VERSION 5.7 ;
BUSBITCHARS "[]" ;
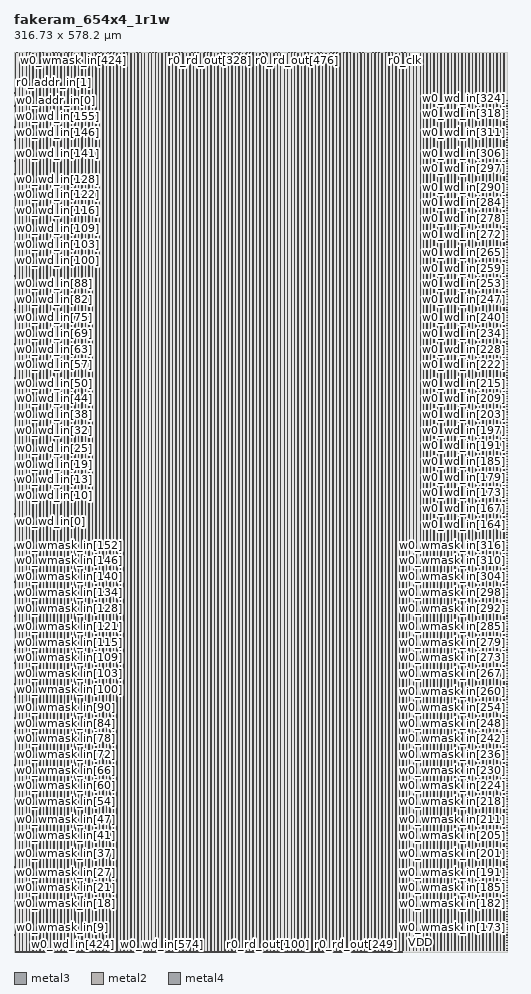
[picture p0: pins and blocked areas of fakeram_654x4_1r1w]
MACRO fakeram_654x4_1r1w
  FOREIGN fakeram_654x4_1r1w 0 0 ;
  SYMMETRY X Y R90 ;
  SIZE 316.730 BY 578.200 ;
  CLASS BLOCK ;
  PIN w0_wmask_in[0]
    DIRECTION INPUT ;
    USE SIGNAL ;
    SHAPE ABUTMENT ;
    PORT
      LAYER metal3 ;
      RECT 0.000 0.805 0.210 0.875 ;
    END
  END w0_wmask_in[0]
  PIN w0_wmask_in[1]
    DIRECTION INPUT ;
    USE SIGNAL ;
    SHAPE ABUTMENT ;
    PORT
      LAYER metal3 ;
      RECT 0.000 2.485 0.210 2.555 ;
    END
  END w0_wmask_in[1]
  PIN w0_wmask_in[2]
    DIRECTION INPUT ;
    USE SIGNAL ;
    SHAPE ABUTMENT ;
    PORT
      LAYER metal3 ;
      RECT 0.000 4.165 0.210 4.235 ;
    END
  END w0_wmask_in[2]
  PIN w0_wmask_in[3]
    DIRECTION INPUT ;
    USE SIGNAL ;
    SHAPE ABUTMENT ;
    PORT
      LAYER metal3 ;
      RECT 0.000 5.845 0.210 5.915 ;
    END
  END w0_wmask_in[3]
  PIN w0_wmask_in[4]
    DIRECTION INPUT ;
    USE SIGNAL ;
    SHAPE ABUTMENT ;
    PORT
      LAYER metal3 ;
      RECT 0.000 7.525 0.210 7.595 ;
    END
  END w0_wmask_in[4]
  PIN w0_wmask_in[5]
    DIRECTION INPUT ;
    USE SIGNAL ;
    SHAPE ABUTMENT ;
    PORT
      LAYER metal3 ;
      RECT 0.000 9.205 0.210 9.275 ;
    END
  END w0_wmask_in[5]
  PIN w0_wmask_in[6]
    DIRECTION INPUT ;
    USE SIGNAL ;
    SHAPE ABUTMENT ;
    PORT
      LAYER metal3 ;
      RECT 0.000 10.885 0.210 10.955 ;
    END
  END w0_wmask_in[6]
  PIN w0_wmask_in[7]
    DIRECTION INPUT ;
    USE SIGNAL ;
    SHAPE ABUTMENT ;
    PORT
      LAYER metal3 ;
      RECT 0.000 12.565 0.210 12.635 ;
    END
  END w0_wmask_in[7]
  PIN w0_wmask_in[8]
    DIRECTION INPUT ;
    USE SIGNAL ;
    SHAPE ABUTMENT ;
    PORT
      LAYER metal3 ;
      RECT 0.000 14.245 0.210 14.315 ;
    END
  END w0_wmask_in[8]
  PIN w0_wmask_in[9]
    DIRECTION INPUT ;
    USE SIGNAL ;
    SHAPE ABUTMENT ;
    PORT
      LAYER metal3 ;
      RECT 0.000 15.925 0.210 15.995 ;
    END
  END w0_wmask_in[9]
  PIN w0_wmask_in[10]
    DIRECTION INPUT ;
    USE SIGNAL ;
    SHAPE ABUTMENT ;
    PORT
      LAYER metal3 ;
      RECT 0.000 17.605 0.210 17.675 ;
    END
  END w0_wmask_in[10]
  PIN w0_wmask_in[11]
    DIRECTION INPUT ;
    USE SIGNAL ;
    SHAPE ABUTMENT ;
    PORT
      LAYER metal3 ;
      RECT 0.000 19.285 0.210 19.355 ;
    END
  END w0_wmask_in[11]
  PIN w0_wmask_in[12]
    DIRECTION INPUT ;
    USE SIGNAL ;
    SHAPE ABUTMENT ;
    PORT
      LAYER metal3 ;
      RECT 0.000 20.965 0.210 21.035 ;
    END
  END w0_wmask_in[12]
  PIN w0_wmask_in[13]
    DIRECTION INPUT ;
    USE SIGNAL ;
    SHAPE ABUTMENT ;
    PORT
      LAYER metal3 ;
      RECT 0.000 22.645 0.210 22.715 ;
    END
  END w0_wmask_in[13]
  PIN w0_wmask_in[14]
    DIRECTION INPUT ;
    USE SIGNAL ;
    SHAPE ABUTMENT ;
    PORT
      LAYER metal3 ;
      RECT 0.000 24.325 0.210 24.395 ;
    END
  END w0_wmask_in[14]
  PIN w0_wmask_in[15]
    DIRECTION INPUT ;
    USE SIGNAL ;
    SHAPE ABUTMENT ;
    PORT
      LAYER metal3 ;
      RECT 0.000 26.005 0.210 26.075 ;
    END
  END w0_wmask_in[15]
  PIN w0_wmask_in[16]
    DIRECTION INPUT ;
    USE SIGNAL ;
    SHAPE ABUTMENT ;
    PORT
      LAYER metal3 ;
      RECT 0.000 27.685 0.210 27.755 ;
    END
  END w0_wmask_in[16]
  PIN w0_wmask_in[17]
    DIRECTION INPUT ;
    USE SIGNAL ;
    SHAPE ABUTMENT ;
    PORT
      LAYER metal3 ;
      RECT 0.000 29.365 0.210 29.435 ;
    END
  END w0_wmask_in[17]
  PIN w0_wmask_in[18]
    DIRECTION INPUT ;
    USE SIGNAL ;
    SHAPE ABUTMENT ;
    PORT
      LAYER metal3 ;
      RECT 0.000 31.045 0.210 31.115 ;
    END
  END w0_wmask_in[18]
  PIN w0_wmask_in[19]
    DIRECTION INPUT ;
    USE SIGNAL ;
    SHAPE ABUTMENT ;
    PORT
      LAYER metal3 ;
      RECT 0.000 32.725 0.210 32.795 ;
    END
  END w0_wmask_in[19]
  PIN w0_wmask_in[20]
    DIRECTION INPUT ;
    USE SIGNAL ;
    SHAPE ABUTMENT ;
    PORT
      LAYER metal3 ;
      RECT 0.000 34.405 0.210 34.475 ;
    END
  END w0_wmask_in[20]
  PIN w0_wmask_in[21]
    DIRECTION INPUT ;
    USE SIGNAL ;
    SHAPE ABUTMENT ;
    PORT
      LAYER metal3 ;
      RECT 0.000 36.085 0.210 36.155 ;
    END
  END w0_wmask_in[21]
  PIN w0_wmask_in[22]
    DIRECTION INPUT ;
    USE SIGNAL ;
    SHAPE ABUTMENT ;
    PORT
      LAYER metal3 ;
      RECT 0.000 37.765 0.210 37.835 ;
    END
  END w0_wmask_in[22]
  PIN w0_wmask_in[23]
    DIRECTION INPUT ;
    USE SIGNAL ;
    SHAPE ABUTMENT ;
    PORT
      LAYER metal3 ;
      RECT 0.000 39.445 0.210 39.515 ;
    END
  END w0_wmask_in[23]
  PIN w0_wmask_in[24]
    DIRECTION INPUT ;
    USE SIGNAL ;
    SHAPE ABUTMENT ;
    PORT
      LAYER metal3 ;
      RECT 0.000 41.125 0.210 41.195 ;
    END
  END w0_wmask_in[24]
  PIN w0_wmask_in[25]
    DIRECTION INPUT ;
    USE SIGNAL ;
    SHAPE ABUTMENT ;
    PORT
      LAYER metal3 ;
      RECT 0.000 42.805 0.210 42.875 ;
    END
  END w0_wmask_in[25]
  PIN w0_wmask_in[26]
    DIRECTION INPUT ;
    USE SIGNAL ;
    SHAPE ABUTMENT ;
    PORT
      LAYER metal3 ;
      RECT 0.000 44.485 0.210 44.555 ;
    END
  END w0_wmask_in[26]
  PIN w0_wmask_in[27]
    DIRECTION INPUT ;
    USE SIGNAL ;
    SHAPE ABUTMENT ;
    PORT
      LAYER metal3 ;
      RECT 0.000 46.165 0.210 46.235 ;
    END
  END w0_wmask_in[27]
  PIN w0_wmask_in[28]
    DIRECTION INPUT ;
    USE SIGNAL ;
    SHAPE ABUTMENT ;
    PORT
      LAYER metal3 ;
      RECT 0.000 47.845 0.210 47.915 ;
    END
  END w0_wmask_in[28]
  PIN w0_wmask_in[29]
    DIRECTION INPUT ;
    USE SIGNAL ;
    SHAPE ABUTMENT ;
    PORT
      LAYER metal3 ;
      RECT 0.000 49.525 0.210 49.595 ;
    END
  END w0_wmask_in[29]
  PIN w0_wmask_in[30]
    DIRECTION INPUT ;
    USE SIGNAL ;
    SHAPE ABUTMENT ;
    PORT
      LAYER metal3 ;
      RECT 0.000 51.205 0.210 51.275 ;
    END
  END w0_wmask_in[30]
  PIN w0_wmask_in[31]
    DIRECTION INPUT ;
    USE SIGNAL ;
    SHAPE ABUTMENT ;
    PORT
      LAYER metal3 ;
      RECT 0.000 52.885 0.210 52.955 ;
    END
  END w0_wmask_in[31]
  PIN w0_wmask_in[32]
    DIRECTION INPUT ;
    USE SIGNAL ;
    SHAPE ABUTMENT ;
    PORT
      LAYER metal3 ;
      RECT 0.000 54.565 0.210 54.635 ;
    END
  END w0_wmask_in[32]
  PIN w0_wmask_in[33]
    DIRECTION INPUT ;
    USE SIGNAL ;
    SHAPE ABUTMENT ;
    PORT
      LAYER metal3 ;
      RECT 0.000 56.245 0.210 56.315 ;
    END
  END w0_wmask_in[33]
  PIN w0_wmask_in[34]
    DIRECTION INPUT ;
    USE SIGNAL ;
    SHAPE ABUTMENT ;
    PORT
      LAYER metal3 ;
      RECT 0.000 57.925 0.210 57.995 ;
    END
  END w0_wmask_in[34]
  PIN w0_wmask_in[35]
    DIRECTION INPUT ;
    USE SIGNAL ;
    SHAPE ABUTMENT ;
    PORT
      LAYER metal3 ;
      RECT 0.000 59.605 0.210 59.675 ;
    END
  END w0_wmask_in[35]
  PIN w0_wmask_in[36]
    DIRECTION INPUT ;
    USE SIGNAL ;
    SHAPE ABUTMENT ;
    PORT
      LAYER metal3 ;
      RECT 0.000 61.285 0.210 61.355 ;
    END
  END w0_wmask_in[36]
  PIN w0_wmask_in[37]
    DIRECTION INPUT ;
    USE SIGNAL ;
    SHAPE ABUTMENT ;
    PORT
      LAYER metal3 ;
      RECT 0.000 62.965 0.210 63.035 ;
    END
  END w0_wmask_in[37]
  PIN w0_wmask_in[38]
    DIRECTION INPUT ;
    USE SIGNAL ;
    SHAPE ABUTMENT ;
    PORT
      LAYER metal3 ;
      RECT 0.000 64.645 0.210 64.715 ;
    END
  END w0_wmask_in[38]
  PIN w0_wmask_in[39]
    DIRECTION INPUT ;
    USE SIGNAL ;
    SHAPE ABUTMENT ;
    PORT
      LAYER metal3 ;
      RECT 0.000 66.325 0.210 66.395 ;
    END
  END w0_wmask_in[39]
  PIN w0_wmask_in[40]
    DIRECTION INPUT ;
    USE SIGNAL ;
    SHAPE ABUTMENT ;
    PORT
      LAYER metal3 ;
      RECT 0.000 68.005 0.210 68.075 ;
    END
  END w0_wmask_in[40]
  PIN w0_wmask_in[41]
    DIRECTION INPUT ;
    USE SIGNAL ;
    SHAPE ABUTMENT ;
    PORT
      LAYER metal3 ;
      RECT 0.000 69.685 0.210 69.755 ;
    END
  END w0_wmask_in[41]
  PIN w0_wmask_in[42]
    DIRECTION INPUT ;
    USE SIGNAL ;
    SHAPE ABUTMENT ;
    PORT
      LAYER metal3 ;
      RECT 0.000 71.365 0.210 71.435 ;
    END
  END w0_wmask_in[42]
  PIN w0_wmask_in[43]
    DIRECTION INPUT ;
    USE SIGNAL ;
    SHAPE ABUTMENT ;
    PORT
      LAYER metal3 ;
      RECT 0.000 73.045 0.210 73.115 ;
    END
  END w0_wmask_in[43]
  PIN w0_wmask_in[44]
    DIRECTION INPUT ;
    USE SIGNAL ;
    SHAPE ABUTMENT ;
    PORT
      LAYER metal3 ;
      RECT 0.000 74.725 0.210 74.795 ;
    END
  END w0_wmask_in[44]
  PIN w0_wmask_in[45]
    DIRECTION INPUT ;
    USE SIGNAL ;
    SHAPE ABUTMENT ;
    PORT
      LAYER metal3 ;
      RECT 0.000 76.405 0.210 76.475 ;
    END
  END w0_wmask_in[45]
  PIN w0_wmask_in[46]
    DIRECTION INPUT ;
    USE SIGNAL ;
    SHAPE ABUTMENT ;
    PORT
      LAYER metal3 ;
      RECT 0.000 78.085 0.210 78.155 ;
    END
  END w0_wmask_in[46]
  PIN w0_wmask_in[47]
    DIRECTION INPUT ;
    USE SIGNAL ;
    SHAPE ABUTMENT ;
    PORT
      LAYER metal3 ;
      RECT 0.000 79.765 0.210 79.835 ;
    END
  END w0_wmask_in[47]
  PIN w0_wmask_in[48]
    DIRECTION INPUT ;
    USE SIGNAL ;
    SHAPE ABUTMENT ;
    PORT
      LAYER metal3 ;
      RECT 0.000 81.445 0.210 81.515 ;
    END
  END w0_wmask_in[48]
  PIN w0_wmask_in[49]
    DIRECTION INPUT ;
    USE SIGNAL ;
    SHAPE ABUTMENT ;
    PORT
      LAYER metal3 ;
      RECT 0.000 83.125 0.210 83.195 ;
    END
  END w0_wmask_in[49]
  PIN w0_wmask_in[50]
    DIRECTION INPUT ;
    USE SIGNAL ;
    SHAPE ABUTMENT ;
    PORT
      LAYER metal3 ;
      RECT 0.000 84.805 0.210 84.875 ;
    END
  END w0_wmask_in[50]
  PIN w0_wmask_in[51]
    DIRECTION INPUT ;
    USE SIGNAL ;
    SHAPE ABUTMENT ;
    PORT
      LAYER metal3 ;
      RECT 0.000 86.485 0.210 86.555 ;
    END
  END w0_wmask_in[51]
  PIN w0_wmask_in[52]
    DIRECTION INPUT ;
    USE SIGNAL ;
    SHAPE ABUTMENT ;
    PORT
      LAYER metal3 ;
      RECT 0.000 88.165 0.210 88.235 ;
    END
  END w0_wmask_in[52]
  PIN w0_wmask_in[53]
    DIRECTION INPUT ;
    USE SIGNAL ;
    SHAPE ABUTMENT ;
    PORT
      LAYER metal3 ;
      RECT 0.000 89.845 0.210 89.915 ;
    END
  END w0_wmask_in[53]
  PIN w0_wmask_in[54]
    DIRECTION INPUT ;
    USE SIGNAL ;
    SHAPE ABUTMENT ;
    PORT
      LAYER metal3 ;
      RECT 0.000 91.525 0.210 91.595 ;
    END
  END w0_wmask_in[54]
  PIN w0_wmask_in[55]
    DIRECTION INPUT ;
    USE SIGNAL ;
    SHAPE ABUTMENT ;
    PORT
      LAYER metal3 ;
      RECT 0.000 93.205 0.210 93.275 ;
    END
  END w0_wmask_in[55]
  PIN w0_wmask_in[56]
    DIRECTION INPUT ;
    USE SIGNAL ;
    SHAPE ABUTMENT ;
    PORT
      LAYER metal3 ;
      RECT 0.000 94.885 0.210 94.955 ;
    END
  END w0_wmask_in[56]
  PIN w0_wmask_in[57]
    DIRECTION INPUT ;
    USE SIGNAL ;
    SHAPE ABUTMENT ;
    PORT
      LAYER metal3 ;
      RECT 0.000 96.565 0.210 96.635 ;
    END
  END w0_wmask_in[57]
  PIN w0_wmask_in[58]
    DIRECTION INPUT ;
    USE SIGNAL ;
    SHAPE ABUTMENT ;
    PORT
      LAYER metal3 ;
      RECT 0.000 98.245 0.210 98.315 ;
    END
  END w0_wmask_in[58]
  PIN w0_wmask_in[59]
    DIRECTION INPUT ;
    USE SIGNAL ;
    SHAPE ABUTMENT ;
    PORT
      LAYER metal3 ;
      RECT 0.000 99.925 0.210 99.995 ;
    END
  END w0_wmask_in[59]
  PIN w0_wmask_in[60]
    DIRECTION INPUT ;
    USE SIGNAL ;
    SHAPE ABUTMENT ;
    PORT
      LAYER metal3 ;
      RECT 0.000 101.605 0.210 101.675 ;
    END
  END w0_wmask_in[60]
  PIN w0_wmask_in[61]
    DIRECTION INPUT ;
    USE SIGNAL ;
    SHAPE ABUTMENT ;
    PORT
      LAYER metal3 ;
      RECT 0.000 103.285 0.210 103.355 ;
    END
  END w0_wmask_in[61]
  PIN w0_wmask_in[62]
    DIRECTION INPUT ;
    USE SIGNAL ;
    SHAPE ABUTMENT ;
    PORT
      LAYER metal3 ;
      RECT 0.000 104.965 0.210 105.035 ;
    END
  END w0_wmask_in[62]
  PIN w0_wmask_in[63]
    DIRECTION INPUT ;
    USE SIGNAL ;
    SHAPE ABUTMENT ;
    PORT
      LAYER metal3 ;
      RECT 0.000 106.645 0.210 106.715 ;
    END
  END w0_wmask_in[63]
  PIN w0_wmask_in[64]
    DIRECTION INPUT ;
    USE SIGNAL ;
    SHAPE ABUTMENT ;
    PORT
      LAYER metal3 ;
      RECT 0.000 108.325 0.210 108.395 ;
    END
  END w0_wmask_in[64]
  PIN w0_wmask_in[65]
    DIRECTION INPUT ;
    USE SIGNAL ;
    SHAPE ABUTMENT ;
    PORT
      LAYER metal3 ;
      RECT 0.000 110.005 0.210 110.075 ;
    END
  END w0_wmask_in[65]
  PIN w0_wmask_in[66]
    DIRECTION INPUT ;
    USE SIGNAL ;
    SHAPE ABUTMENT ;
    PORT
      LAYER metal3 ;
      RECT 0.000 111.685 0.210 111.755 ;
    END
  END w0_wmask_in[66]
  PIN w0_wmask_in[67]
    DIRECTION INPUT ;
    USE SIGNAL ;
    SHAPE ABUTMENT ;
    PORT
      LAYER metal3 ;
      RECT 0.000 113.365 0.210 113.435 ;
    END
  END w0_wmask_in[67]
  PIN w0_wmask_in[68]
    DIRECTION INPUT ;
    USE SIGNAL ;
    SHAPE ABUTMENT ;
    PORT
      LAYER metal3 ;
      RECT 0.000 115.045 0.210 115.115 ;
    END
  END w0_wmask_in[68]
  PIN w0_wmask_in[69]
    DIRECTION INPUT ;
    USE SIGNAL ;
    SHAPE ABUTMENT ;
    PORT
      LAYER metal3 ;
      RECT 0.000 116.725 0.210 116.795 ;
    END
  END w0_wmask_in[69]
  PIN w0_wmask_in[70]
    DIRECTION INPUT ;
    USE SIGNAL ;
    SHAPE ABUTMENT ;
    PORT
      LAYER metal3 ;
      RECT 0.000 118.405 0.210 118.475 ;
    END
  END w0_wmask_in[70]
  PIN w0_wmask_in[71]
    DIRECTION INPUT ;
    USE SIGNAL ;
    SHAPE ABUTMENT ;
    PORT
      LAYER metal3 ;
      RECT 0.000 120.085 0.210 120.155 ;
    END
  END w0_wmask_in[71]
  PIN w0_wmask_in[72]
    DIRECTION INPUT ;
    USE SIGNAL ;
    SHAPE ABUTMENT ;
    PORT
      LAYER metal3 ;
      RECT 0.000 121.765 0.210 121.835 ;
    END
  END w0_wmask_in[72]
  PIN w0_wmask_in[73]
    DIRECTION INPUT ;
    USE SIGNAL ;
    SHAPE ABUTMENT ;
    PORT
      LAYER metal3 ;
      RECT 0.000 123.445 0.210 123.515 ;
    END
  END w0_wmask_in[73]
  PIN w0_wmask_in[74]
    DIRECTION INPUT ;
    USE SIGNAL ;
    SHAPE ABUTMENT ;
    PORT
      LAYER metal3 ;
      RECT 0.000 125.125 0.210 125.195 ;
    END
  END w0_wmask_in[74]
  PIN w0_wmask_in[75]
    DIRECTION INPUT ;
    USE SIGNAL ;
    SHAPE ABUTMENT ;
    PORT
      LAYER metal3 ;
      RECT 0.000 126.805 0.210 126.875 ;
    END
  END w0_wmask_in[75]
  PIN w0_wmask_in[76]
    DIRECTION INPUT ;
    USE SIGNAL ;
    SHAPE ABUTMENT ;
    PORT
      LAYER metal3 ;
      RECT 0.000 128.485 0.210 128.555 ;
    END
  END w0_wmask_in[76]
  PIN w0_wmask_in[77]
    DIRECTION INPUT ;
    USE SIGNAL ;
    SHAPE ABUTMENT ;
    PORT
      LAYER metal3 ;
      RECT 0.000 130.165 0.210 130.235 ;
    END
  END w0_wmask_in[77]
  PIN w0_wmask_in[78]
    DIRECTION INPUT ;
    USE SIGNAL ;
    SHAPE ABUTMENT ;
    PORT
      LAYER metal3 ;
      RECT 0.000 131.845 0.210 131.915 ;
    END
  END w0_wmask_in[78]
  PIN w0_wmask_in[79]
    DIRECTION INPUT ;
    USE SIGNAL ;
    SHAPE ABUTMENT ;
    PORT
      LAYER metal3 ;
      RECT 0.000 133.525 0.210 133.595 ;
    END
  END w0_wmask_in[79]
  PIN w0_wmask_in[80]
    DIRECTION INPUT ;
    USE SIGNAL ;
    SHAPE ABUTMENT ;
    PORT
      LAYER metal3 ;
      RECT 0.000 135.205 0.210 135.275 ;
    END
  END w0_wmask_in[80]
  PIN w0_wmask_in[81]
    DIRECTION INPUT ;
    USE SIGNAL ;
    SHAPE ABUTMENT ;
    PORT
      LAYER metal3 ;
      RECT 0.000 136.885 0.210 136.955 ;
    END
  END w0_wmask_in[81]
  PIN w0_wmask_in[82]
    DIRECTION INPUT ;
    USE SIGNAL ;
    SHAPE ABUTMENT ;
    PORT
      LAYER metal3 ;
      RECT 0.000 138.565 0.210 138.635 ;
    END
  END w0_wmask_in[82]
  PIN w0_wmask_in[83]
    DIRECTION INPUT ;
    USE SIGNAL ;
    SHAPE ABUTMENT ;
    PORT
      LAYER metal3 ;
      RECT 0.000 140.245 0.210 140.315 ;
    END
  END w0_wmask_in[83]
  PIN w0_wmask_in[84]
    DIRECTION INPUT ;
    USE SIGNAL ;
    SHAPE ABUTMENT ;
    PORT
      LAYER metal3 ;
      RECT 0.000 141.925 0.210 141.995 ;
    END
  END w0_wmask_in[84]
  PIN w0_wmask_in[85]
    DIRECTION INPUT ;
    USE SIGNAL ;
    SHAPE ABUTMENT ;
    PORT
      LAYER metal3 ;
      RECT 0.000 143.605 0.210 143.675 ;
    END
  END w0_wmask_in[85]
  PIN w0_wmask_in[86]
    DIRECTION INPUT ;
    USE SIGNAL ;
    SHAPE ABUTMENT ;
    PORT
      LAYER metal3 ;
      RECT 0.000 145.285 0.210 145.355 ;
    END
  END w0_wmask_in[86]
  PIN w0_wmask_in[87]
    DIRECTION INPUT ;
    USE SIGNAL ;
    SHAPE ABUTMENT ;
    PORT
      LAYER metal3 ;
      RECT 0.000 146.965 0.210 147.035 ;
    END
  END w0_wmask_in[87]
  PIN w0_wmask_in[88]
    DIRECTION INPUT ;
    USE SIGNAL ;
    SHAPE ABUTMENT ;
    PORT
      LAYER metal3 ;
      RECT 0.000 148.645 0.210 148.715 ;
    END
  END w0_wmask_in[88]
  PIN w0_wmask_in[89]
    DIRECTION INPUT ;
    USE SIGNAL ;
    SHAPE ABUTMENT ;
    PORT
      LAYER metal3 ;
      RECT 0.000 150.325 0.210 150.395 ;
    END
  END w0_wmask_in[89]
  PIN w0_wmask_in[90]
    DIRECTION INPUT ;
    USE SIGNAL ;
    SHAPE ABUTMENT ;
    PORT
      LAYER metal3 ;
      RECT 0.000 152.005 0.210 152.075 ;
    END
  END w0_wmask_in[90]
  PIN w0_wmask_in[91]
    DIRECTION INPUT ;
    USE SIGNAL ;
    SHAPE ABUTMENT ;
    PORT
      LAYER metal3 ;
      RECT 0.000 153.685 0.210 153.755 ;
    END
  END w0_wmask_in[91]
  PIN w0_wmask_in[92]
    DIRECTION INPUT ;
    USE SIGNAL ;
    SHAPE ABUTMENT ;
    PORT
      LAYER metal3 ;
      RECT 0.000 155.365 0.210 155.435 ;
    END
  END w0_wmask_in[92]
  PIN w0_wmask_in[93]
    DIRECTION INPUT ;
    USE SIGNAL ;
    SHAPE ABUTMENT ;
    PORT
      LAYER metal3 ;
      RECT 0.000 157.045 0.210 157.115 ;
    END
  END w0_wmask_in[93]
  PIN w0_wmask_in[94]
    DIRECTION INPUT ;
    USE SIGNAL ;
    SHAPE ABUTMENT ;
    PORT
      LAYER metal3 ;
      RECT 0.000 158.725 0.210 158.795 ;
    END
  END w0_wmask_in[94]
  PIN w0_wmask_in[95]
    DIRECTION INPUT ;
    USE SIGNAL ;
    SHAPE ABUTMENT ;
    PORT
      LAYER metal3 ;
      RECT 0.000 160.405 0.210 160.475 ;
    END
  END w0_wmask_in[95]
  PIN w0_wmask_in[96]
    DIRECTION INPUT ;
    USE SIGNAL ;
    SHAPE ABUTMENT ;
    PORT
      LAYER metal3 ;
      RECT 0.000 162.085 0.210 162.155 ;
    END
  END w0_wmask_in[96]
  PIN w0_wmask_in[97]
    DIRECTION INPUT ;
    USE SIGNAL ;
    SHAPE ABUTMENT ;
    PORT
      LAYER metal3 ;
      RECT 0.000 163.765 0.210 163.835 ;
    END
  END w0_wmask_in[97]
  PIN w0_wmask_in[98]
    DIRECTION INPUT ;
    USE SIGNAL ;
    SHAPE ABUTMENT ;
    PORT
      LAYER metal3 ;
      RECT 0.000 165.445 0.210 165.515 ;
    END
  END w0_wmask_in[98]
  PIN w0_wmask_in[99]
    DIRECTION INPUT ;
    USE SIGNAL ;
    SHAPE ABUTMENT ;
    PORT
      LAYER metal3 ;
      RECT 0.000 167.125 0.210 167.195 ;
    END
  END w0_wmask_in[99]
  PIN w0_wmask_in[100]
    DIRECTION INPUT ;
    USE SIGNAL ;
    SHAPE ABUTMENT ;
    PORT
      LAYER metal3 ;
      RECT 0.000 168.805 0.210 168.875 ;
    END
  END w0_wmask_in[100]
  PIN w0_wmask_in[101]
    DIRECTION INPUT ;
    USE SIGNAL ;
    SHAPE ABUTMENT ;
    PORT
      LAYER metal3 ;
      RECT 0.000 170.485 0.210 170.555 ;
    END
  END w0_wmask_in[101]
  PIN w0_wmask_in[102]
    DIRECTION INPUT ;
    USE SIGNAL ;
    SHAPE ABUTMENT ;
    PORT
      LAYER metal3 ;
      RECT 0.000 172.165 0.210 172.235 ;
    END
  END w0_wmask_in[102]
  PIN w0_wmask_in[103]
    DIRECTION INPUT ;
    USE SIGNAL ;
    SHAPE ABUTMENT ;
    PORT
      LAYER metal3 ;
      RECT 0.000 173.845 0.210 173.915 ;
    END
  END w0_wmask_in[103]
  PIN w0_wmask_in[104]
    DIRECTION INPUT ;
    USE SIGNAL ;
    SHAPE ABUTMENT ;
    PORT
      LAYER metal3 ;
      RECT 0.000 175.525 0.210 175.595 ;
    END
  END w0_wmask_in[104]
  PIN w0_wmask_in[105]
    DIRECTION INPUT ;
    USE SIGNAL ;
    SHAPE ABUTMENT ;
    PORT
      LAYER metal3 ;
      RECT 0.000 177.205 0.210 177.275 ;
    END
  END w0_wmask_in[105]
  PIN w0_wmask_in[106]
    DIRECTION INPUT ;
    USE SIGNAL ;
    SHAPE ABUTMENT ;
    PORT
      LAYER metal3 ;
      RECT 0.000 178.885 0.210 178.955 ;
    END
  END w0_wmask_in[106]
  PIN w0_wmask_in[107]
    DIRECTION INPUT ;
    USE SIGNAL ;
    SHAPE ABUTMENT ;
    PORT
      LAYER metal3 ;
      RECT 0.000 180.565 0.210 180.635 ;
    END
  END w0_wmask_in[107]
  PIN w0_wmask_in[108]
    DIRECTION INPUT ;
    USE SIGNAL ;
    SHAPE ABUTMENT ;
    PORT
      LAYER metal3 ;
      RECT 0.000 182.245 0.210 182.315 ;
    END
  END w0_wmask_in[108]
  PIN w0_wmask_in[109]
    DIRECTION INPUT ;
    USE SIGNAL ;
    SHAPE ABUTMENT ;
    PORT
      LAYER metal3 ;
      RECT 0.000 183.925 0.210 183.995 ;
    END
  END w0_wmask_in[109]
  PIN w0_wmask_in[110]
    DIRECTION INPUT ;
    USE SIGNAL ;
    SHAPE ABUTMENT ;
    PORT
      LAYER metal3 ;
      RECT 0.000 185.605 0.210 185.675 ;
    END
  END w0_wmask_in[110]
  PIN w0_wmask_in[111]
    DIRECTION INPUT ;
    USE SIGNAL ;
    SHAPE ABUTMENT ;
    PORT
      LAYER metal3 ;
      RECT 0.000 187.285 0.210 187.355 ;
    END
  END w0_wmask_in[111]
  PIN w0_wmask_in[112]
    DIRECTION INPUT ;
    USE SIGNAL ;
    SHAPE ABUTMENT ;
    PORT
      LAYER metal3 ;
      RECT 0.000 188.965 0.210 189.035 ;
    END
  END w0_wmask_in[112]
  PIN w0_wmask_in[113]
    DIRECTION INPUT ;
    USE SIGNAL ;
    SHAPE ABUTMENT ;
    PORT
      LAYER metal3 ;
      RECT 0.000 190.645 0.210 190.715 ;
    END
  END w0_wmask_in[113]
  PIN w0_wmask_in[114]
    DIRECTION INPUT ;
    USE SIGNAL ;
    SHAPE ABUTMENT ;
    PORT
      LAYER metal3 ;
      RECT 0.000 192.325 0.210 192.395 ;
    END
  END w0_wmask_in[114]
  PIN w0_wmask_in[115]
    DIRECTION INPUT ;
    USE SIGNAL ;
    SHAPE ABUTMENT ;
    PORT
      LAYER metal3 ;
      RECT 0.000 194.005 0.210 194.075 ;
    END
  END w0_wmask_in[115]
  PIN w0_wmask_in[116]
    DIRECTION INPUT ;
    USE SIGNAL ;
    SHAPE ABUTMENT ;
    PORT
      LAYER metal3 ;
      RECT 0.000 195.685 0.210 195.755 ;
    END
  END w0_wmask_in[116]
  PIN w0_wmask_in[117]
    DIRECTION INPUT ;
    USE SIGNAL ;
    SHAPE ABUTMENT ;
    PORT
      LAYER metal3 ;
      RECT 0.000 197.365 0.210 197.435 ;
    END
  END w0_wmask_in[117]
  PIN w0_wmask_in[118]
    DIRECTION INPUT ;
    USE SIGNAL ;
    SHAPE ABUTMENT ;
    PORT
      LAYER metal3 ;
      RECT 0.000 199.045 0.210 199.115 ;
    END
  END w0_wmask_in[118]
  PIN w0_wmask_in[119]
    DIRECTION INPUT ;
    USE SIGNAL ;
    SHAPE ABUTMENT ;
    PORT
      LAYER metal3 ;
      RECT 0.000 200.725 0.210 200.795 ;
    END
  END w0_wmask_in[119]
  PIN w0_wmask_in[120]
    DIRECTION INPUT ;
    USE SIGNAL ;
    SHAPE ABUTMENT ;
    PORT
      LAYER metal3 ;
      RECT 0.000 202.405 0.210 202.475 ;
    END
  END w0_wmask_in[120]
  PIN w0_wmask_in[121]
    DIRECTION INPUT ;
    USE SIGNAL ;
    SHAPE ABUTMENT ;
    PORT
      LAYER metal3 ;
      RECT 0.000 204.085 0.210 204.155 ;
    END
  END w0_wmask_in[121]
  PIN w0_wmask_in[122]
    DIRECTION INPUT ;
    USE SIGNAL ;
    SHAPE ABUTMENT ;
    PORT
      LAYER metal3 ;
      RECT 0.000 205.765 0.210 205.835 ;
    END
  END w0_wmask_in[122]
  PIN w0_wmask_in[123]
    DIRECTION INPUT ;
    USE SIGNAL ;
    SHAPE ABUTMENT ;
    PORT
      LAYER metal3 ;
      RECT 0.000 207.445 0.210 207.515 ;
    END
  END w0_wmask_in[123]
  PIN w0_wmask_in[124]
    DIRECTION INPUT ;
    USE SIGNAL ;
    SHAPE ABUTMENT ;
    PORT
      LAYER metal3 ;
      RECT 0.000 209.125 0.210 209.195 ;
    END
  END w0_wmask_in[124]
  PIN w0_wmask_in[125]
    DIRECTION INPUT ;
    USE SIGNAL ;
    SHAPE ABUTMENT ;
    PORT
      LAYER metal3 ;
      RECT 0.000 210.805 0.210 210.875 ;
    END
  END w0_wmask_in[125]
  PIN w0_wmask_in[126]
    DIRECTION INPUT ;
    USE SIGNAL ;
    SHAPE ABUTMENT ;
    PORT
      LAYER metal3 ;
      RECT 0.000 212.485 0.210 212.555 ;
    END
  END w0_wmask_in[126]
  PIN w0_wmask_in[127]
    DIRECTION INPUT ;
    USE SIGNAL ;
    SHAPE ABUTMENT ;
    PORT
      LAYER metal3 ;
      RECT 0.000 214.165 0.210 214.235 ;
    END
  END w0_wmask_in[127]
  PIN w0_wmask_in[128]
    DIRECTION INPUT ;
    USE SIGNAL ;
    SHAPE ABUTMENT ;
    PORT
      LAYER metal3 ;
      RECT 0.000 215.845 0.210 215.915 ;
    END
  END w0_wmask_in[128]
  PIN w0_wmask_in[129]
    DIRECTION INPUT ;
    USE SIGNAL ;
    SHAPE ABUTMENT ;
    PORT
      LAYER metal3 ;
      RECT 0.000 217.525 0.210 217.595 ;
    END
  END w0_wmask_in[129]
  PIN w0_wmask_in[130]
    DIRECTION INPUT ;
    USE SIGNAL ;
    SHAPE ABUTMENT ;
    PORT
      LAYER metal3 ;
      RECT 0.000 219.205 0.210 219.275 ;
    END
  END w0_wmask_in[130]
  PIN w0_wmask_in[131]
    DIRECTION INPUT ;
    USE SIGNAL ;
    SHAPE ABUTMENT ;
    PORT
      LAYER metal3 ;
      RECT 0.000 220.885 0.210 220.955 ;
    END
  END w0_wmask_in[131]
  PIN w0_wmask_in[132]
    DIRECTION INPUT ;
    USE SIGNAL ;
    SHAPE ABUTMENT ;
    PORT
      LAYER metal3 ;
      RECT 0.000 222.565 0.210 222.635 ;
    END
  END w0_wmask_in[132]
  PIN w0_wmask_in[133]
    DIRECTION INPUT ;
    USE SIGNAL ;
    SHAPE ABUTMENT ;
    PORT
      LAYER metal3 ;
      RECT 0.000 224.245 0.210 224.315 ;
    END
  END w0_wmask_in[133]
  PIN w0_wmask_in[134]
    DIRECTION INPUT ;
    USE SIGNAL ;
    SHAPE ABUTMENT ;
    PORT
      LAYER metal3 ;
      RECT 0.000 225.925 0.210 225.995 ;
    END
  END w0_wmask_in[134]
  PIN w0_wmask_in[135]
    DIRECTION INPUT ;
    USE SIGNAL ;
    SHAPE ABUTMENT ;
    PORT
      LAYER metal3 ;
      RECT 0.000 227.605 0.210 227.675 ;
    END
  END w0_wmask_in[135]
  PIN w0_wmask_in[136]
    DIRECTION INPUT ;
    USE SIGNAL ;
    SHAPE ABUTMENT ;
    PORT
      LAYER metal3 ;
      RECT 0.000 229.285 0.210 229.355 ;
    END
  END w0_wmask_in[136]
  PIN w0_wmask_in[137]
    DIRECTION INPUT ;
    USE SIGNAL ;
    SHAPE ABUTMENT ;
    PORT
      LAYER metal3 ;
      RECT 0.000 230.965 0.210 231.035 ;
    END
  END w0_wmask_in[137]
  PIN w0_wmask_in[138]
    DIRECTION INPUT ;
    USE SIGNAL ;
    SHAPE ABUTMENT ;
    PORT
      LAYER metal3 ;
      RECT 0.000 232.645 0.210 232.715 ;
    END
  END w0_wmask_in[138]
  PIN w0_wmask_in[139]
    DIRECTION INPUT ;
    USE SIGNAL ;
    SHAPE ABUTMENT ;
    PORT
      LAYER metal3 ;
      RECT 0.000 234.325 0.210 234.395 ;
    END
  END w0_wmask_in[139]
  PIN w0_wmask_in[140]
    DIRECTION INPUT ;
    USE SIGNAL ;
    SHAPE ABUTMENT ;
    PORT
      LAYER metal3 ;
      RECT 0.000 236.005 0.210 236.075 ;
    END
  END w0_wmask_in[140]
  PIN w0_wmask_in[141]
    DIRECTION INPUT ;
    USE SIGNAL ;
    SHAPE ABUTMENT ;
    PORT
      LAYER metal3 ;
      RECT 0.000 237.685 0.210 237.755 ;
    END
  END w0_wmask_in[141]
  PIN w0_wmask_in[142]
    DIRECTION INPUT ;
    USE SIGNAL ;
    SHAPE ABUTMENT ;
    PORT
      LAYER metal3 ;
      RECT 0.000 239.365 0.210 239.435 ;
    END
  END w0_wmask_in[142]
  PIN w0_wmask_in[143]
    DIRECTION INPUT ;
    USE SIGNAL ;
    SHAPE ABUTMENT ;
    PORT
      LAYER metal3 ;
      RECT 0.000 241.045 0.210 241.115 ;
    END
  END w0_wmask_in[143]
  PIN w0_wmask_in[144]
    DIRECTION INPUT ;
    USE SIGNAL ;
    SHAPE ABUTMENT ;
    PORT
      LAYER metal3 ;
      RECT 0.000 242.725 0.210 242.795 ;
    END
  END w0_wmask_in[144]
  PIN w0_wmask_in[145]
    DIRECTION INPUT ;
    USE SIGNAL ;
    SHAPE ABUTMENT ;
    PORT
      LAYER metal3 ;
      RECT 0.000 244.405 0.210 244.475 ;
    END
  END w0_wmask_in[145]
  PIN w0_wmask_in[146]
    DIRECTION INPUT ;
    USE SIGNAL ;
    SHAPE ABUTMENT ;
    PORT
      LAYER metal3 ;
      RECT 0.000 246.085 0.210 246.155 ;
    END
  END w0_wmask_in[146]
  PIN w0_wmask_in[147]
    DIRECTION INPUT ;
    USE SIGNAL ;
    SHAPE ABUTMENT ;
    PORT
      LAYER metal3 ;
      RECT 0.000 247.765 0.210 247.835 ;
    END
  END w0_wmask_in[147]
  PIN w0_wmask_in[148]
    DIRECTION INPUT ;
    USE SIGNAL ;
    SHAPE ABUTMENT ;
    PORT
      LAYER metal3 ;
      RECT 0.000 249.445 0.210 249.515 ;
    END
  END w0_wmask_in[148]
  PIN w0_wmask_in[149]
    DIRECTION INPUT ;
    USE SIGNAL ;
    SHAPE ABUTMENT ;
    PORT
      LAYER metal3 ;
      RECT 0.000 251.125 0.210 251.195 ;
    END
  END w0_wmask_in[149]
  PIN w0_wmask_in[150]
    DIRECTION INPUT ;
    USE SIGNAL ;
    SHAPE ABUTMENT ;
    PORT
      LAYER metal3 ;
      RECT 0.000 252.805 0.210 252.875 ;
    END
  END w0_wmask_in[150]
  PIN w0_wmask_in[151]
    DIRECTION INPUT ;
    USE SIGNAL ;
    SHAPE ABUTMENT ;
    PORT
      LAYER metal3 ;
      RECT 0.000 254.485 0.210 254.555 ;
    END
  END w0_wmask_in[151]
  PIN w0_wmask_in[152]
    DIRECTION INPUT ;
    USE SIGNAL ;
    SHAPE ABUTMENT ;
    PORT
      LAYER metal3 ;
      RECT 0.000 256.165 0.210 256.235 ;
    END
  END w0_wmask_in[152]
  PIN w0_wmask_in[153]
    DIRECTION INPUT ;
    USE SIGNAL ;
    SHAPE ABUTMENT ;
    PORT
      LAYER metal3 ;
      RECT 0.000 257.845 0.210 257.915 ;
    END
  END w0_wmask_in[153]
  PIN w0_wmask_in[154]
    DIRECTION INPUT ;
    USE SIGNAL ;
    SHAPE ABUTMENT ;
    PORT
      LAYER metal3 ;
      RECT 0.000 259.525 0.210 259.595 ;
    END
  END w0_wmask_in[154]
  PIN w0_wmask_in[155]
    DIRECTION INPUT ;
    USE SIGNAL ;
    SHAPE ABUTMENT ;
    PORT
      LAYER metal3 ;
      RECT 0.000 261.205 0.210 261.275 ;
    END
  END w0_wmask_in[155]
  PIN w0_wmask_in[156]
    DIRECTION INPUT ;
    USE SIGNAL ;
    SHAPE ABUTMENT ;
    PORT
      LAYER metal3 ;
      RECT 0.000 262.885 0.210 262.955 ;
    END
  END w0_wmask_in[156]
  PIN w0_wmask_in[157]
    DIRECTION INPUT ;
    USE SIGNAL ;
    SHAPE ABUTMENT ;
    PORT
      LAYER metal3 ;
      RECT 0.000 264.565 0.210 264.635 ;
    END
  END w0_wmask_in[157]
  PIN w0_wmask_in[158]
    DIRECTION INPUT ;
    USE SIGNAL ;
    SHAPE ABUTMENT ;
    PORT
      LAYER metal3 ;
      RECT 0.000 266.245 0.210 266.315 ;
    END
  END w0_wmask_in[158]
  PIN w0_wmask_in[159]
    DIRECTION INPUT ;
    USE SIGNAL ;
    SHAPE ABUTMENT ;
    PORT
      LAYER metal3 ;
      RECT 0.000 267.925 0.210 267.995 ;
    END
  END w0_wmask_in[159]
  PIN w0_wmask_in[160]
    DIRECTION INPUT ;
    USE SIGNAL ;
    SHAPE ABUTMENT ;
    PORT
      LAYER metal3 ;
      RECT 0.000 269.605 0.210 269.675 ;
    END
  END w0_wmask_in[160]
  PIN w0_wmask_in[161]
    DIRECTION INPUT ;
    USE SIGNAL ;
    SHAPE ABUTMENT ;
    PORT
      LAYER metal3 ;
      RECT 0.000 271.285 0.210 271.355 ;
    END
  END w0_wmask_in[161]
  PIN w0_wmask_in[162]
    DIRECTION INPUT ;
    USE SIGNAL ;
    SHAPE ABUTMENT ;
    PORT
      LAYER metal3 ;
      RECT 0.000 272.965 0.210 273.035 ;
    END
  END w0_wmask_in[162]
  PIN w0_wmask_in[163]
    DIRECTION INPUT ;
    USE SIGNAL ;
    SHAPE ABUTMENT ;
    PORT
      LAYER metal3 ;
      RECT 0.000 274.645 0.210 274.715 ;
    END
  END w0_wmask_in[163]
  PIN w0_wmask_in[164]
    DIRECTION INPUT ;
    USE SIGNAL ;
    SHAPE ABUTMENT ;
    PORT
      LAYER metal3 ;
      RECT 316.520 0.805 316.730 0.875 ;
    END
  END w0_wmask_in[164]
  PIN w0_wmask_in[165]
    DIRECTION INPUT ;
    USE SIGNAL ;
    SHAPE ABUTMENT ;
    PORT
      LAYER metal3 ;
      RECT 316.520 2.485 316.730 2.555 ;
    END
  END w0_wmask_in[165]
  PIN w0_wmask_in[166]
    DIRECTION INPUT ;
    USE SIGNAL ;
    SHAPE ABUTMENT ;
    PORT
      LAYER metal3 ;
      RECT 316.520 4.165 316.730 4.235 ;
    END
  END w0_wmask_in[166]
  PIN w0_wmask_in[167]
    DIRECTION INPUT ;
    USE SIGNAL ;
    SHAPE ABUTMENT ;
    PORT
      LAYER metal3 ;
      RECT 316.520 5.845 316.730 5.915 ;
    END
  END w0_wmask_in[167]
  PIN w0_wmask_in[168]
    DIRECTION INPUT ;
    USE SIGNAL ;
    SHAPE ABUTMENT ;
    PORT
      LAYER metal3 ;
      RECT 316.520 7.525 316.730 7.595 ;
    END
  END w0_wmask_in[168]
  PIN w0_wmask_in[169]
    DIRECTION INPUT ;
    USE SIGNAL ;
    SHAPE ABUTMENT ;
    PORT
      LAYER metal3 ;
      RECT 316.520 9.205 316.730 9.275 ;
    END
  END w0_wmask_in[169]
  PIN w0_wmask_in[170]
    DIRECTION INPUT ;
    USE SIGNAL ;
    SHAPE ABUTMENT ;
    PORT
      LAYER metal3 ;
      RECT 316.520 10.885 316.730 10.955 ;
    END
  END w0_wmask_in[170]
  PIN w0_wmask_in[171]
    DIRECTION INPUT ;
    USE SIGNAL ;
    SHAPE ABUTMENT ;
    PORT
      LAYER metal3 ;
      RECT 316.520 12.565 316.730 12.635 ;
    END
  END w0_wmask_in[171]
  PIN w0_wmask_in[172]
    DIRECTION INPUT ;
    USE SIGNAL ;
    SHAPE ABUTMENT ;
    PORT
      LAYER metal3 ;
      RECT 316.520 14.245 316.730 14.315 ;
    END
  END w0_wmask_in[172]
  PIN w0_wmask_in[173]
    DIRECTION INPUT ;
    USE SIGNAL ;
    SHAPE ABUTMENT ;
    PORT
      LAYER metal3 ;
      RECT 316.520 15.925 316.730 15.995 ;
    END
  END w0_wmask_in[173]
  PIN w0_wmask_in[174]
    DIRECTION INPUT ;
    USE SIGNAL ;
    SHAPE ABUTMENT ;
    PORT
      LAYER metal3 ;
      RECT 316.520 17.605 316.730 17.675 ;
    END
  END w0_wmask_in[174]
  PIN w0_wmask_in[175]
    DIRECTION INPUT ;
    USE SIGNAL ;
    SHAPE ABUTMENT ;
    PORT
      LAYER metal3 ;
      RECT 316.520 19.285 316.730 19.355 ;
    END
  END w0_wmask_in[175]
  PIN w0_wmask_in[176]
    DIRECTION INPUT ;
    USE SIGNAL ;
    SHAPE ABUTMENT ;
    PORT
      LAYER metal3 ;
      RECT 316.520 20.965 316.730 21.035 ;
    END
  END w0_wmask_in[176]
  PIN w0_wmask_in[177]
    DIRECTION INPUT ;
    USE SIGNAL ;
    SHAPE ABUTMENT ;
    PORT
      LAYER metal3 ;
      RECT 316.520 22.645 316.730 22.715 ;
    END
  END w0_wmask_in[177]
  PIN w0_wmask_in[178]
    DIRECTION INPUT ;
    USE SIGNAL ;
    SHAPE ABUTMENT ;
    PORT
      LAYER metal3 ;
      RECT 316.520 24.325 316.730 24.395 ;
    END
  END w0_wmask_in[178]
  PIN w0_wmask_in[179]
    DIRECTION INPUT ;
    USE SIGNAL ;
    SHAPE ABUTMENT ;
    PORT
      LAYER metal3 ;
      RECT 316.520 26.005 316.730 26.075 ;
    END
  END w0_wmask_in[179]
  PIN w0_wmask_in[180]
    DIRECTION INPUT ;
    USE SIGNAL ;
    SHAPE ABUTMENT ;
    PORT
      LAYER metal3 ;
      RECT 316.520 27.685 316.730 27.755 ;
    END
  END w0_wmask_in[180]
  PIN w0_wmask_in[181]
    DIRECTION INPUT ;
    USE SIGNAL ;
    SHAPE ABUTMENT ;
    PORT
      LAYER metal3 ;
      RECT 316.520 29.365 316.730 29.435 ;
    END
  END w0_wmask_in[181]
  PIN w0_wmask_in[182]
    DIRECTION INPUT ;
    USE SIGNAL ;
    SHAPE ABUTMENT ;
    PORT
      LAYER metal3 ;
      RECT 316.520 31.045 316.730 31.115 ;
    END
  END w0_wmask_in[182]
  PIN w0_wmask_in[183]
    DIRECTION INPUT ;
    USE SIGNAL ;
    SHAPE ABUTMENT ;
    PORT
      LAYER metal3 ;
      RECT 316.520 32.725 316.730 32.795 ;
    END
  END w0_wmask_in[183]
  PIN w0_wmask_in[184]
    DIRECTION INPUT ;
    USE SIGNAL ;
    SHAPE ABUTMENT ;
    PORT
      LAYER metal3 ;
      RECT 316.520 34.405 316.730 34.475 ;
    END
  END w0_wmask_in[184]
  PIN w0_wmask_in[185]
    DIRECTION INPUT ;
    USE SIGNAL ;
    SHAPE ABUTMENT ;
    PORT
      LAYER metal3 ;
      RECT 316.520 36.085 316.730 36.155 ;
    END
  END w0_wmask_in[185]
  PIN w0_wmask_in[186]
    DIRECTION INPUT ;
    USE SIGNAL ;
    SHAPE ABUTMENT ;
    PORT
      LAYER metal3 ;
      RECT 316.520 37.765 316.730 37.835 ;
    END
  END w0_wmask_in[186]
  PIN w0_wmask_in[187]
    DIRECTION INPUT ;
    USE SIGNAL ;
    SHAPE ABUTMENT ;
    PORT
      LAYER metal3 ;
      RECT 316.520 39.445 316.730 39.515 ;
    END
  END w0_wmask_in[187]
  PIN w0_wmask_in[188]
    DIRECTION INPUT ;
    USE SIGNAL ;
    SHAPE ABUTMENT ;
    PORT
      LAYER metal3 ;
      RECT 316.520 41.125 316.730 41.195 ;
    END
  END w0_wmask_in[188]
  PIN w0_wmask_in[189]
    DIRECTION INPUT ;
    USE SIGNAL ;
    SHAPE ABUTMENT ;
    PORT
      LAYER metal3 ;
      RECT 316.520 42.805 316.730 42.875 ;
    END
  END w0_wmask_in[189]
  PIN w0_wmask_in[190]
    DIRECTION INPUT ;
    USE SIGNAL ;
    SHAPE ABUTMENT ;
    PORT
      LAYER metal3 ;
      RECT 316.520 44.485 316.730 44.555 ;
    END
  END w0_wmask_in[190]
  PIN w0_wmask_in[191]
    DIRECTION INPUT ;
    USE SIGNAL ;
    SHAPE ABUTMENT ;
    PORT
      LAYER metal3 ;
      RECT 316.520 46.165 316.730 46.235 ;
    END
  END w0_wmask_in[191]
  PIN w0_wmask_in[192]
    DIRECTION INPUT ;
    USE SIGNAL ;
    SHAPE ABUTMENT ;
    PORT
      LAYER metal3 ;
      RECT 316.520 47.845 316.730 47.915 ;
    END
  END w0_wmask_in[192]
  PIN w0_wmask_in[193]
    DIRECTION INPUT ;
    USE SIGNAL ;
    SHAPE ABUTMENT ;
    PORT
      LAYER metal3 ;
      RECT 316.520 49.525 316.730 49.595 ;
    END
  END w0_wmask_in[193]
  PIN w0_wmask_in[194]
    DIRECTION INPUT ;
    USE SIGNAL ;
    SHAPE ABUTMENT ;
    PORT
      LAYER metal3 ;
      RECT 316.520 51.205 316.730 51.275 ;
    END
  END w0_wmask_in[194]
  PIN w0_wmask_in[195]
    DIRECTION INPUT ;
    USE SIGNAL ;
    SHAPE ABUTMENT ;
    PORT
      LAYER metal3 ;
      RECT 316.520 52.885 316.730 52.955 ;
    END
  END w0_wmask_in[195]
  PIN w0_wmask_in[196]
    DIRECTION INPUT ;
    USE SIGNAL ;
    SHAPE ABUTMENT ;
    PORT
      LAYER metal3 ;
      RECT 316.520 54.565 316.730 54.635 ;
    END
  END w0_wmask_in[196]
  PIN w0_wmask_in[197]
    DIRECTION INPUT ;
    USE SIGNAL ;
    SHAPE ABUTMENT ;
    PORT
      LAYER metal3 ;
      RECT 316.520 56.245 316.730 56.315 ;
    END
  END w0_wmask_in[197]
  PIN w0_wmask_in[198]
    DIRECTION INPUT ;
    USE SIGNAL ;
    SHAPE ABUTMENT ;
    PORT
      LAYER metal3 ;
      RECT 316.520 57.925 316.730 57.995 ;
    END
  END w0_wmask_in[198]
  PIN w0_wmask_in[199]
    DIRECTION INPUT ;
    USE SIGNAL ;
    SHAPE ABUTMENT ;
    PORT
      LAYER metal3 ;
      RECT 316.520 59.605 316.730 59.675 ;
    END
  END w0_wmask_in[199]
  PIN w0_wmask_in[200]
    DIRECTION INPUT ;
    USE SIGNAL ;
    SHAPE ABUTMENT ;
    PORT
      LAYER metal3 ;
      RECT 316.520 61.285 316.730 61.355 ;
    END
  END w0_wmask_in[200]
  PIN w0_wmask_in[201]
    DIRECTION INPUT ;
    USE SIGNAL ;
    SHAPE ABUTMENT ;
    PORT
      LAYER metal3 ;
      RECT 316.520 62.965 316.730 63.035 ;
    END
  END w0_wmask_in[201]
  PIN w0_wmask_in[202]
    DIRECTION INPUT ;
    USE SIGNAL ;
    SHAPE ABUTMENT ;
    PORT
      LAYER metal3 ;
      RECT 316.520 64.645 316.730 64.715 ;
    END
  END w0_wmask_in[202]
  PIN w0_wmask_in[203]
    DIRECTION INPUT ;
    USE SIGNAL ;
    SHAPE ABUTMENT ;
    PORT
      LAYER metal3 ;
      RECT 316.520 66.325 316.730 66.395 ;
    END
  END w0_wmask_in[203]
  PIN w0_wmask_in[204]
    DIRECTION INPUT ;
    USE SIGNAL ;
    SHAPE ABUTMENT ;
    PORT
      LAYER metal3 ;
      RECT 316.520 68.005 316.730 68.075 ;
    END
  END w0_wmask_in[204]
  PIN w0_wmask_in[205]
    DIRECTION INPUT ;
    USE SIGNAL ;
    SHAPE ABUTMENT ;
    PORT
      LAYER metal3 ;
      RECT 316.520 69.685 316.730 69.755 ;
    END
  END w0_wmask_in[205]
  PIN w0_wmask_in[206]
    DIRECTION INPUT ;
    USE SIGNAL ;
    SHAPE ABUTMENT ;
    PORT
      LAYER metal3 ;
      RECT 316.520 71.365 316.730 71.435 ;
    END
  END w0_wmask_in[206]
  PIN w0_wmask_in[207]
    DIRECTION INPUT ;
    USE SIGNAL ;
    SHAPE ABUTMENT ;
    PORT
      LAYER metal3 ;
      RECT 316.520 73.045 316.730 73.115 ;
    END
  END w0_wmask_in[207]
  PIN w0_wmask_in[208]
    DIRECTION INPUT ;
    USE SIGNAL ;
    SHAPE ABUTMENT ;
    PORT
      LAYER metal3 ;
      RECT 316.520 74.725 316.730 74.795 ;
    END
  END w0_wmask_in[208]
  PIN w0_wmask_in[209]
    DIRECTION INPUT ;
    USE SIGNAL ;
    SHAPE ABUTMENT ;
    PORT
      LAYER metal3 ;
      RECT 316.520 76.405 316.730 76.475 ;
    END
  END w0_wmask_in[209]
  PIN w0_wmask_in[210]
    DIRECTION INPUT ;
    USE SIGNAL ;
    SHAPE ABUTMENT ;
    PORT
      LAYER metal3 ;
      RECT 316.520 78.085 316.730 78.155 ;
    END
  END w0_wmask_in[210]
  PIN w0_wmask_in[211]
    DIRECTION INPUT ;
    USE SIGNAL ;
    SHAPE ABUTMENT ;
    PORT
      LAYER metal3 ;
      RECT 316.520 79.765 316.730 79.835 ;
    END
  END w0_wmask_in[211]
  PIN w0_wmask_in[212]
    DIRECTION INPUT ;
    USE SIGNAL ;
    SHAPE ABUTMENT ;
    PORT
      LAYER metal3 ;
      RECT 316.520 81.445 316.730 81.515 ;
    END
  END w0_wmask_in[212]
  PIN w0_wmask_in[213]
    DIRECTION INPUT ;
    USE SIGNAL ;
    SHAPE ABUTMENT ;
    PORT
      LAYER metal3 ;
      RECT 316.520 83.125 316.730 83.195 ;
    END
  END w0_wmask_in[213]
  PIN w0_wmask_in[214]
    DIRECTION INPUT ;
    USE SIGNAL ;
    SHAPE ABUTMENT ;
    PORT
      LAYER metal3 ;
      RECT 316.520 84.805 316.730 84.875 ;
    END
  END w0_wmask_in[214]
  PIN w0_wmask_in[215]
    DIRECTION INPUT ;
    USE SIGNAL ;
    SHAPE ABUTMENT ;
    PORT
      LAYER metal3 ;
      RECT 316.520 86.485 316.730 86.555 ;
    END
  END w0_wmask_in[215]
  PIN w0_wmask_in[216]
    DIRECTION INPUT ;
    USE SIGNAL ;
    SHAPE ABUTMENT ;
    PORT
      LAYER metal3 ;
      RECT 316.520 88.165 316.730 88.235 ;
    END
  END w0_wmask_in[216]
  PIN w0_wmask_in[217]
    DIRECTION INPUT ;
    USE SIGNAL ;
    SHAPE ABUTMENT ;
    PORT
      LAYER metal3 ;
      RECT 316.520 89.845 316.730 89.915 ;
    END
  END w0_wmask_in[217]
  PIN w0_wmask_in[218]
    DIRECTION INPUT ;
    USE SIGNAL ;
    SHAPE ABUTMENT ;
    PORT
      LAYER metal3 ;
      RECT 316.520 91.525 316.730 91.595 ;
    END
  END w0_wmask_in[218]
  PIN w0_wmask_in[219]
    DIRECTION INPUT ;
    USE SIGNAL ;
    SHAPE ABUTMENT ;
    PORT
      LAYER metal3 ;
      RECT 316.520 93.205 316.730 93.275 ;
    END
  END w0_wmask_in[219]
  PIN w0_wmask_in[220]
    DIRECTION INPUT ;
    USE SIGNAL ;
    SHAPE ABUTMENT ;
    PORT
      LAYER metal3 ;
      RECT 316.520 94.885 316.730 94.955 ;
    END
  END w0_wmask_in[220]
  PIN w0_wmask_in[221]
    DIRECTION INPUT ;
    USE SIGNAL ;
    SHAPE ABUTMENT ;
    PORT
      LAYER metal3 ;
      RECT 316.520 96.565 316.730 96.635 ;
    END
  END w0_wmask_in[221]
  PIN w0_wmask_in[222]
    DIRECTION INPUT ;
    USE SIGNAL ;
    SHAPE ABUTMENT ;
    PORT
      LAYER metal3 ;
      RECT 316.520 98.245 316.730 98.315 ;
    END
  END w0_wmask_in[222]
  PIN w0_wmask_in[223]
    DIRECTION INPUT ;
    USE SIGNAL ;
    SHAPE ABUTMENT ;
    PORT
      LAYER metal3 ;
      RECT 316.520 99.925 316.730 99.995 ;
    END
  END w0_wmask_in[223]
  PIN w0_wmask_in[224]
    DIRECTION INPUT ;
    USE SIGNAL ;
    SHAPE ABUTMENT ;
    PORT
      LAYER metal3 ;
      RECT 316.520 101.605 316.730 101.675 ;
    END
  END w0_wmask_in[224]
  PIN w0_wmask_in[225]
    DIRECTION INPUT ;
    USE SIGNAL ;
    SHAPE ABUTMENT ;
    PORT
      LAYER metal3 ;
      RECT 316.520 103.285 316.730 103.355 ;
    END
  END w0_wmask_in[225]
  PIN w0_wmask_in[226]
    DIRECTION INPUT ;
    USE SIGNAL ;
    SHAPE ABUTMENT ;
    PORT
      LAYER metal3 ;
      RECT 316.520 104.965 316.730 105.035 ;
    END
  END w0_wmask_in[226]
  PIN w0_wmask_in[227]
    DIRECTION INPUT ;
    USE SIGNAL ;
    SHAPE ABUTMENT ;
    PORT
      LAYER metal3 ;
      RECT 316.520 106.645 316.730 106.715 ;
    END
  END w0_wmask_in[227]
  PIN w0_wmask_in[228]
    DIRECTION INPUT ;
    USE SIGNAL ;
    SHAPE ABUTMENT ;
    PORT
      LAYER metal3 ;
      RECT 316.520 108.325 316.730 108.395 ;
    END
  END w0_wmask_in[228]
  PIN w0_wmask_in[229]
    DIRECTION INPUT ;
    USE SIGNAL ;
    SHAPE ABUTMENT ;
    PORT
      LAYER metal3 ;
      RECT 316.520 110.005 316.730 110.075 ;
    END
  END w0_wmask_in[229]
  PIN w0_wmask_in[230]
    DIRECTION INPUT ;
    USE SIGNAL ;
    SHAPE ABUTMENT ;
    PORT
      LAYER metal3 ;
      RECT 316.520 111.685 316.730 111.755 ;
    END
  END w0_wmask_in[230]
  PIN w0_wmask_in[231]
    DIRECTION INPUT ;
    USE SIGNAL ;
    SHAPE ABUTMENT ;
    PORT
      LAYER metal3 ;
      RECT 316.520 113.365 316.730 113.435 ;
    END
  END w0_wmask_in[231]
  PIN w0_wmask_in[232]
    DIRECTION INPUT ;
    USE SIGNAL ;
    SHAPE ABUTMENT ;
    PORT
      LAYER metal3 ;
      RECT 316.520 115.045 316.730 115.115 ;
    END
  END w0_wmask_in[232]
  PIN w0_wmask_in[233]
    DIRECTION INPUT ;
    USE SIGNAL ;
    SHAPE ABUTMENT ;
    PORT
      LAYER metal3 ;
      RECT 316.520 116.725 316.730 116.795 ;
    END
  END w0_wmask_in[233]
  PIN w0_wmask_in[234]
    DIRECTION INPUT ;
    USE SIGNAL ;
    SHAPE ABUTMENT ;
    PORT
      LAYER metal3 ;
      RECT 316.520 118.405 316.730 118.475 ;
    END
  END w0_wmask_in[234]
  PIN w0_wmask_in[235]
    DIRECTION INPUT ;
    USE SIGNAL ;
    SHAPE ABUTMENT ;
    PORT
      LAYER metal3 ;
      RECT 316.520 120.085 316.730 120.155 ;
    END
  END w0_wmask_in[235]
  PIN w0_wmask_in[236]
    DIRECTION INPUT ;
    USE SIGNAL ;
    SHAPE ABUTMENT ;
    PORT
      LAYER metal3 ;
      RECT 316.520 121.765 316.730 121.835 ;
    END
  END w0_wmask_in[236]
  PIN w0_wmask_in[237]
    DIRECTION INPUT ;
    USE SIGNAL ;
    SHAPE ABUTMENT ;
    PORT
      LAYER metal3 ;
      RECT 316.520 123.445 316.730 123.515 ;
    END
  END w0_wmask_in[237]
  PIN w0_wmask_in[238]
    DIRECTION INPUT ;
    USE SIGNAL ;
    SHAPE ABUTMENT ;
    PORT
      LAYER metal3 ;
      RECT 316.520 125.125 316.730 125.195 ;
    END
  END w0_wmask_in[238]
  PIN w0_wmask_in[239]
    DIRECTION INPUT ;
    USE SIGNAL ;
    SHAPE ABUTMENT ;
    PORT
      LAYER metal3 ;
      RECT 316.520 126.805 316.730 126.875 ;
    END
  END w0_wmask_in[239]
  PIN w0_wmask_in[240]
    DIRECTION INPUT ;
    USE SIGNAL ;
    SHAPE ABUTMENT ;
    PORT
      LAYER metal3 ;
      RECT 316.520 128.485 316.730 128.555 ;
    END
  END w0_wmask_in[240]
  PIN w0_wmask_in[241]
    DIRECTION INPUT ;
    USE SIGNAL ;
    SHAPE ABUTMENT ;
    PORT
      LAYER metal3 ;
      RECT 316.520 130.165 316.730 130.235 ;
    END
  END w0_wmask_in[241]
  PIN w0_wmask_in[242]
    DIRECTION INPUT ;
    USE SIGNAL ;
    SHAPE ABUTMENT ;
    PORT
      LAYER metal3 ;
      RECT 316.520 131.845 316.730 131.915 ;
    END
  END w0_wmask_in[242]
  PIN w0_wmask_in[243]
    DIRECTION INPUT ;
    USE SIGNAL ;
    SHAPE ABUTMENT ;
    PORT
      LAYER metal3 ;
      RECT 316.520 133.525 316.730 133.595 ;
    END
  END w0_wmask_in[243]
  PIN w0_wmask_in[244]
    DIRECTION INPUT ;
    USE SIGNAL ;
    SHAPE ABUTMENT ;
    PORT
      LAYER metal3 ;
      RECT 316.520 135.205 316.730 135.275 ;
    END
  END w0_wmask_in[244]
  PIN w0_wmask_in[245]
    DIRECTION INPUT ;
    USE SIGNAL ;
    SHAPE ABUTMENT ;
    PORT
      LAYER metal3 ;
      RECT 316.520 136.885 316.730 136.955 ;
    END
  END w0_wmask_in[245]
  PIN w0_wmask_in[246]
    DIRECTION INPUT ;
    USE SIGNAL ;
    SHAPE ABUTMENT ;
    PORT
      LAYER metal3 ;
      RECT 316.520 138.565 316.730 138.635 ;
    END
  END w0_wmask_in[246]
  PIN w0_wmask_in[247]
    DIRECTION INPUT ;
    USE SIGNAL ;
    SHAPE ABUTMENT ;
    PORT
      LAYER metal3 ;
      RECT 316.520 140.245 316.730 140.315 ;
    END
  END w0_wmask_in[247]
  PIN w0_wmask_in[248]
    DIRECTION INPUT ;
    USE SIGNAL ;
    SHAPE ABUTMENT ;
    PORT
      LAYER metal3 ;
      RECT 316.520 141.925 316.730 141.995 ;
    END
  END w0_wmask_in[248]
  PIN w0_wmask_in[249]
    DIRECTION INPUT ;
    USE SIGNAL ;
    SHAPE ABUTMENT ;
    PORT
      LAYER metal3 ;
      RECT 316.520 143.605 316.730 143.675 ;
    END
  END w0_wmask_in[249]
  PIN w0_wmask_in[250]
    DIRECTION INPUT ;
    USE SIGNAL ;
    SHAPE ABUTMENT ;
    PORT
      LAYER metal3 ;
      RECT 316.520 145.285 316.730 145.355 ;
    END
  END w0_wmask_in[250]
  PIN w0_wmask_in[251]
    DIRECTION INPUT ;
    USE SIGNAL ;
    SHAPE ABUTMENT ;
    PORT
      LAYER metal3 ;
      RECT 316.520 146.965 316.730 147.035 ;
    END
  END w0_wmask_in[251]
  PIN w0_wmask_in[252]
    DIRECTION INPUT ;
    USE SIGNAL ;
    SHAPE ABUTMENT ;
    PORT
      LAYER metal3 ;
      RECT 316.520 148.645 316.730 148.715 ;
    END
  END w0_wmask_in[252]
  PIN w0_wmask_in[253]
    DIRECTION INPUT ;
    USE SIGNAL ;
    SHAPE ABUTMENT ;
    PORT
      LAYER metal3 ;
      RECT 316.520 150.325 316.730 150.395 ;
    END
  END w0_wmask_in[253]
  PIN w0_wmask_in[254]
    DIRECTION INPUT ;
    USE SIGNAL ;
    SHAPE ABUTMENT ;
    PORT
      LAYER metal3 ;
      RECT 316.520 152.005 316.730 152.075 ;
    END
  END w0_wmask_in[254]
  PIN w0_wmask_in[255]
    DIRECTION INPUT ;
    USE SIGNAL ;
    SHAPE ABUTMENT ;
    PORT
      LAYER metal3 ;
      RECT 316.520 153.685 316.730 153.755 ;
    END
  END w0_wmask_in[255]
  PIN w0_wmask_in[256]
    DIRECTION INPUT ;
    USE SIGNAL ;
    SHAPE ABUTMENT ;
    PORT
      LAYER metal3 ;
      RECT 316.520 155.365 316.730 155.435 ;
    END
  END w0_wmask_in[256]
  PIN w0_wmask_in[257]
    DIRECTION INPUT ;
    USE SIGNAL ;
    SHAPE ABUTMENT ;
    PORT
      LAYER metal3 ;
      RECT 316.520 157.045 316.730 157.115 ;
    END
  END w0_wmask_in[257]
  PIN w0_wmask_in[258]
    DIRECTION INPUT ;
    USE SIGNAL ;
    SHAPE ABUTMENT ;
    PORT
      LAYER metal3 ;
      RECT 316.520 158.725 316.730 158.795 ;
    END
  END w0_wmask_in[258]
  PIN w0_wmask_in[259]
    DIRECTION INPUT ;
    USE SIGNAL ;
    SHAPE ABUTMENT ;
    PORT
      LAYER metal3 ;
      RECT 316.520 160.405 316.730 160.475 ;
    END
  END w0_wmask_in[259]
  PIN w0_wmask_in[260]
    DIRECTION INPUT ;
    USE SIGNAL ;
    SHAPE ABUTMENT ;
    PORT
      LAYER metal3 ;
      RECT 316.520 162.085 316.730 162.155 ;
    END
  END w0_wmask_in[260]
  PIN w0_wmask_in[261]
    DIRECTION INPUT ;
    USE SIGNAL ;
    SHAPE ABUTMENT ;
    PORT
      LAYER metal3 ;
      RECT 316.520 163.765 316.730 163.835 ;
    END
  END w0_wmask_in[261]
  PIN w0_wmask_in[262]
    DIRECTION INPUT ;
    USE SIGNAL ;
    SHAPE ABUTMENT ;
    PORT
      LAYER metal3 ;
      RECT 316.520 165.445 316.730 165.515 ;
    END
  END w0_wmask_in[262]
  PIN w0_wmask_in[263]
    DIRECTION INPUT ;
    USE SIGNAL ;
    SHAPE ABUTMENT ;
    PORT
      LAYER metal3 ;
      RECT 316.520 167.125 316.730 167.195 ;
    END
  END w0_wmask_in[263]
  PIN w0_wmask_in[264]
    DIRECTION INPUT ;
    USE SIGNAL ;
    SHAPE ABUTMENT ;
    PORT
      LAYER metal3 ;
      RECT 316.520 168.805 316.730 168.875 ;
    END
  END w0_wmask_in[264]
  PIN w0_wmask_in[265]
    DIRECTION INPUT ;
    USE SIGNAL ;
    SHAPE ABUTMENT ;
    PORT
      LAYER metal3 ;
      RECT 316.520 170.485 316.730 170.555 ;
    END
  END w0_wmask_in[265]
  PIN w0_wmask_in[266]
    DIRECTION INPUT ;
    USE SIGNAL ;
    SHAPE ABUTMENT ;
    PORT
      LAYER metal3 ;
      RECT 316.520 172.165 316.730 172.235 ;
    END
  END w0_wmask_in[266]
  PIN w0_wmask_in[267]
    DIRECTION INPUT ;
    USE SIGNAL ;
    SHAPE ABUTMENT ;
    PORT
      LAYER metal3 ;
      RECT 316.520 173.845 316.730 173.915 ;
    END
  END w0_wmask_in[267]
  PIN w0_wmask_in[268]
    DIRECTION INPUT ;
    USE SIGNAL ;
    SHAPE ABUTMENT ;
    PORT
      LAYER metal3 ;
      RECT 316.520 175.525 316.730 175.595 ;
    END
  END w0_wmask_in[268]
  PIN w0_wmask_in[269]
    DIRECTION INPUT ;
    USE SIGNAL ;
    SHAPE ABUTMENT ;
    PORT
      LAYER metal3 ;
      RECT 316.520 177.205 316.730 177.275 ;
    END
  END w0_wmask_in[269]
  PIN w0_wmask_in[270]
    DIRECTION INPUT ;
    USE SIGNAL ;
    SHAPE ABUTMENT ;
    PORT
      LAYER metal3 ;
      RECT 316.520 178.885 316.730 178.955 ;
    END
  END w0_wmask_in[270]
  PIN w0_wmask_in[271]
    DIRECTION INPUT ;
    USE SIGNAL ;
    SHAPE ABUTMENT ;
    PORT
      LAYER metal3 ;
      RECT 316.520 180.565 316.730 180.635 ;
    END
  END w0_wmask_in[271]
  PIN w0_wmask_in[272]
    DIRECTION INPUT ;
    USE SIGNAL ;
    SHAPE ABUTMENT ;
    PORT
      LAYER metal3 ;
      RECT 316.520 182.245 316.730 182.315 ;
    END
  END w0_wmask_in[272]
  PIN w0_wmask_in[273]
    DIRECTION INPUT ;
    USE SIGNAL ;
    SHAPE ABUTMENT ;
    PORT
      LAYER metal3 ;
      RECT 316.520 183.925 316.730 183.995 ;
    END
  END w0_wmask_in[273]
  PIN w0_wmask_in[274]
    DIRECTION INPUT ;
    USE SIGNAL ;
    SHAPE ABUTMENT ;
    PORT
      LAYER metal3 ;
      RECT 316.520 185.605 316.730 185.675 ;
    END
  END w0_wmask_in[274]
  PIN w0_wmask_in[275]
    DIRECTION INPUT ;
    USE SIGNAL ;
    SHAPE ABUTMENT ;
    PORT
      LAYER metal3 ;
      RECT 316.520 187.285 316.730 187.355 ;
    END
  END w0_wmask_in[275]
  PIN w0_wmask_in[276]
    DIRECTION INPUT ;
    USE SIGNAL ;
    SHAPE ABUTMENT ;
    PORT
      LAYER metal3 ;
      RECT 316.520 188.965 316.730 189.035 ;
    END
  END w0_wmask_in[276]
  PIN w0_wmask_in[277]
    DIRECTION INPUT ;
    USE SIGNAL ;
    SHAPE ABUTMENT ;
    PORT
      LAYER metal3 ;
      RECT 316.520 190.645 316.730 190.715 ;
    END
  END w0_wmask_in[277]
  PIN w0_wmask_in[278]
    DIRECTION INPUT ;
    USE SIGNAL ;
    SHAPE ABUTMENT ;
    PORT
      LAYER metal3 ;
      RECT 316.520 192.325 316.730 192.395 ;
    END
  END w0_wmask_in[278]
  PIN w0_wmask_in[279]
    DIRECTION INPUT ;
    USE SIGNAL ;
    SHAPE ABUTMENT ;
    PORT
      LAYER metal3 ;
      RECT 316.520 194.005 316.730 194.075 ;
    END
  END w0_wmask_in[279]
  PIN w0_wmask_in[280]
    DIRECTION INPUT ;
    USE SIGNAL ;
    SHAPE ABUTMENT ;
    PORT
      LAYER metal3 ;
      RECT 316.520 195.685 316.730 195.755 ;
    END
  END w0_wmask_in[280]
  PIN w0_wmask_in[281]
    DIRECTION INPUT ;
    USE SIGNAL ;
    SHAPE ABUTMENT ;
    PORT
      LAYER metal3 ;
      RECT 316.520 197.365 316.730 197.435 ;
    END
  END w0_wmask_in[281]
  PIN w0_wmask_in[282]
    DIRECTION INPUT ;
    USE SIGNAL ;
    SHAPE ABUTMENT ;
    PORT
      LAYER metal3 ;
      RECT 316.520 199.045 316.730 199.115 ;
    END
  END w0_wmask_in[282]
  PIN w0_wmask_in[283]
    DIRECTION INPUT ;
    USE SIGNAL ;
    SHAPE ABUTMENT ;
    PORT
      LAYER metal3 ;
      RECT 316.520 200.725 316.730 200.795 ;
    END
  END w0_wmask_in[283]
  PIN w0_wmask_in[284]
    DIRECTION INPUT ;
    USE SIGNAL ;
    SHAPE ABUTMENT ;
    PORT
      LAYER metal3 ;
      RECT 316.520 202.405 316.730 202.475 ;
    END
  END w0_wmask_in[284]
  PIN w0_wmask_in[285]
    DIRECTION INPUT ;
    USE SIGNAL ;
    SHAPE ABUTMENT ;
    PORT
      LAYER metal3 ;
      RECT 316.520 204.085 316.730 204.155 ;
    END
  END w0_wmask_in[285]
  PIN w0_wmask_in[286]
    DIRECTION INPUT ;
    USE SIGNAL ;
    SHAPE ABUTMENT ;
    PORT
      LAYER metal3 ;
      RECT 316.520 205.765 316.730 205.835 ;
    END
  END w0_wmask_in[286]
  PIN w0_wmask_in[287]
    DIRECTION INPUT ;
    USE SIGNAL ;
    SHAPE ABUTMENT ;
    PORT
      LAYER metal3 ;
      RECT 316.520 207.445 316.730 207.515 ;
    END
  END w0_wmask_in[287]
  PIN w0_wmask_in[288]
    DIRECTION INPUT ;
    USE SIGNAL ;
    SHAPE ABUTMENT ;
    PORT
      LAYER metal3 ;
      RECT 316.520 209.125 316.730 209.195 ;
    END
  END w0_wmask_in[288]
  PIN w0_wmask_in[289]
    DIRECTION INPUT ;
    USE SIGNAL ;
    SHAPE ABUTMENT ;
    PORT
      LAYER metal3 ;
      RECT 316.520 210.805 316.730 210.875 ;
    END
  END w0_wmask_in[289]
  PIN w0_wmask_in[290]
    DIRECTION INPUT ;
    USE SIGNAL ;
    SHAPE ABUTMENT ;
    PORT
      LAYER metal3 ;
      RECT 316.520 212.485 316.730 212.555 ;
    END
  END w0_wmask_in[290]
  PIN w0_wmask_in[291]
    DIRECTION INPUT ;
    USE SIGNAL ;
    SHAPE ABUTMENT ;
    PORT
      LAYER metal3 ;
      RECT 316.520 214.165 316.730 214.235 ;
    END
  END w0_wmask_in[291]
  PIN w0_wmask_in[292]
    DIRECTION INPUT ;
    USE SIGNAL ;
    SHAPE ABUTMENT ;
    PORT
      LAYER metal3 ;
      RECT 316.520 215.845 316.730 215.915 ;
    END
  END w0_wmask_in[292]
  PIN w0_wmask_in[293]
    DIRECTION INPUT ;
    USE SIGNAL ;
    SHAPE ABUTMENT ;
    PORT
      LAYER metal3 ;
      RECT 316.520 217.525 316.730 217.595 ;
    END
  END w0_wmask_in[293]
  PIN w0_wmask_in[294]
    DIRECTION INPUT ;
    USE SIGNAL ;
    SHAPE ABUTMENT ;
    PORT
      LAYER metal3 ;
      RECT 316.520 219.205 316.730 219.275 ;
    END
  END w0_wmask_in[294]
  PIN w0_wmask_in[295]
    DIRECTION INPUT ;
    USE SIGNAL ;
    SHAPE ABUTMENT ;
    PORT
      LAYER metal3 ;
      RECT 316.520 220.885 316.730 220.955 ;
    END
  END w0_wmask_in[295]
  PIN w0_wmask_in[296]
    DIRECTION INPUT ;
    USE SIGNAL ;
    SHAPE ABUTMENT ;
    PORT
      LAYER metal3 ;
      RECT 316.520 222.565 316.730 222.635 ;
    END
  END w0_wmask_in[296]
  PIN w0_wmask_in[297]
    DIRECTION INPUT ;
    USE SIGNAL ;
    SHAPE ABUTMENT ;
    PORT
      LAYER metal3 ;
      RECT 316.520 224.245 316.730 224.315 ;
    END
  END w0_wmask_in[297]
  PIN w0_wmask_in[298]
    DIRECTION INPUT ;
    USE SIGNAL ;
    SHAPE ABUTMENT ;
    PORT
      LAYER metal3 ;
      RECT 316.520 225.925 316.730 225.995 ;
    END
  END w0_wmask_in[298]
  PIN w0_wmask_in[299]
    DIRECTION INPUT ;
    USE SIGNAL ;
    SHAPE ABUTMENT ;
    PORT
      LAYER metal3 ;
      RECT 316.520 227.605 316.730 227.675 ;
    END
  END w0_wmask_in[299]
  PIN w0_wmask_in[300]
    DIRECTION INPUT ;
    USE SIGNAL ;
    SHAPE ABUTMENT ;
    PORT
      LAYER metal3 ;
      RECT 316.520 229.285 316.730 229.355 ;
    END
  END w0_wmask_in[300]
  PIN w0_wmask_in[301]
    DIRECTION INPUT ;
    USE SIGNAL ;
    SHAPE ABUTMENT ;
    PORT
      LAYER metal3 ;
      RECT 316.520 230.965 316.730 231.035 ;
    END
  END w0_wmask_in[301]
  PIN w0_wmask_in[302]
    DIRECTION INPUT ;
    USE SIGNAL ;
    SHAPE ABUTMENT ;
    PORT
      LAYER metal3 ;
      RECT 316.520 232.645 316.730 232.715 ;
    END
  END w0_wmask_in[302]
  PIN w0_wmask_in[303]
    DIRECTION INPUT ;
    USE SIGNAL ;
    SHAPE ABUTMENT ;
    PORT
      LAYER metal3 ;
      RECT 316.520 234.325 316.730 234.395 ;
    END
  END w0_wmask_in[303]
  PIN w0_wmask_in[304]
    DIRECTION INPUT ;
    USE SIGNAL ;
    SHAPE ABUTMENT ;
    PORT
      LAYER metal3 ;
      RECT 316.520 236.005 316.730 236.075 ;
    END
  END w0_wmask_in[304]
  PIN w0_wmask_in[305]
    DIRECTION INPUT ;
    USE SIGNAL ;
    SHAPE ABUTMENT ;
    PORT
      LAYER metal3 ;
      RECT 316.520 237.685 316.730 237.755 ;
    END
  END w0_wmask_in[305]
  PIN w0_wmask_in[306]
    DIRECTION INPUT ;
    USE SIGNAL ;
    SHAPE ABUTMENT ;
    PORT
      LAYER metal3 ;
      RECT 316.520 239.365 316.730 239.435 ;
    END
  END w0_wmask_in[306]
  PIN w0_wmask_in[307]
    DIRECTION INPUT ;
    USE SIGNAL ;
    SHAPE ABUTMENT ;
    PORT
      LAYER metal3 ;
      RECT 316.520 241.045 316.730 241.115 ;
    END
  END w0_wmask_in[307]
  PIN w0_wmask_in[308]
    DIRECTION INPUT ;
    USE SIGNAL ;
    SHAPE ABUTMENT ;
    PORT
      LAYER metal3 ;
      RECT 316.520 242.725 316.730 242.795 ;
    END
  END w0_wmask_in[308]
  PIN w0_wmask_in[309]
    DIRECTION INPUT ;
    USE SIGNAL ;
    SHAPE ABUTMENT ;
    PORT
      LAYER metal3 ;
      RECT 316.520 244.405 316.730 244.475 ;
    END
  END w0_wmask_in[309]
  PIN w0_wmask_in[310]
    DIRECTION INPUT ;
    USE SIGNAL ;
    SHAPE ABUTMENT ;
    PORT
      LAYER metal3 ;
      RECT 316.520 246.085 316.730 246.155 ;
    END
  END w0_wmask_in[310]
  PIN w0_wmask_in[311]
    DIRECTION INPUT ;
    USE SIGNAL ;
    SHAPE ABUTMENT ;
    PORT
      LAYER metal3 ;
      RECT 316.520 247.765 316.730 247.835 ;
    END
  END w0_wmask_in[311]
  PIN w0_wmask_in[312]
    DIRECTION INPUT ;
    USE SIGNAL ;
    SHAPE ABUTMENT ;
    PORT
      LAYER metal3 ;
      RECT 316.520 249.445 316.730 249.515 ;
    END
  END w0_wmask_in[312]
  PIN w0_wmask_in[313]
    DIRECTION INPUT ;
    USE SIGNAL ;
    SHAPE ABUTMENT ;
    PORT
      LAYER metal3 ;
      RECT 316.520 251.125 316.730 251.195 ;
    END
  END w0_wmask_in[313]
  PIN w0_wmask_in[314]
    DIRECTION INPUT ;
    USE SIGNAL ;
    SHAPE ABUTMENT ;
    PORT
      LAYER metal3 ;
      RECT 316.520 252.805 316.730 252.875 ;
    END
  END w0_wmask_in[314]
  PIN w0_wmask_in[315]
    DIRECTION INPUT ;
    USE SIGNAL ;
    SHAPE ABUTMENT ;
    PORT
      LAYER metal3 ;
      RECT 316.520 254.485 316.730 254.555 ;
    END
  END w0_wmask_in[315]
  PIN w0_wmask_in[316]
    DIRECTION INPUT ;
    USE SIGNAL ;
    SHAPE ABUTMENT ;
    PORT
      LAYER metal3 ;
      RECT 316.520 256.165 316.730 256.235 ;
    END
  END w0_wmask_in[316]
  PIN w0_wmask_in[317]
    DIRECTION INPUT ;
    USE SIGNAL ;
    SHAPE ABUTMENT ;
    PORT
      LAYER metal3 ;
      RECT 316.520 257.845 316.730 257.915 ;
    END
  END w0_wmask_in[317]
  PIN w0_wmask_in[318]
    DIRECTION INPUT ;
    USE SIGNAL ;
    SHAPE ABUTMENT ;
    PORT
      LAYER metal3 ;
      RECT 316.520 259.525 316.730 259.595 ;
    END
  END w0_wmask_in[318]
  PIN w0_wmask_in[319]
    DIRECTION INPUT ;
    USE SIGNAL ;
    SHAPE ABUTMENT ;
    PORT
      LAYER metal3 ;
      RECT 316.520 261.205 316.730 261.275 ;
    END
  END w0_wmask_in[319]
  PIN w0_wmask_in[320]
    DIRECTION INPUT ;
    USE SIGNAL ;
    SHAPE ABUTMENT ;
    PORT
      LAYER metal3 ;
      RECT 316.520 262.885 316.730 262.955 ;
    END
  END w0_wmask_in[320]
  PIN w0_wmask_in[321]
    DIRECTION INPUT ;
    USE SIGNAL ;
    SHAPE ABUTMENT ;
    PORT
      LAYER metal3 ;
      RECT 316.520 264.565 316.730 264.635 ;
    END
  END w0_wmask_in[321]
  PIN w0_wmask_in[322]
    DIRECTION INPUT ;
    USE SIGNAL ;
    SHAPE ABUTMENT ;
    PORT
      LAYER metal3 ;
      RECT 316.520 266.245 316.730 266.315 ;
    END
  END w0_wmask_in[322]
  PIN w0_wmask_in[323]
    DIRECTION INPUT ;
    USE SIGNAL ;
    SHAPE ABUTMENT ;
    PORT
      LAYER metal3 ;
      RECT 316.520 267.925 316.730 267.995 ;
    END
  END w0_wmask_in[323]
  PIN w0_wmask_in[324]
    DIRECTION INPUT ;
    USE SIGNAL ;
    SHAPE ABUTMENT ;
    PORT
      LAYER metal3 ;
      RECT 316.520 269.605 316.730 269.675 ;
    END
  END w0_wmask_in[324]
  PIN w0_wmask_in[325]
    DIRECTION INPUT ;
    USE SIGNAL ;
    SHAPE ABUTMENT ;
    PORT
      LAYER metal3 ;
      RECT 316.520 271.285 316.730 271.355 ;
    END
  END w0_wmask_in[325]
  PIN w0_wmask_in[326]
    DIRECTION INPUT ;
    USE SIGNAL ;
    SHAPE ABUTMENT ;
    PORT
      LAYER metal3 ;
      RECT 316.520 272.965 316.730 273.035 ;
    END
  END w0_wmask_in[326]
  PIN w0_wmask_in[327]
    DIRECTION INPUT ;
    USE SIGNAL ;
    SHAPE ABUTMENT ;
    PORT
      LAYER metal2 ;
      RECT 1.105 577.990 1.175 578.200 ;
    END
  END w0_wmask_in[327]
  PIN w0_wmask_in[328]
    DIRECTION INPUT ;
    USE SIGNAL ;
    SHAPE ABUTMENT ;
    PORT
      LAYER metal2 ;
      RECT 1.485 577.990 1.555 578.200 ;
    END
  END w0_wmask_in[328]
  PIN w0_wmask_in[329]
    DIRECTION INPUT ;
    USE SIGNAL ;
    SHAPE ABUTMENT ;
    PORT
      LAYER metal2 ;
      RECT 1.865 577.990 1.935 578.200 ;
    END
  END w0_wmask_in[329]
  PIN w0_wmask_in[330]
    DIRECTION INPUT ;
    USE SIGNAL ;
    SHAPE ABUTMENT ;
    PORT
      LAYER metal2 ;
      RECT 2.245 577.990 2.315 578.200 ;
    END
  END w0_wmask_in[330]
  PIN w0_wmask_in[331]
    DIRECTION INPUT ;
    USE SIGNAL ;
    SHAPE ABUTMENT ;
    PORT
      LAYER metal2 ;
      RECT 2.625 577.990 2.695 578.200 ;
    END
  END w0_wmask_in[331]
  PIN w0_wmask_in[332]
    DIRECTION INPUT ;
    USE SIGNAL ;
    SHAPE ABUTMENT ;
    PORT
      LAYER metal2 ;
      RECT 3.005 577.990 3.075 578.200 ;
    END
  END w0_wmask_in[332]
  PIN w0_wmask_in[333]
    DIRECTION INPUT ;
    USE SIGNAL ;
    SHAPE ABUTMENT ;
    PORT
      LAYER metal2 ;
      RECT 3.385 577.990 3.455 578.200 ;
    END
  END w0_wmask_in[333]
  PIN w0_wmask_in[334]
    DIRECTION INPUT ;
    USE SIGNAL ;
    SHAPE ABUTMENT ;
    PORT
      LAYER metal2 ;
      RECT 3.765 577.990 3.835 578.200 ;
    END
  END w0_wmask_in[334]
  PIN w0_wmask_in[335]
    DIRECTION INPUT ;
    USE SIGNAL ;
    SHAPE ABUTMENT ;
    PORT
      LAYER metal2 ;
      RECT 4.145 577.990 4.215 578.200 ;
    END
  END w0_wmask_in[335]
  PIN w0_wmask_in[336]
    DIRECTION INPUT ;
    USE SIGNAL ;
    SHAPE ABUTMENT ;
    PORT
      LAYER metal2 ;
      RECT 4.525 577.990 4.595 578.200 ;
    END
  END w0_wmask_in[336]
  PIN w0_wmask_in[337]
    DIRECTION INPUT ;
    USE SIGNAL ;
    SHAPE ABUTMENT ;
    PORT
      LAYER metal2 ;
      RECT 4.905 577.990 4.975 578.200 ;
    END
  END w0_wmask_in[337]
  PIN w0_wmask_in[338]
    DIRECTION INPUT ;
    USE SIGNAL ;
    SHAPE ABUTMENT ;
    PORT
      LAYER metal2 ;
      RECT 5.285 577.990 5.355 578.200 ;
    END
  END w0_wmask_in[338]
  PIN w0_wmask_in[339]
    DIRECTION INPUT ;
    USE SIGNAL ;
    SHAPE ABUTMENT ;
    PORT
      LAYER metal2 ;
      RECT 5.665 577.990 5.735 578.200 ;
    END
  END w0_wmask_in[339]
  PIN w0_wmask_in[340]
    DIRECTION INPUT ;
    USE SIGNAL ;
    SHAPE ABUTMENT ;
    PORT
      LAYER metal2 ;
      RECT 6.045 577.990 6.115 578.200 ;
    END
  END w0_wmask_in[340]
  PIN w0_wmask_in[341]
    DIRECTION INPUT ;
    USE SIGNAL ;
    SHAPE ABUTMENT ;
    PORT
      LAYER metal2 ;
      RECT 6.425 577.990 6.495 578.200 ;
    END
  END w0_wmask_in[341]
  PIN w0_wmask_in[342]
    DIRECTION INPUT ;
    USE SIGNAL ;
    SHAPE ABUTMENT ;
    PORT
      LAYER metal2 ;
      RECT 6.805 577.990 6.875 578.200 ;
    END
  END w0_wmask_in[342]
  PIN w0_wmask_in[343]
    DIRECTION INPUT ;
    USE SIGNAL ;
    SHAPE ABUTMENT ;
    PORT
      LAYER metal2 ;
      RECT 7.185 577.990 7.255 578.200 ;
    END
  END w0_wmask_in[343]
  PIN w0_wmask_in[344]
    DIRECTION INPUT ;
    USE SIGNAL ;
    SHAPE ABUTMENT ;
    PORT
      LAYER metal2 ;
      RECT 7.565 577.990 7.635 578.200 ;
    END
  END w0_wmask_in[344]
  PIN w0_wmask_in[345]
    DIRECTION INPUT ;
    USE SIGNAL ;
    SHAPE ABUTMENT ;
    PORT
      LAYER metal2 ;
      RECT 7.945 577.990 8.015 578.200 ;
    END
  END w0_wmask_in[345]
  PIN w0_wmask_in[346]
    DIRECTION INPUT ;
    USE SIGNAL ;
    SHAPE ABUTMENT ;
    PORT
      LAYER metal2 ;
      RECT 8.325 577.990 8.395 578.200 ;
    END
  END w0_wmask_in[346]
  PIN w0_wmask_in[347]
    DIRECTION INPUT ;
    USE SIGNAL ;
    SHAPE ABUTMENT ;
    PORT
      LAYER metal2 ;
      RECT 8.705 577.990 8.775 578.200 ;
    END
  END w0_wmask_in[347]
  PIN w0_wmask_in[348]
    DIRECTION INPUT ;
    USE SIGNAL ;
    SHAPE ABUTMENT ;
    PORT
      LAYER metal2 ;
      RECT 9.085 577.990 9.155 578.200 ;
    END
  END w0_wmask_in[348]
  PIN w0_wmask_in[349]
    DIRECTION INPUT ;
    USE SIGNAL ;
    SHAPE ABUTMENT ;
    PORT
      LAYER metal2 ;
      RECT 9.465 577.990 9.535 578.200 ;
    END
  END w0_wmask_in[349]
  PIN w0_wmask_in[350]
    DIRECTION INPUT ;
    USE SIGNAL ;
    SHAPE ABUTMENT ;
    PORT
      LAYER metal2 ;
      RECT 9.845 577.990 9.915 578.200 ;
    END
  END w0_wmask_in[350]
  PIN w0_wmask_in[351]
    DIRECTION INPUT ;
    USE SIGNAL ;
    SHAPE ABUTMENT ;
    PORT
      LAYER metal2 ;
      RECT 10.225 577.990 10.295 578.200 ;
    END
  END w0_wmask_in[351]
  PIN w0_wmask_in[352]
    DIRECTION INPUT ;
    USE SIGNAL ;
    SHAPE ABUTMENT ;
    PORT
      LAYER metal2 ;
      RECT 10.605 577.990 10.675 578.200 ;
    END
  END w0_wmask_in[352]
  PIN w0_wmask_in[353]
    DIRECTION INPUT ;
    USE SIGNAL ;
    SHAPE ABUTMENT ;
    PORT
      LAYER metal2 ;
      RECT 10.985 577.990 11.055 578.200 ;
    END
  END w0_wmask_in[353]
  PIN w0_wmask_in[354]
    DIRECTION INPUT ;
    USE SIGNAL ;
    SHAPE ABUTMENT ;
    PORT
      LAYER metal2 ;
      RECT 11.365 577.990 11.435 578.200 ;
    END
  END w0_wmask_in[354]
  PIN w0_wmask_in[355]
    DIRECTION INPUT ;
    USE SIGNAL ;
    SHAPE ABUTMENT ;
    PORT
      LAYER metal2 ;
      RECT 11.745 577.990 11.815 578.200 ;
    END
  END w0_wmask_in[355]
  PIN w0_wmask_in[356]
    DIRECTION INPUT ;
    USE SIGNAL ;
    SHAPE ABUTMENT ;
    PORT
      LAYER metal2 ;
      RECT 12.125 577.990 12.195 578.200 ;
    END
  END w0_wmask_in[356]
  PIN w0_wmask_in[357]
    DIRECTION INPUT ;
    USE SIGNAL ;
    SHAPE ABUTMENT ;
    PORT
      LAYER metal2 ;
      RECT 12.505 577.990 12.575 578.200 ;
    END
  END w0_wmask_in[357]
  PIN w0_wmask_in[358]
    DIRECTION INPUT ;
    USE SIGNAL ;
    SHAPE ABUTMENT ;
    PORT
      LAYER metal2 ;
      RECT 12.885 577.990 12.955 578.200 ;
    END
  END w0_wmask_in[358]
  PIN w0_wmask_in[359]
    DIRECTION INPUT ;
    USE SIGNAL ;
    SHAPE ABUTMENT ;
    PORT
      LAYER metal2 ;
      RECT 13.265 577.990 13.335 578.200 ;
    END
  END w0_wmask_in[359]
  PIN w0_wmask_in[360]
    DIRECTION INPUT ;
    USE SIGNAL ;
    SHAPE ABUTMENT ;
    PORT
      LAYER metal2 ;
      RECT 13.645 577.990 13.715 578.200 ;
    END
  END w0_wmask_in[360]
  PIN w0_wmask_in[361]
    DIRECTION INPUT ;
    USE SIGNAL ;
    SHAPE ABUTMENT ;
    PORT
      LAYER metal2 ;
      RECT 14.025 577.990 14.095 578.200 ;
    END
  END w0_wmask_in[361]
  PIN w0_wmask_in[362]
    DIRECTION INPUT ;
    USE SIGNAL ;
    SHAPE ABUTMENT ;
    PORT
      LAYER metal2 ;
      RECT 14.405 577.990 14.475 578.200 ;
    END
  END w0_wmask_in[362]
  PIN w0_wmask_in[363]
    DIRECTION INPUT ;
    USE SIGNAL ;
    SHAPE ABUTMENT ;
    PORT
      LAYER metal2 ;
      RECT 14.785 577.990 14.855 578.200 ;
    END
  END w0_wmask_in[363]
  PIN w0_wmask_in[364]
    DIRECTION INPUT ;
    USE SIGNAL ;
    SHAPE ABUTMENT ;
    PORT
      LAYER metal2 ;
      RECT 15.165 577.990 15.235 578.200 ;
    END
  END w0_wmask_in[364]
  PIN w0_wmask_in[365]
    DIRECTION INPUT ;
    USE SIGNAL ;
    SHAPE ABUTMENT ;
    PORT
      LAYER metal2 ;
      RECT 15.545 577.990 15.615 578.200 ;
    END
  END w0_wmask_in[365]
  PIN w0_wmask_in[366]
    DIRECTION INPUT ;
    USE SIGNAL ;
    SHAPE ABUTMENT ;
    PORT
      LAYER metal2 ;
      RECT 15.925 577.990 15.995 578.200 ;
    END
  END w0_wmask_in[366]
  PIN w0_wmask_in[367]
    DIRECTION INPUT ;
    USE SIGNAL ;
    SHAPE ABUTMENT ;
    PORT
      LAYER metal2 ;
      RECT 16.305 577.990 16.375 578.200 ;
    END
  END w0_wmask_in[367]
  PIN w0_wmask_in[368]
    DIRECTION INPUT ;
    USE SIGNAL ;
    SHAPE ABUTMENT ;
    PORT
      LAYER metal2 ;
      RECT 16.685 577.990 16.755 578.200 ;
    END
  END w0_wmask_in[368]
  PIN w0_wmask_in[369]
    DIRECTION INPUT ;
    USE SIGNAL ;
    SHAPE ABUTMENT ;
    PORT
      LAYER metal2 ;
      RECT 17.065 577.990 17.135 578.200 ;
    END
  END w0_wmask_in[369]
  PIN w0_wmask_in[370]
    DIRECTION INPUT ;
    USE SIGNAL ;
    SHAPE ABUTMENT ;
    PORT
      LAYER metal2 ;
      RECT 17.445 577.990 17.515 578.200 ;
    END
  END w0_wmask_in[370]
  PIN w0_wmask_in[371]
    DIRECTION INPUT ;
    USE SIGNAL ;
    SHAPE ABUTMENT ;
    PORT
      LAYER metal2 ;
      RECT 17.825 577.990 17.895 578.200 ;
    END
  END w0_wmask_in[371]
  PIN w0_wmask_in[372]
    DIRECTION INPUT ;
    USE SIGNAL ;
    SHAPE ABUTMENT ;
    PORT
      LAYER metal2 ;
      RECT 18.205 577.990 18.275 578.200 ;
    END
  END w0_wmask_in[372]
  PIN w0_wmask_in[373]
    DIRECTION INPUT ;
    USE SIGNAL ;
    SHAPE ABUTMENT ;
    PORT
      LAYER metal2 ;
      RECT 18.585 577.990 18.655 578.200 ;
    END
  END w0_wmask_in[373]
  PIN w0_wmask_in[374]
    DIRECTION INPUT ;
    USE SIGNAL ;
    SHAPE ABUTMENT ;
    PORT
      LAYER metal2 ;
      RECT 18.965 577.990 19.035 578.200 ;
    END
  END w0_wmask_in[374]
  PIN w0_wmask_in[375]
    DIRECTION INPUT ;
    USE SIGNAL ;
    SHAPE ABUTMENT ;
    PORT
      LAYER metal2 ;
      RECT 19.345 577.990 19.415 578.200 ;
    END
  END w0_wmask_in[375]
  PIN w0_wmask_in[376]
    DIRECTION INPUT ;
    USE SIGNAL ;
    SHAPE ABUTMENT ;
    PORT
      LAYER metal2 ;
      RECT 19.725 577.990 19.795 578.200 ;
    END
  END w0_wmask_in[376]
  PIN w0_wmask_in[377]
    DIRECTION INPUT ;
    USE SIGNAL ;
    SHAPE ABUTMENT ;
    PORT
      LAYER metal2 ;
      RECT 20.105 577.990 20.175 578.200 ;
    END
  END w0_wmask_in[377]
  PIN w0_wmask_in[378]
    DIRECTION INPUT ;
    USE SIGNAL ;
    SHAPE ABUTMENT ;
    PORT
      LAYER metal2 ;
      RECT 20.485 577.990 20.555 578.200 ;
    END
  END w0_wmask_in[378]
  PIN w0_wmask_in[379]
    DIRECTION INPUT ;
    USE SIGNAL ;
    SHAPE ABUTMENT ;
    PORT
      LAYER metal2 ;
      RECT 20.865 577.990 20.935 578.200 ;
    END
  END w0_wmask_in[379]
  PIN w0_wmask_in[380]
    DIRECTION INPUT ;
    USE SIGNAL ;
    SHAPE ABUTMENT ;
    PORT
      LAYER metal2 ;
      RECT 21.245 577.990 21.315 578.200 ;
    END
  END w0_wmask_in[380]
  PIN w0_wmask_in[381]
    DIRECTION INPUT ;
    USE SIGNAL ;
    SHAPE ABUTMENT ;
    PORT
      LAYER metal2 ;
      RECT 21.625 577.990 21.695 578.200 ;
    END
  END w0_wmask_in[381]
  PIN w0_wmask_in[382]
    DIRECTION INPUT ;
    USE SIGNAL ;
    SHAPE ABUTMENT ;
    PORT
      LAYER metal2 ;
      RECT 22.005 577.990 22.075 578.200 ;
    END
  END w0_wmask_in[382]
  PIN w0_wmask_in[383]
    DIRECTION INPUT ;
    USE SIGNAL ;
    SHAPE ABUTMENT ;
    PORT
      LAYER metal2 ;
      RECT 22.385 577.990 22.455 578.200 ;
    END
  END w0_wmask_in[383]
  PIN w0_wmask_in[384]
    DIRECTION INPUT ;
    USE SIGNAL ;
    SHAPE ABUTMENT ;
    PORT
      LAYER metal2 ;
      RECT 22.765 577.990 22.835 578.200 ;
    END
  END w0_wmask_in[384]
  PIN w0_wmask_in[385]
    DIRECTION INPUT ;
    USE SIGNAL ;
    SHAPE ABUTMENT ;
    PORT
      LAYER metal2 ;
      RECT 23.145 577.990 23.215 578.200 ;
    END
  END w0_wmask_in[385]
  PIN w0_wmask_in[386]
    DIRECTION INPUT ;
    USE SIGNAL ;
    SHAPE ABUTMENT ;
    PORT
      LAYER metal2 ;
      RECT 23.525 577.990 23.595 578.200 ;
    END
  END w0_wmask_in[386]
  PIN w0_wmask_in[387]
    DIRECTION INPUT ;
    USE SIGNAL ;
    SHAPE ABUTMENT ;
    PORT
      LAYER metal2 ;
      RECT 23.905 577.990 23.975 578.200 ;
    END
  END w0_wmask_in[387]
  PIN w0_wmask_in[388]
    DIRECTION INPUT ;
    USE SIGNAL ;
    SHAPE ABUTMENT ;
    PORT
      LAYER metal2 ;
      RECT 24.285 577.990 24.355 578.200 ;
    END
  END w0_wmask_in[388]
  PIN w0_wmask_in[389]
    DIRECTION INPUT ;
    USE SIGNAL ;
    SHAPE ABUTMENT ;
    PORT
      LAYER metal2 ;
      RECT 24.665 577.990 24.735 578.200 ;
    END
  END w0_wmask_in[389]
  PIN w0_wmask_in[390]
    DIRECTION INPUT ;
    USE SIGNAL ;
    SHAPE ABUTMENT ;
    PORT
      LAYER metal2 ;
      RECT 25.045 577.990 25.115 578.200 ;
    END
  END w0_wmask_in[390]
  PIN w0_wmask_in[391]
    DIRECTION INPUT ;
    USE SIGNAL ;
    SHAPE ABUTMENT ;
    PORT
      LAYER metal2 ;
      RECT 25.425 577.990 25.495 578.200 ;
    END
  END w0_wmask_in[391]
  PIN w0_wmask_in[392]
    DIRECTION INPUT ;
    USE SIGNAL ;
    SHAPE ABUTMENT ;
    PORT
      LAYER metal2 ;
      RECT 25.805 577.990 25.875 578.200 ;
    END
  END w0_wmask_in[392]
  PIN w0_wmask_in[393]
    DIRECTION INPUT ;
    USE SIGNAL ;
    SHAPE ABUTMENT ;
    PORT
      LAYER metal2 ;
      RECT 26.185 577.990 26.255 578.200 ;
    END
  END w0_wmask_in[393]
  PIN w0_wmask_in[394]
    DIRECTION INPUT ;
    USE SIGNAL ;
    SHAPE ABUTMENT ;
    PORT
      LAYER metal2 ;
      RECT 26.565 577.990 26.635 578.200 ;
    END
  END w0_wmask_in[394]
  PIN w0_wmask_in[395]
    DIRECTION INPUT ;
    USE SIGNAL ;
    SHAPE ABUTMENT ;
    PORT
      LAYER metal2 ;
      RECT 26.945 577.990 27.015 578.200 ;
    END
  END w0_wmask_in[395]
  PIN w0_wmask_in[396]
    DIRECTION INPUT ;
    USE SIGNAL ;
    SHAPE ABUTMENT ;
    PORT
      LAYER metal2 ;
      RECT 27.325 577.990 27.395 578.200 ;
    END
  END w0_wmask_in[396]
  PIN w0_wmask_in[397]
    DIRECTION INPUT ;
    USE SIGNAL ;
    SHAPE ABUTMENT ;
    PORT
      LAYER metal2 ;
      RECT 27.705 577.990 27.775 578.200 ;
    END
  END w0_wmask_in[397]
  PIN w0_wmask_in[398]
    DIRECTION INPUT ;
    USE SIGNAL ;
    SHAPE ABUTMENT ;
    PORT
      LAYER metal2 ;
      RECT 28.085 577.990 28.155 578.200 ;
    END
  END w0_wmask_in[398]
  PIN w0_wmask_in[399]
    DIRECTION INPUT ;
    USE SIGNAL ;
    SHAPE ABUTMENT ;
    PORT
      LAYER metal2 ;
      RECT 28.465 577.990 28.535 578.200 ;
    END
  END w0_wmask_in[399]
  PIN w0_wmask_in[400]
    DIRECTION INPUT ;
    USE SIGNAL ;
    SHAPE ABUTMENT ;
    PORT
      LAYER metal2 ;
      RECT 28.845 577.990 28.915 578.200 ;
    END
  END w0_wmask_in[400]
  PIN w0_wmask_in[401]
    DIRECTION INPUT ;
    USE SIGNAL ;
    SHAPE ABUTMENT ;
    PORT
      LAYER metal2 ;
      RECT 29.225 577.990 29.295 578.200 ;
    END
  END w0_wmask_in[401]
  PIN w0_wmask_in[402]
    DIRECTION INPUT ;
    USE SIGNAL ;
    SHAPE ABUTMENT ;
    PORT
      LAYER metal2 ;
      RECT 29.605 577.990 29.675 578.200 ;
    END
  END w0_wmask_in[402]
  PIN w0_wmask_in[403]
    DIRECTION INPUT ;
    USE SIGNAL ;
    SHAPE ABUTMENT ;
    PORT
      LAYER metal2 ;
      RECT 29.985 577.990 30.055 578.200 ;
    END
  END w0_wmask_in[403]
  PIN w0_wmask_in[404]
    DIRECTION INPUT ;
    USE SIGNAL ;
    SHAPE ABUTMENT ;
    PORT
      LAYER metal2 ;
      RECT 30.365 577.990 30.435 578.200 ;
    END
  END w0_wmask_in[404]
  PIN w0_wmask_in[405]
    DIRECTION INPUT ;
    USE SIGNAL ;
    SHAPE ABUTMENT ;
    PORT
      LAYER metal2 ;
      RECT 30.745 577.990 30.815 578.200 ;
    END
  END w0_wmask_in[405]
  PIN w0_wmask_in[406]
    DIRECTION INPUT ;
    USE SIGNAL ;
    SHAPE ABUTMENT ;
    PORT
      LAYER metal2 ;
      RECT 31.125 577.990 31.195 578.200 ;
    END
  END w0_wmask_in[406]
  PIN w0_wmask_in[407]
    DIRECTION INPUT ;
    USE SIGNAL ;
    SHAPE ABUTMENT ;
    PORT
      LAYER metal2 ;
      RECT 31.505 577.990 31.575 578.200 ;
    END
  END w0_wmask_in[407]
  PIN w0_wmask_in[408]
    DIRECTION INPUT ;
    USE SIGNAL ;
    SHAPE ABUTMENT ;
    PORT
      LAYER metal2 ;
      RECT 31.885 577.990 31.955 578.200 ;
    END
  END w0_wmask_in[408]
  PIN w0_wmask_in[409]
    DIRECTION INPUT ;
    USE SIGNAL ;
    SHAPE ABUTMENT ;
    PORT
      LAYER metal2 ;
      RECT 32.265 577.990 32.335 578.200 ;
    END
  END w0_wmask_in[409]
  PIN w0_wmask_in[410]
    DIRECTION INPUT ;
    USE SIGNAL ;
    SHAPE ABUTMENT ;
    PORT
      LAYER metal2 ;
      RECT 32.645 577.990 32.715 578.200 ;
    END
  END w0_wmask_in[410]
  PIN w0_wmask_in[411]
    DIRECTION INPUT ;
    USE SIGNAL ;
    SHAPE ABUTMENT ;
    PORT
      LAYER metal2 ;
      RECT 33.025 577.990 33.095 578.200 ;
    END
  END w0_wmask_in[411]
  PIN w0_wmask_in[412]
    DIRECTION INPUT ;
    USE SIGNAL ;
    SHAPE ABUTMENT ;
    PORT
      LAYER metal2 ;
      RECT 33.405 577.990 33.475 578.200 ;
    END
  END w0_wmask_in[412]
  PIN w0_wmask_in[413]
    DIRECTION INPUT ;
    USE SIGNAL ;
    SHAPE ABUTMENT ;
    PORT
      LAYER metal2 ;
      RECT 33.785 577.990 33.855 578.200 ;
    END
  END w0_wmask_in[413]
  PIN w0_wmask_in[414]
    DIRECTION INPUT ;
    USE SIGNAL ;
    SHAPE ABUTMENT ;
    PORT
      LAYER metal2 ;
      RECT 34.165 577.990 34.235 578.200 ;
    END
  END w0_wmask_in[414]
  PIN w0_wmask_in[415]
    DIRECTION INPUT ;
    USE SIGNAL ;
    SHAPE ABUTMENT ;
    PORT
      LAYER metal2 ;
      RECT 34.545 577.990 34.615 578.200 ;
    END
  END w0_wmask_in[415]
  PIN w0_wmask_in[416]
    DIRECTION INPUT ;
    USE SIGNAL ;
    SHAPE ABUTMENT ;
    PORT
      LAYER metal2 ;
      RECT 34.925 577.990 34.995 578.200 ;
    END
  END w0_wmask_in[416]
  PIN w0_wmask_in[417]
    DIRECTION INPUT ;
    USE SIGNAL ;
    SHAPE ABUTMENT ;
    PORT
      LAYER metal2 ;
      RECT 35.305 577.990 35.375 578.200 ;
    END
  END w0_wmask_in[417]
  PIN w0_wmask_in[418]
    DIRECTION INPUT ;
    USE SIGNAL ;
    SHAPE ABUTMENT ;
    PORT
      LAYER metal2 ;
      RECT 35.685 577.990 35.755 578.200 ;
    END
  END w0_wmask_in[418]
  PIN w0_wmask_in[419]
    DIRECTION INPUT ;
    USE SIGNAL ;
    SHAPE ABUTMENT ;
    PORT
      LAYER metal2 ;
      RECT 36.065 577.990 36.135 578.200 ;
    END
  END w0_wmask_in[419]
  PIN w0_wmask_in[420]
    DIRECTION INPUT ;
    USE SIGNAL ;
    SHAPE ABUTMENT ;
    PORT
      LAYER metal2 ;
      RECT 36.445 577.990 36.515 578.200 ;
    END
  END w0_wmask_in[420]
  PIN w0_wmask_in[421]
    DIRECTION INPUT ;
    USE SIGNAL ;
    SHAPE ABUTMENT ;
    PORT
      LAYER metal2 ;
      RECT 36.825 577.990 36.895 578.200 ;
    END
  END w0_wmask_in[421]
  PIN w0_wmask_in[422]
    DIRECTION INPUT ;
    USE SIGNAL ;
    SHAPE ABUTMENT ;
    PORT
      LAYER metal2 ;
      RECT 37.205 577.990 37.275 578.200 ;
    END
  END w0_wmask_in[422]
  PIN w0_wmask_in[423]
    DIRECTION INPUT ;
    USE SIGNAL ;
    SHAPE ABUTMENT ;
    PORT
      LAYER metal2 ;
      RECT 37.585 577.990 37.655 578.200 ;
    END
  END w0_wmask_in[423]
  PIN w0_wmask_in[424]
    DIRECTION INPUT ;
    USE SIGNAL ;
    SHAPE ABUTMENT ;
    PORT
      LAYER metal2 ;
      RECT 37.965 577.990 38.035 578.200 ;
    END
  END w0_wmask_in[424]
  PIN w0_wmask_in[425]
    DIRECTION INPUT ;
    USE SIGNAL ;
    SHAPE ABUTMENT ;
    PORT
      LAYER metal2 ;
      RECT 38.345 577.990 38.415 578.200 ;
    END
  END w0_wmask_in[425]
  PIN w0_wmask_in[426]
    DIRECTION INPUT ;
    USE SIGNAL ;
    SHAPE ABUTMENT ;
    PORT
      LAYER metal2 ;
      RECT 38.725 577.990 38.795 578.200 ;
    END
  END w0_wmask_in[426]
  PIN w0_wmask_in[427]
    DIRECTION INPUT ;
    USE SIGNAL ;
    SHAPE ABUTMENT ;
    PORT
      LAYER metal2 ;
      RECT 39.105 577.990 39.175 578.200 ;
    END
  END w0_wmask_in[427]
  PIN w0_wmask_in[428]
    DIRECTION INPUT ;
    USE SIGNAL ;
    SHAPE ABUTMENT ;
    PORT
      LAYER metal2 ;
      RECT 39.485 577.990 39.555 578.200 ;
    END
  END w0_wmask_in[428]
  PIN w0_wmask_in[429]
    DIRECTION INPUT ;
    USE SIGNAL ;
    SHAPE ABUTMENT ;
    PORT
      LAYER metal2 ;
      RECT 39.865 577.990 39.935 578.200 ;
    END
  END w0_wmask_in[429]
  PIN w0_wmask_in[430]
    DIRECTION INPUT ;
    USE SIGNAL ;
    SHAPE ABUTMENT ;
    PORT
      LAYER metal2 ;
      RECT 40.245 577.990 40.315 578.200 ;
    END
  END w0_wmask_in[430]
  PIN w0_wmask_in[431]
    DIRECTION INPUT ;
    USE SIGNAL ;
    SHAPE ABUTMENT ;
    PORT
      LAYER metal2 ;
      RECT 40.625 577.990 40.695 578.200 ;
    END
  END w0_wmask_in[431]
  PIN w0_wmask_in[432]
    DIRECTION INPUT ;
    USE SIGNAL ;
    SHAPE ABUTMENT ;
    PORT
      LAYER metal2 ;
      RECT 41.005 577.990 41.075 578.200 ;
    END
  END w0_wmask_in[432]
  PIN w0_wmask_in[433]
    DIRECTION INPUT ;
    USE SIGNAL ;
    SHAPE ABUTMENT ;
    PORT
      LAYER metal2 ;
      RECT 41.385 577.990 41.455 578.200 ;
    END
  END w0_wmask_in[433]
  PIN w0_wmask_in[434]
    DIRECTION INPUT ;
    USE SIGNAL ;
    SHAPE ABUTMENT ;
    PORT
      LAYER metal2 ;
      RECT 41.765 577.990 41.835 578.200 ;
    END
  END w0_wmask_in[434]
  PIN w0_wmask_in[435]
    DIRECTION INPUT ;
    USE SIGNAL ;
    SHAPE ABUTMENT ;
    PORT
      LAYER metal2 ;
      RECT 42.145 577.990 42.215 578.200 ;
    END
  END w0_wmask_in[435]
  PIN w0_wmask_in[436]
    DIRECTION INPUT ;
    USE SIGNAL ;
    SHAPE ABUTMENT ;
    PORT
      LAYER metal2 ;
      RECT 42.525 577.990 42.595 578.200 ;
    END
  END w0_wmask_in[436]
  PIN w0_wmask_in[437]
    DIRECTION INPUT ;
    USE SIGNAL ;
    SHAPE ABUTMENT ;
    PORT
      LAYER metal2 ;
      RECT 42.905 577.990 42.975 578.200 ;
    END
  END w0_wmask_in[437]
  PIN w0_wmask_in[438]
    DIRECTION INPUT ;
    USE SIGNAL ;
    SHAPE ABUTMENT ;
    PORT
      LAYER metal2 ;
      RECT 43.285 577.990 43.355 578.200 ;
    END
  END w0_wmask_in[438]
  PIN w0_wmask_in[439]
    DIRECTION INPUT ;
    USE SIGNAL ;
    SHAPE ABUTMENT ;
    PORT
      LAYER metal2 ;
      RECT 43.665 577.990 43.735 578.200 ;
    END
  END w0_wmask_in[439]
  PIN w0_wmask_in[440]
    DIRECTION INPUT ;
    USE SIGNAL ;
    SHAPE ABUTMENT ;
    PORT
      LAYER metal2 ;
      RECT 44.045 577.990 44.115 578.200 ;
    END
  END w0_wmask_in[440]
  PIN w0_wmask_in[441]
    DIRECTION INPUT ;
    USE SIGNAL ;
    SHAPE ABUTMENT ;
    PORT
      LAYER metal2 ;
      RECT 44.425 577.990 44.495 578.200 ;
    END
  END w0_wmask_in[441]
  PIN w0_wmask_in[442]
    DIRECTION INPUT ;
    USE SIGNAL ;
    SHAPE ABUTMENT ;
    PORT
      LAYER metal2 ;
      RECT 44.805 577.990 44.875 578.200 ;
    END
  END w0_wmask_in[442]
  PIN w0_wmask_in[443]
    DIRECTION INPUT ;
    USE SIGNAL ;
    SHAPE ABUTMENT ;
    PORT
      LAYER metal2 ;
      RECT 45.185 577.990 45.255 578.200 ;
    END
  END w0_wmask_in[443]
  PIN w0_wmask_in[444]
    DIRECTION INPUT ;
    USE SIGNAL ;
    SHAPE ABUTMENT ;
    PORT
      LAYER metal2 ;
      RECT 45.565 577.990 45.635 578.200 ;
    END
  END w0_wmask_in[444]
  PIN w0_wmask_in[445]
    DIRECTION INPUT ;
    USE SIGNAL ;
    SHAPE ABUTMENT ;
    PORT
      LAYER metal2 ;
      RECT 45.945 577.990 46.015 578.200 ;
    END
  END w0_wmask_in[445]
  PIN w0_wmask_in[446]
    DIRECTION INPUT ;
    USE SIGNAL ;
    SHAPE ABUTMENT ;
    PORT
      LAYER metal2 ;
      RECT 46.325 577.990 46.395 578.200 ;
    END
  END w0_wmask_in[446]
  PIN w0_wmask_in[447]
    DIRECTION INPUT ;
    USE SIGNAL ;
    SHAPE ABUTMENT ;
    PORT
      LAYER metal2 ;
      RECT 46.705 577.990 46.775 578.200 ;
    END
  END w0_wmask_in[447]
  PIN w0_wmask_in[448]
    DIRECTION INPUT ;
    USE SIGNAL ;
    SHAPE ABUTMENT ;
    PORT
      LAYER metal2 ;
      RECT 47.085 577.990 47.155 578.200 ;
    END
  END w0_wmask_in[448]
  PIN w0_wmask_in[449]
    DIRECTION INPUT ;
    USE SIGNAL ;
    SHAPE ABUTMENT ;
    PORT
      LAYER metal2 ;
      RECT 47.465 577.990 47.535 578.200 ;
    END
  END w0_wmask_in[449]
  PIN w0_wmask_in[450]
    DIRECTION INPUT ;
    USE SIGNAL ;
    SHAPE ABUTMENT ;
    PORT
      LAYER metal2 ;
      RECT 47.845 577.990 47.915 578.200 ;
    END
  END w0_wmask_in[450]
  PIN w0_wmask_in[451]
    DIRECTION INPUT ;
    USE SIGNAL ;
    SHAPE ABUTMENT ;
    PORT
      LAYER metal2 ;
      RECT 48.225 577.990 48.295 578.200 ;
    END
  END w0_wmask_in[451]
  PIN w0_wmask_in[452]
    DIRECTION INPUT ;
    USE SIGNAL ;
    SHAPE ABUTMENT ;
    PORT
      LAYER metal2 ;
      RECT 48.605 577.990 48.675 578.200 ;
    END
  END w0_wmask_in[452]
  PIN w0_wmask_in[453]
    DIRECTION INPUT ;
    USE SIGNAL ;
    SHAPE ABUTMENT ;
    PORT
      LAYER metal2 ;
      RECT 48.985 577.990 49.055 578.200 ;
    END
  END w0_wmask_in[453]
  PIN w0_wmask_in[454]
    DIRECTION INPUT ;
    USE SIGNAL ;
    SHAPE ABUTMENT ;
    PORT
      LAYER metal2 ;
      RECT 49.365 577.990 49.435 578.200 ;
    END
  END w0_wmask_in[454]
  PIN w0_wmask_in[455]
    DIRECTION INPUT ;
    USE SIGNAL ;
    SHAPE ABUTMENT ;
    PORT
      LAYER metal2 ;
      RECT 49.745 577.990 49.815 578.200 ;
    END
  END w0_wmask_in[455]
  PIN w0_wmask_in[456]
    DIRECTION INPUT ;
    USE SIGNAL ;
    SHAPE ABUTMENT ;
    PORT
      LAYER metal2 ;
      RECT 50.125 577.990 50.195 578.200 ;
    END
  END w0_wmask_in[456]
  PIN w0_wmask_in[457]
    DIRECTION INPUT ;
    USE SIGNAL ;
    SHAPE ABUTMENT ;
    PORT
      LAYER metal2 ;
      RECT 50.505 577.990 50.575 578.200 ;
    END
  END w0_wmask_in[457]
  PIN w0_wmask_in[458]
    DIRECTION INPUT ;
    USE SIGNAL ;
    SHAPE ABUTMENT ;
    PORT
      LAYER metal2 ;
      RECT 50.885 577.990 50.955 578.200 ;
    END
  END w0_wmask_in[458]
  PIN w0_wmask_in[459]
    DIRECTION INPUT ;
    USE SIGNAL ;
    SHAPE ABUTMENT ;
    PORT
      LAYER metal2 ;
      RECT 51.265 577.990 51.335 578.200 ;
    END
  END w0_wmask_in[459]
  PIN w0_wmask_in[460]
    DIRECTION INPUT ;
    USE SIGNAL ;
    SHAPE ABUTMENT ;
    PORT
      LAYER metal2 ;
      RECT 51.645 577.990 51.715 578.200 ;
    END
  END w0_wmask_in[460]
  PIN w0_wmask_in[461]
    DIRECTION INPUT ;
    USE SIGNAL ;
    SHAPE ABUTMENT ;
    PORT
      LAYER metal2 ;
      RECT 52.025 577.990 52.095 578.200 ;
    END
  END w0_wmask_in[461]
  PIN w0_wmask_in[462]
    DIRECTION INPUT ;
    USE SIGNAL ;
    SHAPE ABUTMENT ;
    PORT
      LAYER metal2 ;
      RECT 52.405 577.990 52.475 578.200 ;
    END
  END w0_wmask_in[462]
  PIN w0_wmask_in[463]
    DIRECTION INPUT ;
    USE SIGNAL ;
    SHAPE ABUTMENT ;
    PORT
      LAYER metal2 ;
      RECT 52.785 577.990 52.855 578.200 ;
    END
  END w0_wmask_in[463]
  PIN w0_wmask_in[464]
    DIRECTION INPUT ;
    USE SIGNAL ;
    SHAPE ABUTMENT ;
    PORT
      LAYER metal2 ;
      RECT 53.165 577.990 53.235 578.200 ;
    END
  END w0_wmask_in[464]
  PIN w0_wmask_in[465]
    DIRECTION INPUT ;
    USE SIGNAL ;
    SHAPE ABUTMENT ;
    PORT
      LAYER metal2 ;
      RECT 53.545 577.990 53.615 578.200 ;
    END
  END w0_wmask_in[465]
  PIN w0_wmask_in[466]
    DIRECTION INPUT ;
    USE SIGNAL ;
    SHAPE ABUTMENT ;
    PORT
      LAYER metal2 ;
      RECT 53.925 577.990 53.995 578.200 ;
    END
  END w0_wmask_in[466]
  PIN w0_wmask_in[467]
    DIRECTION INPUT ;
    USE SIGNAL ;
    SHAPE ABUTMENT ;
    PORT
      LAYER metal2 ;
      RECT 54.305 577.990 54.375 578.200 ;
    END
  END w0_wmask_in[467]
  PIN w0_wmask_in[468]
    DIRECTION INPUT ;
    USE SIGNAL ;
    SHAPE ABUTMENT ;
    PORT
      LAYER metal2 ;
      RECT 54.685 577.990 54.755 578.200 ;
    END
  END w0_wmask_in[468]
  PIN w0_wmask_in[469]
    DIRECTION INPUT ;
    USE SIGNAL ;
    SHAPE ABUTMENT ;
    PORT
      LAYER metal2 ;
      RECT 55.065 577.990 55.135 578.200 ;
    END
  END w0_wmask_in[469]
  PIN w0_wmask_in[470]
    DIRECTION INPUT ;
    USE SIGNAL ;
    SHAPE ABUTMENT ;
    PORT
      LAYER metal2 ;
      RECT 55.445 577.990 55.515 578.200 ;
    END
  END w0_wmask_in[470]
  PIN w0_wmask_in[471]
    DIRECTION INPUT ;
    USE SIGNAL ;
    SHAPE ABUTMENT ;
    PORT
      LAYER metal2 ;
      RECT 55.825 577.990 55.895 578.200 ;
    END
  END w0_wmask_in[471]
  PIN w0_wmask_in[472]
    DIRECTION INPUT ;
    USE SIGNAL ;
    SHAPE ABUTMENT ;
    PORT
      LAYER metal2 ;
      RECT 56.205 577.990 56.275 578.200 ;
    END
  END w0_wmask_in[472]
  PIN w0_wmask_in[473]
    DIRECTION INPUT ;
    USE SIGNAL ;
    SHAPE ABUTMENT ;
    PORT
      LAYER metal2 ;
      RECT 56.585 577.990 56.655 578.200 ;
    END
  END w0_wmask_in[473]
  PIN w0_wmask_in[474]
    DIRECTION INPUT ;
    USE SIGNAL ;
    SHAPE ABUTMENT ;
    PORT
      LAYER metal2 ;
      RECT 56.965 577.990 57.035 578.200 ;
    END
  END w0_wmask_in[474]
  PIN w0_wmask_in[475]
    DIRECTION INPUT ;
    USE SIGNAL ;
    SHAPE ABUTMENT ;
    PORT
      LAYER metal2 ;
      RECT 57.345 577.990 57.415 578.200 ;
    END
  END w0_wmask_in[475]
  PIN w0_wmask_in[476]
    DIRECTION INPUT ;
    USE SIGNAL ;
    SHAPE ABUTMENT ;
    PORT
      LAYER metal2 ;
      RECT 57.725 577.990 57.795 578.200 ;
    END
  END w0_wmask_in[476]
  PIN w0_wmask_in[477]
    DIRECTION INPUT ;
    USE SIGNAL ;
    SHAPE ABUTMENT ;
    PORT
      LAYER metal2 ;
      RECT 58.105 577.990 58.175 578.200 ;
    END
  END w0_wmask_in[477]
  PIN w0_wmask_in[478]
    DIRECTION INPUT ;
    USE SIGNAL ;
    SHAPE ABUTMENT ;
    PORT
      LAYER metal2 ;
      RECT 58.485 577.990 58.555 578.200 ;
    END
  END w0_wmask_in[478]
  PIN w0_wmask_in[479]
    DIRECTION INPUT ;
    USE SIGNAL ;
    SHAPE ABUTMENT ;
    PORT
      LAYER metal2 ;
      RECT 58.865 577.990 58.935 578.200 ;
    END
  END w0_wmask_in[479]
  PIN w0_wmask_in[480]
    DIRECTION INPUT ;
    USE SIGNAL ;
    SHAPE ABUTMENT ;
    PORT
      LAYER metal2 ;
      RECT 59.245 577.990 59.315 578.200 ;
    END
  END w0_wmask_in[480]
  PIN w0_wmask_in[481]
    DIRECTION INPUT ;
    USE SIGNAL ;
    SHAPE ABUTMENT ;
    PORT
      LAYER metal2 ;
      RECT 59.625 577.990 59.695 578.200 ;
    END
  END w0_wmask_in[481]
  PIN w0_wmask_in[482]
    DIRECTION INPUT ;
    USE SIGNAL ;
    SHAPE ABUTMENT ;
    PORT
      LAYER metal2 ;
      RECT 60.005 577.990 60.075 578.200 ;
    END
  END w0_wmask_in[482]
  PIN w0_wmask_in[483]
    DIRECTION INPUT ;
    USE SIGNAL ;
    SHAPE ABUTMENT ;
    PORT
      LAYER metal2 ;
      RECT 60.385 577.990 60.455 578.200 ;
    END
  END w0_wmask_in[483]
  PIN w0_wmask_in[484]
    DIRECTION INPUT ;
    USE SIGNAL ;
    SHAPE ABUTMENT ;
    PORT
      LAYER metal2 ;
      RECT 60.765 577.990 60.835 578.200 ;
    END
  END w0_wmask_in[484]
  PIN w0_wmask_in[485]
    DIRECTION INPUT ;
    USE SIGNAL ;
    SHAPE ABUTMENT ;
    PORT
      LAYER metal2 ;
      RECT 61.145 577.990 61.215 578.200 ;
    END
  END w0_wmask_in[485]
  PIN w0_wmask_in[486]
    DIRECTION INPUT ;
    USE SIGNAL ;
    SHAPE ABUTMENT ;
    PORT
      LAYER metal2 ;
      RECT 61.525 577.990 61.595 578.200 ;
    END
  END w0_wmask_in[486]
  PIN w0_wmask_in[487]
    DIRECTION INPUT ;
    USE SIGNAL ;
    SHAPE ABUTMENT ;
    PORT
      LAYER metal2 ;
      RECT 61.905 577.990 61.975 578.200 ;
    END
  END w0_wmask_in[487]
  PIN w0_wmask_in[488]
    DIRECTION INPUT ;
    USE SIGNAL ;
    SHAPE ABUTMENT ;
    PORT
      LAYER metal2 ;
      RECT 62.285 577.990 62.355 578.200 ;
    END
  END w0_wmask_in[488]
  PIN w0_wmask_in[489]
    DIRECTION INPUT ;
    USE SIGNAL ;
    SHAPE ABUTMENT ;
    PORT
      LAYER metal2 ;
      RECT 62.665 577.990 62.735 578.200 ;
    END
  END w0_wmask_in[489]
  PIN w0_wmask_in[490]
    DIRECTION INPUT ;
    USE SIGNAL ;
    SHAPE ABUTMENT ;
    PORT
      LAYER metal2 ;
      RECT 63.045 577.990 63.115 578.200 ;
    END
  END w0_wmask_in[490]
  PIN w0_wmask_in[491]
    DIRECTION INPUT ;
    USE SIGNAL ;
    SHAPE ABUTMENT ;
    PORT
      LAYER metal2 ;
      RECT 63.425 577.990 63.495 578.200 ;
    END
  END w0_wmask_in[491]
  PIN w0_wmask_in[492]
    DIRECTION INPUT ;
    USE SIGNAL ;
    SHAPE ABUTMENT ;
    PORT
      LAYER metal2 ;
      RECT 63.805 577.990 63.875 578.200 ;
    END
  END w0_wmask_in[492]
  PIN w0_wmask_in[493]
    DIRECTION INPUT ;
    USE SIGNAL ;
    SHAPE ABUTMENT ;
    PORT
      LAYER metal2 ;
      RECT 64.185 577.990 64.255 578.200 ;
    END
  END w0_wmask_in[493]
  PIN w0_wmask_in[494]
    DIRECTION INPUT ;
    USE SIGNAL ;
    SHAPE ABUTMENT ;
    PORT
      LAYER metal2 ;
      RECT 64.565 577.990 64.635 578.200 ;
    END
  END w0_wmask_in[494]
  PIN w0_wmask_in[495]
    DIRECTION INPUT ;
    USE SIGNAL ;
    SHAPE ABUTMENT ;
    PORT
      LAYER metal2 ;
      RECT 64.945 577.990 65.015 578.200 ;
    END
  END w0_wmask_in[495]
  PIN w0_wmask_in[496]
    DIRECTION INPUT ;
    USE SIGNAL ;
    SHAPE ABUTMENT ;
    PORT
      LAYER metal2 ;
      RECT 65.325 577.990 65.395 578.200 ;
    END
  END w0_wmask_in[496]
  PIN w0_wmask_in[497]
    DIRECTION INPUT ;
    USE SIGNAL ;
    SHAPE ABUTMENT ;
    PORT
      LAYER metal2 ;
      RECT 65.705 577.990 65.775 578.200 ;
    END
  END w0_wmask_in[497]
  PIN w0_wmask_in[498]
    DIRECTION INPUT ;
    USE SIGNAL ;
    SHAPE ABUTMENT ;
    PORT
      LAYER metal2 ;
      RECT 66.085 577.990 66.155 578.200 ;
    END
  END w0_wmask_in[498]
  PIN w0_wmask_in[499]
    DIRECTION INPUT ;
    USE SIGNAL ;
    SHAPE ABUTMENT ;
    PORT
      LAYER metal2 ;
      RECT 66.465 577.990 66.535 578.200 ;
    END
  END w0_wmask_in[499]
  PIN w0_wmask_in[500]
    DIRECTION INPUT ;
    USE SIGNAL ;
    SHAPE ABUTMENT ;
    PORT
      LAYER metal2 ;
      RECT 66.845 577.990 66.915 578.200 ;
    END
  END w0_wmask_in[500]
  PIN w0_wmask_in[501]
    DIRECTION INPUT ;
    USE SIGNAL ;
    SHAPE ABUTMENT ;
    PORT
      LAYER metal2 ;
      RECT 67.225 577.990 67.295 578.200 ;
    END
  END w0_wmask_in[501]
  PIN w0_wmask_in[502]
    DIRECTION INPUT ;
    USE SIGNAL ;
    SHAPE ABUTMENT ;
    PORT
      LAYER metal2 ;
      RECT 67.605 577.990 67.675 578.200 ;
    END
  END w0_wmask_in[502]
  PIN w0_wmask_in[503]
    DIRECTION INPUT ;
    USE SIGNAL ;
    SHAPE ABUTMENT ;
    PORT
      LAYER metal2 ;
      RECT 67.985 577.990 68.055 578.200 ;
    END
  END w0_wmask_in[503]
  PIN w0_wmask_in[504]
    DIRECTION INPUT ;
    USE SIGNAL ;
    SHAPE ABUTMENT ;
    PORT
      LAYER metal2 ;
      RECT 68.365 577.990 68.435 578.200 ;
    END
  END w0_wmask_in[504]
  PIN w0_wmask_in[505]
    DIRECTION INPUT ;
    USE SIGNAL ;
    SHAPE ABUTMENT ;
    PORT
      LAYER metal2 ;
      RECT 68.745 577.990 68.815 578.200 ;
    END
  END w0_wmask_in[505]
  PIN w0_wmask_in[506]
    DIRECTION INPUT ;
    USE SIGNAL ;
    SHAPE ABUTMENT ;
    PORT
      LAYER metal2 ;
      RECT 69.125 577.990 69.195 578.200 ;
    END
  END w0_wmask_in[506]
  PIN w0_wmask_in[507]
    DIRECTION INPUT ;
    USE SIGNAL ;
    SHAPE ABUTMENT ;
    PORT
      LAYER metal2 ;
      RECT 69.505 577.990 69.575 578.200 ;
    END
  END w0_wmask_in[507]
  PIN w0_wmask_in[508]
    DIRECTION INPUT ;
    USE SIGNAL ;
    SHAPE ABUTMENT ;
    PORT
      LAYER metal2 ;
      RECT 69.885 577.990 69.955 578.200 ;
    END
  END w0_wmask_in[508]
  PIN w0_wmask_in[509]
    DIRECTION INPUT ;
    USE SIGNAL ;
    SHAPE ABUTMENT ;
    PORT
      LAYER metal2 ;
      RECT 70.265 577.990 70.335 578.200 ;
    END
  END w0_wmask_in[509]
  PIN w0_wmask_in[510]
    DIRECTION INPUT ;
    USE SIGNAL ;
    SHAPE ABUTMENT ;
    PORT
      LAYER metal2 ;
      RECT 70.645 577.990 70.715 578.200 ;
    END
  END w0_wmask_in[510]
  PIN w0_wmask_in[511]
    DIRECTION INPUT ;
    USE SIGNAL ;
    SHAPE ABUTMENT ;
    PORT
      LAYER metal2 ;
      RECT 71.025 577.990 71.095 578.200 ;
    END
  END w0_wmask_in[511]
  PIN w0_wmask_in[512]
    DIRECTION INPUT ;
    USE SIGNAL ;
    SHAPE ABUTMENT ;
    PORT
      LAYER metal2 ;
      RECT 71.405 577.990 71.475 578.200 ;
    END
  END w0_wmask_in[512]
  PIN w0_wmask_in[513]
    DIRECTION INPUT ;
    USE SIGNAL ;
    SHAPE ABUTMENT ;
    PORT
      LAYER metal2 ;
      RECT 71.785 577.990 71.855 578.200 ;
    END
  END w0_wmask_in[513]
  PIN w0_wmask_in[514]
    DIRECTION INPUT ;
    USE SIGNAL ;
    SHAPE ABUTMENT ;
    PORT
      LAYER metal2 ;
      RECT 72.165 577.990 72.235 578.200 ;
    END
  END w0_wmask_in[514]
  PIN w0_wmask_in[515]
    DIRECTION INPUT ;
    USE SIGNAL ;
    SHAPE ABUTMENT ;
    PORT
      LAYER metal2 ;
      RECT 72.545 577.990 72.615 578.200 ;
    END
  END w0_wmask_in[515]
  PIN w0_wmask_in[516]
    DIRECTION INPUT ;
    USE SIGNAL ;
    SHAPE ABUTMENT ;
    PORT
      LAYER metal2 ;
      RECT 72.925 577.990 72.995 578.200 ;
    END
  END w0_wmask_in[516]
  PIN w0_wmask_in[517]
    DIRECTION INPUT ;
    USE SIGNAL ;
    SHAPE ABUTMENT ;
    PORT
      LAYER metal2 ;
      RECT 73.305 577.990 73.375 578.200 ;
    END
  END w0_wmask_in[517]
  PIN w0_wmask_in[518]
    DIRECTION INPUT ;
    USE SIGNAL ;
    SHAPE ABUTMENT ;
    PORT
      LAYER metal2 ;
      RECT 73.685 577.990 73.755 578.200 ;
    END
  END w0_wmask_in[518]
  PIN w0_wmask_in[519]
    DIRECTION INPUT ;
    USE SIGNAL ;
    SHAPE ABUTMENT ;
    PORT
      LAYER metal2 ;
      RECT 74.065 577.990 74.135 578.200 ;
    END
  END w0_wmask_in[519]
  PIN w0_wmask_in[520]
    DIRECTION INPUT ;
    USE SIGNAL ;
    SHAPE ABUTMENT ;
    PORT
      LAYER metal2 ;
      RECT 74.445 577.990 74.515 578.200 ;
    END
  END w0_wmask_in[520]
  PIN w0_wmask_in[521]
    DIRECTION INPUT ;
    USE SIGNAL ;
    SHAPE ABUTMENT ;
    PORT
      LAYER metal2 ;
      RECT 74.825 577.990 74.895 578.200 ;
    END
  END w0_wmask_in[521]
  PIN w0_wmask_in[522]
    DIRECTION INPUT ;
    USE SIGNAL ;
    SHAPE ABUTMENT ;
    PORT
      LAYER metal2 ;
      RECT 75.205 577.990 75.275 578.200 ;
    END
  END w0_wmask_in[522]
  PIN w0_wmask_in[523]
    DIRECTION INPUT ;
    USE SIGNAL ;
    SHAPE ABUTMENT ;
    PORT
      LAYER metal2 ;
      RECT 75.585 577.990 75.655 578.200 ;
    END
  END w0_wmask_in[523]
  PIN w0_wmask_in[524]
    DIRECTION INPUT ;
    USE SIGNAL ;
    SHAPE ABUTMENT ;
    PORT
      LAYER metal2 ;
      RECT 75.965 577.990 76.035 578.200 ;
    END
  END w0_wmask_in[524]
  PIN w0_wmask_in[525]
    DIRECTION INPUT ;
    USE SIGNAL ;
    SHAPE ABUTMENT ;
    PORT
      LAYER metal2 ;
      RECT 76.345 577.990 76.415 578.200 ;
    END
  END w0_wmask_in[525]
  PIN w0_wmask_in[526]
    DIRECTION INPUT ;
    USE SIGNAL ;
    SHAPE ABUTMENT ;
    PORT
      LAYER metal2 ;
      RECT 76.725 577.990 76.795 578.200 ;
    END
  END w0_wmask_in[526]
  PIN w0_wmask_in[527]
    DIRECTION INPUT ;
    USE SIGNAL ;
    SHAPE ABUTMENT ;
    PORT
      LAYER metal2 ;
      RECT 77.105 577.990 77.175 578.200 ;
    END
  END w0_wmask_in[527]
  PIN w0_wmask_in[528]
    DIRECTION INPUT ;
    USE SIGNAL ;
    SHAPE ABUTMENT ;
    PORT
      LAYER metal2 ;
      RECT 77.485 577.990 77.555 578.200 ;
    END
  END w0_wmask_in[528]
  PIN w0_wmask_in[529]
    DIRECTION INPUT ;
    USE SIGNAL ;
    SHAPE ABUTMENT ;
    PORT
      LAYER metal2 ;
      RECT 77.865 577.990 77.935 578.200 ;
    END
  END w0_wmask_in[529]
  PIN w0_wmask_in[530]
    DIRECTION INPUT ;
    USE SIGNAL ;
    SHAPE ABUTMENT ;
    PORT
      LAYER metal2 ;
      RECT 78.245 577.990 78.315 578.200 ;
    END
  END w0_wmask_in[530]
  PIN w0_wmask_in[531]
    DIRECTION INPUT ;
    USE SIGNAL ;
    SHAPE ABUTMENT ;
    PORT
      LAYER metal2 ;
      RECT 78.625 577.990 78.695 578.200 ;
    END
  END w0_wmask_in[531]
  PIN w0_wmask_in[532]
    DIRECTION INPUT ;
    USE SIGNAL ;
    SHAPE ABUTMENT ;
    PORT
      LAYER metal2 ;
      RECT 79.005 577.990 79.075 578.200 ;
    END
  END w0_wmask_in[532]
  PIN w0_wmask_in[533]
    DIRECTION INPUT ;
    USE SIGNAL ;
    SHAPE ABUTMENT ;
    PORT
      LAYER metal2 ;
      RECT 79.385 577.990 79.455 578.200 ;
    END
  END w0_wmask_in[533]
  PIN w0_wmask_in[534]
    DIRECTION INPUT ;
    USE SIGNAL ;
    SHAPE ABUTMENT ;
    PORT
      LAYER metal2 ;
      RECT 79.765 577.990 79.835 578.200 ;
    END
  END w0_wmask_in[534]
  PIN w0_wmask_in[535]
    DIRECTION INPUT ;
    USE SIGNAL ;
    SHAPE ABUTMENT ;
    PORT
      LAYER metal2 ;
      RECT 80.145 577.990 80.215 578.200 ;
    END
  END w0_wmask_in[535]
  PIN w0_wmask_in[536]
    DIRECTION INPUT ;
    USE SIGNAL ;
    SHAPE ABUTMENT ;
    PORT
      LAYER metal2 ;
      RECT 80.525 577.990 80.595 578.200 ;
    END
  END w0_wmask_in[536]
  PIN w0_wmask_in[537]
    DIRECTION INPUT ;
    USE SIGNAL ;
    SHAPE ABUTMENT ;
    PORT
      LAYER metal2 ;
      RECT 80.905 577.990 80.975 578.200 ;
    END
  END w0_wmask_in[537]
  PIN w0_wmask_in[538]
    DIRECTION INPUT ;
    USE SIGNAL ;
    SHAPE ABUTMENT ;
    PORT
      LAYER metal2 ;
      RECT 81.285 577.990 81.355 578.200 ;
    END
  END w0_wmask_in[538]
  PIN w0_wmask_in[539]
    DIRECTION INPUT ;
    USE SIGNAL ;
    SHAPE ABUTMENT ;
    PORT
      LAYER metal2 ;
      RECT 81.665 577.990 81.735 578.200 ;
    END
  END w0_wmask_in[539]
  PIN w0_wmask_in[540]
    DIRECTION INPUT ;
    USE SIGNAL ;
    SHAPE ABUTMENT ;
    PORT
      LAYER metal2 ;
      RECT 82.045 577.990 82.115 578.200 ;
    END
  END w0_wmask_in[540]
  PIN w0_wmask_in[541]
    DIRECTION INPUT ;
    USE SIGNAL ;
    SHAPE ABUTMENT ;
    PORT
      LAYER metal2 ;
      RECT 82.425 577.990 82.495 578.200 ;
    END
  END w0_wmask_in[541]
  PIN w0_wmask_in[542]
    DIRECTION INPUT ;
    USE SIGNAL ;
    SHAPE ABUTMENT ;
    PORT
      LAYER metal2 ;
      RECT 82.805 577.990 82.875 578.200 ;
    END
  END w0_wmask_in[542]
  PIN w0_wmask_in[543]
    DIRECTION INPUT ;
    USE SIGNAL ;
    SHAPE ABUTMENT ;
    PORT
      LAYER metal2 ;
      RECT 83.185 577.990 83.255 578.200 ;
    END
  END w0_wmask_in[543]
  PIN w0_wmask_in[544]
    DIRECTION INPUT ;
    USE SIGNAL ;
    SHAPE ABUTMENT ;
    PORT
      LAYER metal2 ;
      RECT 83.565 577.990 83.635 578.200 ;
    END
  END w0_wmask_in[544]
  PIN w0_wmask_in[545]
    DIRECTION INPUT ;
    USE SIGNAL ;
    SHAPE ABUTMENT ;
    PORT
      LAYER metal2 ;
      RECT 83.945 577.990 84.015 578.200 ;
    END
  END w0_wmask_in[545]
  PIN w0_wmask_in[546]
    DIRECTION INPUT ;
    USE SIGNAL ;
    SHAPE ABUTMENT ;
    PORT
      LAYER metal2 ;
      RECT 84.325 577.990 84.395 578.200 ;
    END
  END w0_wmask_in[546]
  PIN w0_wmask_in[547]
    DIRECTION INPUT ;
    USE SIGNAL ;
    SHAPE ABUTMENT ;
    PORT
      LAYER metal2 ;
      RECT 84.705 577.990 84.775 578.200 ;
    END
  END w0_wmask_in[547]
  PIN w0_wmask_in[548]
    DIRECTION INPUT ;
    USE SIGNAL ;
    SHAPE ABUTMENT ;
    PORT
      LAYER metal2 ;
      RECT 85.085 577.990 85.155 578.200 ;
    END
  END w0_wmask_in[548]
  PIN w0_wmask_in[549]
    DIRECTION INPUT ;
    USE SIGNAL ;
    SHAPE ABUTMENT ;
    PORT
      LAYER metal2 ;
      RECT 85.465 577.990 85.535 578.200 ;
    END
  END w0_wmask_in[549]
  PIN w0_wmask_in[550]
    DIRECTION INPUT ;
    USE SIGNAL ;
    SHAPE ABUTMENT ;
    PORT
      LAYER metal2 ;
      RECT 85.845 577.990 85.915 578.200 ;
    END
  END w0_wmask_in[550]
  PIN w0_wmask_in[551]
    DIRECTION INPUT ;
    USE SIGNAL ;
    SHAPE ABUTMENT ;
    PORT
      LAYER metal2 ;
      RECT 86.225 577.990 86.295 578.200 ;
    END
  END w0_wmask_in[551]
  PIN w0_wmask_in[552]
    DIRECTION INPUT ;
    USE SIGNAL ;
    SHAPE ABUTMENT ;
    PORT
      LAYER metal2 ;
      RECT 86.605 577.990 86.675 578.200 ;
    END
  END w0_wmask_in[552]
  PIN w0_wmask_in[553]
    DIRECTION INPUT ;
    USE SIGNAL ;
    SHAPE ABUTMENT ;
    PORT
      LAYER metal2 ;
      RECT 86.985 577.990 87.055 578.200 ;
    END
  END w0_wmask_in[553]
  PIN w0_wmask_in[554]
    DIRECTION INPUT ;
    USE SIGNAL ;
    SHAPE ABUTMENT ;
    PORT
      LAYER metal2 ;
      RECT 87.365 577.990 87.435 578.200 ;
    END
  END w0_wmask_in[554]
  PIN w0_wmask_in[555]
    DIRECTION INPUT ;
    USE SIGNAL ;
    SHAPE ABUTMENT ;
    PORT
      LAYER metal2 ;
      RECT 87.745 577.990 87.815 578.200 ;
    END
  END w0_wmask_in[555]
  PIN w0_wmask_in[556]
    DIRECTION INPUT ;
    USE SIGNAL ;
    SHAPE ABUTMENT ;
    PORT
      LAYER metal2 ;
      RECT 88.125 577.990 88.195 578.200 ;
    END
  END w0_wmask_in[556]
  PIN w0_wmask_in[557]
    DIRECTION INPUT ;
    USE SIGNAL ;
    SHAPE ABUTMENT ;
    PORT
      LAYER metal2 ;
      RECT 88.505 577.990 88.575 578.200 ;
    END
  END w0_wmask_in[557]
  PIN w0_wmask_in[558]
    DIRECTION INPUT ;
    USE SIGNAL ;
    SHAPE ABUTMENT ;
    PORT
      LAYER metal2 ;
      RECT 88.885 577.990 88.955 578.200 ;
    END
  END w0_wmask_in[558]
  PIN w0_wmask_in[559]
    DIRECTION INPUT ;
    USE SIGNAL ;
    SHAPE ABUTMENT ;
    PORT
      LAYER metal2 ;
      RECT 89.265 577.990 89.335 578.200 ;
    END
  END w0_wmask_in[559]
  PIN w0_wmask_in[560]
    DIRECTION INPUT ;
    USE SIGNAL ;
    SHAPE ABUTMENT ;
    PORT
      LAYER metal2 ;
      RECT 89.645 577.990 89.715 578.200 ;
    END
  END w0_wmask_in[560]
  PIN w0_wmask_in[561]
    DIRECTION INPUT ;
    USE SIGNAL ;
    SHAPE ABUTMENT ;
    PORT
      LAYER metal2 ;
      RECT 90.025 577.990 90.095 578.200 ;
    END
  END w0_wmask_in[561]
  PIN w0_wmask_in[562]
    DIRECTION INPUT ;
    USE SIGNAL ;
    SHAPE ABUTMENT ;
    PORT
      LAYER metal2 ;
      RECT 90.405 577.990 90.475 578.200 ;
    END
  END w0_wmask_in[562]
  PIN w0_wmask_in[563]
    DIRECTION INPUT ;
    USE SIGNAL ;
    SHAPE ABUTMENT ;
    PORT
      LAYER metal2 ;
      RECT 90.785 577.990 90.855 578.200 ;
    END
  END w0_wmask_in[563]
  PIN w0_wmask_in[564]
    DIRECTION INPUT ;
    USE SIGNAL ;
    SHAPE ABUTMENT ;
    PORT
      LAYER metal2 ;
      RECT 91.165 577.990 91.235 578.200 ;
    END
  END w0_wmask_in[564]
  PIN w0_wmask_in[565]
    DIRECTION INPUT ;
    USE SIGNAL ;
    SHAPE ABUTMENT ;
    PORT
      LAYER metal2 ;
      RECT 91.545 577.990 91.615 578.200 ;
    END
  END w0_wmask_in[565]
  PIN w0_wmask_in[566]
    DIRECTION INPUT ;
    USE SIGNAL ;
    SHAPE ABUTMENT ;
    PORT
      LAYER metal2 ;
      RECT 91.925 577.990 91.995 578.200 ;
    END
  END w0_wmask_in[566]
  PIN w0_wmask_in[567]
    DIRECTION INPUT ;
    USE SIGNAL ;
    SHAPE ABUTMENT ;
    PORT
      LAYER metal2 ;
      RECT 92.305 577.990 92.375 578.200 ;
    END
  END w0_wmask_in[567]
  PIN w0_wmask_in[568]
    DIRECTION INPUT ;
    USE SIGNAL ;
    SHAPE ABUTMENT ;
    PORT
      LAYER metal2 ;
      RECT 92.685 577.990 92.755 578.200 ;
    END
  END w0_wmask_in[568]
  PIN w0_wmask_in[569]
    DIRECTION INPUT ;
    USE SIGNAL ;
    SHAPE ABUTMENT ;
    PORT
      LAYER metal2 ;
      RECT 93.065 577.990 93.135 578.200 ;
    END
  END w0_wmask_in[569]
  PIN w0_wmask_in[570]
    DIRECTION INPUT ;
    USE SIGNAL ;
    SHAPE ABUTMENT ;
    PORT
      LAYER metal2 ;
      RECT 93.445 577.990 93.515 578.200 ;
    END
  END w0_wmask_in[570]
  PIN w0_wmask_in[571]
    DIRECTION INPUT ;
    USE SIGNAL ;
    SHAPE ABUTMENT ;
    PORT
      LAYER metal2 ;
      RECT 93.825 577.990 93.895 578.200 ;
    END
  END w0_wmask_in[571]
  PIN w0_wmask_in[572]
    DIRECTION INPUT ;
    USE SIGNAL ;
    SHAPE ABUTMENT ;
    PORT
      LAYER metal2 ;
      RECT 94.205 577.990 94.275 578.200 ;
    END
  END w0_wmask_in[572]
  PIN w0_wmask_in[573]
    DIRECTION INPUT ;
    USE SIGNAL ;
    SHAPE ABUTMENT ;
    PORT
      LAYER metal2 ;
      RECT 94.585 577.990 94.655 578.200 ;
    END
  END w0_wmask_in[573]
  PIN w0_wmask_in[574]
    DIRECTION INPUT ;
    USE SIGNAL ;
    SHAPE ABUTMENT ;
    PORT
      LAYER metal2 ;
      RECT 94.965 577.990 95.035 578.200 ;
    END
  END w0_wmask_in[574]
  PIN w0_wmask_in[575]
    DIRECTION INPUT ;
    USE SIGNAL ;
    SHAPE ABUTMENT ;
    PORT
      LAYER metal2 ;
      RECT 95.345 577.990 95.415 578.200 ;
    END
  END w0_wmask_in[575]
  PIN w0_wmask_in[576]
    DIRECTION INPUT ;
    USE SIGNAL ;
    SHAPE ABUTMENT ;
    PORT
      LAYER metal2 ;
      RECT 95.725 577.990 95.795 578.200 ;
    END
  END w0_wmask_in[576]
  PIN w0_wmask_in[577]
    DIRECTION INPUT ;
    USE SIGNAL ;
    SHAPE ABUTMENT ;
    PORT
      LAYER metal2 ;
      RECT 96.105 577.990 96.175 578.200 ;
    END
  END w0_wmask_in[577]
  PIN w0_wmask_in[578]
    DIRECTION INPUT ;
    USE SIGNAL ;
    SHAPE ABUTMENT ;
    PORT
      LAYER metal2 ;
      RECT 96.485 577.990 96.555 578.200 ;
    END
  END w0_wmask_in[578]
  PIN w0_wmask_in[579]
    DIRECTION INPUT ;
    USE SIGNAL ;
    SHAPE ABUTMENT ;
    PORT
      LAYER metal2 ;
      RECT 96.865 577.990 96.935 578.200 ;
    END
  END w0_wmask_in[579]
  PIN w0_wmask_in[580]
    DIRECTION INPUT ;
    USE SIGNAL ;
    SHAPE ABUTMENT ;
    PORT
      LAYER metal2 ;
      RECT 97.245 577.990 97.315 578.200 ;
    END
  END w0_wmask_in[580]
  PIN w0_wmask_in[581]
    DIRECTION INPUT ;
    USE SIGNAL ;
    SHAPE ABUTMENT ;
    PORT
      LAYER metal2 ;
      RECT 97.625 577.990 97.695 578.200 ;
    END
  END w0_wmask_in[581]
  PIN w0_wmask_in[582]
    DIRECTION INPUT ;
    USE SIGNAL ;
    SHAPE ABUTMENT ;
    PORT
      LAYER metal2 ;
      RECT 98.005 577.990 98.075 578.200 ;
    END
  END w0_wmask_in[582]
  PIN w0_wmask_in[583]
    DIRECTION INPUT ;
    USE SIGNAL ;
    SHAPE ABUTMENT ;
    PORT
      LAYER metal2 ;
      RECT 98.385 577.990 98.455 578.200 ;
    END
  END w0_wmask_in[583]
  PIN w0_wmask_in[584]
    DIRECTION INPUT ;
    USE SIGNAL ;
    SHAPE ABUTMENT ;
    PORT
      LAYER metal2 ;
      RECT 98.765 577.990 98.835 578.200 ;
    END
  END w0_wmask_in[584]
  PIN w0_wmask_in[585]
    DIRECTION INPUT ;
    USE SIGNAL ;
    SHAPE ABUTMENT ;
    PORT
      LAYER metal2 ;
      RECT 99.145 577.990 99.215 578.200 ;
    END
  END w0_wmask_in[585]
  PIN w0_wmask_in[586]
    DIRECTION INPUT ;
    USE SIGNAL ;
    SHAPE ABUTMENT ;
    PORT
      LAYER metal2 ;
      RECT 99.525 577.990 99.595 578.200 ;
    END
  END w0_wmask_in[586]
  PIN w0_wmask_in[587]
    DIRECTION INPUT ;
    USE SIGNAL ;
    SHAPE ABUTMENT ;
    PORT
      LAYER metal2 ;
      RECT 99.905 577.990 99.975 578.200 ;
    END
  END w0_wmask_in[587]
  PIN w0_wmask_in[588]
    DIRECTION INPUT ;
    USE SIGNAL ;
    SHAPE ABUTMENT ;
    PORT
      LAYER metal2 ;
      RECT 100.285 577.990 100.355 578.200 ;
    END
  END w0_wmask_in[588]
  PIN w0_wmask_in[589]
    DIRECTION INPUT ;
    USE SIGNAL ;
    SHAPE ABUTMENT ;
    PORT
      LAYER metal2 ;
      RECT 100.665 577.990 100.735 578.200 ;
    END
  END w0_wmask_in[589]
  PIN w0_wmask_in[590]
    DIRECTION INPUT ;
    USE SIGNAL ;
    SHAPE ABUTMENT ;
    PORT
      LAYER metal2 ;
      RECT 101.045 577.990 101.115 578.200 ;
    END
  END w0_wmask_in[590]
  PIN w0_wmask_in[591]
    DIRECTION INPUT ;
    USE SIGNAL ;
    SHAPE ABUTMENT ;
    PORT
      LAYER metal2 ;
      RECT 101.425 577.990 101.495 578.200 ;
    END
  END w0_wmask_in[591]
  PIN w0_wmask_in[592]
    DIRECTION INPUT ;
    USE SIGNAL ;
    SHAPE ABUTMENT ;
    PORT
      LAYER metal2 ;
      RECT 101.805 577.990 101.875 578.200 ;
    END
  END w0_wmask_in[592]
  PIN w0_wmask_in[593]
    DIRECTION INPUT ;
    USE SIGNAL ;
    SHAPE ABUTMENT ;
    PORT
      LAYER metal2 ;
      RECT 102.185 577.990 102.255 578.200 ;
    END
  END w0_wmask_in[593]
  PIN w0_wmask_in[594]
    DIRECTION INPUT ;
    USE SIGNAL ;
    SHAPE ABUTMENT ;
    PORT
      LAYER metal2 ;
      RECT 102.565 577.990 102.635 578.200 ;
    END
  END w0_wmask_in[594]
  PIN w0_wmask_in[595]
    DIRECTION INPUT ;
    USE SIGNAL ;
    SHAPE ABUTMENT ;
    PORT
      LAYER metal2 ;
      RECT 102.945 577.990 103.015 578.200 ;
    END
  END w0_wmask_in[595]
  PIN w0_wmask_in[596]
    DIRECTION INPUT ;
    USE SIGNAL ;
    SHAPE ABUTMENT ;
    PORT
      LAYER metal2 ;
      RECT 103.325 577.990 103.395 578.200 ;
    END
  END w0_wmask_in[596]
  PIN w0_wmask_in[597]
    DIRECTION INPUT ;
    USE SIGNAL ;
    SHAPE ABUTMENT ;
    PORT
      LAYER metal2 ;
      RECT 103.705 577.990 103.775 578.200 ;
    END
  END w0_wmask_in[597]
  PIN w0_wmask_in[598]
    DIRECTION INPUT ;
    USE SIGNAL ;
    SHAPE ABUTMENT ;
    PORT
      LAYER metal2 ;
      RECT 104.085 577.990 104.155 578.200 ;
    END
  END w0_wmask_in[598]
  PIN w0_wmask_in[599]
    DIRECTION INPUT ;
    USE SIGNAL ;
    SHAPE ABUTMENT ;
    PORT
      LAYER metal2 ;
      RECT 104.465 577.990 104.535 578.200 ;
    END
  END w0_wmask_in[599]
  PIN w0_wmask_in[600]
    DIRECTION INPUT ;
    USE SIGNAL ;
    SHAPE ABUTMENT ;
    PORT
      LAYER metal2 ;
      RECT 104.845 577.990 104.915 578.200 ;
    END
  END w0_wmask_in[600]
  PIN w0_wmask_in[601]
    DIRECTION INPUT ;
    USE SIGNAL ;
    SHAPE ABUTMENT ;
    PORT
      LAYER metal2 ;
      RECT 105.225 577.990 105.295 578.200 ;
    END
  END w0_wmask_in[601]
  PIN w0_wmask_in[602]
    DIRECTION INPUT ;
    USE SIGNAL ;
    SHAPE ABUTMENT ;
    PORT
      LAYER metal2 ;
      RECT 105.605 577.990 105.675 578.200 ;
    END
  END w0_wmask_in[602]
  PIN w0_wmask_in[603]
    DIRECTION INPUT ;
    USE SIGNAL ;
    SHAPE ABUTMENT ;
    PORT
      LAYER metal2 ;
      RECT 105.985 577.990 106.055 578.200 ;
    END
  END w0_wmask_in[603]
  PIN w0_wmask_in[604]
    DIRECTION INPUT ;
    USE SIGNAL ;
    SHAPE ABUTMENT ;
    PORT
      LAYER metal2 ;
      RECT 106.365 577.990 106.435 578.200 ;
    END
  END w0_wmask_in[604]
  PIN w0_wmask_in[605]
    DIRECTION INPUT ;
    USE SIGNAL ;
    SHAPE ABUTMENT ;
    PORT
      LAYER metal2 ;
      RECT 106.745 577.990 106.815 578.200 ;
    END
  END w0_wmask_in[605]
  PIN w0_wmask_in[606]
    DIRECTION INPUT ;
    USE SIGNAL ;
    SHAPE ABUTMENT ;
    PORT
      LAYER metal2 ;
      RECT 107.125 577.990 107.195 578.200 ;
    END
  END w0_wmask_in[606]
  PIN w0_wmask_in[607]
    DIRECTION INPUT ;
    USE SIGNAL ;
    SHAPE ABUTMENT ;
    PORT
      LAYER metal2 ;
      RECT 107.505 577.990 107.575 578.200 ;
    END
  END w0_wmask_in[607]
  PIN w0_wmask_in[608]
    DIRECTION INPUT ;
    USE SIGNAL ;
    SHAPE ABUTMENT ;
    PORT
      LAYER metal2 ;
      RECT 107.885 577.990 107.955 578.200 ;
    END
  END w0_wmask_in[608]
  PIN w0_wmask_in[609]
    DIRECTION INPUT ;
    USE SIGNAL ;
    SHAPE ABUTMENT ;
    PORT
      LAYER metal2 ;
      RECT 108.265 577.990 108.335 578.200 ;
    END
  END w0_wmask_in[609]
  PIN w0_wmask_in[610]
    DIRECTION INPUT ;
    USE SIGNAL ;
    SHAPE ABUTMENT ;
    PORT
      LAYER metal2 ;
      RECT 108.645 577.990 108.715 578.200 ;
    END
  END w0_wmask_in[610]
  PIN w0_wmask_in[611]
    DIRECTION INPUT ;
    USE SIGNAL ;
    SHAPE ABUTMENT ;
    PORT
      LAYER metal2 ;
      RECT 109.025 577.990 109.095 578.200 ;
    END
  END w0_wmask_in[611]
  PIN w0_wmask_in[612]
    DIRECTION INPUT ;
    USE SIGNAL ;
    SHAPE ABUTMENT ;
    PORT
      LAYER metal2 ;
      RECT 109.405 577.990 109.475 578.200 ;
    END
  END w0_wmask_in[612]
  PIN w0_wmask_in[613]
    DIRECTION INPUT ;
    USE SIGNAL ;
    SHAPE ABUTMENT ;
    PORT
      LAYER metal2 ;
      RECT 109.785 577.990 109.855 578.200 ;
    END
  END w0_wmask_in[613]
  PIN w0_wmask_in[614]
    DIRECTION INPUT ;
    USE SIGNAL ;
    SHAPE ABUTMENT ;
    PORT
      LAYER metal2 ;
      RECT 110.165 577.990 110.235 578.200 ;
    END
  END w0_wmask_in[614]
  PIN w0_wmask_in[615]
    DIRECTION INPUT ;
    USE SIGNAL ;
    SHAPE ABUTMENT ;
    PORT
      LAYER metal2 ;
      RECT 110.545 577.990 110.615 578.200 ;
    END
  END w0_wmask_in[615]
  PIN w0_wmask_in[616]
    DIRECTION INPUT ;
    USE SIGNAL ;
    SHAPE ABUTMENT ;
    PORT
      LAYER metal2 ;
      RECT 110.925 577.990 110.995 578.200 ;
    END
  END w0_wmask_in[616]
  PIN w0_wmask_in[617]
    DIRECTION INPUT ;
    USE SIGNAL ;
    SHAPE ABUTMENT ;
    PORT
      LAYER metal2 ;
      RECT 111.305 577.990 111.375 578.200 ;
    END
  END w0_wmask_in[617]
  PIN w0_wmask_in[618]
    DIRECTION INPUT ;
    USE SIGNAL ;
    SHAPE ABUTMENT ;
    PORT
      LAYER metal2 ;
      RECT 111.685 577.990 111.755 578.200 ;
    END
  END w0_wmask_in[618]
  PIN w0_wmask_in[619]
    DIRECTION INPUT ;
    USE SIGNAL ;
    SHAPE ABUTMENT ;
    PORT
      LAYER metal2 ;
      RECT 112.065 577.990 112.135 578.200 ;
    END
  END w0_wmask_in[619]
  PIN w0_wmask_in[620]
    DIRECTION INPUT ;
    USE SIGNAL ;
    SHAPE ABUTMENT ;
    PORT
      LAYER metal2 ;
      RECT 112.445 577.990 112.515 578.200 ;
    END
  END w0_wmask_in[620]
  PIN w0_wmask_in[621]
    DIRECTION INPUT ;
    USE SIGNAL ;
    SHAPE ABUTMENT ;
    PORT
      LAYER metal2 ;
      RECT 112.825 577.990 112.895 578.200 ;
    END
  END w0_wmask_in[621]
  PIN w0_wmask_in[622]
    DIRECTION INPUT ;
    USE SIGNAL ;
    SHAPE ABUTMENT ;
    PORT
      LAYER metal2 ;
      RECT 113.205 577.990 113.275 578.200 ;
    END
  END w0_wmask_in[622]
  PIN w0_wmask_in[623]
    DIRECTION INPUT ;
    USE SIGNAL ;
    SHAPE ABUTMENT ;
    PORT
      LAYER metal2 ;
      RECT 113.585 577.990 113.655 578.200 ;
    END
  END w0_wmask_in[623]
  PIN w0_wmask_in[624]
    DIRECTION INPUT ;
    USE SIGNAL ;
    SHAPE ABUTMENT ;
    PORT
      LAYER metal2 ;
      RECT 113.965 577.990 114.035 578.200 ;
    END
  END w0_wmask_in[624]
  PIN w0_wmask_in[625]
    DIRECTION INPUT ;
    USE SIGNAL ;
    SHAPE ABUTMENT ;
    PORT
      LAYER metal2 ;
      RECT 114.345 577.990 114.415 578.200 ;
    END
  END w0_wmask_in[625]
  PIN w0_wmask_in[626]
    DIRECTION INPUT ;
    USE SIGNAL ;
    SHAPE ABUTMENT ;
    PORT
      LAYER metal2 ;
      RECT 114.725 577.990 114.795 578.200 ;
    END
  END w0_wmask_in[626]
  PIN w0_wmask_in[627]
    DIRECTION INPUT ;
    USE SIGNAL ;
    SHAPE ABUTMENT ;
    PORT
      LAYER metal2 ;
      RECT 115.105 577.990 115.175 578.200 ;
    END
  END w0_wmask_in[627]
  PIN w0_wmask_in[628]
    DIRECTION INPUT ;
    USE SIGNAL ;
    SHAPE ABUTMENT ;
    PORT
      LAYER metal2 ;
      RECT 115.485 577.990 115.555 578.200 ;
    END
  END w0_wmask_in[628]
  PIN w0_wmask_in[629]
    DIRECTION INPUT ;
    USE SIGNAL ;
    SHAPE ABUTMENT ;
    PORT
      LAYER metal2 ;
      RECT 115.865 577.990 115.935 578.200 ;
    END
  END w0_wmask_in[629]
  PIN w0_wmask_in[630]
    DIRECTION INPUT ;
    USE SIGNAL ;
    SHAPE ABUTMENT ;
    PORT
      LAYER metal2 ;
      RECT 116.245 577.990 116.315 578.200 ;
    END
  END w0_wmask_in[630]
  PIN w0_wmask_in[631]
    DIRECTION INPUT ;
    USE SIGNAL ;
    SHAPE ABUTMENT ;
    PORT
      LAYER metal2 ;
      RECT 116.625 577.990 116.695 578.200 ;
    END
  END w0_wmask_in[631]
  PIN w0_wmask_in[632]
    DIRECTION INPUT ;
    USE SIGNAL ;
    SHAPE ABUTMENT ;
    PORT
      LAYER metal2 ;
      RECT 117.005 577.990 117.075 578.200 ;
    END
  END w0_wmask_in[632]
  PIN w0_wmask_in[633]
    DIRECTION INPUT ;
    USE SIGNAL ;
    SHAPE ABUTMENT ;
    PORT
      LAYER metal2 ;
      RECT 117.385 577.990 117.455 578.200 ;
    END
  END w0_wmask_in[633]
  PIN w0_wmask_in[634]
    DIRECTION INPUT ;
    USE SIGNAL ;
    SHAPE ABUTMENT ;
    PORT
      LAYER metal2 ;
      RECT 117.765 577.990 117.835 578.200 ;
    END
  END w0_wmask_in[634]
  PIN w0_wmask_in[635]
    DIRECTION INPUT ;
    USE SIGNAL ;
    SHAPE ABUTMENT ;
    PORT
      LAYER metal2 ;
      RECT 118.145 577.990 118.215 578.200 ;
    END
  END w0_wmask_in[635]
  PIN w0_wmask_in[636]
    DIRECTION INPUT ;
    USE SIGNAL ;
    SHAPE ABUTMENT ;
    PORT
      LAYER metal2 ;
      RECT 118.525 577.990 118.595 578.200 ;
    END
  END w0_wmask_in[636]
  PIN w0_wmask_in[637]
    DIRECTION INPUT ;
    USE SIGNAL ;
    SHAPE ABUTMENT ;
    PORT
      LAYER metal2 ;
      RECT 118.905 577.990 118.975 578.200 ;
    END
  END w0_wmask_in[637]
  PIN w0_wmask_in[638]
    DIRECTION INPUT ;
    USE SIGNAL ;
    SHAPE ABUTMENT ;
    PORT
      LAYER metal2 ;
      RECT 119.285 577.990 119.355 578.200 ;
    END
  END w0_wmask_in[638]
  PIN w0_wmask_in[639]
    DIRECTION INPUT ;
    USE SIGNAL ;
    SHAPE ABUTMENT ;
    PORT
      LAYER metal2 ;
      RECT 119.665 577.990 119.735 578.200 ;
    END
  END w0_wmask_in[639]
  PIN w0_wmask_in[640]
    DIRECTION INPUT ;
    USE SIGNAL ;
    SHAPE ABUTMENT ;
    PORT
      LAYER metal2 ;
      RECT 120.045 577.990 120.115 578.200 ;
    END
  END w0_wmask_in[640]
  PIN w0_wmask_in[641]
    DIRECTION INPUT ;
    USE SIGNAL ;
    SHAPE ABUTMENT ;
    PORT
      LAYER metal2 ;
      RECT 120.425 577.990 120.495 578.200 ;
    END
  END w0_wmask_in[641]
  PIN w0_wmask_in[642]
    DIRECTION INPUT ;
    USE SIGNAL ;
    SHAPE ABUTMENT ;
    PORT
      LAYER metal2 ;
      RECT 120.805 577.990 120.875 578.200 ;
    END
  END w0_wmask_in[642]
  PIN w0_wmask_in[643]
    DIRECTION INPUT ;
    USE SIGNAL ;
    SHAPE ABUTMENT ;
    PORT
      LAYER metal2 ;
      RECT 121.185 577.990 121.255 578.200 ;
    END
  END w0_wmask_in[643]
  PIN w0_wmask_in[644]
    DIRECTION INPUT ;
    USE SIGNAL ;
    SHAPE ABUTMENT ;
    PORT
      LAYER metal2 ;
      RECT 121.565 577.990 121.635 578.200 ;
    END
  END w0_wmask_in[644]
  PIN w0_wmask_in[645]
    DIRECTION INPUT ;
    USE SIGNAL ;
    SHAPE ABUTMENT ;
    PORT
      LAYER metal2 ;
      RECT 121.945 577.990 122.015 578.200 ;
    END
  END w0_wmask_in[645]
  PIN w0_wmask_in[646]
    DIRECTION INPUT ;
    USE SIGNAL ;
    SHAPE ABUTMENT ;
    PORT
      LAYER metal2 ;
      RECT 122.325 577.990 122.395 578.200 ;
    END
  END w0_wmask_in[646]
  PIN w0_wmask_in[647]
    DIRECTION INPUT ;
    USE SIGNAL ;
    SHAPE ABUTMENT ;
    PORT
      LAYER metal2 ;
      RECT 122.705 577.990 122.775 578.200 ;
    END
  END w0_wmask_in[647]
  PIN w0_wmask_in[648]
    DIRECTION INPUT ;
    USE SIGNAL ;
    SHAPE ABUTMENT ;
    PORT
      LAYER metal2 ;
      RECT 123.085 577.990 123.155 578.200 ;
    END
  END w0_wmask_in[648]
  PIN w0_wmask_in[649]
    DIRECTION INPUT ;
    USE SIGNAL ;
    SHAPE ABUTMENT ;
    PORT
      LAYER metal2 ;
      RECT 123.465 577.990 123.535 578.200 ;
    END
  END w0_wmask_in[649]
  PIN w0_wmask_in[650]
    DIRECTION INPUT ;
    USE SIGNAL ;
    SHAPE ABUTMENT ;
    PORT
      LAYER metal2 ;
      RECT 123.845 577.990 123.915 578.200 ;
    END
  END w0_wmask_in[650]
  PIN w0_wmask_in[651]
    DIRECTION INPUT ;
    USE SIGNAL ;
    SHAPE ABUTMENT ;
    PORT
      LAYER metal2 ;
      RECT 124.225 577.990 124.295 578.200 ;
    END
  END w0_wmask_in[651]
  PIN w0_wmask_in[652]
    DIRECTION INPUT ;
    USE SIGNAL ;
    SHAPE ABUTMENT ;
    PORT
      LAYER metal2 ;
      RECT 124.605 577.990 124.675 578.200 ;
    END
  END w0_wmask_in[652]
  PIN w0_wmask_in[653]
    DIRECTION INPUT ;
    USE SIGNAL ;
    SHAPE ABUTMENT ;
    PORT
      LAYER metal2 ;
      RECT 124.985 577.990 125.055 578.200 ;
    END
  END w0_wmask_in[653]
  PIN w0_wd_in[0]
    DIRECTION INPUT ;
    USE SIGNAL ;
    SHAPE ABUTMENT ;
    PORT
      LAYER metal3 ;
      RECT 0.000 276.325 0.210 276.395 ;
    END
  END w0_wd_in[0]
  PIN w0_wd_in[1]
    DIRECTION INPUT ;
    USE SIGNAL ;
    SHAPE ABUTMENT ;
    PORT
      LAYER metal3 ;
      RECT 0.000 278.005 0.210 278.075 ;
    END
  END w0_wd_in[1]
  PIN w0_wd_in[2]
    DIRECTION INPUT ;
    USE SIGNAL ;
    SHAPE ABUTMENT ;
    PORT
      LAYER metal3 ;
      RECT 0.000 279.685 0.210 279.755 ;
    END
  END w0_wd_in[2]
  PIN w0_wd_in[3]
    DIRECTION INPUT ;
    USE SIGNAL ;
    SHAPE ABUTMENT ;
    PORT
      LAYER metal3 ;
      RECT 0.000 281.365 0.210 281.435 ;
    END
  END w0_wd_in[3]
  PIN w0_wd_in[4]
    DIRECTION INPUT ;
    USE SIGNAL ;
    SHAPE ABUTMENT ;
    PORT
      LAYER metal3 ;
      RECT 0.000 283.045 0.210 283.115 ;
    END
  END w0_wd_in[4]
  PIN w0_wd_in[5]
    DIRECTION INPUT ;
    USE SIGNAL ;
    SHAPE ABUTMENT ;
    PORT
      LAYER metal3 ;
      RECT 0.000 284.725 0.210 284.795 ;
    END
  END w0_wd_in[5]
  PIN w0_wd_in[6]
    DIRECTION INPUT ;
    USE SIGNAL ;
    SHAPE ABUTMENT ;
    PORT
      LAYER metal3 ;
      RECT 0.000 286.405 0.210 286.475 ;
    END
  END w0_wd_in[6]
  PIN w0_wd_in[7]
    DIRECTION INPUT ;
    USE SIGNAL ;
    SHAPE ABUTMENT ;
    PORT
      LAYER metal3 ;
      RECT 0.000 288.085 0.210 288.155 ;
    END
  END w0_wd_in[7]
  PIN w0_wd_in[8]
    DIRECTION INPUT ;
    USE SIGNAL ;
    SHAPE ABUTMENT ;
    PORT
      LAYER metal3 ;
      RECT 0.000 289.765 0.210 289.835 ;
    END
  END w0_wd_in[8]
  PIN w0_wd_in[9]
    DIRECTION INPUT ;
    USE SIGNAL ;
    SHAPE ABUTMENT ;
    PORT
      LAYER metal3 ;
      RECT 0.000 291.445 0.210 291.515 ;
    END
  END w0_wd_in[9]
  PIN w0_wd_in[10]
    DIRECTION INPUT ;
    USE SIGNAL ;
    SHAPE ABUTMENT ;
    PORT
      LAYER metal3 ;
      RECT 0.000 293.125 0.210 293.195 ;
    END
  END w0_wd_in[10]
  PIN w0_wd_in[11]
    DIRECTION INPUT ;
    USE SIGNAL ;
    SHAPE ABUTMENT ;
    PORT
      LAYER metal3 ;
      RECT 0.000 294.805 0.210 294.875 ;
    END
  END w0_wd_in[11]
  PIN w0_wd_in[12]
    DIRECTION INPUT ;
    USE SIGNAL ;
    SHAPE ABUTMENT ;
    PORT
      LAYER metal3 ;
      RECT 0.000 296.485 0.210 296.555 ;
    END
  END w0_wd_in[12]
  PIN w0_wd_in[13]
    DIRECTION INPUT ;
    USE SIGNAL ;
    SHAPE ABUTMENT ;
    PORT
      LAYER metal3 ;
      RECT 0.000 298.165 0.210 298.235 ;
    END
  END w0_wd_in[13]
  PIN w0_wd_in[14]
    DIRECTION INPUT ;
    USE SIGNAL ;
    SHAPE ABUTMENT ;
    PORT
      LAYER metal3 ;
      RECT 0.000 299.845 0.210 299.915 ;
    END
  END w0_wd_in[14]
  PIN w0_wd_in[15]
    DIRECTION INPUT ;
    USE SIGNAL ;
    SHAPE ABUTMENT ;
    PORT
      LAYER metal3 ;
      RECT 0.000 301.525 0.210 301.595 ;
    END
  END w0_wd_in[15]
  PIN w0_wd_in[16]
    DIRECTION INPUT ;
    USE SIGNAL ;
    SHAPE ABUTMENT ;
    PORT
      LAYER metal3 ;
      RECT 0.000 303.205 0.210 303.275 ;
    END
  END w0_wd_in[16]
  PIN w0_wd_in[17]
    DIRECTION INPUT ;
    USE SIGNAL ;
    SHAPE ABUTMENT ;
    PORT
      LAYER metal3 ;
      RECT 0.000 304.885 0.210 304.955 ;
    END
  END w0_wd_in[17]
  PIN w0_wd_in[18]
    DIRECTION INPUT ;
    USE SIGNAL ;
    SHAPE ABUTMENT ;
    PORT
      LAYER metal3 ;
      RECT 0.000 306.565 0.210 306.635 ;
    END
  END w0_wd_in[18]
  PIN w0_wd_in[19]
    DIRECTION INPUT ;
    USE SIGNAL ;
    SHAPE ABUTMENT ;
    PORT
      LAYER metal3 ;
      RECT 0.000 308.245 0.210 308.315 ;
    END
  END w0_wd_in[19]
  PIN w0_wd_in[20]
    DIRECTION INPUT ;
    USE SIGNAL ;
    SHAPE ABUTMENT ;
    PORT
      LAYER metal3 ;
      RECT 0.000 309.925 0.210 309.995 ;
    END
  END w0_wd_in[20]
  PIN w0_wd_in[21]
    DIRECTION INPUT ;
    USE SIGNAL ;
    SHAPE ABUTMENT ;
    PORT
      LAYER metal3 ;
      RECT 0.000 311.605 0.210 311.675 ;
    END
  END w0_wd_in[21]
  PIN w0_wd_in[22]
    DIRECTION INPUT ;
    USE SIGNAL ;
    SHAPE ABUTMENT ;
    PORT
      LAYER metal3 ;
      RECT 0.000 313.285 0.210 313.355 ;
    END
  END w0_wd_in[22]
  PIN w0_wd_in[23]
    DIRECTION INPUT ;
    USE SIGNAL ;
    SHAPE ABUTMENT ;
    PORT
      LAYER metal3 ;
      RECT 0.000 314.965 0.210 315.035 ;
    END
  END w0_wd_in[23]
  PIN w0_wd_in[24]
    DIRECTION INPUT ;
    USE SIGNAL ;
    SHAPE ABUTMENT ;
    PORT
      LAYER metal3 ;
      RECT 0.000 316.645 0.210 316.715 ;
    END
  END w0_wd_in[24]
  PIN w0_wd_in[25]
    DIRECTION INPUT ;
    USE SIGNAL ;
    SHAPE ABUTMENT ;
    PORT
      LAYER metal3 ;
      RECT 0.000 318.325 0.210 318.395 ;
    END
  END w0_wd_in[25]
  PIN w0_wd_in[26]
    DIRECTION INPUT ;
    USE SIGNAL ;
    SHAPE ABUTMENT ;
    PORT
      LAYER metal3 ;
      RECT 0.000 320.005 0.210 320.075 ;
    END
  END w0_wd_in[26]
  PIN w0_wd_in[27]
    DIRECTION INPUT ;
    USE SIGNAL ;
    SHAPE ABUTMENT ;
    PORT
      LAYER metal3 ;
      RECT 0.000 321.685 0.210 321.755 ;
    END
  END w0_wd_in[27]
  PIN w0_wd_in[28]
    DIRECTION INPUT ;
    USE SIGNAL ;
    SHAPE ABUTMENT ;
    PORT
      LAYER metal3 ;
      RECT 0.000 323.365 0.210 323.435 ;
    END
  END w0_wd_in[28]
  PIN w0_wd_in[29]
    DIRECTION INPUT ;
    USE SIGNAL ;
    SHAPE ABUTMENT ;
    PORT
      LAYER metal3 ;
      RECT 0.000 325.045 0.210 325.115 ;
    END
  END w0_wd_in[29]
  PIN w0_wd_in[30]
    DIRECTION INPUT ;
    USE SIGNAL ;
    SHAPE ABUTMENT ;
    PORT
      LAYER metal3 ;
      RECT 0.000 326.725 0.210 326.795 ;
    END
  END w0_wd_in[30]
  PIN w0_wd_in[31]
    DIRECTION INPUT ;
    USE SIGNAL ;
    SHAPE ABUTMENT ;
    PORT
      LAYER metal3 ;
      RECT 0.000 328.405 0.210 328.475 ;
    END
  END w0_wd_in[31]
  PIN w0_wd_in[32]
    DIRECTION INPUT ;
    USE SIGNAL ;
    SHAPE ABUTMENT ;
    PORT
      LAYER metal3 ;
      RECT 0.000 330.085 0.210 330.155 ;
    END
  END w0_wd_in[32]
  PIN w0_wd_in[33]
    DIRECTION INPUT ;
    USE SIGNAL ;
    SHAPE ABUTMENT ;
    PORT
      LAYER metal3 ;
      RECT 0.000 331.765 0.210 331.835 ;
    END
  END w0_wd_in[33]
  PIN w0_wd_in[34]
    DIRECTION INPUT ;
    USE SIGNAL ;
    SHAPE ABUTMENT ;
    PORT
      LAYER metal3 ;
      RECT 0.000 333.445 0.210 333.515 ;
    END
  END w0_wd_in[34]
  PIN w0_wd_in[35]
    DIRECTION INPUT ;
    USE SIGNAL ;
    SHAPE ABUTMENT ;
    PORT
      LAYER metal3 ;
      RECT 0.000 335.125 0.210 335.195 ;
    END
  END w0_wd_in[35]
  PIN w0_wd_in[36]
    DIRECTION INPUT ;
    USE SIGNAL ;
    SHAPE ABUTMENT ;
    PORT
      LAYER metal3 ;
      RECT 0.000 336.805 0.210 336.875 ;
    END
  END w0_wd_in[36]
  PIN w0_wd_in[37]
    DIRECTION INPUT ;
    USE SIGNAL ;
    SHAPE ABUTMENT ;
    PORT
      LAYER metal3 ;
      RECT 0.000 338.485 0.210 338.555 ;
    END
  END w0_wd_in[37]
  PIN w0_wd_in[38]
    DIRECTION INPUT ;
    USE SIGNAL ;
    SHAPE ABUTMENT ;
    PORT
      LAYER metal3 ;
      RECT 0.000 340.165 0.210 340.235 ;
    END
  END w0_wd_in[38]
  PIN w0_wd_in[39]
    DIRECTION INPUT ;
    USE SIGNAL ;
    SHAPE ABUTMENT ;
    PORT
      LAYER metal3 ;
      RECT 0.000 341.845 0.210 341.915 ;
    END
  END w0_wd_in[39]
  PIN w0_wd_in[40]
    DIRECTION INPUT ;
    USE SIGNAL ;
    SHAPE ABUTMENT ;
    PORT
      LAYER metal3 ;
      RECT 0.000 343.525 0.210 343.595 ;
    END
  END w0_wd_in[40]
  PIN w0_wd_in[41]
    DIRECTION INPUT ;
    USE SIGNAL ;
    SHAPE ABUTMENT ;
    PORT
      LAYER metal3 ;
      RECT 0.000 345.205 0.210 345.275 ;
    END
  END w0_wd_in[41]
  PIN w0_wd_in[42]
    DIRECTION INPUT ;
    USE SIGNAL ;
    SHAPE ABUTMENT ;
    PORT
      LAYER metal3 ;
      RECT 0.000 346.885 0.210 346.955 ;
    END
  END w0_wd_in[42]
  PIN w0_wd_in[43]
    DIRECTION INPUT ;
    USE SIGNAL ;
    SHAPE ABUTMENT ;
    PORT
      LAYER metal3 ;
      RECT 0.000 348.565 0.210 348.635 ;
    END
  END w0_wd_in[43]
  PIN w0_wd_in[44]
    DIRECTION INPUT ;
    USE SIGNAL ;
    SHAPE ABUTMENT ;
    PORT
      LAYER metal3 ;
      RECT 0.000 350.245 0.210 350.315 ;
    END
  END w0_wd_in[44]
  PIN w0_wd_in[45]
    DIRECTION INPUT ;
    USE SIGNAL ;
    SHAPE ABUTMENT ;
    PORT
      LAYER metal3 ;
      RECT 0.000 351.925 0.210 351.995 ;
    END
  END w0_wd_in[45]
  PIN w0_wd_in[46]
    DIRECTION INPUT ;
    USE SIGNAL ;
    SHAPE ABUTMENT ;
    PORT
      LAYER metal3 ;
      RECT 0.000 353.605 0.210 353.675 ;
    END
  END w0_wd_in[46]
  PIN w0_wd_in[47]
    DIRECTION INPUT ;
    USE SIGNAL ;
    SHAPE ABUTMENT ;
    PORT
      LAYER metal3 ;
      RECT 0.000 355.285 0.210 355.355 ;
    END
  END w0_wd_in[47]
  PIN w0_wd_in[48]
    DIRECTION INPUT ;
    USE SIGNAL ;
    SHAPE ABUTMENT ;
    PORT
      LAYER metal3 ;
      RECT 0.000 356.965 0.210 357.035 ;
    END
  END w0_wd_in[48]
  PIN w0_wd_in[49]
    DIRECTION INPUT ;
    USE SIGNAL ;
    SHAPE ABUTMENT ;
    PORT
      LAYER metal3 ;
      RECT 0.000 358.645 0.210 358.715 ;
    END
  END w0_wd_in[49]
  PIN w0_wd_in[50]
    DIRECTION INPUT ;
    USE SIGNAL ;
    SHAPE ABUTMENT ;
    PORT
      LAYER metal3 ;
      RECT 0.000 360.325 0.210 360.395 ;
    END
  END w0_wd_in[50]
  PIN w0_wd_in[51]
    DIRECTION INPUT ;
    USE SIGNAL ;
    SHAPE ABUTMENT ;
    PORT
      LAYER metal3 ;
      RECT 0.000 362.005 0.210 362.075 ;
    END
  END w0_wd_in[51]
  PIN w0_wd_in[52]
    DIRECTION INPUT ;
    USE SIGNAL ;
    SHAPE ABUTMENT ;
    PORT
      LAYER metal3 ;
      RECT 0.000 363.685 0.210 363.755 ;
    END
  END w0_wd_in[52]
  PIN w0_wd_in[53]
    DIRECTION INPUT ;
    USE SIGNAL ;
    SHAPE ABUTMENT ;
    PORT
      LAYER metal3 ;
      RECT 0.000 365.365 0.210 365.435 ;
    END
  END w0_wd_in[53]
  PIN w0_wd_in[54]
    DIRECTION INPUT ;
    USE SIGNAL ;
    SHAPE ABUTMENT ;
    PORT
      LAYER metal3 ;
      RECT 0.000 367.045 0.210 367.115 ;
    END
  END w0_wd_in[54]
  PIN w0_wd_in[55]
    DIRECTION INPUT ;
    USE SIGNAL ;
    SHAPE ABUTMENT ;
    PORT
      LAYER metal3 ;
      RECT 0.000 368.725 0.210 368.795 ;
    END
  END w0_wd_in[55]
  PIN w0_wd_in[56]
    DIRECTION INPUT ;
    USE SIGNAL ;
    SHAPE ABUTMENT ;
    PORT
      LAYER metal3 ;
      RECT 0.000 370.405 0.210 370.475 ;
    END
  END w0_wd_in[56]
  PIN w0_wd_in[57]
    DIRECTION INPUT ;
    USE SIGNAL ;
    SHAPE ABUTMENT ;
    PORT
      LAYER metal3 ;
      RECT 0.000 372.085 0.210 372.155 ;
    END
  END w0_wd_in[57]
  PIN w0_wd_in[58]
    DIRECTION INPUT ;
    USE SIGNAL ;
    SHAPE ABUTMENT ;
    PORT
      LAYER metal3 ;
      RECT 0.000 373.765 0.210 373.835 ;
    END
  END w0_wd_in[58]
  PIN w0_wd_in[59]
    DIRECTION INPUT ;
    USE SIGNAL ;
    SHAPE ABUTMENT ;
    PORT
      LAYER metal3 ;
      RECT 0.000 375.445 0.210 375.515 ;
    END
  END w0_wd_in[59]
  PIN w0_wd_in[60]
    DIRECTION INPUT ;
    USE SIGNAL ;
    SHAPE ABUTMENT ;
    PORT
      LAYER metal3 ;
      RECT 0.000 377.125 0.210 377.195 ;
    END
  END w0_wd_in[60]
  PIN w0_wd_in[61]
    DIRECTION INPUT ;
    USE SIGNAL ;
    SHAPE ABUTMENT ;
    PORT
      LAYER metal3 ;
      RECT 0.000 378.805 0.210 378.875 ;
    END
  END w0_wd_in[61]
  PIN w0_wd_in[62]
    DIRECTION INPUT ;
    USE SIGNAL ;
    SHAPE ABUTMENT ;
    PORT
      LAYER metal3 ;
      RECT 0.000 380.485 0.210 380.555 ;
    END
  END w0_wd_in[62]
  PIN w0_wd_in[63]
    DIRECTION INPUT ;
    USE SIGNAL ;
    SHAPE ABUTMENT ;
    PORT
      LAYER metal3 ;
      RECT 0.000 382.165 0.210 382.235 ;
    END
  END w0_wd_in[63]
  PIN w0_wd_in[64]
    DIRECTION INPUT ;
    USE SIGNAL ;
    SHAPE ABUTMENT ;
    PORT
      LAYER metal3 ;
      RECT 0.000 383.845 0.210 383.915 ;
    END
  END w0_wd_in[64]
  PIN w0_wd_in[65]
    DIRECTION INPUT ;
    USE SIGNAL ;
    SHAPE ABUTMENT ;
    PORT
      LAYER metal3 ;
      RECT 0.000 385.525 0.210 385.595 ;
    END
  END w0_wd_in[65]
  PIN w0_wd_in[66]
    DIRECTION INPUT ;
    USE SIGNAL ;
    SHAPE ABUTMENT ;
    PORT
      LAYER metal3 ;
      RECT 0.000 387.205 0.210 387.275 ;
    END
  END w0_wd_in[66]
  PIN w0_wd_in[67]
    DIRECTION INPUT ;
    USE SIGNAL ;
    SHAPE ABUTMENT ;
    PORT
      LAYER metal3 ;
      RECT 0.000 388.885 0.210 388.955 ;
    END
  END w0_wd_in[67]
  PIN w0_wd_in[68]
    DIRECTION INPUT ;
    USE SIGNAL ;
    SHAPE ABUTMENT ;
    PORT
      LAYER metal3 ;
      RECT 0.000 390.565 0.210 390.635 ;
    END
  END w0_wd_in[68]
  PIN w0_wd_in[69]
    DIRECTION INPUT ;
    USE SIGNAL ;
    SHAPE ABUTMENT ;
    PORT
      LAYER metal3 ;
      RECT 0.000 392.245 0.210 392.315 ;
    END
  END w0_wd_in[69]
  PIN w0_wd_in[70]
    DIRECTION INPUT ;
    USE SIGNAL ;
    SHAPE ABUTMENT ;
    PORT
      LAYER metal3 ;
      RECT 0.000 393.925 0.210 393.995 ;
    END
  END w0_wd_in[70]
  PIN w0_wd_in[71]
    DIRECTION INPUT ;
    USE SIGNAL ;
    SHAPE ABUTMENT ;
    PORT
      LAYER metal3 ;
      RECT 0.000 395.605 0.210 395.675 ;
    END
  END w0_wd_in[71]
  PIN w0_wd_in[72]
    DIRECTION INPUT ;
    USE SIGNAL ;
    SHAPE ABUTMENT ;
    PORT
      LAYER metal3 ;
      RECT 0.000 397.285 0.210 397.355 ;
    END
  END w0_wd_in[72]
  PIN w0_wd_in[73]
    DIRECTION INPUT ;
    USE SIGNAL ;
    SHAPE ABUTMENT ;
    PORT
      LAYER metal3 ;
      RECT 0.000 398.965 0.210 399.035 ;
    END
  END w0_wd_in[73]
  PIN w0_wd_in[74]
    DIRECTION INPUT ;
    USE SIGNAL ;
    SHAPE ABUTMENT ;
    PORT
      LAYER metal3 ;
      RECT 0.000 400.645 0.210 400.715 ;
    END
  END w0_wd_in[74]
  PIN w0_wd_in[75]
    DIRECTION INPUT ;
    USE SIGNAL ;
    SHAPE ABUTMENT ;
    PORT
      LAYER metal3 ;
      RECT 0.000 402.325 0.210 402.395 ;
    END
  END w0_wd_in[75]
  PIN w0_wd_in[76]
    DIRECTION INPUT ;
    USE SIGNAL ;
    SHAPE ABUTMENT ;
    PORT
      LAYER metal3 ;
      RECT 0.000 404.005 0.210 404.075 ;
    END
  END w0_wd_in[76]
  PIN w0_wd_in[77]
    DIRECTION INPUT ;
    USE SIGNAL ;
    SHAPE ABUTMENT ;
    PORT
      LAYER metal3 ;
      RECT 0.000 405.685 0.210 405.755 ;
    END
  END w0_wd_in[77]
  PIN w0_wd_in[78]
    DIRECTION INPUT ;
    USE SIGNAL ;
    SHAPE ABUTMENT ;
    PORT
      LAYER metal3 ;
      RECT 0.000 407.365 0.210 407.435 ;
    END
  END w0_wd_in[78]
  PIN w0_wd_in[79]
    DIRECTION INPUT ;
    USE SIGNAL ;
    SHAPE ABUTMENT ;
    PORT
      LAYER metal3 ;
      RECT 0.000 409.045 0.210 409.115 ;
    END
  END w0_wd_in[79]
  PIN w0_wd_in[80]
    DIRECTION INPUT ;
    USE SIGNAL ;
    SHAPE ABUTMENT ;
    PORT
      LAYER metal3 ;
      RECT 0.000 410.725 0.210 410.795 ;
    END
  END w0_wd_in[80]
  PIN w0_wd_in[81]
    DIRECTION INPUT ;
    USE SIGNAL ;
    SHAPE ABUTMENT ;
    PORT
      LAYER metal3 ;
      RECT 0.000 412.405 0.210 412.475 ;
    END
  END w0_wd_in[81]
  PIN w0_wd_in[82]
    DIRECTION INPUT ;
    USE SIGNAL ;
    SHAPE ABUTMENT ;
    PORT
      LAYER metal3 ;
      RECT 0.000 414.085 0.210 414.155 ;
    END
  END w0_wd_in[82]
  PIN w0_wd_in[83]
    DIRECTION INPUT ;
    USE SIGNAL ;
    SHAPE ABUTMENT ;
    PORT
      LAYER metal3 ;
      RECT 0.000 415.765 0.210 415.835 ;
    END
  END w0_wd_in[83]
  PIN w0_wd_in[84]
    DIRECTION INPUT ;
    USE SIGNAL ;
    SHAPE ABUTMENT ;
    PORT
      LAYER metal3 ;
      RECT 0.000 417.445 0.210 417.515 ;
    END
  END w0_wd_in[84]
  PIN w0_wd_in[85]
    DIRECTION INPUT ;
    USE SIGNAL ;
    SHAPE ABUTMENT ;
    PORT
      LAYER metal3 ;
      RECT 0.000 419.125 0.210 419.195 ;
    END
  END w0_wd_in[85]
  PIN w0_wd_in[86]
    DIRECTION INPUT ;
    USE SIGNAL ;
    SHAPE ABUTMENT ;
    PORT
      LAYER metal3 ;
      RECT 0.000 420.805 0.210 420.875 ;
    END
  END w0_wd_in[86]
  PIN w0_wd_in[87]
    DIRECTION INPUT ;
    USE SIGNAL ;
    SHAPE ABUTMENT ;
    PORT
      LAYER metal3 ;
      RECT 0.000 422.485 0.210 422.555 ;
    END
  END w0_wd_in[87]
  PIN w0_wd_in[88]
    DIRECTION INPUT ;
    USE SIGNAL ;
    SHAPE ABUTMENT ;
    PORT
      LAYER metal3 ;
      RECT 0.000 424.165 0.210 424.235 ;
    END
  END w0_wd_in[88]
  PIN w0_wd_in[89]
    DIRECTION INPUT ;
    USE SIGNAL ;
    SHAPE ABUTMENT ;
    PORT
      LAYER metal3 ;
      RECT 0.000 425.845 0.210 425.915 ;
    END
  END w0_wd_in[89]
  PIN w0_wd_in[90]
    DIRECTION INPUT ;
    USE SIGNAL ;
    SHAPE ABUTMENT ;
    PORT
      LAYER metal3 ;
      RECT 0.000 427.525 0.210 427.595 ;
    END
  END w0_wd_in[90]
  PIN w0_wd_in[91]
    DIRECTION INPUT ;
    USE SIGNAL ;
    SHAPE ABUTMENT ;
    PORT
      LAYER metal3 ;
      RECT 0.000 429.205 0.210 429.275 ;
    END
  END w0_wd_in[91]
  PIN w0_wd_in[92]
    DIRECTION INPUT ;
    USE SIGNAL ;
    SHAPE ABUTMENT ;
    PORT
      LAYER metal3 ;
      RECT 0.000 430.885 0.210 430.955 ;
    END
  END w0_wd_in[92]
  PIN w0_wd_in[93]
    DIRECTION INPUT ;
    USE SIGNAL ;
    SHAPE ABUTMENT ;
    PORT
      LAYER metal3 ;
      RECT 0.000 432.565 0.210 432.635 ;
    END
  END w0_wd_in[93]
  PIN w0_wd_in[94]
    DIRECTION INPUT ;
    USE SIGNAL ;
    SHAPE ABUTMENT ;
    PORT
      LAYER metal3 ;
      RECT 0.000 434.245 0.210 434.315 ;
    END
  END w0_wd_in[94]
  PIN w0_wd_in[95]
    DIRECTION INPUT ;
    USE SIGNAL ;
    SHAPE ABUTMENT ;
    PORT
      LAYER metal3 ;
      RECT 0.000 435.925 0.210 435.995 ;
    END
  END w0_wd_in[95]
  PIN w0_wd_in[96]
    DIRECTION INPUT ;
    USE SIGNAL ;
    SHAPE ABUTMENT ;
    PORT
      LAYER metal3 ;
      RECT 0.000 437.605 0.210 437.675 ;
    END
  END w0_wd_in[96]
  PIN w0_wd_in[97]
    DIRECTION INPUT ;
    USE SIGNAL ;
    SHAPE ABUTMENT ;
    PORT
      LAYER metal3 ;
      RECT 0.000 439.285 0.210 439.355 ;
    END
  END w0_wd_in[97]
  PIN w0_wd_in[98]
    DIRECTION INPUT ;
    USE SIGNAL ;
    SHAPE ABUTMENT ;
    PORT
      LAYER metal3 ;
      RECT 0.000 440.965 0.210 441.035 ;
    END
  END w0_wd_in[98]
  PIN w0_wd_in[99]
    DIRECTION INPUT ;
    USE SIGNAL ;
    SHAPE ABUTMENT ;
    PORT
      LAYER metal3 ;
      RECT 0.000 442.645 0.210 442.715 ;
    END
  END w0_wd_in[99]
  PIN w0_wd_in[100]
    DIRECTION INPUT ;
    USE SIGNAL ;
    SHAPE ABUTMENT ;
    PORT
      LAYER metal3 ;
      RECT 0.000 444.325 0.210 444.395 ;
    END
  END w0_wd_in[100]
  PIN w0_wd_in[101]
    DIRECTION INPUT ;
    USE SIGNAL ;
    SHAPE ABUTMENT ;
    PORT
      LAYER metal3 ;
      RECT 0.000 446.005 0.210 446.075 ;
    END
  END w0_wd_in[101]
  PIN w0_wd_in[102]
    DIRECTION INPUT ;
    USE SIGNAL ;
    SHAPE ABUTMENT ;
    PORT
      LAYER metal3 ;
      RECT 0.000 447.685 0.210 447.755 ;
    END
  END w0_wd_in[102]
  PIN w0_wd_in[103]
    DIRECTION INPUT ;
    USE SIGNAL ;
    SHAPE ABUTMENT ;
    PORT
      LAYER metal3 ;
      RECT 0.000 449.365 0.210 449.435 ;
    END
  END w0_wd_in[103]
  PIN w0_wd_in[104]
    DIRECTION INPUT ;
    USE SIGNAL ;
    SHAPE ABUTMENT ;
    PORT
      LAYER metal3 ;
      RECT 0.000 451.045 0.210 451.115 ;
    END
  END w0_wd_in[104]
  PIN w0_wd_in[105]
    DIRECTION INPUT ;
    USE SIGNAL ;
    SHAPE ABUTMENT ;
    PORT
      LAYER metal3 ;
      RECT 0.000 452.725 0.210 452.795 ;
    END
  END w0_wd_in[105]
  PIN w0_wd_in[106]
    DIRECTION INPUT ;
    USE SIGNAL ;
    SHAPE ABUTMENT ;
    PORT
      LAYER metal3 ;
      RECT 0.000 454.405 0.210 454.475 ;
    END
  END w0_wd_in[106]
  PIN w0_wd_in[107]
    DIRECTION INPUT ;
    USE SIGNAL ;
    SHAPE ABUTMENT ;
    PORT
      LAYER metal3 ;
      RECT 0.000 456.085 0.210 456.155 ;
    END
  END w0_wd_in[107]
  PIN w0_wd_in[108]
    DIRECTION INPUT ;
    USE SIGNAL ;
    SHAPE ABUTMENT ;
    PORT
      LAYER metal3 ;
      RECT 0.000 457.765 0.210 457.835 ;
    END
  END w0_wd_in[108]
  PIN w0_wd_in[109]
    DIRECTION INPUT ;
    USE SIGNAL ;
    SHAPE ABUTMENT ;
    PORT
      LAYER metal3 ;
      RECT 0.000 459.445 0.210 459.515 ;
    END
  END w0_wd_in[109]
  PIN w0_wd_in[110]
    DIRECTION INPUT ;
    USE SIGNAL ;
    SHAPE ABUTMENT ;
    PORT
      LAYER metal3 ;
      RECT 0.000 461.125 0.210 461.195 ;
    END
  END w0_wd_in[110]
  PIN w0_wd_in[111]
    DIRECTION INPUT ;
    USE SIGNAL ;
    SHAPE ABUTMENT ;
    PORT
      LAYER metal3 ;
      RECT 0.000 462.805 0.210 462.875 ;
    END
  END w0_wd_in[111]
  PIN w0_wd_in[112]
    DIRECTION INPUT ;
    USE SIGNAL ;
    SHAPE ABUTMENT ;
    PORT
      LAYER metal3 ;
      RECT 0.000 464.485 0.210 464.555 ;
    END
  END w0_wd_in[112]
  PIN w0_wd_in[113]
    DIRECTION INPUT ;
    USE SIGNAL ;
    SHAPE ABUTMENT ;
    PORT
      LAYER metal3 ;
      RECT 0.000 466.165 0.210 466.235 ;
    END
  END w0_wd_in[113]
  PIN w0_wd_in[114]
    DIRECTION INPUT ;
    USE SIGNAL ;
    SHAPE ABUTMENT ;
    PORT
      LAYER metal3 ;
      RECT 0.000 467.845 0.210 467.915 ;
    END
  END w0_wd_in[114]
  PIN w0_wd_in[115]
    DIRECTION INPUT ;
    USE SIGNAL ;
    SHAPE ABUTMENT ;
    PORT
      LAYER metal3 ;
      RECT 0.000 469.525 0.210 469.595 ;
    END
  END w0_wd_in[115]
  PIN w0_wd_in[116]
    DIRECTION INPUT ;
    USE SIGNAL ;
    SHAPE ABUTMENT ;
    PORT
      LAYER metal3 ;
      RECT 0.000 471.205 0.210 471.275 ;
    END
  END w0_wd_in[116]
  PIN w0_wd_in[117]
    DIRECTION INPUT ;
    USE SIGNAL ;
    SHAPE ABUTMENT ;
    PORT
      LAYER metal3 ;
      RECT 0.000 472.885 0.210 472.955 ;
    END
  END w0_wd_in[117]
  PIN w0_wd_in[118]
    DIRECTION INPUT ;
    USE SIGNAL ;
    SHAPE ABUTMENT ;
    PORT
      LAYER metal3 ;
      RECT 0.000 474.565 0.210 474.635 ;
    END
  END w0_wd_in[118]
  PIN w0_wd_in[119]
    DIRECTION INPUT ;
    USE SIGNAL ;
    SHAPE ABUTMENT ;
    PORT
      LAYER metal3 ;
      RECT 0.000 476.245 0.210 476.315 ;
    END
  END w0_wd_in[119]
  PIN w0_wd_in[120]
    DIRECTION INPUT ;
    USE SIGNAL ;
    SHAPE ABUTMENT ;
    PORT
      LAYER metal3 ;
      RECT 0.000 477.925 0.210 477.995 ;
    END
  END w0_wd_in[120]
  PIN w0_wd_in[121]
    DIRECTION INPUT ;
    USE SIGNAL ;
    SHAPE ABUTMENT ;
    PORT
      LAYER metal3 ;
      RECT 0.000 479.605 0.210 479.675 ;
    END
  END w0_wd_in[121]
  PIN w0_wd_in[122]
    DIRECTION INPUT ;
    USE SIGNAL ;
    SHAPE ABUTMENT ;
    PORT
      LAYER metal3 ;
      RECT 0.000 481.285 0.210 481.355 ;
    END
  END w0_wd_in[122]
  PIN w0_wd_in[123]
    DIRECTION INPUT ;
    USE SIGNAL ;
    SHAPE ABUTMENT ;
    PORT
      LAYER metal3 ;
      RECT 0.000 482.965 0.210 483.035 ;
    END
  END w0_wd_in[123]
  PIN w0_wd_in[124]
    DIRECTION INPUT ;
    USE SIGNAL ;
    SHAPE ABUTMENT ;
    PORT
      LAYER metal3 ;
      RECT 0.000 484.645 0.210 484.715 ;
    END
  END w0_wd_in[124]
  PIN w0_wd_in[125]
    DIRECTION INPUT ;
    USE SIGNAL ;
    SHAPE ABUTMENT ;
    PORT
      LAYER metal3 ;
      RECT 0.000 486.325 0.210 486.395 ;
    END
  END w0_wd_in[125]
  PIN w0_wd_in[126]
    DIRECTION INPUT ;
    USE SIGNAL ;
    SHAPE ABUTMENT ;
    PORT
      LAYER metal3 ;
      RECT 0.000 488.005 0.210 488.075 ;
    END
  END w0_wd_in[126]
  PIN w0_wd_in[127]
    DIRECTION INPUT ;
    USE SIGNAL ;
    SHAPE ABUTMENT ;
    PORT
      LAYER metal3 ;
      RECT 0.000 489.685 0.210 489.755 ;
    END
  END w0_wd_in[127]
  PIN w0_wd_in[128]
    DIRECTION INPUT ;
    USE SIGNAL ;
    SHAPE ABUTMENT ;
    PORT
      LAYER metal3 ;
      RECT 0.000 491.365 0.210 491.435 ;
    END
  END w0_wd_in[128]
  PIN w0_wd_in[129]
    DIRECTION INPUT ;
    USE SIGNAL ;
    SHAPE ABUTMENT ;
    PORT
      LAYER metal3 ;
      RECT 0.000 493.045 0.210 493.115 ;
    END
  END w0_wd_in[129]
  PIN w0_wd_in[130]
    DIRECTION INPUT ;
    USE SIGNAL ;
    SHAPE ABUTMENT ;
    PORT
      LAYER metal3 ;
      RECT 0.000 494.725 0.210 494.795 ;
    END
  END w0_wd_in[130]
  PIN w0_wd_in[131]
    DIRECTION INPUT ;
    USE SIGNAL ;
    SHAPE ABUTMENT ;
    PORT
      LAYER metal3 ;
      RECT 0.000 496.405 0.210 496.475 ;
    END
  END w0_wd_in[131]
  PIN w0_wd_in[132]
    DIRECTION INPUT ;
    USE SIGNAL ;
    SHAPE ABUTMENT ;
    PORT
      LAYER metal3 ;
      RECT 0.000 498.085 0.210 498.155 ;
    END
  END w0_wd_in[132]
  PIN w0_wd_in[133]
    DIRECTION INPUT ;
    USE SIGNAL ;
    SHAPE ABUTMENT ;
    PORT
      LAYER metal3 ;
      RECT 0.000 499.765 0.210 499.835 ;
    END
  END w0_wd_in[133]
  PIN w0_wd_in[134]
    DIRECTION INPUT ;
    USE SIGNAL ;
    SHAPE ABUTMENT ;
    PORT
      LAYER metal3 ;
      RECT 0.000 501.445 0.210 501.515 ;
    END
  END w0_wd_in[134]
  PIN w0_wd_in[135]
    DIRECTION INPUT ;
    USE SIGNAL ;
    SHAPE ABUTMENT ;
    PORT
      LAYER metal3 ;
      RECT 0.000 503.125 0.210 503.195 ;
    END
  END w0_wd_in[135]
  PIN w0_wd_in[136]
    DIRECTION INPUT ;
    USE SIGNAL ;
    SHAPE ABUTMENT ;
    PORT
      LAYER metal3 ;
      RECT 0.000 504.805 0.210 504.875 ;
    END
  END w0_wd_in[136]
  PIN w0_wd_in[137]
    DIRECTION INPUT ;
    USE SIGNAL ;
    SHAPE ABUTMENT ;
    PORT
      LAYER metal3 ;
      RECT 0.000 506.485 0.210 506.555 ;
    END
  END w0_wd_in[137]
  PIN w0_wd_in[138]
    DIRECTION INPUT ;
    USE SIGNAL ;
    SHAPE ABUTMENT ;
    PORT
      LAYER metal3 ;
      RECT 0.000 508.165 0.210 508.235 ;
    END
  END w0_wd_in[138]
  PIN w0_wd_in[139]
    DIRECTION INPUT ;
    USE SIGNAL ;
    SHAPE ABUTMENT ;
    PORT
      LAYER metal3 ;
      RECT 0.000 509.845 0.210 509.915 ;
    END
  END w0_wd_in[139]
  PIN w0_wd_in[140]
    DIRECTION INPUT ;
    USE SIGNAL ;
    SHAPE ABUTMENT ;
    PORT
      LAYER metal3 ;
      RECT 0.000 511.525 0.210 511.595 ;
    END
  END w0_wd_in[140]
  PIN w0_wd_in[141]
    DIRECTION INPUT ;
    USE SIGNAL ;
    SHAPE ABUTMENT ;
    PORT
      LAYER metal3 ;
      RECT 0.000 513.205 0.210 513.275 ;
    END
  END w0_wd_in[141]
  PIN w0_wd_in[142]
    DIRECTION INPUT ;
    USE SIGNAL ;
    SHAPE ABUTMENT ;
    PORT
      LAYER metal3 ;
      RECT 0.000 514.885 0.210 514.955 ;
    END
  END w0_wd_in[142]
  PIN w0_wd_in[143]
    DIRECTION INPUT ;
    USE SIGNAL ;
    SHAPE ABUTMENT ;
    PORT
      LAYER metal3 ;
      RECT 0.000 516.565 0.210 516.635 ;
    END
  END w0_wd_in[143]
  PIN w0_wd_in[144]
    DIRECTION INPUT ;
    USE SIGNAL ;
    SHAPE ABUTMENT ;
    PORT
      LAYER metal3 ;
      RECT 0.000 518.245 0.210 518.315 ;
    END
  END w0_wd_in[144]
  PIN w0_wd_in[145]
    DIRECTION INPUT ;
    USE SIGNAL ;
    SHAPE ABUTMENT ;
    PORT
      LAYER metal3 ;
      RECT 0.000 519.925 0.210 519.995 ;
    END
  END w0_wd_in[145]
  PIN w0_wd_in[146]
    DIRECTION INPUT ;
    USE SIGNAL ;
    SHAPE ABUTMENT ;
    PORT
      LAYER metal3 ;
      RECT 0.000 521.605 0.210 521.675 ;
    END
  END w0_wd_in[146]
  PIN w0_wd_in[147]
    DIRECTION INPUT ;
    USE SIGNAL ;
    SHAPE ABUTMENT ;
    PORT
      LAYER metal3 ;
      RECT 0.000 523.285 0.210 523.355 ;
    END
  END w0_wd_in[147]
  PIN w0_wd_in[148]
    DIRECTION INPUT ;
    USE SIGNAL ;
    SHAPE ABUTMENT ;
    PORT
      LAYER metal3 ;
      RECT 0.000 524.965 0.210 525.035 ;
    END
  END w0_wd_in[148]
  PIN w0_wd_in[149]
    DIRECTION INPUT ;
    USE SIGNAL ;
    SHAPE ABUTMENT ;
    PORT
      LAYER metal3 ;
      RECT 0.000 526.645 0.210 526.715 ;
    END
  END w0_wd_in[149]
  PIN w0_wd_in[150]
    DIRECTION INPUT ;
    USE SIGNAL ;
    SHAPE ABUTMENT ;
    PORT
      LAYER metal3 ;
      RECT 0.000 528.325 0.210 528.395 ;
    END
  END w0_wd_in[150]
  PIN w0_wd_in[151]
    DIRECTION INPUT ;
    USE SIGNAL ;
    SHAPE ABUTMENT ;
    PORT
      LAYER metal3 ;
      RECT 0.000 530.005 0.210 530.075 ;
    END
  END w0_wd_in[151]
  PIN w0_wd_in[152]
    DIRECTION INPUT ;
    USE SIGNAL ;
    SHAPE ABUTMENT ;
    PORT
      LAYER metal3 ;
      RECT 0.000 531.685 0.210 531.755 ;
    END
  END w0_wd_in[152]
  PIN w0_wd_in[153]
    DIRECTION INPUT ;
    USE SIGNAL ;
    SHAPE ABUTMENT ;
    PORT
      LAYER metal3 ;
      RECT 0.000 533.365 0.210 533.435 ;
    END
  END w0_wd_in[153]
  PIN w0_wd_in[154]
    DIRECTION INPUT ;
    USE SIGNAL ;
    SHAPE ABUTMENT ;
    PORT
      LAYER metal3 ;
      RECT 0.000 535.045 0.210 535.115 ;
    END
  END w0_wd_in[154]
  PIN w0_wd_in[155]
    DIRECTION INPUT ;
    USE SIGNAL ;
    SHAPE ABUTMENT ;
    PORT
      LAYER metal3 ;
      RECT 0.000 536.725 0.210 536.795 ;
    END
  END w0_wd_in[155]
  PIN w0_wd_in[156]
    DIRECTION INPUT ;
    USE SIGNAL ;
    SHAPE ABUTMENT ;
    PORT
      LAYER metal3 ;
      RECT 0.000 538.405 0.210 538.475 ;
    END
  END w0_wd_in[156]
  PIN w0_wd_in[157]
    DIRECTION INPUT ;
    USE SIGNAL ;
    SHAPE ABUTMENT ;
    PORT
      LAYER metal3 ;
      RECT 0.000 540.085 0.210 540.155 ;
    END
  END w0_wd_in[157]
  PIN w0_wd_in[158]
    DIRECTION INPUT ;
    USE SIGNAL ;
    SHAPE ABUTMENT ;
    PORT
      LAYER metal3 ;
      RECT 0.000 541.765 0.210 541.835 ;
    END
  END w0_wd_in[158]
  PIN w0_wd_in[159]
    DIRECTION INPUT ;
    USE SIGNAL ;
    SHAPE ABUTMENT ;
    PORT
      LAYER metal3 ;
      RECT 0.000 543.445 0.210 543.515 ;
    END
  END w0_wd_in[159]
  PIN w0_wd_in[160]
    DIRECTION INPUT ;
    USE SIGNAL ;
    SHAPE ABUTMENT ;
    PORT
      LAYER metal3 ;
      RECT 0.000 545.125 0.210 545.195 ;
    END
  END w0_wd_in[160]
  PIN w0_wd_in[161]
    DIRECTION INPUT ;
    USE SIGNAL ;
    SHAPE ABUTMENT ;
    PORT
      LAYER metal3 ;
      RECT 0.000 546.805 0.210 546.875 ;
    END
  END w0_wd_in[161]
  PIN w0_wd_in[162]
    DIRECTION INPUT ;
    USE SIGNAL ;
    SHAPE ABUTMENT ;
    PORT
      LAYER metal3 ;
      RECT 0.000 548.485 0.210 548.555 ;
    END
  END w0_wd_in[162]
  PIN w0_wd_in[163]
    DIRECTION INPUT ;
    USE SIGNAL ;
    SHAPE ABUTMENT ;
    PORT
      LAYER metal3 ;
      RECT 0.000 550.165 0.210 550.235 ;
    END
  END w0_wd_in[163]
  PIN w0_wd_in[164]
    DIRECTION INPUT ;
    USE SIGNAL ;
    SHAPE ABUTMENT ;
    PORT
      LAYER metal3 ;
      RECT 316.520 274.645 316.730 274.715 ;
    END
  END w0_wd_in[164]
  PIN w0_wd_in[165]
    DIRECTION INPUT ;
    USE SIGNAL ;
    SHAPE ABUTMENT ;
    PORT
      LAYER metal3 ;
      RECT 316.520 276.325 316.730 276.395 ;
    END
  END w0_wd_in[165]
  PIN w0_wd_in[166]
    DIRECTION INPUT ;
    USE SIGNAL ;
    SHAPE ABUTMENT ;
    PORT
      LAYER metal3 ;
      RECT 316.520 278.005 316.730 278.075 ;
    END
  END w0_wd_in[166]
  PIN w0_wd_in[167]
    DIRECTION INPUT ;
    USE SIGNAL ;
    SHAPE ABUTMENT ;
    PORT
      LAYER metal3 ;
      RECT 316.520 279.685 316.730 279.755 ;
    END
  END w0_wd_in[167]
  PIN w0_wd_in[168]
    DIRECTION INPUT ;
    USE SIGNAL ;
    SHAPE ABUTMENT ;
    PORT
      LAYER metal3 ;
      RECT 316.520 281.365 316.730 281.435 ;
    END
  END w0_wd_in[168]
  PIN w0_wd_in[169]
    DIRECTION INPUT ;
    USE SIGNAL ;
    SHAPE ABUTMENT ;
    PORT
      LAYER metal3 ;
      RECT 316.520 283.045 316.730 283.115 ;
    END
  END w0_wd_in[169]
  PIN w0_wd_in[170]
    DIRECTION INPUT ;
    USE SIGNAL ;
    SHAPE ABUTMENT ;
    PORT
      LAYER metal3 ;
      RECT 316.520 284.725 316.730 284.795 ;
    END
  END w0_wd_in[170]
  PIN w0_wd_in[171]
    DIRECTION INPUT ;
    USE SIGNAL ;
    SHAPE ABUTMENT ;
    PORT
      LAYER metal3 ;
      RECT 316.520 286.405 316.730 286.475 ;
    END
  END w0_wd_in[171]
  PIN w0_wd_in[172]
    DIRECTION INPUT ;
    USE SIGNAL ;
    SHAPE ABUTMENT ;
    PORT
      LAYER metal3 ;
      RECT 316.520 288.085 316.730 288.155 ;
    END
  END w0_wd_in[172]
  PIN w0_wd_in[173]
    DIRECTION INPUT ;
    USE SIGNAL ;
    SHAPE ABUTMENT ;
    PORT
      LAYER metal3 ;
      RECT 316.520 289.765 316.730 289.835 ;
    END
  END w0_wd_in[173]
  PIN w0_wd_in[174]
    DIRECTION INPUT ;
    USE SIGNAL ;
    SHAPE ABUTMENT ;
    PORT
      LAYER metal3 ;
      RECT 316.520 291.445 316.730 291.515 ;
    END
  END w0_wd_in[174]
  PIN w0_wd_in[175]
    DIRECTION INPUT ;
    USE SIGNAL ;
    SHAPE ABUTMENT ;
    PORT
      LAYER metal3 ;
      RECT 316.520 293.125 316.730 293.195 ;
    END
  END w0_wd_in[175]
  PIN w0_wd_in[176]
    DIRECTION INPUT ;
    USE SIGNAL ;
    SHAPE ABUTMENT ;
    PORT
      LAYER metal3 ;
      RECT 316.520 294.805 316.730 294.875 ;
    END
  END w0_wd_in[176]
  PIN w0_wd_in[177]
    DIRECTION INPUT ;
    USE SIGNAL ;
    SHAPE ABUTMENT ;
    PORT
      LAYER metal3 ;
      RECT 316.520 296.485 316.730 296.555 ;
    END
  END w0_wd_in[177]
  PIN w0_wd_in[178]
    DIRECTION INPUT ;
    USE SIGNAL ;
    SHAPE ABUTMENT ;
    PORT
      LAYER metal3 ;
      RECT 316.520 298.165 316.730 298.235 ;
    END
  END w0_wd_in[178]
  PIN w0_wd_in[179]
    DIRECTION INPUT ;
    USE SIGNAL ;
    SHAPE ABUTMENT ;
    PORT
      LAYER metal3 ;
      RECT 316.520 299.845 316.730 299.915 ;
    END
  END w0_wd_in[179]
  PIN w0_wd_in[180]
    DIRECTION INPUT ;
    USE SIGNAL ;
    SHAPE ABUTMENT ;
    PORT
      LAYER metal3 ;
      RECT 316.520 301.525 316.730 301.595 ;
    END
  END w0_wd_in[180]
  PIN w0_wd_in[181]
    DIRECTION INPUT ;
    USE SIGNAL ;
    SHAPE ABUTMENT ;
    PORT
      LAYER metal3 ;
      RECT 316.520 303.205 316.730 303.275 ;
    END
  END w0_wd_in[181]
  PIN w0_wd_in[182]
    DIRECTION INPUT ;
    USE SIGNAL ;
    SHAPE ABUTMENT ;
    PORT
      LAYER metal3 ;
      RECT 316.520 304.885 316.730 304.955 ;
    END
  END w0_wd_in[182]
  PIN w0_wd_in[183]
    DIRECTION INPUT ;
    USE SIGNAL ;
    SHAPE ABUTMENT ;
    PORT
      LAYER metal3 ;
      RECT 316.520 306.565 316.730 306.635 ;
    END
  END w0_wd_in[183]
  PIN w0_wd_in[184]
    DIRECTION INPUT ;
    USE SIGNAL ;
    SHAPE ABUTMENT ;
    PORT
      LAYER metal3 ;
      RECT 316.520 308.245 316.730 308.315 ;
    END
  END w0_wd_in[184]
  PIN w0_wd_in[185]
    DIRECTION INPUT ;
    USE SIGNAL ;
    SHAPE ABUTMENT ;
    PORT
      LAYER metal3 ;
      RECT 316.520 309.925 316.730 309.995 ;
    END
  END w0_wd_in[185]
  PIN w0_wd_in[186]
    DIRECTION INPUT ;
    USE SIGNAL ;
    SHAPE ABUTMENT ;
    PORT
      LAYER metal3 ;
      RECT 316.520 311.605 316.730 311.675 ;
    END
  END w0_wd_in[186]
  PIN w0_wd_in[187]
    DIRECTION INPUT ;
    USE SIGNAL ;
    SHAPE ABUTMENT ;
    PORT
      LAYER metal3 ;
      RECT 316.520 313.285 316.730 313.355 ;
    END
  END w0_wd_in[187]
  PIN w0_wd_in[188]
    DIRECTION INPUT ;
    USE SIGNAL ;
    SHAPE ABUTMENT ;
    PORT
      LAYER metal3 ;
      RECT 316.520 314.965 316.730 315.035 ;
    END
  END w0_wd_in[188]
  PIN w0_wd_in[189]
    DIRECTION INPUT ;
    USE SIGNAL ;
    SHAPE ABUTMENT ;
    PORT
      LAYER metal3 ;
      RECT 316.520 316.645 316.730 316.715 ;
    END
  END w0_wd_in[189]
  PIN w0_wd_in[190]
    DIRECTION INPUT ;
    USE SIGNAL ;
    SHAPE ABUTMENT ;
    PORT
      LAYER metal3 ;
      RECT 316.520 318.325 316.730 318.395 ;
    END
  END w0_wd_in[190]
  PIN w0_wd_in[191]
    DIRECTION INPUT ;
    USE SIGNAL ;
    SHAPE ABUTMENT ;
    PORT
      LAYER metal3 ;
      RECT 316.520 320.005 316.730 320.075 ;
    END
  END w0_wd_in[191]
  PIN w0_wd_in[192]
    DIRECTION INPUT ;
    USE SIGNAL ;
    SHAPE ABUTMENT ;
    PORT
      LAYER metal3 ;
      RECT 316.520 321.685 316.730 321.755 ;
    END
  END w0_wd_in[192]
  PIN w0_wd_in[193]
    DIRECTION INPUT ;
    USE SIGNAL ;
    SHAPE ABUTMENT ;
    PORT
      LAYER metal3 ;
      RECT 316.520 323.365 316.730 323.435 ;
    END
  END w0_wd_in[193]
  PIN w0_wd_in[194]
    DIRECTION INPUT ;
    USE SIGNAL ;
    SHAPE ABUTMENT ;
    PORT
      LAYER metal3 ;
      RECT 316.520 325.045 316.730 325.115 ;
    END
  END w0_wd_in[194]
  PIN w0_wd_in[195]
    DIRECTION INPUT ;
    USE SIGNAL ;
    SHAPE ABUTMENT ;
    PORT
      LAYER metal3 ;
      RECT 316.520 326.725 316.730 326.795 ;
    END
  END w0_wd_in[195]
  PIN w0_wd_in[196]
    DIRECTION INPUT ;
    USE SIGNAL ;
    SHAPE ABUTMENT ;
    PORT
      LAYER metal3 ;
      RECT 316.520 328.405 316.730 328.475 ;
    END
  END w0_wd_in[196]
  PIN w0_wd_in[197]
    DIRECTION INPUT ;
    USE SIGNAL ;
    SHAPE ABUTMENT ;
    PORT
      LAYER metal3 ;
      RECT 316.520 330.085 316.730 330.155 ;
    END
  END w0_wd_in[197]
  PIN w0_wd_in[198]
    DIRECTION INPUT ;
    USE SIGNAL ;
    SHAPE ABUTMENT ;
    PORT
      LAYER metal3 ;
      RECT 316.520 331.765 316.730 331.835 ;
    END
  END w0_wd_in[198]
  PIN w0_wd_in[199]
    DIRECTION INPUT ;
    USE SIGNAL ;
    SHAPE ABUTMENT ;
    PORT
      LAYER metal3 ;
      RECT 316.520 333.445 316.730 333.515 ;
    END
  END w0_wd_in[199]
  PIN w0_wd_in[200]
    DIRECTION INPUT ;
    USE SIGNAL ;
    SHAPE ABUTMENT ;
    PORT
      LAYER metal3 ;
      RECT 316.520 335.125 316.730 335.195 ;
    END
  END w0_wd_in[200]
  PIN w0_wd_in[201]
    DIRECTION INPUT ;
    USE SIGNAL ;
    SHAPE ABUTMENT ;
    PORT
      LAYER metal3 ;
      RECT 316.520 336.805 316.730 336.875 ;
    END
  END w0_wd_in[201]
  PIN w0_wd_in[202]
    DIRECTION INPUT ;
    USE SIGNAL ;
    SHAPE ABUTMENT ;
    PORT
      LAYER metal3 ;
      RECT 316.520 338.485 316.730 338.555 ;
    END
  END w0_wd_in[202]
  PIN w0_wd_in[203]
    DIRECTION INPUT ;
    USE SIGNAL ;
    SHAPE ABUTMENT ;
    PORT
      LAYER metal3 ;
      RECT 316.520 340.165 316.730 340.235 ;
    END
  END w0_wd_in[203]
  PIN w0_wd_in[204]
    DIRECTION INPUT ;
    USE SIGNAL ;
    SHAPE ABUTMENT ;
    PORT
      LAYER metal3 ;
      RECT 316.520 341.845 316.730 341.915 ;
    END
  END w0_wd_in[204]
  PIN w0_wd_in[205]
    DIRECTION INPUT ;
    USE SIGNAL ;
    SHAPE ABUTMENT ;
    PORT
      LAYER metal3 ;
      RECT 316.520 343.525 316.730 343.595 ;
    END
  END w0_wd_in[205]
  PIN w0_wd_in[206]
    DIRECTION INPUT ;
    USE SIGNAL ;
    SHAPE ABUTMENT ;
    PORT
      LAYER metal3 ;
      RECT 316.520 345.205 316.730 345.275 ;
    END
  END w0_wd_in[206]
  PIN w0_wd_in[207]
    DIRECTION INPUT ;
    USE SIGNAL ;
    SHAPE ABUTMENT ;
    PORT
      LAYER metal3 ;
      RECT 316.520 346.885 316.730 346.955 ;
    END
  END w0_wd_in[207]
  PIN w0_wd_in[208]
    DIRECTION INPUT ;
    USE SIGNAL ;
    SHAPE ABUTMENT ;
    PORT
      LAYER metal3 ;
      RECT 316.520 348.565 316.730 348.635 ;
    END
  END w0_wd_in[208]
  PIN w0_wd_in[209]
    DIRECTION INPUT ;
    USE SIGNAL ;
    SHAPE ABUTMENT ;
    PORT
      LAYER metal3 ;
      RECT 316.520 350.245 316.730 350.315 ;
    END
  END w0_wd_in[209]
  PIN w0_wd_in[210]
    DIRECTION INPUT ;
    USE SIGNAL ;
    SHAPE ABUTMENT ;
    PORT
      LAYER metal3 ;
      RECT 316.520 351.925 316.730 351.995 ;
    END
  END w0_wd_in[210]
  PIN w0_wd_in[211]
    DIRECTION INPUT ;
    USE SIGNAL ;
    SHAPE ABUTMENT ;
    PORT
      LAYER metal3 ;
      RECT 316.520 353.605 316.730 353.675 ;
    END
  END w0_wd_in[211]
  PIN w0_wd_in[212]
    DIRECTION INPUT ;
    USE SIGNAL ;
    SHAPE ABUTMENT ;
    PORT
      LAYER metal3 ;
      RECT 316.520 355.285 316.730 355.355 ;
    END
  END w0_wd_in[212]
  PIN w0_wd_in[213]
    DIRECTION INPUT ;
    USE SIGNAL ;
    SHAPE ABUTMENT ;
    PORT
      LAYER metal3 ;
      RECT 316.520 356.965 316.730 357.035 ;
    END
  END w0_wd_in[213]
  PIN w0_wd_in[214]
    DIRECTION INPUT ;
    USE SIGNAL ;
    SHAPE ABUTMENT ;
    PORT
      LAYER metal3 ;
      RECT 316.520 358.645 316.730 358.715 ;
    END
  END w0_wd_in[214]
  PIN w0_wd_in[215]
    DIRECTION INPUT ;
    USE SIGNAL ;
    SHAPE ABUTMENT ;
    PORT
      LAYER metal3 ;
      RECT 316.520 360.325 316.730 360.395 ;
    END
  END w0_wd_in[215]
  PIN w0_wd_in[216]
    DIRECTION INPUT ;
    USE SIGNAL ;
    SHAPE ABUTMENT ;
    PORT
      LAYER metal3 ;
      RECT 316.520 362.005 316.730 362.075 ;
    END
  END w0_wd_in[216]
  PIN w0_wd_in[217]
    DIRECTION INPUT ;
    USE SIGNAL ;
    SHAPE ABUTMENT ;
    PORT
      LAYER metal3 ;
      RECT 316.520 363.685 316.730 363.755 ;
    END
  END w0_wd_in[217]
  PIN w0_wd_in[218]
    DIRECTION INPUT ;
    USE SIGNAL ;
    SHAPE ABUTMENT ;
    PORT
      LAYER metal3 ;
      RECT 316.520 365.365 316.730 365.435 ;
    END
  END w0_wd_in[218]
  PIN w0_wd_in[219]
    DIRECTION INPUT ;
    USE SIGNAL ;
    SHAPE ABUTMENT ;
    PORT
      LAYER metal3 ;
      RECT 316.520 367.045 316.730 367.115 ;
    END
  END w0_wd_in[219]
  PIN w0_wd_in[220]
    DIRECTION INPUT ;
    USE SIGNAL ;
    SHAPE ABUTMENT ;
    PORT
      LAYER metal3 ;
      RECT 316.520 368.725 316.730 368.795 ;
    END
  END w0_wd_in[220]
  PIN w0_wd_in[221]
    DIRECTION INPUT ;
    USE SIGNAL ;
    SHAPE ABUTMENT ;
    PORT
      LAYER metal3 ;
      RECT 316.520 370.405 316.730 370.475 ;
    END
  END w0_wd_in[221]
  PIN w0_wd_in[222]
    DIRECTION INPUT ;
    USE SIGNAL ;
    SHAPE ABUTMENT ;
    PORT
      LAYER metal3 ;
      RECT 316.520 372.085 316.730 372.155 ;
    END
  END w0_wd_in[222]
  PIN w0_wd_in[223]
    DIRECTION INPUT ;
    USE SIGNAL ;
    SHAPE ABUTMENT ;
    PORT
      LAYER metal3 ;
      RECT 316.520 373.765 316.730 373.835 ;
    END
  END w0_wd_in[223]
  PIN w0_wd_in[224]
    DIRECTION INPUT ;
    USE SIGNAL ;
    SHAPE ABUTMENT ;
    PORT
      LAYER metal3 ;
      RECT 316.520 375.445 316.730 375.515 ;
    END
  END w0_wd_in[224]
  PIN w0_wd_in[225]
    DIRECTION INPUT ;
    USE SIGNAL ;
    SHAPE ABUTMENT ;
    PORT
      LAYER metal3 ;
      RECT 316.520 377.125 316.730 377.195 ;
    END
  END w0_wd_in[225]
  PIN w0_wd_in[226]
    DIRECTION INPUT ;
    USE SIGNAL ;
    SHAPE ABUTMENT ;
    PORT
      LAYER metal3 ;
      RECT 316.520 378.805 316.730 378.875 ;
    END
  END w0_wd_in[226]
  PIN w0_wd_in[227]
    DIRECTION INPUT ;
    USE SIGNAL ;
    SHAPE ABUTMENT ;
    PORT
      LAYER metal3 ;
      RECT 316.520 380.485 316.730 380.555 ;
    END
  END w0_wd_in[227]
  PIN w0_wd_in[228]
    DIRECTION INPUT ;
    USE SIGNAL ;
    SHAPE ABUTMENT ;
    PORT
      LAYER metal3 ;
      RECT 316.520 382.165 316.730 382.235 ;
    END
  END w0_wd_in[228]
  PIN w0_wd_in[229]
    DIRECTION INPUT ;
    USE SIGNAL ;
    SHAPE ABUTMENT ;
    PORT
      LAYER metal3 ;
      RECT 316.520 383.845 316.730 383.915 ;
    END
  END w0_wd_in[229]
  PIN w0_wd_in[230]
    DIRECTION INPUT ;
    USE SIGNAL ;
    SHAPE ABUTMENT ;
    PORT
      LAYER metal3 ;
      RECT 316.520 385.525 316.730 385.595 ;
    END
  END w0_wd_in[230]
  PIN w0_wd_in[231]
    DIRECTION INPUT ;
    USE SIGNAL ;
    SHAPE ABUTMENT ;
    PORT
      LAYER metal3 ;
      RECT 316.520 387.205 316.730 387.275 ;
    END
  END w0_wd_in[231]
  PIN w0_wd_in[232]
    DIRECTION INPUT ;
    USE SIGNAL ;
    SHAPE ABUTMENT ;
    PORT
      LAYER metal3 ;
      RECT 316.520 388.885 316.730 388.955 ;
    END
  END w0_wd_in[232]
  PIN w0_wd_in[233]
    DIRECTION INPUT ;
    USE SIGNAL ;
    SHAPE ABUTMENT ;
    PORT
      LAYER metal3 ;
      RECT 316.520 390.565 316.730 390.635 ;
    END
  END w0_wd_in[233]
  PIN w0_wd_in[234]
    DIRECTION INPUT ;
    USE SIGNAL ;
    SHAPE ABUTMENT ;
    PORT
      LAYER metal3 ;
      RECT 316.520 392.245 316.730 392.315 ;
    END
  END w0_wd_in[234]
  PIN w0_wd_in[235]
    DIRECTION INPUT ;
    USE SIGNAL ;
    SHAPE ABUTMENT ;
    PORT
      LAYER metal3 ;
      RECT 316.520 393.925 316.730 393.995 ;
    END
  END w0_wd_in[235]
  PIN w0_wd_in[236]
    DIRECTION INPUT ;
    USE SIGNAL ;
    SHAPE ABUTMENT ;
    PORT
      LAYER metal3 ;
      RECT 316.520 395.605 316.730 395.675 ;
    END
  END w0_wd_in[236]
  PIN w0_wd_in[237]
    DIRECTION INPUT ;
    USE SIGNAL ;
    SHAPE ABUTMENT ;
    PORT
      LAYER metal3 ;
      RECT 316.520 397.285 316.730 397.355 ;
    END
  END w0_wd_in[237]
  PIN w0_wd_in[238]
    DIRECTION INPUT ;
    USE SIGNAL ;
    SHAPE ABUTMENT ;
    PORT
      LAYER metal3 ;
      RECT 316.520 398.965 316.730 399.035 ;
    END
  END w0_wd_in[238]
  PIN w0_wd_in[239]
    DIRECTION INPUT ;
    USE SIGNAL ;
    SHAPE ABUTMENT ;
    PORT
      LAYER metal3 ;
      RECT 316.520 400.645 316.730 400.715 ;
    END
  END w0_wd_in[239]
  PIN w0_wd_in[240]
    DIRECTION INPUT ;
    USE SIGNAL ;
    SHAPE ABUTMENT ;
    PORT
      LAYER metal3 ;
      RECT 316.520 402.325 316.730 402.395 ;
    END
  END w0_wd_in[240]
  PIN w0_wd_in[241]
    DIRECTION INPUT ;
    USE SIGNAL ;
    SHAPE ABUTMENT ;
    PORT
      LAYER metal3 ;
      RECT 316.520 404.005 316.730 404.075 ;
    END
  END w0_wd_in[241]
  PIN w0_wd_in[242]
    DIRECTION INPUT ;
    USE SIGNAL ;
    SHAPE ABUTMENT ;
    PORT
      LAYER metal3 ;
      RECT 316.520 405.685 316.730 405.755 ;
    END
  END w0_wd_in[242]
  PIN w0_wd_in[243]
    DIRECTION INPUT ;
    USE SIGNAL ;
    SHAPE ABUTMENT ;
    PORT
      LAYER metal3 ;
      RECT 316.520 407.365 316.730 407.435 ;
    END
  END w0_wd_in[243]
  PIN w0_wd_in[244]
    DIRECTION INPUT ;
    USE SIGNAL ;
    SHAPE ABUTMENT ;
    PORT
      LAYER metal3 ;
      RECT 316.520 409.045 316.730 409.115 ;
    END
  END w0_wd_in[244]
  PIN w0_wd_in[245]
    DIRECTION INPUT ;
    USE SIGNAL ;
    SHAPE ABUTMENT ;
    PORT
      LAYER metal3 ;
      RECT 316.520 410.725 316.730 410.795 ;
    END
  END w0_wd_in[245]
  PIN w0_wd_in[246]
    DIRECTION INPUT ;
    USE SIGNAL ;
    SHAPE ABUTMENT ;
    PORT
      LAYER metal3 ;
      RECT 316.520 412.405 316.730 412.475 ;
    END
  END w0_wd_in[246]
  PIN w0_wd_in[247]
    DIRECTION INPUT ;
    USE SIGNAL ;
    SHAPE ABUTMENT ;
    PORT
      LAYER metal3 ;
      RECT 316.520 414.085 316.730 414.155 ;
    END
  END w0_wd_in[247]
  PIN w0_wd_in[248]
    DIRECTION INPUT ;
    USE SIGNAL ;
    SHAPE ABUTMENT ;
    PORT
      LAYER metal3 ;
      RECT 316.520 415.765 316.730 415.835 ;
    END
  END w0_wd_in[248]
  PIN w0_wd_in[249]
    DIRECTION INPUT ;
    USE SIGNAL ;
    SHAPE ABUTMENT ;
    PORT
      LAYER metal3 ;
      RECT 316.520 417.445 316.730 417.515 ;
    END
  END w0_wd_in[249]
  PIN w0_wd_in[250]
    DIRECTION INPUT ;
    USE SIGNAL ;
    SHAPE ABUTMENT ;
    PORT
      LAYER metal3 ;
      RECT 316.520 419.125 316.730 419.195 ;
    END
  END w0_wd_in[250]
  PIN w0_wd_in[251]
    DIRECTION INPUT ;
    USE SIGNAL ;
    SHAPE ABUTMENT ;
    PORT
      LAYER metal3 ;
      RECT 316.520 420.805 316.730 420.875 ;
    END
  END w0_wd_in[251]
  PIN w0_wd_in[252]
    DIRECTION INPUT ;
    USE SIGNAL ;
    SHAPE ABUTMENT ;
    PORT
      LAYER metal3 ;
      RECT 316.520 422.485 316.730 422.555 ;
    END
  END w0_wd_in[252]
  PIN w0_wd_in[253]
    DIRECTION INPUT ;
    USE SIGNAL ;
    SHAPE ABUTMENT ;
    PORT
      LAYER metal3 ;
      RECT 316.520 424.165 316.730 424.235 ;
    END
  END w0_wd_in[253]
  PIN w0_wd_in[254]
    DIRECTION INPUT ;
    USE SIGNAL ;
    SHAPE ABUTMENT ;
    PORT
      LAYER metal3 ;
      RECT 316.520 425.845 316.730 425.915 ;
    END
  END w0_wd_in[254]
  PIN w0_wd_in[255]
    DIRECTION INPUT ;
    USE SIGNAL ;
    SHAPE ABUTMENT ;
    PORT
      LAYER metal3 ;
      RECT 316.520 427.525 316.730 427.595 ;
    END
  END w0_wd_in[255]
  PIN w0_wd_in[256]
    DIRECTION INPUT ;
    USE SIGNAL ;
    SHAPE ABUTMENT ;
    PORT
      LAYER metal3 ;
      RECT 316.520 429.205 316.730 429.275 ;
    END
  END w0_wd_in[256]
  PIN w0_wd_in[257]
    DIRECTION INPUT ;
    USE SIGNAL ;
    SHAPE ABUTMENT ;
    PORT
      LAYER metal3 ;
      RECT 316.520 430.885 316.730 430.955 ;
    END
  END w0_wd_in[257]
  PIN w0_wd_in[258]
    DIRECTION INPUT ;
    USE SIGNAL ;
    SHAPE ABUTMENT ;
    PORT
      LAYER metal3 ;
      RECT 316.520 432.565 316.730 432.635 ;
    END
  END w0_wd_in[258]
  PIN w0_wd_in[259]
    DIRECTION INPUT ;
    USE SIGNAL ;
    SHAPE ABUTMENT ;
    PORT
      LAYER metal3 ;
      RECT 316.520 434.245 316.730 434.315 ;
    END
  END w0_wd_in[259]
  PIN w0_wd_in[260]
    DIRECTION INPUT ;
    USE SIGNAL ;
    SHAPE ABUTMENT ;
    PORT
      LAYER metal3 ;
      RECT 316.520 435.925 316.730 435.995 ;
    END
  END w0_wd_in[260]
  PIN w0_wd_in[261]
    DIRECTION INPUT ;
    USE SIGNAL ;
    SHAPE ABUTMENT ;
    PORT
      LAYER metal3 ;
      RECT 316.520 437.605 316.730 437.675 ;
    END
  END w0_wd_in[261]
  PIN w0_wd_in[262]
    DIRECTION INPUT ;
    USE SIGNAL ;
    SHAPE ABUTMENT ;
    PORT
      LAYER metal3 ;
      RECT 316.520 439.285 316.730 439.355 ;
    END
  END w0_wd_in[262]
  PIN w0_wd_in[263]
    DIRECTION INPUT ;
    USE SIGNAL ;
    SHAPE ABUTMENT ;
    PORT
      LAYER metal3 ;
      RECT 316.520 440.965 316.730 441.035 ;
    END
  END w0_wd_in[263]
  PIN w0_wd_in[264]
    DIRECTION INPUT ;
    USE SIGNAL ;
    SHAPE ABUTMENT ;
    PORT
      LAYER metal3 ;
      RECT 316.520 442.645 316.730 442.715 ;
    END
  END w0_wd_in[264]
  PIN w0_wd_in[265]
    DIRECTION INPUT ;
    USE SIGNAL ;
    SHAPE ABUTMENT ;
    PORT
      LAYER metal3 ;
      RECT 316.520 444.325 316.730 444.395 ;
    END
  END w0_wd_in[265]
  PIN w0_wd_in[266]
    DIRECTION INPUT ;
    USE SIGNAL ;
    SHAPE ABUTMENT ;
    PORT
      LAYER metal3 ;
      RECT 316.520 446.005 316.730 446.075 ;
    END
  END w0_wd_in[266]
  PIN w0_wd_in[267]
    DIRECTION INPUT ;
    USE SIGNAL ;
    SHAPE ABUTMENT ;
    PORT
      LAYER metal3 ;
      RECT 316.520 447.685 316.730 447.755 ;
    END
  END w0_wd_in[267]
  PIN w0_wd_in[268]
    DIRECTION INPUT ;
    USE SIGNAL ;
    SHAPE ABUTMENT ;
    PORT
      LAYER metal3 ;
      RECT 316.520 449.365 316.730 449.435 ;
    END
  END w0_wd_in[268]
  PIN w0_wd_in[269]
    DIRECTION INPUT ;
    USE SIGNAL ;
    SHAPE ABUTMENT ;
    PORT
      LAYER metal3 ;
      RECT 316.520 451.045 316.730 451.115 ;
    END
  END w0_wd_in[269]
  PIN w0_wd_in[270]
    DIRECTION INPUT ;
    USE SIGNAL ;
    SHAPE ABUTMENT ;
    PORT
      LAYER metal3 ;
      RECT 316.520 452.725 316.730 452.795 ;
    END
  END w0_wd_in[270]
  PIN w0_wd_in[271]
    DIRECTION INPUT ;
    USE SIGNAL ;
    SHAPE ABUTMENT ;
    PORT
      LAYER metal3 ;
      RECT 316.520 454.405 316.730 454.475 ;
    END
  END w0_wd_in[271]
  PIN w0_wd_in[272]
    DIRECTION INPUT ;
    USE SIGNAL ;
    SHAPE ABUTMENT ;
    PORT
      LAYER metal3 ;
      RECT 316.520 456.085 316.730 456.155 ;
    END
  END w0_wd_in[272]
  PIN w0_wd_in[273]
    DIRECTION INPUT ;
    USE SIGNAL ;
    SHAPE ABUTMENT ;
    PORT
      LAYER metal3 ;
      RECT 316.520 457.765 316.730 457.835 ;
    END
  END w0_wd_in[273]
  PIN w0_wd_in[274]
    DIRECTION INPUT ;
    USE SIGNAL ;
    SHAPE ABUTMENT ;
    PORT
      LAYER metal3 ;
      RECT 316.520 459.445 316.730 459.515 ;
    END
  END w0_wd_in[274]
  PIN w0_wd_in[275]
    DIRECTION INPUT ;
    USE SIGNAL ;
    SHAPE ABUTMENT ;
    PORT
      LAYER metal3 ;
      RECT 316.520 461.125 316.730 461.195 ;
    END
  END w0_wd_in[275]
  PIN w0_wd_in[276]
    DIRECTION INPUT ;
    USE SIGNAL ;
    SHAPE ABUTMENT ;
    PORT
      LAYER metal3 ;
      RECT 316.520 462.805 316.730 462.875 ;
    END
  END w0_wd_in[276]
  PIN w0_wd_in[277]
    DIRECTION INPUT ;
    USE SIGNAL ;
    SHAPE ABUTMENT ;
    PORT
      LAYER metal3 ;
      RECT 316.520 464.485 316.730 464.555 ;
    END
  END w0_wd_in[277]
  PIN w0_wd_in[278]
    DIRECTION INPUT ;
    USE SIGNAL ;
    SHAPE ABUTMENT ;
    PORT
      LAYER metal3 ;
      RECT 316.520 466.165 316.730 466.235 ;
    END
  END w0_wd_in[278]
  PIN w0_wd_in[279]
    DIRECTION INPUT ;
    USE SIGNAL ;
    SHAPE ABUTMENT ;
    PORT
      LAYER metal3 ;
      RECT 316.520 467.845 316.730 467.915 ;
    END
  END w0_wd_in[279]
  PIN w0_wd_in[280]
    DIRECTION INPUT ;
    USE SIGNAL ;
    SHAPE ABUTMENT ;
    PORT
      LAYER metal3 ;
      RECT 316.520 469.525 316.730 469.595 ;
    END
  END w0_wd_in[280]
  PIN w0_wd_in[281]
    DIRECTION INPUT ;
    USE SIGNAL ;
    SHAPE ABUTMENT ;
    PORT
      LAYER metal3 ;
      RECT 316.520 471.205 316.730 471.275 ;
    END
  END w0_wd_in[281]
  PIN w0_wd_in[282]
    DIRECTION INPUT ;
    USE SIGNAL ;
    SHAPE ABUTMENT ;
    PORT
      LAYER metal3 ;
      RECT 316.520 472.885 316.730 472.955 ;
    END
  END w0_wd_in[282]
  PIN w0_wd_in[283]
    DIRECTION INPUT ;
    USE SIGNAL ;
    SHAPE ABUTMENT ;
    PORT
      LAYER metal3 ;
      RECT 316.520 474.565 316.730 474.635 ;
    END
  END w0_wd_in[283]
  PIN w0_wd_in[284]
    DIRECTION INPUT ;
    USE SIGNAL ;
    SHAPE ABUTMENT ;
    PORT
      LAYER metal3 ;
      RECT 316.520 476.245 316.730 476.315 ;
    END
  END w0_wd_in[284]
  PIN w0_wd_in[285]
    DIRECTION INPUT ;
    USE SIGNAL ;
    SHAPE ABUTMENT ;
    PORT
      LAYER metal3 ;
      RECT 316.520 477.925 316.730 477.995 ;
    END
  END w0_wd_in[285]
  PIN w0_wd_in[286]
    DIRECTION INPUT ;
    USE SIGNAL ;
    SHAPE ABUTMENT ;
    PORT
      LAYER metal3 ;
      RECT 316.520 479.605 316.730 479.675 ;
    END
  END w0_wd_in[286]
  PIN w0_wd_in[287]
    DIRECTION INPUT ;
    USE SIGNAL ;
    SHAPE ABUTMENT ;
    PORT
      LAYER metal3 ;
      RECT 316.520 481.285 316.730 481.355 ;
    END
  END w0_wd_in[287]
  PIN w0_wd_in[288]
    DIRECTION INPUT ;
    USE SIGNAL ;
    SHAPE ABUTMENT ;
    PORT
      LAYER metal3 ;
      RECT 316.520 482.965 316.730 483.035 ;
    END
  END w0_wd_in[288]
  PIN w0_wd_in[289]
    DIRECTION INPUT ;
    USE SIGNAL ;
    SHAPE ABUTMENT ;
    PORT
      LAYER metal3 ;
      RECT 316.520 484.645 316.730 484.715 ;
    END
  END w0_wd_in[289]
  PIN w0_wd_in[290]
    DIRECTION INPUT ;
    USE SIGNAL ;
    SHAPE ABUTMENT ;
    PORT
      LAYER metal3 ;
      RECT 316.520 486.325 316.730 486.395 ;
    END
  END w0_wd_in[290]
  PIN w0_wd_in[291]
    DIRECTION INPUT ;
    USE SIGNAL ;
    SHAPE ABUTMENT ;
    PORT
      LAYER metal3 ;
      RECT 316.520 488.005 316.730 488.075 ;
    END
  END w0_wd_in[291]
  PIN w0_wd_in[292]
    DIRECTION INPUT ;
    USE SIGNAL ;
    SHAPE ABUTMENT ;
    PORT
      LAYER metal3 ;
      RECT 316.520 489.685 316.730 489.755 ;
    END
  END w0_wd_in[292]
  PIN w0_wd_in[293]
    DIRECTION INPUT ;
    USE SIGNAL ;
    SHAPE ABUTMENT ;
    PORT
      LAYER metal3 ;
      RECT 316.520 491.365 316.730 491.435 ;
    END
  END w0_wd_in[293]
  PIN w0_wd_in[294]
    DIRECTION INPUT ;
    USE SIGNAL ;
    SHAPE ABUTMENT ;
    PORT
      LAYER metal3 ;
      RECT 316.520 493.045 316.730 493.115 ;
    END
  END w0_wd_in[294]
  PIN w0_wd_in[295]
    DIRECTION INPUT ;
    USE SIGNAL ;
    SHAPE ABUTMENT ;
    PORT
      LAYER metal3 ;
      RECT 316.520 494.725 316.730 494.795 ;
    END
  END w0_wd_in[295]
  PIN w0_wd_in[296]
    DIRECTION INPUT ;
    USE SIGNAL ;
    SHAPE ABUTMENT ;
    PORT
      LAYER metal3 ;
      RECT 316.520 496.405 316.730 496.475 ;
    END
  END w0_wd_in[296]
  PIN w0_wd_in[297]
    DIRECTION INPUT ;
    USE SIGNAL ;
    SHAPE ABUTMENT ;
    PORT
      LAYER metal3 ;
      RECT 316.520 498.085 316.730 498.155 ;
    END
  END w0_wd_in[297]
  PIN w0_wd_in[298]
    DIRECTION INPUT ;
    USE SIGNAL ;
    SHAPE ABUTMENT ;
    PORT
      LAYER metal3 ;
      RECT 316.520 499.765 316.730 499.835 ;
    END
  END w0_wd_in[298]
  PIN w0_wd_in[299]
    DIRECTION INPUT ;
    USE SIGNAL ;
    SHAPE ABUTMENT ;
    PORT
      LAYER metal3 ;
      RECT 316.520 501.445 316.730 501.515 ;
    END
  END w0_wd_in[299]
  PIN w0_wd_in[300]
    DIRECTION INPUT ;
    USE SIGNAL ;
    SHAPE ABUTMENT ;
    PORT
      LAYER metal3 ;
      RECT 316.520 503.125 316.730 503.195 ;
    END
  END w0_wd_in[300]
  PIN w0_wd_in[301]
    DIRECTION INPUT ;
    USE SIGNAL ;
    SHAPE ABUTMENT ;
    PORT
      LAYER metal3 ;
      RECT 316.520 504.805 316.730 504.875 ;
    END
  END w0_wd_in[301]
  PIN w0_wd_in[302]
    DIRECTION INPUT ;
    USE SIGNAL ;
    SHAPE ABUTMENT ;
    PORT
      LAYER metal3 ;
      RECT 316.520 506.485 316.730 506.555 ;
    END
  END w0_wd_in[302]
  PIN w0_wd_in[303]
    DIRECTION INPUT ;
    USE SIGNAL ;
    SHAPE ABUTMENT ;
    PORT
      LAYER metal3 ;
      RECT 316.520 508.165 316.730 508.235 ;
    END
  END w0_wd_in[303]
  PIN w0_wd_in[304]
    DIRECTION INPUT ;
    USE SIGNAL ;
    SHAPE ABUTMENT ;
    PORT
      LAYER metal3 ;
      RECT 316.520 509.845 316.730 509.915 ;
    END
  END w0_wd_in[304]
  PIN w0_wd_in[305]
    DIRECTION INPUT ;
    USE SIGNAL ;
    SHAPE ABUTMENT ;
    PORT
      LAYER metal3 ;
      RECT 316.520 511.525 316.730 511.595 ;
    END
  END w0_wd_in[305]
  PIN w0_wd_in[306]
    DIRECTION INPUT ;
    USE SIGNAL ;
    SHAPE ABUTMENT ;
    PORT
      LAYER metal3 ;
      RECT 316.520 513.205 316.730 513.275 ;
    END
  END w0_wd_in[306]
  PIN w0_wd_in[307]
    DIRECTION INPUT ;
    USE SIGNAL ;
    SHAPE ABUTMENT ;
    PORT
      LAYER metal3 ;
      RECT 316.520 514.885 316.730 514.955 ;
    END
  END w0_wd_in[307]
  PIN w0_wd_in[308]
    DIRECTION INPUT ;
    USE SIGNAL ;
    SHAPE ABUTMENT ;
    PORT
      LAYER metal3 ;
      RECT 316.520 516.565 316.730 516.635 ;
    END
  END w0_wd_in[308]
  PIN w0_wd_in[309]
    DIRECTION INPUT ;
    USE SIGNAL ;
    SHAPE ABUTMENT ;
    PORT
      LAYER metal3 ;
      RECT 316.520 518.245 316.730 518.315 ;
    END
  END w0_wd_in[309]
  PIN w0_wd_in[310]
    DIRECTION INPUT ;
    USE SIGNAL ;
    SHAPE ABUTMENT ;
    PORT
      LAYER metal3 ;
      RECT 316.520 519.925 316.730 519.995 ;
    END
  END w0_wd_in[310]
  PIN w0_wd_in[311]
    DIRECTION INPUT ;
    USE SIGNAL ;
    SHAPE ABUTMENT ;
    PORT
      LAYER metal3 ;
      RECT 316.520 521.605 316.730 521.675 ;
    END
  END w0_wd_in[311]
  PIN w0_wd_in[312]
    DIRECTION INPUT ;
    USE SIGNAL ;
    SHAPE ABUTMENT ;
    PORT
      LAYER metal3 ;
      RECT 316.520 523.285 316.730 523.355 ;
    END
  END w0_wd_in[312]
  PIN w0_wd_in[313]
    DIRECTION INPUT ;
    USE SIGNAL ;
    SHAPE ABUTMENT ;
    PORT
      LAYER metal3 ;
      RECT 316.520 524.965 316.730 525.035 ;
    END
  END w0_wd_in[313]
  PIN w0_wd_in[314]
    DIRECTION INPUT ;
    USE SIGNAL ;
    SHAPE ABUTMENT ;
    PORT
      LAYER metal3 ;
      RECT 316.520 526.645 316.730 526.715 ;
    END
  END w0_wd_in[314]
  PIN w0_wd_in[315]
    DIRECTION INPUT ;
    USE SIGNAL ;
    SHAPE ABUTMENT ;
    PORT
      LAYER metal3 ;
      RECT 316.520 528.325 316.730 528.395 ;
    END
  END w0_wd_in[315]
  PIN w0_wd_in[316]
    DIRECTION INPUT ;
    USE SIGNAL ;
    SHAPE ABUTMENT ;
    PORT
      LAYER metal3 ;
      RECT 316.520 530.005 316.730 530.075 ;
    END
  END w0_wd_in[316]
  PIN w0_wd_in[317]
    DIRECTION INPUT ;
    USE SIGNAL ;
    SHAPE ABUTMENT ;
    PORT
      LAYER metal3 ;
      RECT 316.520 531.685 316.730 531.755 ;
    END
  END w0_wd_in[317]
  PIN w0_wd_in[318]
    DIRECTION INPUT ;
    USE SIGNAL ;
    SHAPE ABUTMENT ;
    PORT
      LAYER metal3 ;
      RECT 316.520 533.365 316.730 533.435 ;
    END
  END w0_wd_in[318]
  PIN w0_wd_in[319]
    DIRECTION INPUT ;
    USE SIGNAL ;
    SHAPE ABUTMENT ;
    PORT
      LAYER metal3 ;
      RECT 316.520 535.045 316.730 535.115 ;
    END
  END w0_wd_in[319]
  PIN w0_wd_in[320]
    DIRECTION INPUT ;
    USE SIGNAL ;
    SHAPE ABUTMENT ;
    PORT
      LAYER metal3 ;
      RECT 316.520 536.725 316.730 536.795 ;
    END
  END w0_wd_in[320]
  PIN w0_wd_in[321]
    DIRECTION INPUT ;
    USE SIGNAL ;
    SHAPE ABUTMENT ;
    PORT
      LAYER metal3 ;
      RECT 316.520 538.405 316.730 538.475 ;
    END
  END w0_wd_in[321]
  PIN w0_wd_in[322]
    DIRECTION INPUT ;
    USE SIGNAL ;
    SHAPE ABUTMENT ;
    PORT
      LAYER metal3 ;
      RECT 316.520 540.085 316.730 540.155 ;
    END
  END w0_wd_in[322]
  PIN w0_wd_in[323]
    DIRECTION INPUT ;
    USE SIGNAL ;
    SHAPE ABUTMENT ;
    PORT
      LAYER metal3 ;
      RECT 316.520 541.765 316.730 541.835 ;
    END
  END w0_wd_in[323]
  PIN w0_wd_in[324]
    DIRECTION INPUT ;
    USE SIGNAL ;
    SHAPE ABUTMENT ;
    PORT
      LAYER metal3 ;
      RECT 316.520 543.445 316.730 543.515 ;
    END
  END w0_wd_in[324]
  PIN w0_wd_in[325]
    DIRECTION INPUT ;
    USE SIGNAL ;
    SHAPE ABUTMENT ;
    PORT
      LAYER metal3 ;
      RECT 316.520 545.125 316.730 545.195 ;
    END
  END w0_wd_in[325]
  PIN w0_wd_in[326]
    DIRECTION INPUT ;
    USE SIGNAL ;
    SHAPE ABUTMENT ;
    PORT
      LAYER metal3 ;
      RECT 316.520 546.805 316.730 546.875 ;
    END
  END w0_wd_in[326]
  PIN w0_wd_in[327]
    DIRECTION OUTPUT ;
    USE SIGNAL ;
    SHAPE ABUTMENT ;
    PORT
      LAYER metal2 ;
      RECT 1.105 0.000 1.175 0.210 ;
    END
  END w0_wd_in[327]
  PIN w0_wd_in[328]
    DIRECTION OUTPUT ;
    USE SIGNAL ;
    SHAPE ABUTMENT ;
    PORT
      LAYER metal2 ;
      RECT 1.485 0.000 1.555 0.210 ;
    END
  END w0_wd_in[328]
  PIN w0_wd_in[329]
    DIRECTION OUTPUT ;
    USE SIGNAL ;
    SHAPE ABUTMENT ;
    PORT
      LAYER metal2 ;
      RECT 1.865 0.000 1.935 0.210 ;
    END
  END w0_wd_in[329]
  PIN w0_wd_in[330]
    DIRECTION OUTPUT ;
    USE SIGNAL ;
    SHAPE ABUTMENT ;
    PORT
      LAYER metal2 ;
      RECT 2.245 0.000 2.315 0.210 ;
    END
  END w0_wd_in[330]
  PIN w0_wd_in[331]
    DIRECTION OUTPUT ;
    USE SIGNAL ;
    SHAPE ABUTMENT ;
    PORT
      LAYER metal2 ;
      RECT 2.625 0.000 2.695 0.210 ;
    END
  END w0_wd_in[331]
  PIN w0_wd_in[332]
    DIRECTION OUTPUT ;
    USE SIGNAL ;
    SHAPE ABUTMENT ;
    PORT
      LAYER metal2 ;
      RECT 3.005 0.000 3.075 0.210 ;
    END
  END w0_wd_in[332]
  PIN w0_wd_in[333]
    DIRECTION OUTPUT ;
    USE SIGNAL ;
    SHAPE ABUTMENT ;
    PORT
      LAYER metal2 ;
      RECT 3.385 0.000 3.455 0.210 ;
    END
  END w0_wd_in[333]
  PIN w0_wd_in[334]
    DIRECTION OUTPUT ;
    USE SIGNAL ;
    SHAPE ABUTMENT ;
    PORT
      LAYER metal2 ;
      RECT 3.765 0.000 3.835 0.210 ;
    END
  END w0_wd_in[334]
  PIN w0_wd_in[335]
    DIRECTION OUTPUT ;
    USE SIGNAL ;
    SHAPE ABUTMENT ;
    PORT
      LAYER metal2 ;
      RECT 4.145 0.000 4.215 0.210 ;
    END
  END w0_wd_in[335]
  PIN w0_wd_in[336]
    DIRECTION OUTPUT ;
    USE SIGNAL ;
    SHAPE ABUTMENT ;
    PORT
      LAYER metal2 ;
      RECT 4.525 0.000 4.595 0.210 ;
    END
  END w0_wd_in[336]
  PIN w0_wd_in[337]
    DIRECTION OUTPUT ;
    USE SIGNAL ;
    SHAPE ABUTMENT ;
    PORT
      LAYER metal2 ;
      RECT 4.905 0.000 4.975 0.210 ;
    END
  END w0_wd_in[337]
  PIN w0_wd_in[338]
    DIRECTION OUTPUT ;
    USE SIGNAL ;
    SHAPE ABUTMENT ;
    PORT
      LAYER metal2 ;
      RECT 5.285 0.000 5.355 0.210 ;
    END
  END w0_wd_in[338]
  PIN w0_wd_in[339]
    DIRECTION OUTPUT ;
    USE SIGNAL ;
    SHAPE ABUTMENT ;
    PORT
      LAYER metal2 ;
      RECT 5.665 0.000 5.735 0.210 ;
    END
  END w0_wd_in[339]
  PIN w0_wd_in[340]
    DIRECTION OUTPUT ;
    USE SIGNAL ;
    SHAPE ABUTMENT ;
    PORT
      LAYER metal2 ;
      RECT 6.045 0.000 6.115 0.210 ;
    END
  END w0_wd_in[340]
  PIN w0_wd_in[341]
    DIRECTION OUTPUT ;
    USE SIGNAL ;
    SHAPE ABUTMENT ;
    PORT
      LAYER metal2 ;
      RECT 6.425 0.000 6.495 0.210 ;
    END
  END w0_wd_in[341]
  PIN w0_wd_in[342]
    DIRECTION OUTPUT ;
    USE SIGNAL ;
    SHAPE ABUTMENT ;
    PORT
      LAYER metal2 ;
      RECT 6.805 0.000 6.875 0.210 ;
    END
  END w0_wd_in[342]
  PIN w0_wd_in[343]
    DIRECTION OUTPUT ;
    USE SIGNAL ;
    SHAPE ABUTMENT ;
    PORT
      LAYER metal2 ;
      RECT 7.185 0.000 7.255 0.210 ;
    END
  END w0_wd_in[343]
  PIN w0_wd_in[344]
    DIRECTION OUTPUT ;
    USE SIGNAL ;
    SHAPE ABUTMENT ;
    PORT
      LAYER metal2 ;
      RECT 7.565 0.000 7.635 0.210 ;
    END
  END w0_wd_in[344]
  PIN w0_wd_in[345]
    DIRECTION OUTPUT ;
    USE SIGNAL ;
    SHAPE ABUTMENT ;
    PORT
      LAYER metal2 ;
      RECT 7.945 0.000 8.015 0.210 ;
    END
  END w0_wd_in[345]
  PIN w0_wd_in[346]
    DIRECTION OUTPUT ;
    USE SIGNAL ;
    SHAPE ABUTMENT ;
    PORT
      LAYER metal2 ;
      RECT 8.325 0.000 8.395 0.210 ;
    END
  END w0_wd_in[346]
  PIN w0_wd_in[347]
    DIRECTION OUTPUT ;
    USE SIGNAL ;
    SHAPE ABUTMENT ;
    PORT
      LAYER metal2 ;
      RECT 8.705 0.000 8.775 0.210 ;
    END
  END w0_wd_in[347]
  PIN w0_wd_in[348]
    DIRECTION OUTPUT ;
    USE SIGNAL ;
    SHAPE ABUTMENT ;
    PORT
      LAYER metal2 ;
      RECT 9.085 0.000 9.155 0.210 ;
    END
  END w0_wd_in[348]
  PIN w0_wd_in[349]
    DIRECTION OUTPUT ;
    USE SIGNAL ;
    SHAPE ABUTMENT ;
    PORT
      LAYER metal2 ;
      RECT 9.465 0.000 9.535 0.210 ;
    END
  END w0_wd_in[349]
  PIN w0_wd_in[350]
    DIRECTION OUTPUT ;
    USE SIGNAL ;
    SHAPE ABUTMENT ;
    PORT
      LAYER metal2 ;
      RECT 9.845 0.000 9.915 0.210 ;
    END
  END w0_wd_in[350]
  PIN w0_wd_in[351]
    DIRECTION OUTPUT ;
    USE SIGNAL ;
    SHAPE ABUTMENT ;
    PORT
      LAYER metal2 ;
      RECT 10.225 0.000 10.295 0.210 ;
    END
  END w0_wd_in[351]
  PIN w0_wd_in[352]
    DIRECTION OUTPUT ;
    USE SIGNAL ;
    SHAPE ABUTMENT ;
    PORT
      LAYER metal2 ;
      RECT 10.605 0.000 10.675 0.210 ;
    END
  END w0_wd_in[352]
  PIN w0_wd_in[353]
    DIRECTION OUTPUT ;
    USE SIGNAL ;
    SHAPE ABUTMENT ;
    PORT
      LAYER metal2 ;
      RECT 10.985 0.000 11.055 0.210 ;
    END
  END w0_wd_in[353]
  PIN w0_wd_in[354]
    DIRECTION OUTPUT ;
    USE SIGNAL ;
    SHAPE ABUTMENT ;
    PORT
      LAYER metal2 ;
      RECT 11.365 0.000 11.435 0.210 ;
    END
  END w0_wd_in[354]
  PIN w0_wd_in[355]
    DIRECTION OUTPUT ;
    USE SIGNAL ;
    SHAPE ABUTMENT ;
    PORT
      LAYER metal2 ;
      RECT 11.745 0.000 11.815 0.210 ;
    END
  END w0_wd_in[355]
  PIN w0_wd_in[356]
    DIRECTION OUTPUT ;
    USE SIGNAL ;
    SHAPE ABUTMENT ;
    PORT
      LAYER metal2 ;
      RECT 12.125 0.000 12.195 0.210 ;
    END
  END w0_wd_in[356]
  PIN w0_wd_in[357]
    DIRECTION OUTPUT ;
    USE SIGNAL ;
    SHAPE ABUTMENT ;
    PORT
      LAYER metal2 ;
      RECT 12.505 0.000 12.575 0.210 ;
    END
  END w0_wd_in[357]
  PIN w0_wd_in[358]
    DIRECTION OUTPUT ;
    USE SIGNAL ;
    SHAPE ABUTMENT ;
    PORT
      LAYER metal2 ;
      RECT 12.885 0.000 12.955 0.210 ;
    END
  END w0_wd_in[358]
  PIN w0_wd_in[359]
    DIRECTION OUTPUT ;
    USE SIGNAL ;
    SHAPE ABUTMENT ;
    PORT
      LAYER metal2 ;
      RECT 13.265 0.000 13.335 0.210 ;
    END
  END w0_wd_in[359]
  PIN w0_wd_in[360]
    DIRECTION OUTPUT ;
    USE SIGNAL ;
    SHAPE ABUTMENT ;
    PORT
      LAYER metal2 ;
      RECT 13.645 0.000 13.715 0.210 ;
    END
  END w0_wd_in[360]
  PIN w0_wd_in[361]
    DIRECTION OUTPUT ;
    USE SIGNAL ;
    SHAPE ABUTMENT ;
    PORT
      LAYER metal2 ;
      RECT 14.025 0.000 14.095 0.210 ;
    END
  END w0_wd_in[361]
  PIN w0_wd_in[362]
    DIRECTION OUTPUT ;
    USE SIGNAL ;
    SHAPE ABUTMENT ;
    PORT
      LAYER metal2 ;
      RECT 14.405 0.000 14.475 0.210 ;
    END
  END w0_wd_in[362]
  PIN w0_wd_in[363]
    DIRECTION OUTPUT ;
    USE SIGNAL ;
    SHAPE ABUTMENT ;
    PORT
      LAYER metal2 ;
      RECT 14.785 0.000 14.855 0.210 ;
    END
  END w0_wd_in[363]
  PIN w0_wd_in[364]
    DIRECTION OUTPUT ;
    USE SIGNAL ;
    SHAPE ABUTMENT ;
    PORT
      LAYER metal2 ;
      RECT 15.165 0.000 15.235 0.210 ;
    END
  END w0_wd_in[364]
  PIN w0_wd_in[365]
    DIRECTION OUTPUT ;
    USE SIGNAL ;
    SHAPE ABUTMENT ;
    PORT
      LAYER metal2 ;
      RECT 15.545 0.000 15.615 0.210 ;
    END
  END w0_wd_in[365]
  PIN w0_wd_in[366]
    DIRECTION OUTPUT ;
    USE SIGNAL ;
    SHAPE ABUTMENT ;
    PORT
      LAYER metal2 ;
      RECT 15.925 0.000 15.995 0.210 ;
    END
  END w0_wd_in[366]
  PIN w0_wd_in[367]
    DIRECTION OUTPUT ;
    USE SIGNAL ;
    SHAPE ABUTMENT ;
    PORT
      LAYER metal2 ;
      RECT 16.305 0.000 16.375 0.210 ;
    END
  END w0_wd_in[367]
  PIN w0_wd_in[368]
    DIRECTION OUTPUT ;
    USE SIGNAL ;
    SHAPE ABUTMENT ;
    PORT
      LAYER metal2 ;
      RECT 16.685 0.000 16.755 0.210 ;
    END
  END w0_wd_in[368]
  PIN w0_wd_in[369]
    DIRECTION OUTPUT ;
    USE SIGNAL ;
    SHAPE ABUTMENT ;
    PORT
      LAYER metal2 ;
      RECT 17.065 0.000 17.135 0.210 ;
    END
  END w0_wd_in[369]
  PIN w0_wd_in[370]
    DIRECTION OUTPUT ;
    USE SIGNAL ;
    SHAPE ABUTMENT ;
    PORT
      LAYER metal2 ;
      RECT 17.445 0.000 17.515 0.210 ;
    END
  END w0_wd_in[370]
  PIN w0_wd_in[371]
    DIRECTION OUTPUT ;
    USE SIGNAL ;
    SHAPE ABUTMENT ;
    PORT
      LAYER metal2 ;
      RECT 17.825 0.000 17.895 0.210 ;
    END
  END w0_wd_in[371]
  PIN w0_wd_in[372]
    DIRECTION OUTPUT ;
    USE SIGNAL ;
    SHAPE ABUTMENT ;
    PORT
      LAYER metal2 ;
      RECT 18.205 0.000 18.275 0.210 ;
    END
  END w0_wd_in[372]
  PIN w0_wd_in[373]
    DIRECTION OUTPUT ;
    USE SIGNAL ;
    SHAPE ABUTMENT ;
    PORT
      LAYER metal2 ;
      RECT 18.585 0.000 18.655 0.210 ;
    END
  END w0_wd_in[373]
  PIN w0_wd_in[374]
    DIRECTION OUTPUT ;
    USE SIGNAL ;
    SHAPE ABUTMENT ;
    PORT
      LAYER metal2 ;
      RECT 18.965 0.000 19.035 0.210 ;
    END
  END w0_wd_in[374]
  PIN w0_wd_in[375]
    DIRECTION OUTPUT ;
    USE SIGNAL ;
    SHAPE ABUTMENT ;
    PORT
      LAYER metal2 ;
      RECT 19.345 0.000 19.415 0.210 ;
    END
  END w0_wd_in[375]
  PIN w0_wd_in[376]
    DIRECTION OUTPUT ;
    USE SIGNAL ;
    SHAPE ABUTMENT ;
    PORT
      LAYER metal2 ;
      RECT 19.725 0.000 19.795 0.210 ;
    END
  END w0_wd_in[376]
  PIN w0_wd_in[377]
    DIRECTION OUTPUT ;
    USE SIGNAL ;
    SHAPE ABUTMENT ;
    PORT
      LAYER metal2 ;
      RECT 20.105 0.000 20.175 0.210 ;
    END
  END w0_wd_in[377]
  PIN w0_wd_in[378]
    DIRECTION OUTPUT ;
    USE SIGNAL ;
    SHAPE ABUTMENT ;
    PORT
      LAYER metal2 ;
      RECT 20.485 0.000 20.555 0.210 ;
    END
  END w0_wd_in[378]
  PIN w0_wd_in[379]
    DIRECTION OUTPUT ;
    USE SIGNAL ;
    SHAPE ABUTMENT ;
    PORT
      LAYER metal2 ;
      RECT 20.865 0.000 20.935 0.210 ;
    END
  END w0_wd_in[379]
  PIN w0_wd_in[380]
    DIRECTION OUTPUT ;
    USE SIGNAL ;
    SHAPE ABUTMENT ;
    PORT
      LAYER metal2 ;
      RECT 21.245 0.000 21.315 0.210 ;
    END
  END w0_wd_in[380]
  PIN w0_wd_in[381]
    DIRECTION OUTPUT ;
    USE SIGNAL ;
    SHAPE ABUTMENT ;
    PORT
      LAYER metal2 ;
      RECT 21.625 0.000 21.695 0.210 ;
    END
  END w0_wd_in[381]
  PIN w0_wd_in[382]
    DIRECTION OUTPUT ;
    USE SIGNAL ;
    SHAPE ABUTMENT ;
    PORT
      LAYER metal2 ;
      RECT 22.005 0.000 22.075 0.210 ;
    END
  END w0_wd_in[382]
  PIN w0_wd_in[383]
    DIRECTION OUTPUT ;
    USE SIGNAL ;
    SHAPE ABUTMENT ;
    PORT
      LAYER metal2 ;
      RECT 22.385 0.000 22.455 0.210 ;
    END
  END w0_wd_in[383]
  PIN w0_wd_in[384]
    DIRECTION OUTPUT ;
    USE SIGNAL ;
    SHAPE ABUTMENT ;
    PORT
      LAYER metal2 ;
      RECT 22.765 0.000 22.835 0.210 ;
    END
  END w0_wd_in[384]
  PIN w0_wd_in[385]
    DIRECTION OUTPUT ;
    USE SIGNAL ;
    SHAPE ABUTMENT ;
    PORT
      LAYER metal2 ;
      RECT 23.145 0.000 23.215 0.210 ;
    END
  END w0_wd_in[385]
  PIN w0_wd_in[386]
    DIRECTION OUTPUT ;
    USE SIGNAL ;
    SHAPE ABUTMENT ;
    PORT
      LAYER metal2 ;
      RECT 23.525 0.000 23.595 0.210 ;
    END
  END w0_wd_in[386]
  PIN w0_wd_in[387]
    DIRECTION OUTPUT ;
    USE SIGNAL ;
    SHAPE ABUTMENT ;
    PORT
      LAYER metal2 ;
      RECT 23.905 0.000 23.975 0.210 ;
    END
  END w0_wd_in[387]
  PIN w0_wd_in[388]
    DIRECTION OUTPUT ;
    USE SIGNAL ;
    SHAPE ABUTMENT ;
    PORT
      LAYER metal2 ;
      RECT 24.285 0.000 24.355 0.210 ;
    END
  END w0_wd_in[388]
  PIN w0_wd_in[389]
    DIRECTION OUTPUT ;
    USE SIGNAL ;
    SHAPE ABUTMENT ;
    PORT
      LAYER metal2 ;
      RECT 24.665 0.000 24.735 0.210 ;
    END
  END w0_wd_in[389]
  PIN w0_wd_in[390]
    DIRECTION OUTPUT ;
    USE SIGNAL ;
    SHAPE ABUTMENT ;
    PORT
      LAYER metal2 ;
      RECT 25.045 0.000 25.115 0.210 ;
    END
  END w0_wd_in[390]
  PIN w0_wd_in[391]
    DIRECTION OUTPUT ;
    USE SIGNAL ;
    SHAPE ABUTMENT ;
    PORT
      LAYER metal2 ;
      RECT 25.425 0.000 25.495 0.210 ;
    END
  END w0_wd_in[391]
  PIN w0_wd_in[392]
    DIRECTION OUTPUT ;
    USE SIGNAL ;
    SHAPE ABUTMENT ;
    PORT
      LAYER metal2 ;
      RECT 25.805 0.000 25.875 0.210 ;
    END
  END w0_wd_in[392]
  PIN w0_wd_in[393]
    DIRECTION OUTPUT ;
    USE SIGNAL ;
    SHAPE ABUTMENT ;
    PORT
      LAYER metal2 ;
      RECT 26.185 0.000 26.255 0.210 ;
    END
  END w0_wd_in[393]
  PIN w0_wd_in[394]
    DIRECTION OUTPUT ;
    USE SIGNAL ;
    SHAPE ABUTMENT ;
    PORT
      LAYER metal2 ;
      RECT 26.565 0.000 26.635 0.210 ;
    END
  END w0_wd_in[394]
  PIN w0_wd_in[395]
    DIRECTION OUTPUT ;
    USE SIGNAL ;
    SHAPE ABUTMENT ;
    PORT
      LAYER metal2 ;
      RECT 26.945 0.000 27.015 0.210 ;
    END
  END w0_wd_in[395]
  PIN w0_wd_in[396]
    DIRECTION OUTPUT ;
    USE SIGNAL ;
    SHAPE ABUTMENT ;
    PORT
      LAYER metal2 ;
      RECT 27.325 0.000 27.395 0.210 ;
    END
  END w0_wd_in[396]
  PIN w0_wd_in[397]
    DIRECTION OUTPUT ;
    USE SIGNAL ;
    SHAPE ABUTMENT ;
    PORT
      LAYER metal2 ;
      RECT 27.705 0.000 27.775 0.210 ;
    END
  END w0_wd_in[397]
  PIN w0_wd_in[398]
    DIRECTION OUTPUT ;
    USE SIGNAL ;
    SHAPE ABUTMENT ;
    PORT
      LAYER metal2 ;
      RECT 28.085 0.000 28.155 0.210 ;
    END
  END w0_wd_in[398]
  PIN w0_wd_in[399]
    DIRECTION OUTPUT ;
    USE SIGNAL ;
    SHAPE ABUTMENT ;
    PORT
      LAYER metal2 ;
      RECT 28.465 0.000 28.535 0.210 ;
    END
  END w0_wd_in[399]
  PIN w0_wd_in[400]
    DIRECTION OUTPUT ;
    USE SIGNAL ;
    SHAPE ABUTMENT ;
    PORT
      LAYER metal2 ;
      RECT 28.845 0.000 28.915 0.210 ;
    END
  END w0_wd_in[400]
  PIN w0_wd_in[401]
    DIRECTION OUTPUT ;
    USE SIGNAL ;
    SHAPE ABUTMENT ;
    PORT
      LAYER metal2 ;
      RECT 29.225 0.000 29.295 0.210 ;
    END
  END w0_wd_in[401]
  PIN w0_wd_in[402]
    DIRECTION OUTPUT ;
    USE SIGNAL ;
    SHAPE ABUTMENT ;
    PORT
      LAYER metal2 ;
      RECT 29.605 0.000 29.675 0.210 ;
    END
  END w0_wd_in[402]
  PIN w0_wd_in[403]
    DIRECTION OUTPUT ;
    USE SIGNAL ;
    SHAPE ABUTMENT ;
    PORT
      LAYER metal2 ;
      RECT 29.985 0.000 30.055 0.210 ;
    END
  END w0_wd_in[403]
  PIN w0_wd_in[404]
    DIRECTION OUTPUT ;
    USE SIGNAL ;
    SHAPE ABUTMENT ;
    PORT
      LAYER metal2 ;
      RECT 30.365 0.000 30.435 0.210 ;
    END
  END w0_wd_in[404]
  PIN w0_wd_in[405]
    DIRECTION OUTPUT ;
    USE SIGNAL ;
    SHAPE ABUTMENT ;
    PORT
      LAYER metal2 ;
      RECT 30.745 0.000 30.815 0.210 ;
    END
  END w0_wd_in[405]
  PIN w0_wd_in[406]
    DIRECTION OUTPUT ;
    USE SIGNAL ;
    SHAPE ABUTMENT ;
    PORT
      LAYER metal2 ;
      RECT 31.125 0.000 31.195 0.210 ;
    END
  END w0_wd_in[406]
  PIN w0_wd_in[407]
    DIRECTION OUTPUT ;
    USE SIGNAL ;
    SHAPE ABUTMENT ;
    PORT
      LAYER metal2 ;
      RECT 31.505 0.000 31.575 0.210 ;
    END
  END w0_wd_in[407]
  PIN w0_wd_in[408]
    DIRECTION OUTPUT ;
    USE SIGNAL ;
    SHAPE ABUTMENT ;
    PORT
      LAYER metal2 ;
      RECT 31.885 0.000 31.955 0.210 ;
    END
  END w0_wd_in[408]
  PIN w0_wd_in[409]
    DIRECTION OUTPUT ;
    USE SIGNAL ;
    SHAPE ABUTMENT ;
    PORT
      LAYER metal2 ;
      RECT 32.265 0.000 32.335 0.210 ;
    END
  END w0_wd_in[409]
  PIN w0_wd_in[410]
    DIRECTION OUTPUT ;
    USE SIGNAL ;
    SHAPE ABUTMENT ;
    PORT
      LAYER metal2 ;
      RECT 32.645 0.000 32.715 0.210 ;
    END
  END w0_wd_in[410]
  PIN w0_wd_in[411]
    DIRECTION OUTPUT ;
    USE SIGNAL ;
    SHAPE ABUTMENT ;
    PORT
      LAYER metal2 ;
      RECT 33.025 0.000 33.095 0.210 ;
    END
  END w0_wd_in[411]
  PIN w0_wd_in[412]
    DIRECTION OUTPUT ;
    USE SIGNAL ;
    SHAPE ABUTMENT ;
    PORT
      LAYER metal2 ;
      RECT 33.405 0.000 33.475 0.210 ;
    END
  END w0_wd_in[412]
  PIN w0_wd_in[413]
    DIRECTION OUTPUT ;
    USE SIGNAL ;
    SHAPE ABUTMENT ;
    PORT
      LAYER metal2 ;
      RECT 33.785 0.000 33.855 0.210 ;
    END
  END w0_wd_in[413]
  PIN w0_wd_in[414]
    DIRECTION OUTPUT ;
    USE SIGNAL ;
    SHAPE ABUTMENT ;
    PORT
      LAYER metal2 ;
      RECT 34.165 0.000 34.235 0.210 ;
    END
  END w0_wd_in[414]
  PIN w0_wd_in[415]
    DIRECTION OUTPUT ;
    USE SIGNAL ;
    SHAPE ABUTMENT ;
    PORT
      LAYER metal2 ;
      RECT 34.545 0.000 34.615 0.210 ;
    END
  END w0_wd_in[415]
  PIN w0_wd_in[416]
    DIRECTION OUTPUT ;
    USE SIGNAL ;
    SHAPE ABUTMENT ;
    PORT
      LAYER metal2 ;
      RECT 34.925 0.000 34.995 0.210 ;
    END
  END w0_wd_in[416]
  PIN w0_wd_in[417]
    DIRECTION OUTPUT ;
    USE SIGNAL ;
    SHAPE ABUTMENT ;
    PORT
      LAYER metal2 ;
      RECT 35.305 0.000 35.375 0.210 ;
    END
  END w0_wd_in[417]
  PIN w0_wd_in[418]
    DIRECTION OUTPUT ;
    USE SIGNAL ;
    SHAPE ABUTMENT ;
    PORT
      LAYER metal2 ;
      RECT 35.685 0.000 35.755 0.210 ;
    END
  END w0_wd_in[418]
  PIN w0_wd_in[419]
    DIRECTION OUTPUT ;
    USE SIGNAL ;
    SHAPE ABUTMENT ;
    PORT
      LAYER metal2 ;
      RECT 36.065 0.000 36.135 0.210 ;
    END
  END w0_wd_in[419]
  PIN w0_wd_in[420]
    DIRECTION OUTPUT ;
    USE SIGNAL ;
    SHAPE ABUTMENT ;
    PORT
      LAYER metal2 ;
      RECT 36.445 0.000 36.515 0.210 ;
    END
  END w0_wd_in[420]
  PIN w0_wd_in[421]
    DIRECTION OUTPUT ;
    USE SIGNAL ;
    SHAPE ABUTMENT ;
    PORT
      LAYER metal2 ;
      RECT 36.825 0.000 36.895 0.210 ;
    END
  END w0_wd_in[421]
  PIN w0_wd_in[422]
    DIRECTION OUTPUT ;
    USE SIGNAL ;
    SHAPE ABUTMENT ;
    PORT
      LAYER metal2 ;
      RECT 37.205 0.000 37.275 0.210 ;
    END
  END w0_wd_in[422]
  PIN w0_wd_in[423]
    DIRECTION OUTPUT ;
    USE SIGNAL ;
    SHAPE ABUTMENT ;
    PORT
      LAYER metal2 ;
      RECT 37.585 0.000 37.655 0.210 ;
    END
  END w0_wd_in[423]
  PIN w0_wd_in[424]
    DIRECTION OUTPUT ;
    USE SIGNAL ;
    SHAPE ABUTMENT ;
    PORT
      LAYER metal2 ;
      RECT 37.965 0.000 38.035 0.210 ;
    END
  END w0_wd_in[424]
  PIN w0_wd_in[425]
    DIRECTION OUTPUT ;
    USE SIGNAL ;
    SHAPE ABUTMENT ;
    PORT
      LAYER metal2 ;
      RECT 38.345 0.000 38.415 0.210 ;
    END
  END w0_wd_in[425]
  PIN w0_wd_in[426]
    DIRECTION OUTPUT ;
    USE SIGNAL ;
    SHAPE ABUTMENT ;
    PORT
      LAYER metal2 ;
      RECT 38.725 0.000 38.795 0.210 ;
    END
  END w0_wd_in[426]
  PIN w0_wd_in[427]
    DIRECTION OUTPUT ;
    USE SIGNAL ;
    SHAPE ABUTMENT ;
    PORT
      LAYER metal2 ;
      RECT 39.105 0.000 39.175 0.210 ;
    END
  END w0_wd_in[427]
  PIN w0_wd_in[428]
    DIRECTION OUTPUT ;
    USE SIGNAL ;
    SHAPE ABUTMENT ;
    PORT
      LAYER metal2 ;
      RECT 39.485 0.000 39.555 0.210 ;
    END
  END w0_wd_in[428]
  PIN w0_wd_in[429]
    DIRECTION OUTPUT ;
    USE SIGNAL ;
    SHAPE ABUTMENT ;
    PORT
      LAYER metal2 ;
      RECT 39.865 0.000 39.935 0.210 ;
    END
  END w0_wd_in[429]
  PIN w0_wd_in[430]
    DIRECTION OUTPUT ;
    USE SIGNAL ;
    SHAPE ABUTMENT ;
    PORT
      LAYER metal2 ;
      RECT 40.245 0.000 40.315 0.210 ;
    END
  END w0_wd_in[430]
  PIN w0_wd_in[431]
    DIRECTION OUTPUT ;
    USE SIGNAL ;
    SHAPE ABUTMENT ;
    PORT
      LAYER metal2 ;
      RECT 40.625 0.000 40.695 0.210 ;
    END
  END w0_wd_in[431]
  PIN w0_wd_in[432]
    DIRECTION OUTPUT ;
    USE SIGNAL ;
    SHAPE ABUTMENT ;
    PORT
      LAYER metal2 ;
      RECT 41.005 0.000 41.075 0.210 ;
    END
  END w0_wd_in[432]
  PIN w0_wd_in[433]
    DIRECTION OUTPUT ;
    USE SIGNAL ;
    SHAPE ABUTMENT ;
    PORT
      LAYER metal2 ;
      RECT 41.385 0.000 41.455 0.210 ;
    END
  END w0_wd_in[433]
  PIN w0_wd_in[434]
    DIRECTION OUTPUT ;
    USE SIGNAL ;
    SHAPE ABUTMENT ;
    PORT
      LAYER metal2 ;
      RECT 41.765 0.000 41.835 0.210 ;
    END
  END w0_wd_in[434]
  PIN w0_wd_in[435]
    DIRECTION OUTPUT ;
    USE SIGNAL ;
    SHAPE ABUTMENT ;
    PORT
      LAYER metal2 ;
      RECT 42.145 0.000 42.215 0.210 ;
    END
  END w0_wd_in[435]
  PIN w0_wd_in[436]
    DIRECTION OUTPUT ;
    USE SIGNAL ;
    SHAPE ABUTMENT ;
    PORT
      LAYER metal2 ;
      RECT 42.525 0.000 42.595 0.210 ;
    END
  END w0_wd_in[436]
  PIN w0_wd_in[437]
    DIRECTION OUTPUT ;
    USE SIGNAL ;
    SHAPE ABUTMENT ;
    PORT
      LAYER metal2 ;
      RECT 42.905 0.000 42.975 0.210 ;
    END
  END w0_wd_in[437]
  PIN w0_wd_in[438]
    DIRECTION OUTPUT ;
    USE SIGNAL ;
    SHAPE ABUTMENT ;
    PORT
      LAYER metal2 ;
      RECT 43.285 0.000 43.355 0.210 ;
    END
  END w0_wd_in[438]
  PIN w0_wd_in[439]
    DIRECTION OUTPUT ;
    USE SIGNAL ;
    SHAPE ABUTMENT ;
    PORT
      LAYER metal2 ;
      RECT 43.665 0.000 43.735 0.210 ;
    END
  END w0_wd_in[439]
  PIN w0_wd_in[440]
    DIRECTION OUTPUT ;
    USE SIGNAL ;
    SHAPE ABUTMENT ;
    PORT
      LAYER metal2 ;
      RECT 44.045 0.000 44.115 0.210 ;
    END
  END w0_wd_in[440]
  PIN w0_wd_in[441]
    DIRECTION OUTPUT ;
    USE SIGNAL ;
    SHAPE ABUTMENT ;
    PORT
      LAYER metal2 ;
      RECT 44.425 0.000 44.495 0.210 ;
    END
  END w0_wd_in[441]
  PIN w0_wd_in[442]
    DIRECTION OUTPUT ;
    USE SIGNAL ;
    SHAPE ABUTMENT ;
    PORT
      LAYER metal2 ;
      RECT 44.805 0.000 44.875 0.210 ;
    END
  END w0_wd_in[442]
  PIN w0_wd_in[443]
    DIRECTION OUTPUT ;
    USE SIGNAL ;
    SHAPE ABUTMENT ;
    PORT
      LAYER metal2 ;
      RECT 45.185 0.000 45.255 0.210 ;
    END
  END w0_wd_in[443]
  PIN w0_wd_in[444]
    DIRECTION OUTPUT ;
    USE SIGNAL ;
    SHAPE ABUTMENT ;
    PORT
      LAYER metal2 ;
      RECT 45.565 0.000 45.635 0.210 ;
    END
  END w0_wd_in[444]
  PIN w0_wd_in[445]
    DIRECTION OUTPUT ;
    USE SIGNAL ;
    SHAPE ABUTMENT ;
    PORT
      LAYER metal2 ;
      RECT 45.945 0.000 46.015 0.210 ;
    END
  END w0_wd_in[445]
  PIN w0_wd_in[446]
    DIRECTION OUTPUT ;
    USE SIGNAL ;
    SHAPE ABUTMENT ;
    PORT
      LAYER metal2 ;
      RECT 46.325 0.000 46.395 0.210 ;
    END
  END w0_wd_in[446]
  PIN w0_wd_in[447]
    DIRECTION OUTPUT ;
    USE SIGNAL ;
    SHAPE ABUTMENT ;
    PORT
      LAYER metal2 ;
      RECT 46.705 0.000 46.775 0.210 ;
    END
  END w0_wd_in[447]
  PIN w0_wd_in[448]
    DIRECTION OUTPUT ;
    USE SIGNAL ;
    SHAPE ABUTMENT ;
    PORT
      LAYER metal2 ;
      RECT 47.085 0.000 47.155 0.210 ;
    END
  END w0_wd_in[448]
  PIN w0_wd_in[449]
    DIRECTION OUTPUT ;
    USE SIGNAL ;
    SHAPE ABUTMENT ;
    PORT
      LAYER metal2 ;
      RECT 47.465 0.000 47.535 0.210 ;
    END
  END w0_wd_in[449]
  PIN w0_wd_in[450]
    DIRECTION OUTPUT ;
    USE SIGNAL ;
    SHAPE ABUTMENT ;
    PORT
      LAYER metal2 ;
      RECT 47.845 0.000 47.915 0.210 ;
    END
  END w0_wd_in[450]
  PIN w0_wd_in[451]
    DIRECTION OUTPUT ;
    USE SIGNAL ;
    SHAPE ABUTMENT ;
    PORT
      LAYER metal2 ;
      RECT 48.225 0.000 48.295 0.210 ;
    END
  END w0_wd_in[451]
  PIN w0_wd_in[452]
    DIRECTION OUTPUT ;
    USE SIGNAL ;
    SHAPE ABUTMENT ;
    PORT
      LAYER metal2 ;
      RECT 48.605 0.000 48.675 0.210 ;
    END
  END w0_wd_in[452]
  PIN w0_wd_in[453]
    DIRECTION OUTPUT ;
    USE SIGNAL ;
    SHAPE ABUTMENT ;
    PORT
      LAYER metal2 ;
      RECT 48.985 0.000 49.055 0.210 ;
    END
  END w0_wd_in[453]
  PIN w0_wd_in[454]
    DIRECTION OUTPUT ;
    USE SIGNAL ;
    SHAPE ABUTMENT ;
    PORT
      LAYER metal2 ;
      RECT 49.365 0.000 49.435 0.210 ;
    END
  END w0_wd_in[454]
  PIN w0_wd_in[455]
    DIRECTION OUTPUT ;
    USE SIGNAL ;
    SHAPE ABUTMENT ;
    PORT
      LAYER metal2 ;
      RECT 49.745 0.000 49.815 0.210 ;
    END
  END w0_wd_in[455]
  PIN w0_wd_in[456]
    DIRECTION OUTPUT ;
    USE SIGNAL ;
    SHAPE ABUTMENT ;
    PORT
      LAYER metal2 ;
      RECT 50.125 0.000 50.195 0.210 ;
    END
  END w0_wd_in[456]
  PIN w0_wd_in[457]
    DIRECTION OUTPUT ;
    USE SIGNAL ;
    SHAPE ABUTMENT ;
    PORT
      LAYER metal2 ;
      RECT 50.505 0.000 50.575 0.210 ;
    END
  END w0_wd_in[457]
  PIN w0_wd_in[458]
    DIRECTION OUTPUT ;
    USE SIGNAL ;
    SHAPE ABUTMENT ;
    PORT
      LAYER metal2 ;
      RECT 50.885 0.000 50.955 0.210 ;
    END
  END w0_wd_in[458]
  PIN w0_wd_in[459]
    DIRECTION OUTPUT ;
    USE SIGNAL ;
    SHAPE ABUTMENT ;
    PORT
      LAYER metal2 ;
      RECT 51.265 0.000 51.335 0.210 ;
    END
  END w0_wd_in[459]
  PIN w0_wd_in[460]
    DIRECTION OUTPUT ;
    USE SIGNAL ;
    SHAPE ABUTMENT ;
    PORT
      LAYER metal2 ;
      RECT 51.645 0.000 51.715 0.210 ;
    END
  END w0_wd_in[460]
  PIN w0_wd_in[461]
    DIRECTION OUTPUT ;
    USE SIGNAL ;
    SHAPE ABUTMENT ;
    PORT
      LAYER metal2 ;
      RECT 52.025 0.000 52.095 0.210 ;
    END
  END w0_wd_in[461]
  PIN w0_wd_in[462]
    DIRECTION OUTPUT ;
    USE SIGNAL ;
    SHAPE ABUTMENT ;
    PORT
      LAYER metal2 ;
      RECT 52.405 0.000 52.475 0.210 ;
    END
  END w0_wd_in[462]
  PIN w0_wd_in[463]
    DIRECTION OUTPUT ;
    USE SIGNAL ;
    SHAPE ABUTMENT ;
    PORT
      LAYER metal2 ;
      RECT 52.785 0.000 52.855 0.210 ;
    END
  END w0_wd_in[463]
  PIN w0_wd_in[464]
    DIRECTION OUTPUT ;
    USE SIGNAL ;
    SHAPE ABUTMENT ;
    PORT
      LAYER metal2 ;
      RECT 53.165 0.000 53.235 0.210 ;
    END
  END w0_wd_in[464]
  PIN w0_wd_in[465]
    DIRECTION OUTPUT ;
    USE SIGNAL ;
    SHAPE ABUTMENT ;
    PORT
      LAYER metal2 ;
      RECT 53.545 0.000 53.615 0.210 ;
    END
  END w0_wd_in[465]
  PIN w0_wd_in[466]
    DIRECTION OUTPUT ;
    USE SIGNAL ;
    SHAPE ABUTMENT ;
    PORT
      LAYER metal2 ;
      RECT 53.925 0.000 53.995 0.210 ;
    END
  END w0_wd_in[466]
  PIN w0_wd_in[467]
    DIRECTION OUTPUT ;
    USE SIGNAL ;
    SHAPE ABUTMENT ;
    PORT
      LAYER metal2 ;
      RECT 54.305 0.000 54.375 0.210 ;
    END
  END w0_wd_in[467]
  PIN w0_wd_in[468]
    DIRECTION OUTPUT ;
    USE SIGNAL ;
    SHAPE ABUTMENT ;
    PORT
      LAYER metal2 ;
      RECT 54.685 0.000 54.755 0.210 ;
    END
  END w0_wd_in[468]
  PIN w0_wd_in[469]
    DIRECTION OUTPUT ;
    USE SIGNAL ;
    SHAPE ABUTMENT ;
    PORT
      LAYER metal2 ;
      RECT 55.065 0.000 55.135 0.210 ;
    END
  END w0_wd_in[469]
  PIN w0_wd_in[470]
    DIRECTION OUTPUT ;
    USE SIGNAL ;
    SHAPE ABUTMENT ;
    PORT
      LAYER metal2 ;
      RECT 55.445 0.000 55.515 0.210 ;
    END
  END w0_wd_in[470]
  PIN w0_wd_in[471]
    DIRECTION OUTPUT ;
    USE SIGNAL ;
    SHAPE ABUTMENT ;
    PORT
      LAYER metal2 ;
      RECT 55.825 0.000 55.895 0.210 ;
    END
  END w0_wd_in[471]
  PIN w0_wd_in[472]
    DIRECTION OUTPUT ;
    USE SIGNAL ;
    SHAPE ABUTMENT ;
    PORT
      LAYER metal2 ;
      RECT 56.205 0.000 56.275 0.210 ;
    END
  END w0_wd_in[472]
  PIN w0_wd_in[473]
    DIRECTION OUTPUT ;
    USE SIGNAL ;
    SHAPE ABUTMENT ;
    PORT
      LAYER metal2 ;
      RECT 56.585 0.000 56.655 0.210 ;
    END
  END w0_wd_in[473]
  PIN w0_wd_in[474]
    DIRECTION OUTPUT ;
    USE SIGNAL ;
    SHAPE ABUTMENT ;
    PORT
      LAYER metal2 ;
      RECT 56.965 0.000 57.035 0.210 ;
    END
  END w0_wd_in[474]
  PIN w0_wd_in[475]
    DIRECTION OUTPUT ;
    USE SIGNAL ;
    SHAPE ABUTMENT ;
    PORT
      LAYER metal2 ;
      RECT 57.345 0.000 57.415 0.210 ;
    END
  END w0_wd_in[475]
  PIN w0_wd_in[476]
    DIRECTION OUTPUT ;
    USE SIGNAL ;
    SHAPE ABUTMENT ;
    PORT
      LAYER metal2 ;
      RECT 57.725 0.000 57.795 0.210 ;
    END
  END w0_wd_in[476]
  PIN w0_wd_in[477]
    DIRECTION OUTPUT ;
    USE SIGNAL ;
    SHAPE ABUTMENT ;
    PORT
      LAYER metal2 ;
      RECT 58.105 0.000 58.175 0.210 ;
    END
  END w0_wd_in[477]
  PIN w0_wd_in[478]
    DIRECTION OUTPUT ;
    USE SIGNAL ;
    SHAPE ABUTMENT ;
    PORT
      LAYER metal2 ;
      RECT 58.485 0.000 58.555 0.210 ;
    END
  END w0_wd_in[478]
  PIN w0_wd_in[479]
    DIRECTION OUTPUT ;
    USE SIGNAL ;
    SHAPE ABUTMENT ;
    PORT
      LAYER metal2 ;
      RECT 58.865 0.000 58.935 0.210 ;
    END
  END w0_wd_in[479]
  PIN w0_wd_in[480]
    DIRECTION OUTPUT ;
    USE SIGNAL ;
    SHAPE ABUTMENT ;
    PORT
      LAYER metal2 ;
      RECT 59.245 0.000 59.315 0.210 ;
    END
  END w0_wd_in[480]
  PIN w0_wd_in[481]
    DIRECTION OUTPUT ;
    USE SIGNAL ;
    SHAPE ABUTMENT ;
    PORT
      LAYER metal2 ;
      RECT 59.625 0.000 59.695 0.210 ;
    END
  END w0_wd_in[481]
  PIN w0_wd_in[482]
    DIRECTION OUTPUT ;
    USE SIGNAL ;
    SHAPE ABUTMENT ;
    PORT
      LAYER metal2 ;
      RECT 60.005 0.000 60.075 0.210 ;
    END
  END w0_wd_in[482]
  PIN w0_wd_in[483]
    DIRECTION OUTPUT ;
    USE SIGNAL ;
    SHAPE ABUTMENT ;
    PORT
      LAYER metal2 ;
      RECT 60.385 0.000 60.455 0.210 ;
    END
  END w0_wd_in[483]
  PIN w0_wd_in[484]
    DIRECTION OUTPUT ;
    USE SIGNAL ;
    SHAPE ABUTMENT ;
    PORT
      LAYER metal2 ;
      RECT 60.765 0.000 60.835 0.210 ;
    END
  END w0_wd_in[484]
  PIN w0_wd_in[485]
    DIRECTION OUTPUT ;
    USE SIGNAL ;
    SHAPE ABUTMENT ;
    PORT
      LAYER metal2 ;
      RECT 61.145 0.000 61.215 0.210 ;
    END
  END w0_wd_in[485]
  PIN w0_wd_in[486]
    DIRECTION OUTPUT ;
    USE SIGNAL ;
    SHAPE ABUTMENT ;
    PORT
      LAYER metal2 ;
      RECT 61.525 0.000 61.595 0.210 ;
    END
  END w0_wd_in[486]
  PIN w0_wd_in[487]
    DIRECTION OUTPUT ;
    USE SIGNAL ;
    SHAPE ABUTMENT ;
    PORT
      LAYER metal2 ;
      RECT 61.905 0.000 61.975 0.210 ;
    END
  END w0_wd_in[487]
  PIN w0_wd_in[488]
    DIRECTION OUTPUT ;
    USE SIGNAL ;
    SHAPE ABUTMENT ;
    PORT
      LAYER metal2 ;
      RECT 62.285 0.000 62.355 0.210 ;
    END
  END w0_wd_in[488]
  PIN w0_wd_in[489]
    DIRECTION OUTPUT ;
    USE SIGNAL ;
    SHAPE ABUTMENT ;
    PORT
      LAYER metal2 ;
      RECT 62.665 0.000 62.735 0.210 ;
    END
  END w0_wd_in[489]
  PIN w0_wd_in[490]
    DIRECTION OUTPUT ;
    USE SIGNAL ;
    SHAPE ABUTMENT ;
    PORT
      LAYER metal2 ;
      RECT 63.045 0.000 63.115 0.210 ;
    END
  END w0_wd_in[490]
  PIN w0_wd_in[491]
    DIRECTION OUTPUT ;
    USE SIGNAL ;
    SHAPE ABUTMENT ;
    PORT
      LAYER metal2 ;
      RECT 63.425 0.000 63.495 0.210 ;
    END
  END w0_wd_in[491]
  PIN w0_wd_in[492]
    DIRECTION OUTPUT ;
    USE SIGNAL ;
    SHAPE ABUTMENT ;
    PORT
      LAYER metal2 ;
      RECT 63.805 0.000 63.875 0.210 ;
    END
  END w0_wd_in[492]
  PIN w0_wd_in[493]
    DIRECTION OUTPUT ;
    USE SIGNAL ;
    SHAPE ABUTMENT ;
    PORT
      LAYER metal2 ;
      RECT 64.185 0.000 64.255 0.210 ;
    END
  END w0_wd_in[493]
  PIN w0_wd_in[494]
    DIRECTION OUTPUT ;
    USE SIGNAL ;
    SHAPE ABUTMENT ;
    PORT
      LAYER metal2 ;
      RECT 64.565 0.000 64.635 0.210 ;
    END
  END w0_wd_in[494]
  PIN w0_wd_in[495]
    DIRECTION OUTPUT ;
    USE SIGNAL ;
    SHAPE ABUTMENT ;
    PORT
      LAYER metal2 ;
      RECT 64.945 0.000 65.015 0.210 ;
    END
  END w0_wd_in[495]
  PIN w0_wd_in[496]
    DIRECTION OUTPUT ;
    USE SIGNAL ;
    SHAPE ABUTMENT ;
    PORT
      LAYER metal2 ;
      RECT 65.325 0.000 65.395 0.210 ;
    END
  END w0_wd_in[496]
  PIN w0_wd_in[497]
    DIRECTION OUTPUT ;
    USE SIGNAL ;
    SHAPE ABUTMENT ;
    PORT
      LAYER metal2 ;
      RECT 65.705 0.000 65.775 0.210 ;
    END
  END w0_wd_in[497]
  PIN w0_wd_in[498]
    DIRECTION OUTPUT ;
    USE SIGNAL ;
    SHAPE ABUTMENT ;
    PORT
      LAYER metal2 ;
      RECT 66.085 0.000 66.155 0.210 ;
    END
  END w0_wd_in[498]
  PIN w0_wd_in[499]
    DIRECTION OUTPUT ;
    USE SIGNAL ;
    SHAPE ABUTMENT ;
    PORT
      LAYER metal2 ;
      RECT 66.465 0.000 66.535 0.210 ;
    END
  END w0_wd_in[499]
  PIN w0_wd_in[500]
    DIRECTION OUTPUT ;
    USE SIGNAL ;
    SHAPE ABUTMENT ;
    PORT
      LAYER metal2 ;
      RECT 66.845 0.000 66.915 0.210 ;
    END
  END w0_wd_in[500]
  PIN w0_wd_in[501]
    DIRECTION OUTPUT ;
    USE SIGNAL ;
    SHAPE ABUTMENT ;
    PORT
      LAYER metal2 ;
      RECT 67.225 0.000 67.295 0.210 ;
    END
  END w0_wd_in[501]
  PIN w0_wd_in[502]
    DIRECTION OUTPUT ;
    USE SIGNAL ;
    SHAPE ABUTMENT ;
    PORT
      LAYER metal2 ;
      RECT 67.605 0.000 67.675 0.210 ;
    END
  END w0_wd_in[502]
  PIN w0_wd_in[503]
    DIRECTION OUTPUT ;
    USE SIGNAL ;
    SHAPE ABUTMENT ;
    PORT
      LAYER metal2 ;
      RECT 67.985 0.000 68.055 0.210 ;
    END
  END w0_wd_in[503]
  PIN w0_wd_in[504]
    DIRECTION OUTPUT ;
    USE SIGNAL ;
    SHAPE ABUTMENT ;
    PORT
      LAYER metal2 ;
      RECT 68.365 0.000 68.435 0.210 ;
    END
  END w0_wd_in[504]
  PIN w0_wd_in[505]
    DIRECTION OUTPUT ;
    USE SIGNAL ;
    SHAPE ABUTMENT ;
    PORT
      LAYER metal2 ;
      RECT 68.745 0.000 68.815 0.210 ;
    END
  END w0_wd_in[505]
  PIN w0_wd_in[506]
    DIRECTION OUTPUT ;
    USE SIGNAL ;
    SHAPE ABUTMENT ;
    PORT
      LAYER metal2 ;
      RECT 69.125 0.000 69.195 0.210 ;
    END
  END w0_wd_in[506]
  PIN w0_wd_in[507]
    DIRECTION OUTPUT ;
    USE SIGNAL ;
    SHAPE ABUTMENT ;
    PORT
      LAYER metal2 ;
      RECT 69.505 0.000 69.575 0.210 ;
    END
  END w0_wd_in[507]
  PIN w0_wd_in[508]
    DIRECTION OUTPUT ;
    USE SIGNAL ;
    SHAPE ABUTMENT ;
    PORT
      LAYER metal2 ;
      RECT 69.885 0.000 69.955 0.210 ;
    END
  END w0_wd_in[508]
  PIN w0_wd_in[509]
    DIRECTION OUTPUT ;
    USE SIGNAL ;
    SHAPE ABUTMENT ;
    PORT
      LAYER metal2 ;
      RECT 70.265 0.000 70.335 0.210 ;
    END
  END w0_wd_in[509]
  PIN w0_wd_in[510]
    DIRECTION OUTPUT ;
    USE SIGNAL ;
    SHAPE ABUTMENT ;
    PORT
      LAYER metal2 ;
      RECT 70.645 0.000 70.715 0.210 ;
    END
  END w0_wd_in[510]
  PIN w0_wd_in[511]
    DIRECTION OUTPUT ;
    USE SIGNAL ;
    SHAPE ABUTMENT ;
    PORT
      LAYER metal2 ;
      RECT 71.025 0.000 71.095 0.210 ;
    END
  END w0_wd_in[511]
  PIN w0_wd_in[512]
    DIRECTION OUTPUT ;
    USE SIGNAL ;
    SHAPE ABUTMENT ;
    PORT
      LAYER metal2 ;
      RECT 71.405 0.000 71.475 0.210 ;
    END
  END w0_wd_in[512]
  PIN w0_wd_in[513]
    DIRECTION OUTPUT ;
    USE SIGNAL ;
    SHAPE ABUTMENT ;
    PORT
      LAYER metal2 ;
      RECT 71.785 0.000 71.855 0.210 ;
    END
  END w0_wd_in[513]
  PIN w0_wd_in[514]
    DIRECTION OUTPUT ;
    USE SIGNAL ;
    SHAPE ABUTMENT ;
    PORT
      LAYER metal2 ;
      RECT 72.165 0.000 72.235 0.210 ;
    END
  END w0_wd_in[514]
  PIN w0_wd_in[515]
    DIRECTION OUTPUT ;
    USE SIGNAL ;
    SHAPE ABUTMENT ;
    PORT
      LAYER metal2 ;
      RECT 72.545 0.000 72.615 0.210 ;
    END
  END w0_wd_in[515]
  PIN w0_wd_in[516]
    DIRECTION OUTPUT ;
    USE SIGNAL ;
    SHAPE ABUTMENT ;
    PORT
      LAYER metal2 ;
      RECT 72.925 0.000 72.995 0.210 ;
    END
  END w0_wd_in[516]
  PIN w0_wd_in[517]
    DIRECTION OUTPUT ;
    USE SIGNAL ;
    SHAPE ABUTMENT ;
    PORT
      LAYER metal2 ;
      RECT 73.305 0.000 73.375 0.210 ;
    END
  END w0_wd_in[517]
  PIN w0_wd_in[518]
    DIRECTION OUTPUT ;
    USE SIGNAL ;
    SHAPE ABUTMENT ;
    PORT
      LAYER metal2 ;
      RECT 73.685 0.000 73.755 0.210 ;
    END
  END w0_wd_in[518]
  PIN w0_wd_in[519]
    DIRECTION OUTPUT ;
    USE SIGNAL ;
    SHAPE ABUTMENT ;
    PORT
      LAYER metal2 ;
      RECT 74.065 0.000 74.135 0.210 ;
    END
  END w0_wd_in[519]
  PIN w0_wd_in[520]
    DIRECTION OUTPUT ;
    USE SIGNAL ;
    SHAPE ABUTMENT ;
    PORT
      LAYER metal2 ;
      RECT 74.445 0.000 74.515 0.210 ;
    END
  END w0_wd_in[520]
  PIN w0_wd_in[521]
    DIRECTION OUTPUT ;
    USE SIGNAL ;
    SHAPE ABUTMENT ;
    PORT
      LAYER metal2 ;
      RECT 74.825 0.000 74.895 0.210 ;
    END
  END w0_wd_in[521]
  PIN w0_wd_in[522]
    DIRECTION OUTPUT ;
    USE SIGNAL ;
    SHAPE ABUTMENT ;
    PORT
      LAYER metal2 ;
      RECT 75.205 0.000 75.275 0.210 ;
    END
  END w0_wd_in[522]
  PIN w0_wd_in[523]
    DIRECTION OUTPUT ;
    USE SIGNAL ;
    SHAPE ABUTMENT ;
    PORT
      LAYER metal2 ;
      RECT 75.585 0.000 75.655 0.210 ;
    END
  END w0_wd_in[523]
  PIN w0_wd_in[524]
    DIRECTION OUTPUT ;
    USE SIGNAL ;
    SHAPE ABUTMENT ;
    PORT
      LAYER metal2 ;
      RECT 75.965 0.000 76.035 0.210 ;
    END
  END w0_wd_in[524]
  PIN w0_wd_in[525]
    DIRECTION OUTPUT ;
    USE SIGNAL ;
    SHAPE ABUTMENT ;
    PORT
      LAYER metal2 ;
      RECT 76.345 0.000 76.415 0.210 ;
    END
  END w0_wd_in[525]
  PIN w0_wd_in[526]
    DIRECTION OUTPUT ;
    USE SIGNAL ;
    SHAPE ABUTMENT ;
    PORT
      LAYER metal2 ;
      RECT 76.725 0.000 76.795 0.210 ;
    END
  END w0_wd_in[526]
  PIN w0_wd_in[527]
    DIRECTION OUTPUT ;
    USE SIGNAL ;
    SHAPE ABUTMENT ;
    PORT
      LAYER metal2 ;
      RECT 77.105 0.000 77.175 0.210 ;
    END
  END w0_wd_in[527]
  PIN w0_wd_in[528]
    DIRECTION OUTPUT ;
    USE SIGNAL ;
    SHAPE ABUTMENT ;
    PORT
      LAYER metal2 ;
      RECT 77.485 0.000 77.555 0.210 ;
    END
  END w0_wd_in[528]
  PIN w0_wd_in[529]
    DIRECTION OUTPUT ;
    USE SIGNAL ;
    SHAPE ABUTMENT ;
    PORT
      LAYER metal2 ;
      RECT 77.865 0.000 77.935 0.210 ;
    END
  END w0_wd_in[529]
  PIN w0_wd_in[530]
    DIRECTION OUTPUT ;
    USE SIGNAL ;
    SHAPE ABUTMENT ;
    PORT
      LAYER metal2 ;
      RECT 78.245 0.000 78.315 0.210 ;
    END
  END w0_wd_in[530]
  PIN w0_wd_in[531]
    DIRECTION OUTPUT ;
    USE SIGNAL ;
    SHAPE ABUTMENT ;
    PORT
      LAYER metal2 ;
      RECT 78.625 0.000 78.695 0.210 ;
    END
  END w0_wd_in[531]
  PIN w0_wd_in[532]
    DIRECTION OUTPUT ;
    USE SIGNAL ;
    SHAPE ABUTMENT ;
    PORT
      LAYER metal2 ;
      RECT 79.005 0.000 79.075 0.210 ;
    END
  END w0_wd_in[532]
  PIN w0_wd_in[533]
    DIRECTION OUTPUT ;
    USE SIGNAL ;
    SHAPE ABUTMENT ;
    PORT
      LAYER metal2 ;
      RECT 79.385 0.000 79.455 0.210 ;
    END
  END w0_wd_in[533]
  PIN w0_wd_in[534]
    DIRECTION OUTPUT ;
    USE SIGNAL ;
    SHAPE ABUTMENT ;
    PORT
      LAYER metal2 ;
      RECT 79.765 0.000 79.835 0.210 ;
    END
  END w0_wd_in[534]
  PIN w0_wd_in[535]
    DIRECTION OUTPUT ;
    USE SIGNAL ;
    SHAPE ABUTMENT ;
    PORT
      LAYER metal2 ;
      RECT 80.145 0.000 80.215 0.210 ;
    END
  END w0_wd_in[535]
  PIN w0_wd_in[536]
    DIRECTION OUTPUT ;
    USE SIGNAL ;
    SHAPE ABUTMENT ;
    PORT
      LAYER metal2 ;
      RECT 80.525 0.000 80.595 0.210 ;
    END
  END w0_wd_in[536]
  PIN w0_wd_in[537]
    DIRECTION OUTPUT ;
    USE SIGNAL ;
    SHAPE ABUTMENT ;
    PORT
      LAYER metal2 ;
      RECT 80.905 0.000 80.975 0.210 ;
    END
  END w0_wd_in[537]
  PIN w0_wd_in[538]
    DIRECTION OUTPUT ;
    USE SIGNAL ;
    SHAPE ABUTMENT ;
    PORT
      LAYER metal2 ;
      RECT 81.285 0.000 81.355 0.210 ;
    END
  END w0_wd_in[538]
  PIN w0_wd_in[539]
    DIRECTION OUTPUT ;
    USE SIGNAL ;
    SHAPE ABUTMENT ;
    PORT
      LAYER metal2 ;
      RECT 81.665 0.000 81.735 0.210 ;
    END
  END w0_wd_in[539]
  PIN w0_wd_in[540]
    DIRECTION OUTPUT ;
    USE SIGNAL ;
    SHAPE ABUTMENT ;
    PORT
      LAYER metal2 ;
      RECT 82.045 0.000 82.115 0.210 ;
    END
  END w0_wd_in[540]
  PIN w0_wd_in[541]
    DIRECTION OUTPUT ;
    USE SIGNAL ;
    SHAPE ABUTMENT ;
    PORT
      LAYER metal2 ;
      RECT 82.425 0.000 82.495 0.210 ;
    END
  END w0_wd_in[541]
  PIN w0_wd_in[542]
    DIRECTION OUTPUT ;
    USE SIGNAL ;
    SHAPE ABUTMENT ;
    PORT
      LAYER metal2 ;
      RECT 82.805 0.000 82.875 0.210 ;
    END
  END w0_wd_in[542]
  PIN w0_wd_in[543]
    DIRECTION OUTPUT ;
    USE SIGNAL ;
    SHAPE ABUTMENT ;
    PORT
      LAYER metal2 ;
      RECT 83.185 0.000 83.255 0.210 ;
    END
  END w0_wd_in[543]
  PIN w0_wd_in[544]
    DIRECTION OUTPUT ;
    USE SIGNAL ;
    SHAPE ABUTMENT ;
    PORT
      LAYER metal2 ;
      RECT 83.565 0.000 83.635 0.210 ;
    END
  END w0_wd_in[544]
  PIN w0_wd_in[545]
    DIRECTION OUTPUT ;
    USE SIGNAL ;
    SHAPE ABUTMENT ;
    PORT
      LAYER metal2 ;
      RECT 83.945 0.000 84.015 0.210 ;
    END
  END w0_wd_in[545]
  PIN w0_wd_in[546]
    DIRECTION OUTPUT ;
    USE SIGNAL ;
    SHAPE ABUTMENT ;
    PORT
      LAYER metal2 ;
      RECT 84.325 0.000 84.395 0.210 ;
    END
  END w0_wd_in[546]
  PIN w0_wd_in[547]
    DIRECTION OUTPUT ;
    USE SIGNAL ;
    SHAPE ABUTMENT ;
    PORT
      LAYER metal2 ;
      RECT 84.705 0.000 84.775 0.210 ;
    END
  END w0_wd_in[547]
  PIN w0_wd_in[548]
    DIRECTION OUTPUT ;
    USE SIGNAL ;
    SHAPE ABUTMENT ;
    PORT
      LAYER metal2 ;
      RECT 85.085 0.000 85.155 0.210 ;
    END
  END w0_wd_in[548]
  PIN w0_wd_in[549]
    DIRECTION OUTPUT ;
    USE SIGNAL ;
    SHAPE ABUTMENT ;
    PORT
      LAYER metal2 ;
      RECT 85.465 0.000 85.535 0.210 ;
    END
  END w0_wd_in[549]
  PIN w0_wd_in[550]
    DIRECTION OUTPUT ;
    USE SIGNAL ;
    SHAPE ABUTMENT ;
    PORT
      LAYER metal2 ;
      RECT 85.845 0.000 85.915 0.210 ;
    END
  END w0_wd_in[550]
  PIN w0_wd_in[551]
    DIRECTION OUTPUT ;
    USE SIGNAL ;
    SHAPE ABUTMENT ;
    PORT
      LAYER metal2 ;
      RECT 86.225 0.000 86.295 0.210 ;
    END
  END w0_wd_in[551]
  PIN w0_wd_in[552]
    DIRECTION OUTPUT ;
    USE SIGNAL ;
    SHAPE ABUTMENT ;
    PORT
      LAYER metal2 ;
      RECT 86.605 0.000 86.675 0.210 ;
    END
  END w0_wd_in[552]
  PIN w0_wd_in[553]
    DIRECTION OUTPUT ;
    USE SIGNAL ;
    SHAPE ABUTMENT ;
    PORT
      LAYER metal2 ;
      RECT 86.985 0.000 87.055 0.210 ;
    END
  END w0_wd_in[553]
  PIN w0_wd_in[554]
    DIRECTION OUTPUT ;
    USE SIGNAL ;
    SHAPE ABUTMENT ;
    PORT
      LAYER metal2 ;
      RECT 87.365 0.000 87.435 0.210 ;
    END
  END w0_wd_in[554]
  PIN w0_wd_in[555]
    DIRECTION OUTPUT ;
    USE SIGNAL ;
    SHAPE ABUTMENT ;
    PORT
      LAYER metal2 ;
      RECT 87.745 0.000 87.815 0.210 ;
    END
  END w0_wd_in[555]
  PIN w0_wd_in[556]
    DIRECTION OUTPUT ;
    USE SIGNAL ;
    SHAPE ABUTMENT ;
    PORT
      LAYER metal2 ;
      RECT 88.125 0.000 88.195 0.210 ;
    END
  END w0_wd_in[556]
  PIN w0_wd_in[557]
    DIRECTION OUTPUT ;
    USE SIGNAL ;
    SHAPE ABUTMENT ;
    PORT
      LAYER metal2 ;
      RECT 88.505 0.000 88.575 0.210 ;
    END
  END w0_wd_in[557]
  PIN w0_wd_in[558]
    DIRECTION OUTPUT ;
    USE SIGNAL ;
    SHAPE ABUTMENT ;
    PORT
      LAYER metal2 ;
      RECT 88.885 0.000 88.955 0.210 ;
    END
  END w0_wd_in[558]
  PIN w0_wd_in[559]
    DIRECTION OUTPUT ;
    USE SIGNAL ;
    SHAPE ABUTMENT ;
    PORT
      LAYER metal2 ;
      RECT 89.265 0.000 89.335 0.210 ;
    END
  END w0_wd_in[559]
  PIN w0_wd_in[560]
    DIRECTION OUTPUT ;
    USE SIGNAL ;
    SHAPE ABUTMENT ;
    PORT
      LAYER metal2 ;
      RECT 89.645 0.000 89.715 0.210 ;
    END
  END w0_wd_in[560]
  PIN w0_wd_in[561]
    DIRECTION OUTPUT ;
    USE SIGNAL ;
    SHAPE ABUTMENT ;
    PORT
      LAYER metal2 ;
      RECT 90.025 0.000 90.095 0.210 ;
    END
  END w0_wd_in[561]
  PIN w0_wd_in[562]
    DIRECTION OUTPUT ;
    USE SIGNAL ;
    SHAPE ABUTMENT ;
    PORT
      LAYER metal2 ;
      RECT 90.405 0.000 90.475 0.210 ;
    END
  END w0_wd_in[562]
  PIN w0_wd_in[563]
    DIRECTION OUTPUT ;
    USE SIGNAL ;
    SHAPE ABUTMENT ;
    PORT
      LAYER metal2 ;
      RECT 90.785 0.000 90.855 0.210 ;
    END
  END w0_wd_in[563]
  PIN w0_wd_in[564]
    DIRECTION OUTPUT ;
    USE SIGNAL ;
    SHAPE ABUTMENT ;
    PORT
      LAYER metal2 ;
      RECT 91.165 0.000 91.235 0.210 ;
    END
  END w0_wd_in[564]
  PIN w0_wd_in[565]
    DIRECTION OUTPUT ;
    USE SIGNAL ;
    SHAPE ABUTMENT ;
    PORT
      LAYER metal2 ;
      RECT 91.545 0.000 91.615 0.210 ;
    END
  END w0_wd_in[565]
  PIN w0_wd_in[566]
    DIRECTION OUTPUT ;
    USE SIGNAL ;
    SHAPE ABUTMENT ;
    PORT
      LAYER metal2 ;
      RECT 91.925 0.000 91.995 0.210 ;
    END
  END w0_wd_in[566]
  PIN w0_wd_in[567]
    DIRECTION OUTPUT ;
    USE SIGNAL ;
    SHAPE ABUTMENT ;
    PORT
      LAYER metal2 ;
      RECT 92.305 0.000 92.375 0.210 ;
    END
  END w0_wd_in[567]
  PIN w0_wd_in[568]
    DIRECTION OUTPUT ;
    USE SIGNAL ;
    SHAPE ABUTMENT ;
    PORT
      LAYER metal2 ;
      RECT 92.685 0.000 92.755 0.210 ;
    END
  END w0_wd_in[568]
  PIN w0_wd_in[569]
    DIRECTION OUTPUT ;
    USE SIGNAL ;
    SHAPE ABUTMENT ;
    PORT
      LAYER metal2 ;
      RECT 93.065 0.000 93.135 0.210 ;
    END
  END w0_wd_in[569]
  PIN w0_wd_in[570]
    DIRECTION OUTPUT ;
    USE SIGNAL ;
    SHAPE ABUTMENT ;
    PORT
      LAYER metal2 ;
      RECT 93.445 0.000 93.515 0.210 ;
    END
  END w0_wd_in[570]
  PIN w0_wd_in[571]
    DIRECTION OUTPUT ;
    USE SIGNAL ;
    SHAPE ABUTMENT ;
    PORT
      LAYER metal2 ;
      RECT 93.825 0.000 93.895 0.210 ;
    END
  END w0_wd_in[571]
  PIN w0_wd_in[572]
    DIRECTION OUTPUT ;
    USE SIGNAL ;
    SHAPE ABUTMENT ;
    PORT
      LAYER metal2 ;
      RECT 94.205 0.000 94.275 0.210 ;
    END
  END w0_wd_in[572]
  PIN w0_wd_in[573]
    DIRECTION OUTPUT ;
    USE SIGNAL ;
    SHAPE ABUTMENT ;
    PORT
      LAYER metal2 ;
      RECT 94.585 0.000 94.655 0.210 ;
    END
  END w0_wd_in[573]
  PIN w0_wd_in[574]
    DIRECTION OUTPUT ;
    USE SIGNAL ;
    SHAPE ABUTMENT ;
    PORT
      LAYER metal2 ;
      RECT 94.965 0.000 95.035 0.210 ;
    END
  END w0_wd_in[574]
  PIN w0_wd_in[575]
    DIRECTION OUTPUT ;
    USE SIGNAL ;
    SHAPE ABUTMENT ;
    PORT
      LAYER metal2 ;
      RECT 95.345 0.000 95.415 0.210 ;
    END
  END w0_wd_in[575]
  PIN w0_wd_in[576]
    DIRECTION OUTPUT ;
    USE SIGNAL ;
    SHAPE ABUTMENT ;
    PORT
      LAYER metal2 ;
      RECT 95.725 0.000 95.795 0.210 ;
    END
  END w0_wd_in[576]
  PIN w0_wd_in[577]
    DIRECTION OUTPUT ;
    USE SIGNAL ;
    SHAPE ABUTMENT ;
    PORT
      LAYER metal2 ;
      RECT 96.105 0.000 96.175 0.210 ;
    END
  END w0_wd_in[577]
  PIN w0_wd_in[578]
    DIRECTION OUTPUT ;
    USE SIGNAL ;
    SHAPE ABUTMENT ;
    PORT
      LAYER metal2 ;
      RECT 96.485 0.000 96.555 0.210 ;
    END
  END w0_wd_in[578]
  PIN w0_wd_in[579]
    DIRECTION OUTPUT ;
    USE SIGNAL ;
    SHAPE ABUTMENT ;
    PORT
      LAYER metal2 ;
      RECT 96.865 0.000 96.935 0.210 ;
    END
  END w0_wd_in[579]
  PIN w0_wd_in[580]
    DIRECTION OUTPUT ;
    USE SIGNAL ;
    SHAPE ABUTMENT ;
    PORT
      LAYER metal2 ;
      RECT 97.245 0.000 97.315 0.210 ;
    END
  END w0_wd_in[580]
  PIN w0_wd_in[581]
    DIRECTION OUTPUT ;
    USE SIGNAL ;
    SHAPE ABUTMENT ;
    PORT
      LAYER metal2 ;
      RECT 97.625 0.000 97.695 0.210 ;
    END
  END w0_wd_in[581]
  PIN w0_wd_in[582]
    DIRECTION OUTPUT ;
    USE SIGNAL ;
    SHAPE ABUTMENT ;
    PORT
      LAYER metal2 ;
      RECT 98.005 0.000 98.075 0.210 ;
    END
  END w0_wd_in[582]
  PIN w0_wd_in[583]
    DIRECTION OUTPUT ;
    USE SIGNAL ;
    SHAPE ABUTMENT ;
    PORT
      LAYER metal2 ;
      RECT 98.385 0.000 98.455 0.210 ;
    END
  END w0_wd_in[583]
  PIN w0_wd_in[584]
    DIRECTION OUTPUT ;
    USE SIGNAL ;
    SHAPE ABUTMENT ;
    PORT
      LAYER metal2 ;
      RECT 98.765 0.000 98.835 0.210 ;
    END
  END w0_wd_in[584]
  PIN w0_wd_in[585]
    DIRECTION OUTPUT ;
    USE SIGNAL ;
    SHAPE ABUTMENT ;
    PORT
      LAYER metal2 ;
      RECT 99.145 0.000 99.215 0.210 ;
    END
  END w0_wd_in[585]
  PIN w0_wd_in[586]
    DIRECTION OUTPUT ;
    USE SIGNAL ;
    SHAPE ABUTMENT ;
    PORT
      LAYER metal2 ;
      RECT 99.525 0.000 99.595 0.210 ;
    END
  END w0_wd_in[586]
  PIN w0_wd_in[587]
    DIRECTION OUTPUT ;
    USE SIGNAL ;
    SHAPE ABUTMENT ;
    PORT
      LAYER metal2 ;
      RECT 99.905 0.000 99.975 0.210 ;
    END
  END w0_wd_in[587]
  PIN w0_wd_in[588]
    DIRECTION OUTPUT ;
    USE SIGNAL ;
    SHAPE ABUTMENT ;
    PORT
      LAYER metal2 ;
      RECT 100.285 0.000 100.355 0.210 ;
    END
  END w0_wd_in[588]
  PIN w0_wd_in[589]
    DIRECTION OUTPUT ;
    USE SIGNAL ;
    SHAPE ABUTMENT ;
    PORT
      LAYER metal2 ;
      RECT 100.665 0.000 100.735 0.210 ;
    END
  END w0_wd_in[589]
  PIN w0_wd_in[590]
    DIRECTION OUTPUT ;
    USE SIGNAL ;
    SHAPE ABUTMENT ;
    PORT
      LAYER metal2 ;
      RECT 101.045 0.000 101.115 0.210 ;
    END
  END w0_wd_in[590]
  PIN w0_wd_in[591]
    DIRECTION OUTPUT ;
    USE SIGNAL ;
    SHAPE ABUTMENT ;
    PORT
      LAYER metal2 ;
      RECT 101.425 0.000 101.495 0.210 ;
    END
  END w0_wd_in[591]
  PIN w0_wd_in[592]
    DIRECTION OUTPUT ;
    USE SIGNAL ;
    SHAPE ABUTMENT ;
    PORT
      LAYER metal2 ;
      RECT 101.805 0.000 101.875 0.210 ;
    END
  END w0_wd_in[592]
  PIN w0_wd_in[593]
    DIRECTION OUTPUT ;
    USE SIGNAL ;
    SHAPE ABUTMENT ;
    PORT
      LAYER metal2 ;
      RECT 102.185 0.000 102.255 0.210 ;
    END
  END w0_wd_in[593]
  PIN w0_wd_in[594]
    DIRECTION OUTPUT ;
    USE SIGNAL ;
    SHAPE ABUTMENT ;
    PORT
      LAYER metal2 ;
      RECT 102.565 0.000 102.635 0.210 ;
    END
  END w0_wd_in[594]
  PIN w0_wd_in[595]
    DIRECTION OUTPUT ;
    USE SIGNAL ;
    SHAPE ABUTMENT ;
    PORT
      LAYER metal2 ;
      RECT 102.945 0.000 103.015 0.210 ;
    END
  END w0_wd_in[595]
  PIN w0_wd_in[596]
    DIRECTION OUTPUT ;
    USE SIGNAL ;
    SHAPE ABUTMENT ;
    PORT
      LAYER metal2 ;
      RECT 103.325 0.000 103.395 0.210 ;
    END
  END w0_wd_in[596]
  PIN w0_wd_in[597]
    DIRECTION OUTPUT ;
    USE SIGNAL ;
    SHAPE ABUTMENT ;
    PORT
      LAYER metal2 ;
      RECT 103.705 0.000 103.775 0.210 ;
    END
  END w0_wd_in[597]
  PIN w0_wd_in[598]
    DIRECTION OUTPUT ;
    USE SIGNAL ;
    SHAPE ABUTMENT ;
    PORT
      LAYER metal2 ;
      RECT 104.085 0.000 104.155 0.210 ;
    END
  END w0_wd_in[598]
  PIN w0_wd_in[599]
    DIRECTION OUTPUT ;
    USE SIGNAL ;
    SHAPE ABUTMENT ;
    PORT
      LAYER metal2 ;
      RECT 104.465 0.000 104.535 0.210 ;
    END
  END w0_wd_in[599]
  PIN w0_wd_in[600]
    DIRECTION OUTPUT ;
    USE SIGNAL ;
    SHAPE ABUTMENT ;
    PORT
      LAYER metal2 ;
      RECT 104.845 0.000 104.915 0.210 ;
    END
  END w0_wd_in[600]
  PIN w0_wd_in[601]
    DIRECTION OUTPUT ;
    USE SIGNAL ;
    SHAPE ABUTMENT ;
    PORT
      LAYER metal2 ;
      RECT 105.225 0.000 105.295 0.210 ;
    END
  END w0_wd_in[601]
  PIN w0_wd_in[602]
    DIRECTION OUTPUT ;
    USE SIGNAL ;
    SHAPE ABUTMENT ;
    PORT
      LAYER metal2 ;
      RECT 105.605 0.000 105.675 0.210 ;
    END
  END w0_wd_in[602]
  PIN w0_wd_in[603]
    DIRECTION OUTPUT ;
    USE SIGNAL ;
    SHAPE ABUTMENT ;
    PORT
      LAYER metal2 ;
      RECT 105.985 0.000 106.055 0.210 ;
    END
  END w0_wd_in[603]
  PIN w0_wd_in[604]
    DIRECTION OUTPUT ;
    USE SIGNAL ;
    SHAPE ABUTMENT ;
    PORT
      LAYER metal2 ;
      RECT 106.365 0.000 106.435 0.210 ;
    END
  END w0_wd_in[604]
  PIN w0_wd_in[605]
    DIRECTION OUTPUT ;
    USE SIGNAL ;
    SHAPE ABUTMENT ;
    PORT
      LAYER metal2 ;
      RECT 106.745 0.000 106.815 0.210 ;
    END
  END w0_wd_in[605]
  PIN w0_wd_in[606]
    DIRECTION OUTPUT ;
    USE SIGNAL ;
    SHAPE ABUTMENT ;
    PORT
      LAYER metal2 ;
      RECT 107.125 0.000 107.195 0.210 ;
    END
  END w0_wd_in[606]
  PIN w0_wd_in[607]
    DIRECTION OUTPUT ;
    USE SIGNAL ;
    SHAPE ABUTMENT ;
    PORT
      LAYER metal2 ;
      RECT 107.505 0.000 107.575 0.210 ;
    END
  END w0_wd_in[607]
  PIN w0_wd_in[608]
    DIRECTION OUTPUT ;
    USE SIGNAL ;
    SHAPE ABUTMENT ;
    PORT
      LAYER metal2 ;
      RECT 107.885 0.000 107.955 0.210 ;
    END
  END w0_wd_in[608]
  PIN w0_wd_in[609]
    DIRECTION OUTPUT ;
    USE SIGNAL ;
    SHAPE ABUTMENT ;
    PORT
      LAYER metal2 ;
      RECT 108.265 0.000 108.335 0.210 ;
    END
  END w0_wd_in[609]
  PIN w0_wd_in[610]
    DIRECTION OUTPUT ;
    USE SIGNAL ;
    SHAPE ABUTMENT ;
    PORT
      LAYER metal2 ;
      RECT 108.645 0.000 108.715 0.210 ;
    END
  END w0_wd_in[610]
  PIN w0_wd_in[611]
    DIRECTION OUTPUT ;
    USE SIGNAL ;
    SHAPE ABUTMENT ;
    PORT
      LAYER metal2 ;
      RECT 109.025 0.000 109.095 0.210 ;
    END
  END w0_wd_in[611]
  PIN w0_wd_in[612]
    DIRECTION OUTPUT ;
    USE SIGNAL ;
    SHAPE ABUTMENT ;
    PORT
      LAYER metal2 ;
      RECT 109.405 0.000 109.475 0.210 ;
    END
  END w0_wd_in[612]
  PIN w0_wd_in[613]
    DIRECTION OUTPUT ;
    USE SIGNAL ;
    SHAPE ABUTMENT ;
    PORT
      LAYER metal2 ;
      RECT 109.785 0.000 109.855 0.210 ;
    END
  END w0_wd_in[613]
  PIN w0_wd_in[614]
    DIRECTION OUTPUT ;
    USE SIGNAL ;
    SHAPE ABUTMENT ;
    PORT
      LAYER metal2 ;
      RECT 110.165 0.000 110.235 0.210 ;
    END
  END w0_wd_in[614]
  PIN w0_wd_in[615]
    DIRECTION OUTPUT ;
    USE SIGNAL ;
    SHAPE ABUTMENT ;
    PORT
      LAYER metal2 ;
      RECT 110.545 0.000 110.615 0.210 ;
    END
  END w0_wd_in[615]
  PIN w0_wd_in[616]
    DIRECTION OUTPUT ;
    USE SIGNAL ;
    SHAPE ABUTMENT ;
    PORT
      LAYER metal2 ;
      RECT 110.925 0.000 110.995 0.210 ;
    END
  END w0_wd_in[616]
  PIN w0_wd_in[617]
    DIRECTION OUTPUT ;
    USE SIGNAL ;
    SHAPE ABUTMENT ;
    PORT
      LAYER metal2 ;
      RECT 111.305 0.000 111.375 0.210 ;
    END
  END w0_wd_in[617]
  PIN w0_wd_in[618]
    DIRECTION OUTPUT ;
    USE SIGNAL ;
    SHAPE ABUTMENT ;
    PORT
      LAYER metal2 ;
      RECT 111.685 0.000 111.755 0.210 ;
    END
  END w0_wd_in[618]
  PIN w0_wd_in[619]
    DIRECTION OUTPUT ;
    USE SIGNAL ;
    SHAPE ABUTMENT ;
    PORT
      LAYER metal2 ;
      RECT 112.065 0.000 112.135 0.210 ;
    END
  END w0_wd_in[619]
  PIN w0_wd_in[620]
    DIRECTION OUTPUT ;
    USE SIGNAL ;
    SHAPE ABUTMENT ;
    PORT
      LAYER metal2 ;
      RECT 112.445 0.000 112.515 0.210 ;
    END
  END w0_wd_in[620]
  PIN w0_wd_in[621]
    DIRECTION OUTPUT ;
    USE SIGNAL ;
    SHAPE ABUTMENT ;
    PORT
      LAYER metal2 ;
      RECT 112.825 0.000 112.895 0.210 ;
    END
  END w0_wd_in[621]
  PIN w0_wd_in[622]
    DIRECTION OUTPUT ;
    USE SIGNAL ;
    SHAPE ABUTMENT ;
    PORT
      LAYER metal2 ;
      RECT 113.205 0.000 113.275 0.210 ;
    END
  END w0_wd_in[622]
  PIN w0_wd_in[623]
    DIRECTION OUTPUT ;
    USE SIGNAL ;
    SHAPE ABUTMENT ;
    PORT
      LAYER metal2 ;
      RECT 113.585 0.000 113.655 0.210 ;
    END
  END w0_wd_in[623]
  PIN w0_wd_in[624]
    DIRECTION OUTPUT ;
    USE SIGNAL ;
    SHAPE ABUTMENT ;
    PORT
      LAYER metal2 ;
      RECT 113.965 0.000 114.035 0.210 ;
    END
  END w0_wd_in[624]
  PIN w0_wd_in[625]
    DIRECTION OUTPUT ;
    USE SIGNAL ;
    SHAPE ABUTMENT ;
    PORT
      LAYER metal2 ;
      RECT 114.345 0.000 114.415 0.210 ;
    END
  END w0_wd_in[625]
  PIN w0_wd_in[626]
    DIRECTION OUTPUT ;
    USE SIGNAL ;
    SHAPE ABUTMENT ;
    PORT
      LAYER metal2 ;
      RECT 114.725 0.000 114.795 0.210 ;
    END
  END w0_wd_in[626]
  PIN w0_wd_in[627]
    DIRECTION OUTPUT ;
    USE SIGNAL ;
    SHAPE ABUTMENT ;
    PORT
      LAYER metal2 ;
      RECT 115.105 0.000 115.175 0.210 ;
    END
  END w0_wd_in[627]
  PIN w0_wd_in[628]
    DIRECTION OUTPUT ;
    USE SIGNAL ;
    SHAPE ABUTMENT ;
    PORT
      LAYER metal2 ;
      RECT 115.485 0.000 115.555 0.210 ;
    END
  END w0_wd_in[628]
  PIN w0_wd_in[629]
    DIRECTION OUTPUT ;
    USE SIGNAL ;
    SHAPE ABUTMENT ;
    PORT
      LAYER metal2 ;
      RECT 115.865 0.000 115.935 0.210 ;
    END
  END w0_wd_in[629]
  PIN w0_wd_in[630]
    DIRECTION OUTPUT ;
    USE SIGNAL ;
    SHAPE ABUTMENT ;
    PORT
      LAYER metal2 ;
      RECT 116.245 0.000 116.315 0.210 ;
    END
  END w0_wd_in[630]
  PIN w0_wd_in[631]
    DIRECTION OUTPUT ;
    USE SIGNAL ;
    SHAPE ABUTMENT ;
    PORT
      LAYER metal2 ;
      RECT 116.625 0.000 116.695 0.210 ;
    END
  END w0_wd_in[631]
  PIN w0_wd_in[632]
    DIRECTION OUTPUT ;
    USE SIGNAL ;
    SHAPE ABUTMENT ;
    PORT
      LAYER metal2 ;
      RECT 117.005 0.000 117.075 0.210 ;
    END
  END w0_wd_in[632]
  PIN w0_wd_in[633]
    DIRECTION OUTPUT ;
    USE SIGNAL ;
    SHAPE ABUTMENT ;
    PORT
      LAYER metal2 ;
      RECT 117.385 0.000 117.455 0.210 ;
    END
  END w0_wd_in[633]
  PIN w0_wd_in[634]
    DIRECTION OUTPUT ;
    USE SIGNAL ;
    SHAPE ABUTMENT ;
    PORT
      LAYER metal2 ;
      RECT 117.765 0.000 117.835 0.210 ;
    END
  END w0_wd_in[634]
  PIN w0_wd_in[635]
    DIRECTION OUTPUT ;
    USE SIGNAL ;
    SHAPE ABUTMENT ;
    PORT
      LAYER metal2 ;
      RECT 118.145 0.000 118.215 0.210 ;
    END
  END w0_wd_in[635]
  PIN w0_wd_in[636]
    DIRECTION OUTPUT ;
    USE SIGNAL ;
    SHAPE ABUTMENT ;
    PORT
      LAYER metal2 ;
      RECT 118.525 0.000 118.595 0.210 ;
    END
  END w0_wd_in[636]
  PIN w0_wd_in[637]
    DIRECTION OUTPUT ;
    USE SIGNAL ;
    SHAPE ABUTMENT ;
    PORT
      LAYER metal2 ;
      RECT 118.905 0.000 118.975 0.210 ;
    END
  END w0_wd_in[637]
  PIN w0_wd_in[638]
    DIRECTION OUTPUT ;
    USE SIGNAL ;
    SHAPE ABUTMENT ;
    PORT
      LAYER metal2 ;
      RECT 119.285 0.000 119.355 0.210 ;
    END
  END w0_wd_in[638]
  PIN w0_wd_in[639]
    DIRECTION OUTPUT ;
    USE SIGNAL ;
    SHAPE ABUTMENT ;
    PORT
      LAYER metal2 ;
      RECT 119.665 0.000 119.735 0.210 ;
    END
  END w0_wd_in[639]
  PIN w0_wd_in[640]
    DIRECTION OUTPUT ;
    USE SIGNAL ;
    SHAPE ABUTMENT ;
    PORT
      LAYER metal2 ;
      RECT 120.045 0.000 120.115 0.210 ;
    END
  END w0_wd_in[640]
  PIN w0_wd_in[641]
    DIRECTION OUTPUT ;
    USE SIGNAL ;
    SHAPE ABUTMENT ;
    PORT
      LAYER metal2 ;
      RECT 120.425 0.000 120.495 0.210 ;
    END
  END w0_wd_in[641]
  PIN w0_wd_in[642]
    DIRECTION OUTPUT ;
    USE SIGNAL ;
    SHAPE ABUTMENT ;
    PORT
      LAYER metal2 ;
      RECT 120.805 0.000 120.875 0.210 ;
    END
  END w0_wd_in[642]
  PIN w0_wd_in[643]
    DIRECTION OUTPUT ;
    USE SIGNAL ;
    SHAPE ABUTMENT ;
    PORT
      LAYER metal2 ;
      RECT 121.185 0.000 121.255 0.210 ;
    END
  END w0_wd_in[643]
  PIN w0_wd_in[644]
    DIRECTION OUTPUT ;
    USE SIGNAL ;
    SHAPE ABUTMENT ;
    PORT
      LAYER metal2 ;
      RECT 121.565 0.000 121.635 0.210 ;
    END
  END w0_wd_in[644]
  PIN w0_wd_in[645]
    DIRECTION OUTPUT ;
    USE SIGNAL ;
    SHAPE ABUTMENT ;
    PORT
      LAYER metal2 ;
      RECT 121.945 0.000 122.015 0.210 ;
    END
  END w0_wd_in[645]
  PIN w0_wd_in[646]
    DIRECTION OUTPUT ;
    USE SIGNAL ;
    SHAPE ABUTMENT ;
    PORT
      LAYER metal2 ;
      RECT 122.325 0.000 122.395 0.210 ;
    END
  END w0_wd_in[646]
  PIN w0_wd_in[647]
    DIRECTION OUTPUT ;
    USE SIGNAL ;
    SHAPE ABUTMENT ;
    PORT
      LAYER metal2 ;
      RECT 122.705 0.000 122.775 0.210 ;
    END
  END w0_wd_in[647]
  PIN w0_wd_in[648]
    DIRECTION OUTPUT ;
    USE SIGNAL ;
    SHAPE ABUTMENT ;
    PORT
      LAYER metal2 ;
      RECT 123.085 0.000 123.155 0.210 ;
    END
  END w0_wd_in[648]
  PIN w0_wd_in[649]
    DIRECTION OUTPUT ;
    USE SIGNAL ;
    SHAPE ABUTMENT ;
    PORT
      LAYER metal2 ;
      RECT 123.465 0.000 123.535 0.210 ;
    END
  END w0_wd_in[649]
  PIN w0_wd_in[650]
    DIRECTION OUTPUT ;
    USE SIGNAL ;
    SHAPE ABUTMENT ;
    PORT
      LAYER metal2 ;
      RECT 123.845 0.000 123.915 0.210 ;
    END
  END w0_wd_in[650]
  PIN w0_wd_in[651]
    DIRECTION OUTPUT ;
    USE SIGNAL ;
    SHAPE ABUTMENT ;
    PORT
      LAYER metal2 ;
      RECT 124.225 0.000 124.295 0.210 ;
    END
  END w0_wd_in[651]
  PIN w0_wd_in[652]
    DIRECTION OUTPUT ;
    USE SIGNAL ;
    SHAPE ABUTMENT ;
    PORT
      LAYER metal2 ;
      RECT 124.605 0.000 124.675 0.210 ;
    END
  END w0_wd_in[652]
  PIN w0_wd_in[653]
    DIRECTION OUTPUT ;
    USE SIGNAL ;
    SHAPE ABUTMENT ;
    PORT
      LAYER metal2 ;
      RECT 124.985 0.000 125.055 0.210 ;
    END
  END w0_wd_in[653]
  PIN r0_rd_out[0]
    DIRECTION OUTPUT ;
    USE SIGNAL ;
    SHAPE ABUTMENT ;
    PORT
      LAYER metal2 ;
      RECT 125.365 0.000 125.435 0.210 ;
    END
  END r0_rd_out[0]
  PIN r0_rd_out[1]
    DIRECTION OUTPUT ;
    USE SIGNAL ;
    SHAPE ABUTMENT ;
    PORT
      LAYER metal2 ;
      RECT 125.745 0.000 125.815 0.210 ;
    END
  END r0_rd_out[1]
  PIN r0_rd_out[2]
    DIRECTION OUTPUT ;
    USE SIGNAL ;
    SHAPE ABUTMENT ;
    PORT
      LAYER metal2 ;
      RECT 126.125 0.000 126.195 0.210 ;
    END
  END r0_rd_out[2]
  PIN r0_rd_out[3]
    DIRECTION OUTPUT ;
    USE SIGNAL ;
    SHAPE ABUTMENT ;
    PORT
      LAYER metal2 ;
      RECT 126.505 0.000 126.575 0.210 ;
    END
  END r0_rd_out[3]
  PIN r0_rd_out[4]
    DIRECTION OUTPUT ;
    USE SIGNAL ;
    SHAPE ABUTMENT ;
    PORT
      LAYER metal2 ;
      RECT 126.885 0.000 126.955 0.210 ;
    END
  END r0_rd_out[4]
  PIN r0_rd_out[5]
    DIRECTION OUTPUT ;
    USE SIGNAL ;
    SHAPE ABUTMENT ;
    PORT
      LAYER metal2 ;
      RECT 127.265 0.000 127.335 0.210 ;
    END
  END r0_rd_out[5]
  PIN r0_rd_out[6]
    DIRECTION OUTPUT ;
    USE SIGNAL ;
    SHAPE ABUTMENT ;
    PORT
      LAYER metal2 ;
      RECT 127.645 0.000 127.715 0.210 ;
    END
  END r0_rd_out[6]
  PIN r0_rd_out[7]
    DIRECTION OUTPUT ;
    USE SIGNAL ;
    SHAPE ABUTMENT ;
    PORT
      LAYER metal2 ;
      RECT 128.025 0.000 128.095 0.210 ;
    END
  END r0_rd_out[7]
  PIN r0_rd_out[8]
    DIRECTION OUTPUT ;
    USE SIGNAL ;
    SHAPE ABUTMENT ;
    PORT
      LAYER metal2 ;
      RECT 128.405 0.000 128.475 0.210 ;
    END
  END r0_rd_out[8]
  PIN r0_rd_out[9]
    DIRECTION OUTPUT ;
    USE SIGNAL ;
    SHAPE ABUTMENT ;
    PORT
      LAYER metal2 ;
      RECT 128.785 0.000 128.855 0.210 ;
    END
  END r0_rd_out[9]
  PIN r0_rd_out[10]
    DIRECTION OUTPUT ;
    USE SIGNAL ;
    SHAPE ABUTMENT ;
    PORT
      LAYER metal2 ;
      RECT 129.165 0.000 129.235 0.210 ;
    END
  END r0_rd_out[10]
  PIN r0_rd_out[11]
    DIRECTION OUTPUT ;
    USE SIGNAL ;
    SHAPE ABUTMENT ;
    PORT
      LAYER metal2 ;
      RECT 129.545 0.000 129.615 0.210 ;
    END
  END r0_rd_out[11]
  PIN r0_rd_out[12]
    DIRECTION OUTPUT ;
    USE SIGNAL ;
    SHAPE ABUTMENT ;
    PORT
      LAYER metal2 ;
      RECT 129.925 0.000 129.995 0.210 ;
    END
  END r0_rd_out[12]
  PIN r0_rd_out[13]
    DIRECTION OUTPUT ;
    USE SIGNAL ;
    SHAPE ABUTMENT ;
    PORT
      LAYER metal2 ;
      RECT 130.305 0.000 130.375 0.210 ;
    END
  END r0_rd_out[13]
  PIN r0_rd_out[14]
    DIRECTION OUTPUT ;
    USE SIGNAL ;
    SHAPE ABUTMENT ;
    PORT
      LAYER metal2 ;
      RECT 130.685 0.000 130.755 0.210 ;
    END
  END r0_rd_out[14]
  PIN r0_rd_out[15]
    DIRECTION OUTPUT ;
    USE SIGNAL ;
    SHAPE ABUTMENT ;
    PORT
      LAYER metal2 ;
      RECT 131.065 0.000 131.135 0.210 ;
    END
  END r0_rd_out[15]
  PIN r0_rd_out[16]
    DIRECTION OUTPUT ;
    USE SIGNAL ;
    SHAPE ABUTMENT ;
    PORT
      LAYER metal2 ;
      RECT 131.445 0.000 131.515 0.210 ;
    END
  END r0_rd_out[16]
  PIN r0_rd_out[17]
    DIRECTION OUTPUT ;
    USE SIGNAL ;
    SHAPE ABUTMENT ;
    PORT
      LAYER metal2 ;
      RECT 131.825 0.000 131.895 0.210 ;
    END
  END r0_rd_out[17]
  PIN r0_rd_out[18]
    DIRECTION OUTPUT ;
    USE SIGNAL ;
    SHAPE ABUTMENT ;
    PORT
      LAYER metal2 ;
      RECT 132.205 0.000 132.275 0.210 ;
    END
  END r0_rd_out[18]
  PIN r0_rd_out[19]
    DIRECTION OUTPUT ;
    USE SIGNAL ;
    SHAPE ABUTMENT ;
    PORT
      LAYER metal2 ;
      RECT 132.585 0.000 132.655 0.210 ;
    END
  END r0_rd_out[19]
  PIN r0_rd_out[20]
    DIRECTION OUTPUT ;
    USE SIGNAL ;
    SHAPE ABUTMENT ;
    PORT
      LAYER metal2 ;
      RECT 132.965 0.000 133.035 0.210 ;
    END
  END r0_rd_out[20]
  PIN r0_rd_out[21]
    DIRECTION OUTPUT ;
    USE SIGNAL ;
    SHAPE ABUTMENT ;
    PORT
      LAYER metal2 ;
      RECT 133.345 0.000 133.415 0.210 ;
    END
  END r0_rd_out[21]
  PIN r0_rd_out[22]
    DIRECTION OUTPUT ;
    USE SIGNAL ;
    SHAPE ABUTMENT ;
    PORT
      LAYER metal2 ;
      RECT 133.725 0.000 133.795 0.210 ;
    END
  END r0_rd_out[22]
  PIN r0_rd_out[23]
    DIRECTION OUTPUT ;
    USE SIGNAL ;
    SHAPE ABUTMENT ;
    PORT
      LAYER metal2 ;
      RECT 134.105 0.000 134.175 0.210 ;
    END
  END r0_rd_out[23]
  PIN r0_rd_out[24]
    DIRECTION OUTPUT ;
    USE SIGNAL ;
    SHAPE ABUTMENT ;
    PORT
      LAYER metal2 ;
      RECT 134.485 0.000 134.555 0.210 ;
    END
  END r0_rd_out[24]
  PIN r0_rd_out[25]
    DIRECTION OUTPUT ;
    USE SIGNAL ;
    SHAPE ABUTMENT ;
    PORT
      LAYER metal2 ;
      RECT 134.865 0.000 134.935 0.210 ;
    END
  END r0_rd_out[25]
  PIN r0_rd_out[26]
    DIRECTION OUTPUT ;
    USE SIGNAL ;
    SHAPE ABUTMENT ;
    PORT
      LAYER metal2 ;
      RECT 135.245 0.000 135.315 0.210 ;
    END
  END r0_rd_out[26]
  PIN r0_rd_out[27]
    DIRECTION OUTPUT ;
    USE SIGNAL ;
    SHAPE ABUTMENT ;
    PORT
      LAYER metal2 ;
      RECT 135.625 0.000 135.695 0.210 ;
    END
  END r0_rd_out[27]
  PIN r0_rd_out[28]
    DIRECTION OUTPUT ;
    USE SIGNAL ;
    SHAPE ABUTMENT ;
    PORT
      LAYER metal2 ;
      RECT 136.005 0.000 136.075 0.210 ;
    END
  END r0_rd_out[28]
  PIN r0_rd_out[29]
    DIRECTION OUTPUT ;
    USE SIGNAL ;
    SHAPE ABUTMENT ;
    PORT
      LAYER metal2 ;
      RECT 136.385 0.000 136.455 0.210 ;
    END
  END r0_rd_out[29]
  PIN r0_rd_out[30]
    DIRECTION OUTPUT ;
    USE SIGNAL ;
    SHAPE ABUTMENT ;
    PORT
      LAYER metal2 ;
      RECT 136.765 0.000 136.835 0.210 ;
    END
  END r0_rd_out[30]
  PIN r0_rd_out[31]
    DIRECTION OUTPUT ;
    USE SIGNAL ;
    SHAPE ABUTMENT ;
    PORT
      LAYER metal2 ;
      RECT 137.145 0.000 137.215 0.210 ;
    END
  END r0_rd_out[31]
  PIN r0_rd_out[32]
    DIRECTION OUTPUT ;
    USE SIGNAL ;
    SHAPE ABUTMENT ;
    PORT
      LAYER metal2 ;
      RECT 137.525 0.000 137.595 0.210 ;
    END
  END r0_rd_out[32]
  PIN r0_rd_out[33]
    DIRECTION OUTPUT ;
    USE SIGNAL ;
    SHAPE ABUTMENT ;
    PORT
      LAYER metal2 ;
      RECT 137.905 0.000 137.975 0.210 ;
    END
  END r0_rd_out[33]
  PIN r0_rd_out[34]
    DIRECTION OUTPUT ;
    USE SIGNAL ;
    SHAPE ABUTMENT ;
    PORT
      LAYER metal2 ;
      RECT 138.285 0.000 138.355 0.210 ;
    END
  END r0_rd_out[34]
  PIN r0_rd_out[35]
    DIRECTION OUTPUT ;
    USE SIGNAL ;
    SHAPE ABUTMENT ;
    PORT
      LAYER metal2 ;
      RECT 138.665 0.000 138.735 0.210 ;
    END
  END r0_rd_out[35]
  PIN r0_rd_out[36]
    DIRECTION OUTPUT ;
    USE SIGNAL ;
    SHAPE ABUTMENT ;
    PORT
      LAYER metal2 ;
      RECT 139.045 0.000 139.115 0.210 ;
    END
  END r0_rd_out[36]
  PIN r0_rd_out[37]
    DIRECTION OUTPUT ;
    USE SIGNAL ;
    SHAPE ABUTMENT ;
    PORT
      LAYER metal2 ;
      RECT 139.425 0.000 139.495 0.210 ;
    END
  END r0_rd_out[37]
  PIN r0_rd_out[38]
    DIRECTION OUTPUT ;
    USE SIGNAL ;
    SHAPE ABUTMENT ;
    PORT
      LAYER metal2 ;
      RECT 139.805 0.000 139.875 0.210 ;
    END
  END r0_rd_out[38]
  PIN r0_rd_out[39]
    DIRECTION OUTPUT ;
    USE SIGNAL ;
    SHAPE ABUTMENT ;
    PORT
      LAYER metal2 ;
      RECT 140.185 0.000 140.255 0.210 ;
    END
  END r0_rd_out[39]
  PIN r0_rd_out[40]
    DIRECTION OUTPUT ;
    USE SIGNAL ;
    SHAPE ABUTMENT ;
    PORT
      LAYER metal2 ;
      RECT 140.565 0.000 140.635 0.210 ;
    END
  END r0_rd_out[40]
  PIN r0_rd_out[41]
    DIRECTION OUTPUT ;
    USE SIGNAL ;
    SHAPE ABUTMENT ;
    PORT
      LAYER metal2 ;
      RECT 140.945 0.000 141.015 0.210 ;
    END
  END r0_rd_out[41]
  PIN r0_rd_out[42]
    DIRECTION OUTPUT ;
    USE SIGNAL ;
    SHAPE ABUTMENT ;
    PORT
      LAYER metal2 ;
      RECT 141.325 0.000 141.395 0.210 ;
    END
  END r0_rd_out[42]
  PIN r0_rd_out[43]
    DIRECTION OUTPUT ;
    USE SIGNAL ;
    SHAPE ABUTMENT ;
    PORT
      LAYER metal2 ;
      RECT 141.705 0.000 141.775 0.210 ;
    END
  END r0_rd_out[43]
  PIN r0_rd_out[44]
    DIRECTION OUTPUT ;
    USE SIGNAL ;
    SHAPE ABUTMENT ;
    PORT
      LAYER metal2 ;
      RECT 142.085 0.000 142.155 0.210 ;
    END
  END r0_rd_out[44]
  PIN r0_rd_out[45]
    DIRECTION OUTPUT ;
    USE SIGNAL ;
    SHAPE ABUTMENT ;
    PORT
      LAYER metal2 ;
      RECT 142.465 0.000 142.535 0.210 ;
    END
  END r0_rd_out[45]
  PIN r0_rd_out[46]
    DIRECTION OUTPUT ;
    USE SIGNAL ;
    SHAPE ABUTMENT ;
    PORT
      LAYER metal2 ;
      RECT 142.845 0.000 142.915 0.210 ;
    END
  END r0_rd_out[46]
  PIN r0_rd_out[47]
    DIRECTION OUTPUT ;
    USE SIGNAL ;
    SHAPE ABUTMENT ;
    PORT
      LAYER metal2 ;
      RECT 143.225 0.000 143.295 0.210 ;
    END
  END r0_rd_out[47]
  PIN r0_rd_out[48]
    DIRECTION OUTPUT ;
    USE SIGNAL ;
    SHAPE ABUTMENT ;
    PORT
      LAYER metal2 ;
      RECT 143.605 0.000 143.675 0.210 ;
    END
  END r0_rd_out[48]
  PIN r0_rd_out[49]
    DIRECTION OUTPUT ;
    USE SIGNAL ;
    SHAPE ABUTMENT ;
    PORT
      LAYER metal2 ;
      RECT 143.985 0.000 144.055 0.210 ;
    END
  END r0_rd_out[49]
  PIN r0_rd_out[50]
    DIRECTION OUTPUT ;
    USE SIGNAL ;
    SHAPE ABUTMENT ;
    PORT
      LAYER metal2 ;
      RECT 144.365 0.000 144.435 0.210 ;
    END
  END r0_rd_out[50]
  PIN r0_rd_out[51]
    DIRECTION OUTPUT ;
    USE SIGNAL ;
    SHAPE ABUTMENT ;
    PORT
      LAYER metal2 ;
      RECT 144.745 0.000 144.815 0.210 ;
    END
  END r0_rd_out[51]
  PIN r0_rd_out[52]
    DIRECTION OUTPUT ;
    USE SIGNAL ;
    SHAPE ABUTMENT ;
    PORT
      LAYER metal2 ;
      RECT 145.125 0.000 145.195 0.210 ;
    END
  END r0_rd_out[52]
  PIN r0_rd_out[53]
    DIRECTION OUTPUT ;
    USE SIGNAL ;
    SHAPE ABUTMENT ;
    PORT
      LAYER metal2 ;
      RECT 145.505 0.000 145.575 0.210 ;
    END
  END r0_rd_out[53]
  PIN r0_rd_out[54]
    DIRECTION OUTPUT ;
    USE SIGNAL ;
    SHAPE ABUTMENT ;
    PORT
      LAYER metal2 ;
      RECT 145.885 0.000 145.955 0.210 ;
    END
  END r0_rd_out[54]
  PIN r0_rd_out[55]
    DIRECTION OUTPUT ;
    USE SIGNAL ;
    SHAPE ABUTMENT ;
    PORT
      LAYER metal2 ;
      RECT 146.265 0.000 146.335 0.210 ;
    END
  END r0_rd_out[55]
  PIN r0_rd_out[56]
    DIRECTION OUTPUT ;
    USE SIGNAL ;
    SHAPE ABUTMENT ;
    PORT
      LAYER metal2 ;
      RECT 146.645 0.000 146.715 0.210 ;
    END
  END r0_rd_out[56]
  PIN r0_rd_out[57]
    DIRECTION OUTPUT ;
    USE SIGNAL ;
    SHAPE ABUTMENT ;
    PORT
      LAYER metal2 ;
      RECT 147.025 0.000 147.095 0.210 ;
    END
  END r0_rd_out[57]
  PIN r0_rd_out[58]
    DIRECTION OUTPUT ;
    USE SIGNAL ;
    SHAPE ABUTMENT ;
    PORT
      LAYER metal2 ;
      RECT 147.405 0.000 147.475 0.210 ;
    END
  END r0_rd_out[58]
  PIN r0_rd_out[59]
    DIRECTION OUTPUT ;
    USE SIGNAL ;
    SHAPE ABUTMENT ;
    PORT
      LAYER metal2 ;
      RECT 147.785 0.000 147.855 0.210 ;
    END
  END r0_rd_out[59]
  PIN r0_rd_out[60]
    DIRECTION OUTPUT ;
    USE SIGNAL ;
    SHAPE ABUTMENT ;
    PORT
      LAYER metal2 ;
      RECT 148.165 0.000 148.235 0.210 ;
    END
  END r0_rd_out[60]
  PIN r0_rd_out[61]
    DIRECTION OUTPUT ;
    USE SIGNAL ;
    SHAPE ABUTMENT ;
    PORT
      LAYER metal2 ;
      RECT 148.545 0.000 148.615 0.210 ;
    END
  END r0_rd_out[61]
  PIN r0_rd_out[62]
    DIRECTION OUTPUT ;
    USE SIGNAL ;
    SHAPE ABUTMENT ;
    PORT
      LAYER metal2 ;
      RECT 148.925 0.000 148.995 0.210 ;
    END
  END r0_rd_out[62]
  PIN r0_rd_out[63]
    DIRECTION OUTPUT ;
    USE SIGNAL ;
    SHAPE ABUTMENT ;
    PORT
      LAYER metal2 ;
      RECT 149.305 0.000 149.375 0.210 ;
    END
  END r0_rd_out[63]
  PIN r0_rd_out[64]
    DIRECTION OUTPUT ;
    USE SIGNAL ;
    SHAPE ABUTMENT ;
    PORT
      LAYER metal2 ;
      RECT 149.685 0.000 149.755 0.210 ;
    END
  END r0_rd_out[64]
  PIN r0_rd_out[65]
    DIRECTION OUTPUT ;
    USE SIGNAL ;
    SHAPE ABUTMENT ;
    PORT
      LAYER metal2 ;
      RECT 150.065 0.000 150.135 0.210 ;
    END
  END r0_rd_out[65]
  PIN r0_rd_out[66]
    DIRECTION OUTPUT ;
    USE SIGNAL ;
    SHAPE ABUTMENT ;
    PORT
      LAYER metal2 ;
      RECT 150.445 0.000 150.515 0.210 ;
    END
  END r0_rd_out[66]
  PIN r0_rd_out[67]
    DIRECTION OUTPUT ;
    USE SIGNAL ;
    SHAPE ABUTMENT ;
    PORT
      LAYER metal2 ;
      RECT 150.825 0.000 150.895 0.210 ;
    END
  END r0_rd_out[67]
  PIN r0_rd_out[68]
    DIRECTION OUTPUT ;
    USE SIGNAL ;
    SHAPE ABUTMENT ;
    PORT
      LAYER metal2 ;
      RECT 151.205 0.000 151.275 0.210 ;
    END
  END r0_rd_out[68]
  PIN r0_rd_out[69]
    DIRECTION OUTPUT ;
    USE SIGNAL ;
    SHAPE ABUTMENT ;
    PORT
      LAYER metal2 ;
      RECT 151.585 0.000 151.655 0.210 ;
    END
  END r0_rd_out[69]
  PIN r0_rd_out[70]
    DIRECTION OUTPUT ;
    USE SIGNAL ;
    SHAPE ABUTMENT ;
    PORT
      LAYER metal2 ;
      RECT 151.965 0.000 152.035 0.210 ;
    END
  END r0_rd_out[70]
  PIN r0_rd_out[71]
    DIRECTION OUTPUT ;
    USE SIGNAL ;
    SHAPE ABUTMENT ;
    PORT
      LAYER metal2 ;
      RECT 152.345 0.000 152.415 0.210 ;
    END
  END r0_rd_out[71]
  PIN r0_rd_out[72]
    DIRECTION OUTPUT ;
    USE SIGNAL ;
    SHAPE ABUTMENT ;
    PORT
      LAYER metal2 ;
      RECT 152.725 0.000 152.795 0.210 ;
    END
  END r0_rd_out[72]
  PIN r0_rd_out[73]
    DIRECTION OUTPUT ;
    USE SIGNAL ;
    SHAPE ABUTMENT ;
    PORT
      LAYER metal2 ;
      RECT 153.105 0.000 153.175 0.210 ;
    END
  END r0_rd_out[73]
  PIN r0_rd_out[74]
    DIRECTION OUTPUT ;
    USE SIGNAL ;
    SHAPE ABUTMENT ;
    PORT
      LAYER metal2 ;
      RECT 153.485 0.000 153.555 0.210 ;
    END
  END r0_rd_out[74]
  PIN r0_rd_out[75]
    DIRECTION OUTPUT ;
    USE SIGNAL ;
    SHAPE ABUTMENT ;
    PORT
      LAYER metal2 ;
      RECT 153.865 0.000 153.935 0.210 ;
    END
  END r0_rd_out[75]
  PIN r0_rd_out[76]
    DIRECTION OUTPUT ;
    USE SIGNAL ;
    SHAPE ABUTMENT ;
    PORT
      LAYER metal2 ;
      RECT 154.245 0.000 154.315 0.210 ;
    END
  END r0_rd_out[76]
  PIN r0_rd_out[77]
    DIRECTION OUTPUT ;
    USE SIGNAL ;
    SHAPE ABUTMENT ;
    PORT
      LAYER metal2 ;
      RECT 154.625 0.000 154.695 0.210 ;
    END
  END r0_rd_out[77]
  PIN r0_rd_out[78]
    DIRECTION OUTPUT ;
    USE SIGNAL ;
    SHAPE ABUTMENT ;
    PORT
      LAYER metal2 ;
      RECT 155.005 0.000 155.075 0.210 ;
    END
  END r0_rd_out[78]
  PIN r0_rd_out[79]
    DIRECTION OUTPUT ;
    USE SIGNAL ;
    SHAPE ABUTMENT ;
    PORT
      LAYER metal2 ;
      RECT 155.385 0.000 155.455 0.210 ;
    END
  END r0_rd_out[79]
  PIN r0_rd_out[80]
    DIRECTION OUTPUT ;
    USE SIGNAL ;
    SHAPE ABUTMENT ;
    PORT
      LAYER metal2 ;
      RECT 155.765 0.000 155.835 0.210 ;
    END
  END r0_rd_out[80]
  PIN r0_rd_out[81]
    DIRECTION OUTPUT ;
    USE SIGNAL ;
    SHAPE ABUTMENT ;
    PORT
      LAYER metal2 ;
      RECT 156.145 0.000 156.215 0.210 ;
    END
  END r0_rd_out[81]
  PIN r0_rd_out[82]
    DIRECTION OUTPUT ;
    USE SIGNAL ;
    SHAPE ABUTMENT ;
    PORT
      LAYER metal2 ;
      RECT 156.525 0.000 156.595 0.210 ;
    END
  END r0_rd_out[82]
  PIN r0_rd_out[83]
    DIRECTION OUTPUT ;
    USE SIGNAL ;
    SHAPE ABUTMENT ;
    PORT
      LAYER metal2 ;
      RECT 156.905 0.000 156.975 0.210 ;
    END
  END r0_rd_out[83]
  PIN r0_rd_out[84]
    DIRECTION OUTPUT ;
    USE SIGNAL ;
    SHAPE ABUTMENT ;
    PORT
      LAYER metal2 ;
      RECT 157.285 0.000 157.355 0.210 ;
    END
  END r0_rd_out[84]
  PIN r0_rd_out[85]
    DIRECTION OUTPUT ;
    USE SIGNAL ;
    SHAPE ABUTMENT ;
    PORT
      LAYER metal2 ;
      RECT 157.665 0.000 157.735 0.210 ;
    END
  END r0_rd_out[85]
  PIN r0_rd_out[86]
    DIRECTION OUTPUT ;
    USE SIGNAL ;
    SHAPE ABUTMENT ;
    PORT
      LAYER metal2 ;
      RECT 158.045 0.000 158.115 0.210 ;
    END
  END r0_rd_out[86]
  PIN r0_rd_out[87]
    DIRECTION OUTPUT ;
    USE SIGNAL ;
    SHAPE ABUTMENT ;
    PORT
      LAYER metal2 ;
      RECT 158.425 0.000 158.495 0.210 ;
    END
  END r0_rd_out[87]
  PIN r0_rd_out[88]
    DIRECTION OUTPUT ;
    USE SIGNAL ;
    SHAPE ABUTMENT ;
    PORT
      LAYER metal2 ;
      RECT 158.805 0.000 158.875 0.210 ;
    END
  END r0_rd_out[88]
  PIN r0_rd_out[89]
    DIRECTION OUTPUT ;
    USE SIGNAL ;
    SHAPE ABUTMENT ;
    PORT
      LAYER metal2 ;
      RECT 159.185 0.000 159.255 0.210 ;
    END
  END r0_rd_out[89]
  PIN r0_rd_out[90]
    DIRECTION OUTPUT ;
    USE SIGNAL ;
    SHAPE ABUTMENT ;
    PORT
      LAYER metal2 ;
      RECT 159.565 0.000 159.635 0.210 ;
    END
  END r0_rd_out[90]
  PIN r0_rd_out[91]
    DIRECTION OUTPUT ;
    USE SIGNAL ;
    SHAPE ABUTMENT ;
    PORT
      LAYER metal2 ;
      RECT 159.945 0.000 160.015 0.210 ;
    END
  END r0_rd_out[91]
  PIN r0_rd_out[92]
    DIRECTION OUTPUT ;
    USE SIGNAL ;
    SHAPE ABUTMENT ;
    PORT
      LAYER metal2 ;
      RECT 160.325 0.000 160.395 0.210 ;
    END
  END r0_rd_out[92]
  PIN r0_rd_out[93]
    DIRECTION OUTPUT ;
    USE SIGNAL ;
    SHAPE ABUTMENT ;
    PORT
      LAYER metal2 ;
      RECT 160.705 0.000 160.775 0.210 ;
    END
  END r0_rd_out[93]
  PIN r0_rd_out[94]
    DIRECTION OUTPUT ;
    USE SIGNAL ;
    SHAPE ABUTMENT ;
    PORT
      LAYER metal2 ;
      RECT 161.085 0.000 161.155 0.210 ;
    END
  END r0_rd_out[94]
  PIN r0_rd_out[95]
    DIRECTION OUTPUT ;
    USE SIGNAL ;
    SHAPE ABUTMENT ;
    PORT
      LAYER metal2 ;
      RECT 161.465 0.000 161.535 0.210 ;
    END
  END r0_rd_out[95]
  PIN r0_rd_out[96]
    DIRECTION OUTPUT ;
    USE SIGNAL ;
    SHAPE ABUTMENT ;
    PORT
      LAYER metal2 ;
      RECT 161.845 0.000 161.915 0.210 ;
    END
  END r0_rd_out[96]
  PIN r0_rd_out[97]
    DIRECTION OUTPUT ;
    USE SIGNAL ;
    SHAPE ABUTMENT ;
    PORT
      LAYER metal2 ;
      RECT 162.225 0.000 162.295 0.210 ;
    END
  END r0_rd_out[97]
  PIN r0_rd_out[98]
    DIRECTION OUTPUT ;
    USE SIGNAL ;
    SHAPE ABUTMENT ;
    PORT
      LAYER metal2 ;
      RECT 162.605 0.000 162.675 0.210 ;
    END
  END r0_rd_out[98]
  PIN r0_rd_out[99]
    DIRECTION OUTPUT ;
    USE SIGNAL ;
    SHAPE ABUTMENT ;
    PORT
      LAYER metal2 ;
      RECT 162.985 0.000 163.055 0.210 ;
    END
  END r0_rd_out[99]
  PIN r0_rd_out[100]
    DIRECTION OUTPUT ;
    USE SIGNAL ;
    SHAPE ABUTMENT ;
    PORT
      LAYER metal2 ;
      RECT 163.365 0.000 163.435 0.210 ;
    END
  END r0_rd_out[100]
  PIN r0_rd_out[101]
    DIRECTION OUTPUT ;
    USE SIGNAL ;
    SHAPE ABUTMENT ;
    PORT
      LAYER metal2 ;
      RECT 163.745 0.000 163.815 0.210 ;
    END
  END r0_rd_out[101]
  PIN r0_rd_out[102]
    DIRECTION OUTPUT ;
    USE SIGNAL ;
    SHAPE ABUTMENT ;
    PORT
      LAYER metal2 ;
      RECT 164.125 0.000 164.195 0.210 ;
    END
  END r0_rd_out[102]
  PIN r0_rd_out[103]
    DIRECTION OUTPUT ;
    USE SIGNAL ;
    SHAPE ABUTMENT ;
    PORT
      LAYER metal2 ;
      RECT 164.505 0.000 164.575 0.210 ;
    END
  END r0_rd_out[103]
  PIN r0_rd_out[104]
    DIRECTION OUTPUT ;
    USE SIGNAL ;
    SHAPE ABUTMENT ;
    PORT
      LAYER metal2 ;
      RECT 164.885 0.000 164.955 0.210 ;
    END
  END r0_rd_out[104]
  PIN r0_rd_out[105]
    DIRECTION OUTPUT ;
    USE SIGNAL ;
    SHAPE ABUTMENT ;
    PORT
      LAYER metal2 ;
      RECT 165.265 0.000 165.335 0.210 ;
    END
  END r0_rd_out[105]
  PIN r0_rd_out[106]
    DIRECTION OUTPUT ;
    USE SIGNAL ;
    SHAPE ABUTMENT ;
    PORT
      LAYER metal2 ;
      RECT 165.645 0.000 165.715 0.210 ;
    END
  END r0_rd_out[106]
  PIN r0_rd_out[107]
    DIRECTION OUTPUT ;
    USE SIGNAL ;
    SHAPE ABUTMENT ;
    PORT
      LAYER metal2 ;
      RECT 166.025 0.000 166.095 0.210 ;
    END
  END r0_rd_out[107]
  PIN r0_rd_out[108]
    DIRECTION OUTPUT ;
    USE SIGNAL ;
    SHAPE ABUTMENT ;
    PORT
      LAYER metal2 ;
      RECT 166.405 0.000 166.475 0.210 ;
    END
  END r0_rd_out[108]
  PIN r0_rd_out[109]
    DIRECTION OUTPUT ;
    USE SIGNAL ;
    SHAPE ABUTMENT ;
    PORT
      LAYER metal2 ;
      RECT 166.785 0.000 166.855 0.210 ;
    END
  END r0_rd_out[109]
  PIN r0_rd_out[110]
    DIRECTION OUTPUT ;
    USE SIGNAL ;
    SHAPE ABUTMENT ;
    PORT
      LAYER metal2 ;
      RECT 167.165 0.000 167.235 0.210 ;
    END
  END r0_rd_out[110]
  PIN r0_rd_out[111]
    DIRECTION OUTPUT ;
    USE SIGNAL ;
    SHAPE ABUTMENT ;
    PORT
      LAYER metal2 ;
      RECT 167.545 0.000 167.615 0.210 ;
    END
  END r0_rd_out[111]
  PIN r0_rd_out[112]
    DIRECTION OUTPUT ;
    USE SIGNAL ;
    SHAPE ABUTMENT ;
    PORT
      LAYER metal2 ;
      RECT 167.925 0.000 167.995 0.210 ;
    END
  END r0_rd_out[112]
  PIN r0_rd_out[113]
    DIRECTION OUTPUT ;
    USE SIGNAL ;
    SHAPE ABUTMENT ;
    PORT
      LAYER metal2 ;
      RECT 168.305 0.000 168.375 0.210 ;
    END
  END r0_rd_out[113]
  PIN r0_rd_out[114]
    DIRECTION OUTPUT ;
    USE SIGNAL ;
    SHAPE ABUTMENT ;
    PORT
      LAYER metal2 ;
      RECT 168.685 0.000 168.755 0.210 ;
    END
  END r0_rd_out[114]
  PIN r0_rd_out[115]
    DIRECTION OUTPUT ;
    USE SIGNAL ;
    SHAPE ABUTMENT ;
    PORT
      LAYER metal2 ;
      RECT 169.065 0.000 169.135 0.210 ;
    END
  END r0_rd_out[115]
  PIN r0_rd_out[116]
    DIRECTION OUTPUT ;
    USE SIGNAL ;
    SHAPE ABUTMENT ;
    PORT
      LAYER metal2 ;
      RECT 169.445 0.000 169.515 0.210 ;
    END
  END r0_rd_out[116]
  PIN r0_rd_out[117]
    DIRECTION OUTPUT ;
    USE SIGNAL ;
    SHAPE ABUTMENT ;
    PORT
      LAYER metal2 ;
      RECT 169.825 0.000 169.895 0.210 ;
    END
  END r0_rd_out[117]
  PIN r0_rd_out[118]
    DIRECTION OUTPUT ;
    USE SIGNAL ;
    SHAPE ABUTMENT ;
    PORT
      LAYER metal2 ;
      RECT 170.205 0.000 170.275 0.210 ;
    END
  END r0_rd_out[118]
  PIN r0_rd_out[119]
    DIRECTION OUTPUT ;
    USE SIGNAL ;
    SHAPE ABUTMENT ;
    PORT
      LAYER metal2 ;
      RECT 170.585 0.000 170.655 0.210 ;
    END
  END r0_rd_out[119]
  PIN r0_rd_out[120]
    DIRECTION OUTPUT ;
    USE SIGNAL ;
    SHAPE ABUTMENT ;
    PORT
      LAYER metal2 ;
      RECT 170.965 0.000 171.035 0.210 ;
    END
  END r0_rd_out[120]
  PIN r0_rd_out[121]
    DIRECTION OUTPUT ;
    USE SIGNAL ;
    SHAPE ABUTMENT ;
    PORT
      LAYER metal2 ;
      RECT 171.345 0.000 171.415 0.210 ;
    END
  END r0_rd_out[121]
  PIN r0_rd_out[122]
    DIRECTION OUTPUT ;
    USE SIGNAL ;
    SHAPE ABUTMENT ;
    PORT
      LAYER metal2 ;
      RECT 171.725 0.000 171.795 0.210 ;
    END
  END r0_rd_out[122]
  PIN r0_rd_out[123]
    DIRECTION OUTPUT ;
    USE SIGNAL ;
    SHAPE ABUTMENT ;
    PORT
      LAYER metal2 ;
      RECT 172.105 0.000 172.175 0.210 ;
    END
  END r0_rd_out[123]
  PIN r0_rd_out[124]
    DIRECTION OUTPUT ;
    USE SIGNAL ;
    SHAPE ABUTMENT ;
    PORT
      LAYER metal2 ;
      RECT 172.485 0.000 172.555 0.210 ;
    END
  END r0_rd_out[124]
  PIN r0_rd_out[125]
    DIRECTION OUTPUT ;
    USE SIGNAL ;
    SHAPE ABUTMENT ;
    PORT
      LAYER metal2 ;
      RECT 172.865 0.000 172.935 0.210 ;
    END
  END r0_rd_out[125]
  PIN r0_rd_out[126]
    DIRECTION OUTPUT ;
    USE SIGNAL ;
    SHAPE ABUTMENT ;
    PORT
      LAYER metal2 ;
      RECT 173.245 0.000 173.315 0.210 ;
    END
  END r0_rd_out[126]
  PIN r0_rd_out[127]
    DIRECTION OUTPUT ;
    USE SIGNAL ;
    SHAPE ABUTMENT ;
    PORT
      LAYER metal2 ;
      RECT 173.625 0.000 173.695 0.210 ;
    END
  END r0_rd_out[127]
  PIN r0_rd_out[128]
    DIRECTION OUTPUT ;
    USE SIGNAL ;
    SHAPE ABUTMENT ;
    PORT
      LAYER metal2 ;
      RECT 174.005 0.000 174.075 0.210 ;
    END
  END r0_rd_out[128]
  PIN r0_rd_out[129]
    DIRECTION OUTPUT ;
    USE SIGNAL ;
    SHAPE ABUTMENT ;
    PORT
      LAYER metal2 ;
      RECT 174.385 0.000 174.455 0.210 ;
    END
  END r0_rd_out[129]
  PIN r0_rd_out[130]
    DIRECTION OUTPUT ;
    USE SIGNAL ;
    SHAPE ABUTMENT ;
    PORT
      LAYER metal2 ;
      RECT 174.765 0.000 174.835 0.210 ;
    END
  END r0_rd_out[130]
  PIN r0_rd_out[131]
    DIRECTION OUTPUT ;
    USE SIGNAL ;
    SHAPE ABUTMENT ;
    PORT
      LAYER metal2 ;
      RECT 175.145 0.000 175.215 0.210 ;
    END
  END r0_rd_out[131]
  PIN r0_rd_out[132]
    DIRECTION OUTPUT ;
    USE SIGNAL ;
    SHAPE ABUTMENT ;
    PORT
      LAYER metal2 ;
      RECT 175.525 0.000 175.595 0.210 ;
    END
  END r0_rd_out[132]
  PIN r0_rd_out[133]
    DIRECTION OUTPUT ;
    USE SIGNAL ;
    SHAPE ABUTMENT ;
    PORT
      LAYER metal2 ;
      RECT 175.905 0.000 175.975 0.210 ;
    END
  END r0_rd_out[133]
  PIN r0_rd_out[134]
    DIRECTION OUTPUT ;
    USE SIGNAL ;
    SHAPE ABUTMENT ;
    PORT
      LAYER metal2 ;
      RECT 176.285 0.000 176.355 0.210 ;
    END
  END r0_rd_out[134]
  PIN r0_rd_out[135]
    DIRECTION OUTPUT ;
    USE SIGNAL ;
    SHAPE ABUTMENT ;
    PORT
      LAYER metal2 ;
      RECT 176.665 0.000 176.735 0.210 ;
    END
  END r0_rd_out[135]
  PIN r0_rd_out[136]
    DIRECTION OUTPUT ;
    USE SIGNAL ;
    SHAPE ABUTMENT ;
    PORT
      LAYER metal2 ;
      RECT 177.045 0.000 177.115 0.210 ;
    END
  END r0_rd_out[136]
  PIN r0_rd_out[137]
    DIRECTION OUTPUT ;
    USE SIGNAL ;
    SHAPE ABUTMENT ;
    PORT
      LAYER metal2 ;
      RECT 177.425 0.000 177.495 0.210 ;
    END
  END r0_rd_out[137]
  PIN r0_rd_out[138]
    DIRECTION OUTPUT ;
    USE SIGNAL ;
    SHAPE ABUTMENT ;
    PORT
      LAYER metal2 ;
      RECT 177.805 0.000 177.875 0.210 ;
    END
  END r0_rd_out[138]
  PIN r0_rd_out[139]
    DIRECTION OUTPUT ;
    USE SIGNAL ;
    SHAPE ABUTMENT ;
    PORT
      LAYER metal2 ;
      RECT 178.185 0.000 178.255 0.210 ;
    END
  END r0_rd_out[139]
  PIN r0_rd_out[140]
    DIRECTION OUTPUT ;
    USE SIGNAL ;
    SHAPE ABUTMENT ;
    PORT
      LAYER metal2 ;
      RECT 178.565 0.000 178.635 0.210 ;
    END
  END r0_rd_out[140]
  PIN r0_rd_out[141]
    DIRECTION OUTPUT ;
    USE SIGNAL ;
    SHAPE ABUTMENT ;
    PORT
      LAYER metal2 ;
      RECT 178.945 0.000 179.015 0.210 ;
    END
  END r0_rd_out[141]
  PIN r0_rd_out[142]
    DIRECTION OUTPUT ;
    USE SIGNAL ;
    SHAPE ABUTMENT ;
    PORT
      LAYER metal2 ;
      RECT 179.325 0.000 179.395 0.210 ;
    END
  END r0_rd_out[142]
  PIN r0_rd_out[143]
    DIRECTION OUTPUT ;
    USE SIGNAL ;
    SHAPE ABUTMENT ;
    PORT
      LAYER metal2 ;
      RECT 179.705 0.000 179.775 0.210 ;
    END
  END r0_rd_out[143]
  PIN r0_rd_out[144]
    DIRECTION OUTPUT ;
    USE SIGNAL ;
    SHAPE ABUTMENT ;
    PORT
      LAYER metal2 ;
      RECT 180.085 0.000 180.155 0.210 ;
    END
  END r0_rd_out[144]
  PIN r0_rd_out[145]
    DIRECTION OUTPUT ;
    USE SIGNAL ;
    SHAPE ABUTMENT ;
    PORT
      LAYER metal2 ;
      RECT 180.465 0.000 180.535 0.210 ;
    END
  END r0_rd_out[145]
  PIN r0_rd_out[146]
    DIRECTION OUTPUT ;
    USE SIGNAL ;
    SHAPE ABUTMENT ;
    PORT
      LAYER metal2 ;
      RECT 180.845 0.000 180.915 0.210 ;
    END
  END r0_rd_out[146]
  PIN r0_rd_out[147]
    DIRECTION OUTPUT ;
    USE SIGNAL ;
    SHAPE ABUTMENT ;
    PORT
      LAYER metal2 ;
      RECT 181.225 0.000 181.295 0.210 ;
    END
  END r0_rd_out[147]
  PIN r0_rd_out[148]
    DIRECTION OUTPUT ;
    USE SIGNAL ;
    SHAPE ABUTMENT ;
    PORT
      LAYER metal2 ;
      RECT 181.605 0.000 181.675 0.210 ;
    END
  END r0_rd_out[148]
  PIN r0_rd_out[149]
    DIRECTION OUTPUT ;
    USE SIGNAL ;
    SHAPE ABUTMENT ;
    PORT
      LAYER metal2 ;
      RECT 181.985 0.000 182.055 0.210 ;
    END
  END r0_rd_out[149]
  PIN r0_rd_out[150]
    DIRECTION OUTPUT ;
    USE SIGNAL ;
    SHAPE ABUTMENT ;
    PORT
      LAYER metal2 ;
      RECT 182.365 0.000 182.435 0.210 ;
    END
  END r0_rd_out[150]
  PIN r0_rd_out[151]
    DIRECTION OUTPUT ;
    USE SIGNAL ;
    SHAPE ABUTMENT ;
    PORT
      LAYER metal2 ;
      RECT 182.745 0.000 182.815 0.210 ;
    END
  END r0_rd_out[151]
  PIN r0_rd_out[152]
    DIRECTION OUTPUT ;
    USE SIGNAL ;
    SHAPE ABUTMENT ;
    PORT
      LAYER metal2 ;
      RECT 183.125 0.000 183.195 0.210 ;
    END
  END r0_rd_out[152]
  PIN r0_rd_out[153]
    DIRECTION OUTPUT ;
    USE SIGNAL ;
    SHAPE ABUTMENT ;
    PORT
      LAYER metal2 ;
      RECT 183.505 0.000 183.575 0.210 ;
    END
  END r0_rd_out[153]
  PIN r0_rd_out[154]
    DIRECTION OUTPUT ;
    USE SIGNAL ;
    SHAPE ABUTMENT ;
    PORT
      LAYER metal2 ;
      RECT 183.885 0.000 183.955 0.210 ;
    END
  END r0_rd_out[154]
  PIN r0_rd_out[155]
    DIRECTION OUTPUT ;
    USE SIGNAL ;
    SHAPE ABUTMENT ;
    PORT
      LAYER metal2 ;
      RECT 184.265 0.000 184.335 0.210 ;
    END
  END r0_rd_out[155]
  PIN r0_rd_out[156]
    DIRECTION OUTPUT ;
    USE SIGNAL ;
    SHAPE ABUTMENT ;
    PORT
      LAYER metal2 ;
      RECT 184.645 0.000 184.715 0.210 ;
    END
  END r0_rd_out[156]
  PIN r0_rd_out[157]
    DIRECTION OUTPUT ;
    USE SIGNAL ;
    SHAPE ABUTMENT ;
    PORT
      LAYER metal2 ;
      RECT 185.025 0.000 185.095 0.210 ;
    END
  END r0_rd_out[157]
  PIN r0_rd_out[158]
    DIRECTION OUTPUT ;
    USE SIGNAL ;
    SHAPE ABUTMENT ;
    PORT
      LAYER metal2 ;
      RECT 185.405 0.000 185.475 0.210 ;
    END
  END r0_rd_out[158]
  PIN r0_rd_out[159]
    DIRECTION OUTPUT ;
    USE SIGNAL ;
    SHAPE ABUTMENT ;
    PORT
      LAYER metal2 ;
      RECT 185.785 0.000 185.855 0.210 ;
    END
  END r0_rd_out[159]
  PIN r0_rd_out[160]
    DIRECTION OUTPUT ;
    USE SIGNAL ;
    SHAPE ABUTMENT ;
    PORT
      LAYER metal2 ;
      RECT 186.165 0.000 186.235 0.210 ;
    END
  END r0_rd_out[160]
  PIN r0_rd_out[161]
    DIRECTION OUTPUT ;
    USE SIGNAL ;
    SHAPE ABUTMENT ;
    PORT
      LAYER metal2 ;
      RECT 186.545 0.000 186.615 0.210 ;
    END
  END r0_rd_out[161]
  PIN r0_rd_out[162]
    DIRECTION OUTPUT ;
    USE SIGNAL ;
    SHAPE ABUTMENT ;
    PORT
      LAYER metal2 ;
      RECT 186.925 0.000 186.995 0.210 ;
    END
  END r0_rd_out[162]
  PIN r0_rd_out[163]
    DIRECTION OUTPUT ;
    USE SIGNAL ;
    SHAPE ABUTMENT ;
    PORT
      LAYER metal2 ;
      RECT 187.305 0.000 187.375 0.210 ;
    END
  END r0_rd_out[163]
  PIN r0_rd_out[164]
    DIRECTION OUTPUT ;
    USE SIGNAL ;
    SHAPE ABUTMENT ;
    PORT
      LAYER metal2 ;
      RECT 187.685 0.000 187.755 0.210 ;
    END
  END r0_rd_out[164]
  PIN r0_rd_out[165]
    DIRECTION OUTPUT ;
    USE SIGNAL ;
    SHAPE ABUTMENT ;
    PORT
      LAYER metal2 ;
      RECT 188.065 0.000 188.135 0.210 ;
    END
  END r0_rd_out[165]
  PIN r0_rd_out[166]
    DIRECTION OUTPUT ;
    USE SIGNAL ;
    SHAPE ABUTMENT ;
    PORT
      LAYER metal2 ;
      RECT 188.445 0.000 188.515 0.210 ;
    END
  END r0_rd_out[166]
  PIN r0_rd_out[167]
    DIRECTION OUTPUT ;
    USE SIGNAL ;
    SHAPE ABUTMENT ;
    PORT
      LAYER metal2 ;
      RECT 188.825 0.000 188.895 0.210 ;
    END
  END r0_rd_out[167]
  PIN r0_rd_out[168]
    DIRECTION OUTPUT ;
    USE SIGNAL ;
    SHAPE ABUTMENT ;
    PORT
      LAYER metal2 ;
      RECT 189.205 0.000 189.275 0.210 ;
    END
  END r0_rd_out[168]
  PIN r0_rd_out[169]
    DIRECTION OUTPUT ;
    USE SIGNAL ;
    SHAPE ABUTMENT ;
    PORT
      LAYER metal2 ;
      RECT 189.585 0.000 189.655 0.210 ;
    END
  END r0_rd_out[169]
  PIN r0_rd_out[170]
    DIRECTION OUTPUT ;
    USE SIGNAL ;
    SHAPE ABUTMENT ;
    PORT
      LAYER metal2 ;
      RECT 189.965 0.000 190.035 0.210 ;
    END
  END r0_rd_out[170]
  PIN r0_rd_out[171]
    DIRECTION OUTPUT ;
    USE SIGNAL ;
    SHAPE ABUTMENT ;
    PORT
      LAYER metal2 ;
      RECT 190.345 0.000 190.415 0.210 ;
    END
  END r0_rd_out[171]
  PIN r0_rd_out[172]
    DIRECTION OUTPUT ;
    USE SIGNAL ;
    SHAPE ABUTMENT ;
    PORT
      LAYER metal2 ;
      RECT 190.725 0.000 190.795 0.210 ;
    END
  END r0_rd_out[172]
  PIN r0_rd_out[173]
    DIRECTION OUTPUT ;
    USE SIGNAL ;
    SHAPE ABUTMENT ;
    PORT
      LAYER metal2 ;
      RECT 191.105 0.000 191.175 0.210 ;
    END
  END r0_rd_out[173]
  PIN r0_rd_out[174]
    DIRECTION OUTPUT ;
    USE SIGNAL ;
    SHAPE ABUTMENT ;
    PORT
      LAYER metal2 ;
      RECT 191.485 0.000 191.555 0.210 ;
    END
  END r0_rd_out[174]
  PIN r0_rd_out[175]
    DIRECTION OUTPUT ;
    USE SIGNAL ;
    SHAPE ABUTMENT ;
    PORT
      LAYER metal2 ;
      RECT 191.865 0.000 191.935 0.210 ;
    END
  END r0_rd_out[175]
  PIN r0_rd_out[176]
    DIRECTION OUTPUT ;
    USE SIGNAL ;
    SHAPE ABUTMENT ;
    PORT
      LAYER metal2 ;
      RECT 192.245 0.000 192.315 0.210 ;
    END
  END r0_rd_out[176]
  PIN r0_rd_out[177]
    DIRECTION OUTPUT ;
    USE SIGNAL ;
    SHAPE ABUTMENT ;
    PORT
      LAYER metal2 ;
      RECT 192.625 0.000 192.695 0.210 ;
    END
  END r0_rd_out[177]
  PIN r0_rd_out[178]
    DIRECTION OUTPUT ;
    USE SIGNAL ;
    SHAPE ABUTMENT ;
    PORT
      LAYER metal2 ;
      RECT 193.005 0.000 193.075 0.210 ;
    END
  END r0_rd_out[178]
  PIN r0_rd_out[179]
    DIRECTION OUTPUT ;
    USE SIGNAL ;
    SHAPE ABUTMENT ;
    PORT
      LAYER metal2 ;
      RECT 193.385 0.000 193.455 0.210 ;
    END
  END r0_rd_out[179]
  PIN r0_rd_out[180]
    DIRECTION OUTPUT ;
    USE SIGNAL ;
    SHAPE ABUTMENT ;
    PORT
      LAYER metal2 ;
      RECT 193.765 0.000 193.835 0.210 ;
    END
  END r0_rd_out[180]
  PIN r0_rd_out[181]
    DIRECTION OUTPUT ;
    USE SIGNAL ;
    SHAPE ABUTMENT ;
    PORT
      LAYER metal2 ;
      RECT 194.145 0.000 194.215 0.210 ;
    END
  END r0_rd_out[181]
  PIN r0_rd_out[182]
    DIRECTION OUTPUT ;
    USE SIGNAL ;
    SHAPE ABUTMENT ;
    PORT
      LAYER metal2 ;
      RECT 194.525 0.000 194.595 0.210 ;
    END
  END r0_rd_out[182]
  PIN r0_rd_out[183]
    DIRECTION OUTPUT ;
    USE SIGNAL ;
    SHAPE ABUTMENT ;
    PORT
      LAYER metal2 ;
      RECT 194.905 0.000 194.975 0.210 ;
    END
  END r0_rd_out[183]
  PIN r0_rd_out[184]
    DIRECTION OUTPUT ;
    USE SIGNAL ;
    SHAPE ABUTMENT ;
    PORT
      LAYER metal2 ;
      RECT 195.285 0.000 195.355 0.210 ;
    END
  END r0_rd_out[184]
  PIN r0_rd_out[185]
    DIRECTION OUTPUT ;
    USE SIGNAL ;
    SHAPE ABUTMENT ;
    PORT
      LAYER metal2 ;
      RECT 195.665 0.000 195.735 0.210 ;
    END
  END r0_rd_out[185]
  PIN r0_rd_out[186]
    DIRECTION OUTPUT ;
    USE SIGNAL ;
    SHAPE ABUTMENT ;
    PORT
      LAYER metal2 ;
      RECT 196.045 0.000 196.115 0.210 ;
    END
  END r0_rd_out[186]
  PIN r0_rd_out[187]
    DIRECTION OUTPUT ;
    USE SIGNAL ;
    SHAPE ABUTMENT ;
    PORT
      LAYER metal2 ;
      RECT 196.425 0.000 196.495 0.210 ;
    END
  END r0_rd_out[187]
  PIN r0_rd_out[188]
    DIRECTION OUTPUT ;
    USE SIGNAL ;
    SHAPE ABUTMENT ;
    PORT
      LAYER metal2 ;
      RECT 196.805 0.000 196.875 0.210 ;
    END
  END r0_rd_out[188]
  PIN r0_rd_out[189]
    DIRECTION OUTPUT ;
    USE SIGNAL ;
    SHAPE ABUTMENT ;
    PORT
      LAYER metal2 ;
      RECT 197.185 0.000 197.255 0.210 ;
    END
  END r0_rd_out[189]
  PIN r0_rd_out[190]
    DIRECTION OUTPUT ;
    USE SIGNAL ;
    SHAPE ABUTMENT ;
    PORT
      LAYER metal2 ;
      RECT 197.565 0.000 197.635 0.210 ;
    END
  END r0_rd_out[190]
  PIN r0_rd_out[191]
    DIRECTION OUTPUT ;
    USE SIGNAL ;
    SHAPE ABUTMENT ;
    PORT
      LAYER metal2 ;
      RECT 197.945 0.000 198.015 0.210 ;
    END
  END r0_rd_out[191]
  PIN r0_rd_out[192]
    DIRECTION OUTPUT ;
    USE SIGNAL ;
    SHAPE ABUTMENT ;
    PORT
      LAYER metal2 ;
      RECT 198.325 0.000 198.395 0.210 ;
    END
  END r0_rd_out[192]
  PIN r0_rd_out[193]
    DIRECTION OUTPUT ;
    USE SIGNAL ;
    SHAPE ABUTMENT ;
    PORT
      LAYER metal2 ;
      RECT 198.705 0.000 198.775 0.210 ;
    END
  END r0_rd_out[193]
  PIN r0_rd_out[194]
    DIRECTION OUTPUT ;
    USE SIGNAL ;
    SHAPE ABUTMENT ;
    PORT
      LAYER metal2 ;
      RECT 199.085 0.000 199.155 0.210 ;
    END
  END r0_rd_out[194]
  PIN r0_rd_out[195]
    DIRECTION OUTPUT ;
    USE SIGNAL ;
    SHAPE ABUTMENT ;
    PORT
      LAYER metal2 ;
      RECT 199.465 0.000 199.535 0.210 ;
    END
  END r0_rd_out[195]
  PIN r0_rd_out[196]
    DIRECTION OUTPUT ;
    USE SIGNAL ;
    SHAPE ABUTMENT ;
    PORT
      LAYER metal2 ;
      RECT 199.845 0.000 199.915 0.210 ;
    END
  END r0_rd_out[196]
  PIN r0_rd_out[197]
    DIRECTION OUTPUT ;
    USE SIGNAL ;
    SHAPE ABUTMENT ;
    PORT
      LAYER metal2 ;
      RECT 200.225 0.000 200.295 0.210 ;
    END
  END r0_rd_out[197]
  PIN r0_rd_out[198]
    DIRECTION OUTPUT ;
    USE SIGNAL ;
    SHAPE ABUTMENT ;
    PORT
      LAYER metal2 ;
      RECT 200.605 0.000 200.675 0.210 ;
    END
  END r0_rd_out[198]
  PIN r0_rd_out[199]
    DIRECTION OUTPUT ;
    USE SIGNAL ;
    SHAPE ABUTMENT ;
    PORT
      LAYER metal2 ;
      RECT 200.985 0.000 201.055 0.210 ;
    END
  END r0_rd_out[199]
  PIN r0_rd_out[200]
    DIRECTION OUTPUT ;
    USE SIGNAL ;
    SHAPE ABUTMENT ;
    PORT
      LAYER metal2 ;
      RECT 201.365 0.000 201.435 0.210 ;
    END
  END r0_rd_out[200]
  PIN r0_rd_out[201]
    DIRECTION OUTPUT ;
    USE SIGNAL ;
    SHAPE ABUTMENT ;
    PORT
      LAYER metal2 ;
      RECT 201.745 0.000 201.815 0.210 ;
    END
  END r0_rd_out[201]
  PIN r0_rd_out[202]
    DIRECTION OUTPUT ;
    USE SIGNAL ;
    SHAPE ABUTMENT ;
    PORT
      LAYER metal2 ;
      RECT 202.125 0.000 202.195 0.210 ;
    END
  END r0_rd_out[202]
  PIN r0_rd_out[203]
    DIRECTION OUTPUT ;
    USE SIGNAL ;
    SHAPE ABUTMENT ;
    PORT
      LAYER metal2 ;
      RECT 202.505 0.000 202.575 0.210 ;
    END
  END r0_rd_out[203]
  PIN r0_rd_out[204]
    DIRECTION OUTPUT ;
    USE SIGNAL ;
    SHAPE ABUTMENT ;
    PORT
      LAYER metal2 ;
      RECT 202.885 0.000 202.955 0.210 ;
    END
  END r0_rd_out[204]
  PIN r0_rd_out[205]
    DIRECTION OUTPUT ;
    USE SIGNAL ;
    SHAPE ABUTMENT ;
    PORT
      LAYER metal2 ;
      RECT 203.265 0.000 203.335 0.210 ;
    END
  END r0_rd_out[205]
  PIN r0_rd_out[206]
    DIRECTION OUTPUT ;
    USE SIGNAL ;
    SHAPE ABUTMENT ;
    PORT
      LAYER metal2 ;
      RECT 203.645 0.000 203.715 0.210 ;
    END
  END r0_rd_out[206]
  PIN r0_rd_out[207]
    DIRECTION OUTPUT ;
    USE SIGNAL ;
    SHAPE ABUTMENT ;
    PORT
      LAYER metal2 ;
      RECT 204.025 0.000 204.095 0.210 ;
    END
  END r0_rd_out[207]
  PIN r0_rd_out[208]
    DIRECTION OUTPUT ;
    USE SIGNAL ;
    SHAPE ABUTMENT ;
    PORT
      LAYER metal2 ;
      RECT 204.405 0.000 204.475 0.210 ;
    END
  END r0_rd_out[208]
  PIN r0_rd_out[209]
    DIRECTION OUTPUT ;
    USE SIGNAL ;
    SHAPE ABUTMENT ;
    PORT
      LAYER metal2 ;
      RECT 204.785 0.000 204.855 0.210 ;
    END
  END r0_rd_out[209]
  PIN r0_rd_out[210]
    DIRECTION OUTPUT ;
    USE SIGNAL ;
    SHAPE ABUTMENT ;
    PORT
      LAYER metal2 ;
      RECT 205.165 0.000 205.235 0.210 ;
    END
  END r0_rd_out[210]
  PIN r0_rd_out[211]
    DIRECTION OUTPUT ;
    USE SIGNAL ;
    SHAPE ABUTMENT ;
    PORT
      LAYER metal2 ;
      RECT 205.545 0.000 205.615 0.210 ;
    END
  END r0_rd_out[211]
  PIN r0_rd_out[212]
    DIRECTION OUTPUT ;
    USE SIGNAL ;
    SHAPE ABUTMENT ;
    PORT
      LAYER metal2 ;
      RECT 205.925 0.000 205.995 0.210 ;
    END
  END r0_rd_out[212]
  PIN r0_rd_out[213]
    DIRECTION OUTPUT ;
    USE SIGNAL ;
    SHAPE ABUTMENT ;
    PORT
      LAYER metal2 ;
      RECT 206.305 0.000 206.375 0.210 ;
    END
  END r0_rd_out[213]
  PIN r0_rd_out[214]
    DIRECTION OUTPUT ;
    USE SIGNAL ;
    SHAPE ABUTMENT ;
    PORT
      LAYER metal2 ;
      RECT 206.685 0.000 206.755 0.210 ;
    END
  END r0_rd_out[214]
  PIN r0_rd_out[215]
    DIRECTION OUTPUT ;
    USE SIGNAL ;
    SHAPE ABUTMENT ;
    PORT
      LAYER metal2 ;
      RECT 207.065 0.000 207.135 0.210 ;
    END
  END r0_rd_out[215]
  PIN r0_rd_out[216]
    DIRECTION OUTPUT ;
    USE SIGNAL ;
    SHAPE ABUTMENT ;
    PORT
      LAYER metal2 ;
      RECT 207.445 0.000 207.515 0.210 ;
    END
  END r0_rd_out[216]
  PIN r0_rd_out[217]
    DIRECTION OUTPUT ;
    USE SIGNAL ;
    SHAPE ABUTMENT ;
    PORT
      LAYER metal2 ;
      RECT 207.825 0.000 207.895 0.210 ;
    END
  END r0_rd_out[217]
  PIN r0_rd_out[218]
    DIRECTION OUTPUT ;
    USE SIGNAL ;
    SHAPE ABUTMENT ;
    PORT
      LAYER metal2 ;
      RECT 208.205 0.000 208.275 0.210 ;
    END
  END r0_rd_out[218]
  PIN r0_rd_out[219]
    DIRECTION OUTPUT ;
    USE SIGNAL ;
    SHAPE ABUTMENT ;
    PORT
      LAYER metal2 ;
      RECT 208.585 0.000 208.655 0.210 ;
    END
  END r0_rd_out[219]
  PIN r0_rd_out[220]
    DIRECTION OUTPUT ;
    USE SIGNAL ;
    SHAPE ABUTMENT ;
    PORT
      LAYER metal2 ;
      RECT 208.965 0.000 209.035 0.210 ;
    END
  END r0_rd_out[220]
  PIN r0_rd_out[221]
    DIRECTION OUTPUT ;
    USE SIGNAL ;
    SHAPE ABUTMENT ;
    PORT
      LAYER metal2 ;
      RECT 209.345 0.000 209.415 0.210 ;
    END
  END r0_rd_out[221]
  PIN r0_rd_out[222]
    DIRECTION OUTPUT ;
    USE SIGNAL ;
    SHAPE ABUTMENT ;
    PORT
      LAYER metal2 ;
      RECT 209.725 0.000 209.795 0.210 ;
    END
  END r0_rd_out[222]
  PIN r0_rd_out[223]
    DIRECTION OUTPUT ;
    USE SIGNAL ;
    SHAPE ABUTMENT ;
    PORT
      LAYER metal2 ;
      RECT 210.105 0.000 210.175 0.210 ;
    END
  END r0_rd_out[223]
  PIN r0_rd_out[224]
    DIRECTION OUTPUT ;
    USE SIGNAL ;
    SHAPE ABUTMENT ;
    PORT
      LAYER metal2 ;
      RECT 210.485 0.000 210.555 0.210 ;
    END
  END r0_rd_out[224]
  PIN r0_rd_out[225]
    DIRECTION OUTPUT ;
    USE SIGNAL ;
    SHAPE ABUTMENT ;
    PORT
      LAYER metal2 ;
      RECT 210.865 0.000 210.935 0.210 ;
    END
  END r0_rd_out[225]
  PIN r0_rd_out[226]
    DIRECTION OUTPUT ;
    USE SIGNAL ;
    SHAPE ABUTMENT ;
    PORT
      LAYER metal2 ;
      RECT 211.245 0.000 211.315 0.210 ;
    END
  END r0_rd_out[226]
  PIN r0_rd_out[227]
    DIRECTION OUTPUT ;
    USE SIGNAL ;
    SHAPE ABUTMENT ;
    PORT
      LAYER metal2 ;
      RECT 211.625 0.000 211.695 0.210 ;
    END
  END r0_rd_out[227]
  PIN r0_rd_out[228]
    DIRECTION OUTPUT ;
    USE SIGNAL ;
    SHAPE ABUTMENT ;
    PORT
      LAYER metal2 ;
      RECT 212.005 0.000 212.075 0.210 ;
    END
  END r0_rd_out[228]
  PIN r0_rd_out[229]
    DIRECTION OUTPUT ;
    USE SIGNAL ;
    SHAPE ABUTMENT ;
    PORT
      LAYER metal2 ;
      RECT 212.385 0.000 212.455 0.210 ;
    END
  END r0_rd_out[229]
  PIN r0_rd_out[230]
    DIRECTION OUTPUT ;
    USE SIGNAL ;
    SHAPE ABUTMENT ;
    PORT
      LAYER metal2 ;
      RECT 212.765 0.000 212.835 0.210 ;
    END
  END r0_rd_out[230]
  PIN r0_rd_out[231]
    DIRECTION OUTPUT ;
    USE SIGNAL ;
    SHAPE ABUTMENT ;
    PORT
      LAYER metal2 ;
      RECT 213.145 0.000 213.215 0.210 ;
    END
  END r0_rd_out[231]
  PIN r0_rd_out[232]
    DIRECTION OUTPUT ;
    USE SIGNAL ;
    SHAPE ABUTMENT ;
    PORT
      LAYER metal2 ;
      RECT 213.525 0.000 213.595 0.210 ;
    END
  END r0_rd_out[232]
  PIN r0_rd_out[233]
    DIRECTION OUTPUT ;
    USE SIGNAL ;
    SHAPE ABUTMENT ;
    PORT
      LAYER metal2 ;
      RECT 213.905 0.000 213.975 0.210 ;
    END
  END r0_rd_out[233]
  PIN r0_rd_out[234]
    DIRECTION OUTPUT ;
    USE SIGNAL ;
    SHAPE ABUTMENT ;
    PORT
      LAYER metal2 ;
      RECT 214.285 0.000 214.355 0.210 ;
    END
  END r0_rd_out[234]
  PIN r0_rd_out[235]
    DIRECTION OUTPUT ;
    USE SIGNAL ;
    SHAPE ABUTMENT ;
    PORT
      LAYER metal2 ;
      RECT 214.665 0.000 214.735 0.210 ;
    END
  END r0_rd_out[235]
  PIN r0_rd_out[236]
    DIRECTION OUTPUT ;
    USE SIGNAL ;
    SHAPE ABUTMENT ;
    PORT
      LAYER metal2 ;
      RECT 215.045 0.000 215.115 0.210 ;
    END
  END r0_rd_out[236]
  PIN r0_rd_out[237]
    DIRECTION OUTPUT ;
    USE SIGNAL ;
    SHAPE ABUTMENT ;
    PORT
      LAYER metal2 ;
      RECT 215.425 0.000 215.495 0.210 ;
    END
  END r0_rd_out[237]
  PIN r0_rd_out[238]
    DIRECTION OUTPUT ;
    USE SIGNAL ;
    SHAPE ABUTMENT ;
    PORT
      LAYER metal2 ;
      RECT 215.805 0.000 215.875 0.210 ;
    END
  END r0_rd_out[238]
  PIN r0_rd_out[239]
    DIRECTION OUTPUT ;
    USE SIGNAL ;
    SHAPE ABUTMENT ;
    PORT
      LAYER metal2 ;
      RECT 216.185 0.000 216.255 0.210 ;
    END
  END r0_rd_out[239]
  PIN r0_rd_out[240]
    DIRECTION OUTPUT ;
    USE SIGNAL ;
    SHAPE ABUTMENT ;
    PORT
      LAYER metal2 ;
      RECT 216.565 0.000 216.635 0.210 ;
    END
  END r0_rd_out[240]
  PIN r0_rd_out[241]
    DIRECTION OUTPUT ;
    USE SIGNAL ;
    SHAPE ABUTMENT ;
    PORT
      LAYER metal2 ;
      RECT 216.945 0.000 217.015 0.210 ;
    END
  END r0_rd_out[241]
  PIN r0_rd_out[242]
    DIRECTION OUTPUT ;
    USE SIGNAL ;
    SHAPE ABUTMENT ;
    PORT
      LAYER metal2 ;
      RECT 217.325 0.000 217.395 0.210 ;
    END
  END r0_rd_out[242]
  PIN r0_rd_out[243]
    DIRECTION OUTPUT ;
    USE SIGNAL ;
    SHAPE ABUTMENT ;
    PORT
      LAYER metal2 ;
      RECT 217.705 0.000 217.775 0.210 ;
    END
  END r0_rd_out[243]
  PIN r0_rd_out[244]
    DIRECTION OUTPUT ;
    USE SIGNAL ;
    SHAPE ABUTMENT ;
    PORT
      LAYER metal2 ;
      RECT 218.085 0.000 218.155 0.210 ;
    END
  END r0_rd_out[244]
  PIN r0_rd_out[245]
    DIRECTION OUTPUT ;
    USE SIGNAL ;
    SHAPE ABUTMENT ;
    PORT
      LAYER metal2 ;
      RECT 218.465 0.000 218.535 0.210 ;
    END
  END r0_rd_out[245]
  PIN r0_rd_out[246]
    DIRECTION OUTPUT ;
    USE SIGNAL ;
    SHAPE ABUTMENT ;
    PORT
      LAYER metal2 ;
      RECT 218.845 0.000 218.915 0.210 ;
    END
  END r0_rd_out[246]
  PIN r0_rd_out[247]
    DIRECTION OUTPUT ;
    USE SIGNAL ;
    SHAPE ABUTMENT ;
    PORT
      LAYER metal2 ;
      RECT 219.225 0.000 219.295 0.210 ;
    END
  END r0_rd_out[247]
  PIN r0_rd_out[248]
    DIRECTION OUTPUT ;
    USE SIGNAL ;
    SHAPE ABUTMENT ;
    PORT
      LAYER metal2 ;
      RECT 219.605 0.000 219.675 0.210 ;
    END
  END r0_rd_out[248]
  PIN r0_rd_out[249]
    DIRECTION OUTPUT ;
    USE SIGNAL ;
    SHAPE ABUTMENT ;
    PORT
      LAYER metal2 ;
      RECT 219.985 0.000 220.055 0.210 ;
    END
  END r0_rd_out[249]
  PIN r0_rd_out[250]
    DIRECTION OUTPUT ;
    USE SIGNAL ;
    SHAPE ABUTMENT ;
    PORT
      LAYER metal2 ;
      RECT 220.365 0.000 220.435 0.210 ;
    END
  END r0_rd_out[250]
  PIN r0_rd_out[251]
    DIRECTION OUTPUT ;
    USE SIGNAL ;
    SHAPE ABUTMENT ;
    PORT
      LAYER metal2 ;
      RECT 220.745 0.000 220.815 0.210 ;
    END
  END r0_rd_out[251]
  PIN r0_rd_out[252]
    DIRECTION OUTPUT ;
    USE SIGNAL ;
    SHAPE ABUTMENT ;
    PORT
      LAYER metal2 ;
      RECT 221.125 0.000 221.195 0.210 ;
    END
  END r0_rd_out[252]
  PIN r0_rd_out[253]
    DIRECTION OUTPUT ;
    USE SIGNAL ;
    SHAPE ABUTMENT ;
    PORT
      LAYER metal2 ;
      RECT 221.505 0.000 221.575 0.210 ;
    END
  END r0_rd_out[253]
  PIN r0_rd_out[254]
    DIRECTION OUTPUT ;
    USE SIGNAL ;
    SHAPE ABUTMENT ;
    PORT
      LAYER metal2 ;
      RECT 221.885 0.000 221.955 0.210 ;
    END
  END r0_rd_out[254]
  PIN r0_rd_out[255]
    DIRECTION OUTPUT ;
    USE SIGNAL ;
    SHAPE ABUTMENT ;
    PORT
      LAYER metal2 ;
      RECT 222.265 0.000 222.335 0.210 ;
    END
  END r0_rd_out[255]
  PIN r0_rd_out[256]
    DIRECTION OUTPUT ;
    USE SIGNAL ;
    SHAPE ABUTMENT ;
    PORT
      LAYER metal2 ;
      RECT 222.645 0.000 222.715 0.210 ;
    END
  END r0_rd_out[256]
  PIN r0_rd_out[257]
    DIRECTION OUTPUT ;
    USE SIGNAL ;
    SHAPE ABUTMENT ;
    PORT
      LAYER metal2 ;
      RECT 223.025 0.000 223.095 0.210 ;
    END
  END r0_rd_out[257]
  PIN r0_rd_out[258]
    DIRECTION OUTPUT ;
    USE SIGNAL ;
    SHAPE ABUTMENT ;
    PORT
      LAYER metal2 ;
      RECT 223.405 0.000 223.475 0.210 ;
    END
  END r0_rd_out[258]
  PIN r0_rd_out[259]
    DIRECTION OUTPUT ;
    USE SIGNAL ;
    SHAPE ABUTMENT ;
    PORT
      LAYER metal2 ;
      RECT 223.785 0.000 223.855 0.210 ;
    END
  END r0_rd_out[259]
  PIN r0_rd_out[260]
    DIRECTION OUTPUT ;
    USE SIGNAL ;
    SHAPE ABUTMENT ;
    PORT
      LAYER metal2 ;
      RECT 224.165 0.000 224.235 0.210 ;
    END
  END r0_rd_out[260]
  PIN r0_rd_out[261]
    DIRECTION OUTPUT ;
    USE SIGNAL ;
    SHAPE ABUTMENT ;
    PORT
      LAYER metal2 ;
      RECT 224.545 0.000 224.615 0.210 ;
    END
  END r0_rd_out[261]
  PIN r0_rd_out[262]
    DIRECTION OUTPUT ;
    USE SIGNAL ;
    SHAPE ABUTMENT ;
    PORT
      LAYER metal2 ;
      RECT 224.925 0.000 224.995 0.210 ;
    END
  END r0_rd_out[262]
  PIN r0_rd_out[263]
    DIRECTION OUTPUT ;
    USE SIGNAL ;
    SHAPE ABUTMENT ;
    PORT
      LAYER metal2 ;
      RECT 225.305 0.000 225.375 0.210 ;
    END
  END r0_rd_out[263]
  PIN r0_rd_out[264]
    DIRECTION OUTPUT ;
    USE SIGNAL ;
    SHAPE ABUTMENT ;
    PORT
      LAYER metal2 ;
      RECT 225.685 0.000 225.755 0.210 ;
    END
  END r0_rd_out[264]
  PIN r0_rd_out[265]
    DIRECTION OUTPUT ;
    USE SIGNAL ;
    SHAPE ABUTMENT ;
    PORT
      LAYER metal2 ;
      RECT 226.065 0.000 226.135 0.210 ;
    END
  END r0_rd_out[265]
  PIN r0_rd_out[266]
    DIRECTION OUTPUT ;
    USE SIGNAL ;
    SHAPE ABUTMENT ;
    PORT
      LAYER metal2 ;
      RECT 226.445 0.000 226.515 0.210 ;
    END
  END r0_rd_out[266]
  PIN r0_rd_out[267]
    DIRECTION OUTPUT ;
    USE SIGNAL ;
    SHAPE ABUTMENT ;
    PORT
      LAYER metal2 ;
      RECT 226.825 0.000 226.895 0.210 ;
    END
  END r0_rd_out[267]
  PIN r0_rd_out[268]
    DIRECTION OUTPUT ;
    USE SIGNAL ;
    SHAPE ABUTMENT ;
    PORT
      LAYER metal2 ;
      RECT 227.205 0.000 227.275 0.210 ;
    END
  END r0_rd_out[268]
  PIN r0_rd_out[269]
    DIRECTION OUTPUT ;
    USE SIGNAL ;
    SHAPE ABUTMENT ;
    PORT
      LAYER metal2 ;
      RECT 227.585 0.000 227.655 0.210 ;
    END
  END r0_rd_out[269]
  PIN r0_rd_out[270]
    DIRECTION OUTPUT ;
    USE SIGNAL ;
    SHAPE ABUTMENT ;
    PORT
      LAYER metal2 ;
      RECT 227.965 0.000 228.035 0.210 ;
    END
  END r0_rd_out[270]
  PIN r0_rd_out[271]
    DIRECTION OUTPUT ;
    USE SIGNAL ;
    SHAPE ABUTMENT ;
    PORT
      LAYER metal2 ;
      RECT 228.345 0.000 228.415 0.210 ;
    END
  END r0_rd_out[271]
  PIN r0_rd_out[272]
    DIRECTION OUTPUT ;
    USE SIGNAL ;
    SHAPE ABUTMENT ;
    PORT
      LAYER metal2 ;
      RECT 228.725 0.000 228.795 0.210 ;
    END
  END r0_rd_out[272]
  PIN r0_rd_out[273]
    DIRECTION OUTPUT ;
    USE SIGNAL ;
    SHAPE ABUTMENT ;
    PORT
      LAYER metal2 ;
      RECT 229.105 0.000 229.175 0.210 ;
    END
  END r0_rd_out[273]
  PIN r0_rd_out[274]
    DIRECTION OUTPUT ;
    USE SIGNAL ;
    SHAPE ABUTMENT ;
    PORT
      LAYER metal2 ;
      RECT 229.485 0.000 229.555 0.210 ;
    END
  END r0_rd_out[274]
  PIN r0_rd_out[275]
    DIRECTION OUTPUT ;
    USE SIGNAL ;
    SHAPE ABUTMENT ;
    PORT
      LAYER metal2 ;
      RECT 229.865 0.000 229.935 0.210 ;
    END
  END r0_rd_out[275]
  PIN r0_rd_out[276]
    DIRECTION OUTPUT ;
    USE SIGNAL ;
    SHAPE ABUTMENT ;
    PORT
      LAYER metal2 ;
      RECT 230.245 0.000 230.315 0.210 ;
    END
  END r0_rd_out[276]
  PIN r0_rd_out[277]
    DIRECTION OUTPUT ;
    USE SIGNAL ;
    SHAPE ABUTMENT ;
    PORT
      LAYER metal2 ;
      RECT 230.625 0.000 230.695 0.210 ;
    END
  END r0_rd_out[277]
  PIN r0_rd_out[278]
    DIRECTION OUTPUT ;
    USE SIGNAL ;
    SHAPE ABUTMENT ;
    PORT
      LAYER metal2 ;
      RECT 231.005 0.000 231.075 0.210 ;
    END
  END r0_rd_out[278]
  PIN r0_rd_out[279]
    DIRECTION OUTPUT ;
    USE SIGNAL ;
    SHAPE ABUTMENT ;
    PORT
      LAYER metal2 ;
      RECT 231.385 0.000 231.455 0.210 ;
    END
  END r0_rd_out[279]
  PIN r0_rd_out[280]
    DIRECTION OUTPUT ;
    USE SIGNAL ;
    SHAPE ABUTMENT ;
    PORT
      LAYER metal2 ;
      RECT 231.765 0.000 231.835 0.210 ;
    END
  END r0_rd_out[280]
  PIN r0_rd_out[281]
    DIRECTION OUTPUT ;
    USE SIGNAL ;
    SHAPE ABUTMENT ;
    PORT
      LAYER metal2 ;
      RECT 232.145 0.000 232.215 0.210 ;
    END
  END r0_rd_out[281]
  PIN r0_rd_out[282]
    DIRECTION OUTPUT ;
    USE SIGNAL ;
    SHAPE ABUTMENT ;
    PORT
      LAYER metal2 ;
      RECT 232.525 0.000 232.595 0.210 ;
    END
  END r0_rd_out[282]
  PIN r0_rd_out[283]
    DIRECTION OUTPUT ;
    USE SIGNAL ;
    SHAPE ABUTMENT ;
    PORT
      LAYER metal2 ;
      RECT 232.905 0.000 232.975 0.210 ;
    END
  END r0_rd_out[283]
  PIN r0_rd_out[284]
    DIRECTION OUTPUT ;
    USE SIGNAL ;
    SHAPE ABUTMENT ;
    PORT
      LAYER metal2 ;
      RECT 233.285 0.000 233.355 0.210 ;
    END
  END r0_rd_out[284]
  PIN r0_rd_out[285]
    DIRECTION OUTPUT ;
    USE SIGNAL ;
    SHAPE ABUTMENT ;
    PORT
      LAYER metal2 ;
      RECT 233.665 0.000 233.735 0.210 ;
    END
  END r0_rd_out[285]
  PIN r0_rd_out[286]
    DIRECTION OUTPUT ;
    USE SIGNAL ;
    SHAPE ABUTMENT ;
    PORT
      LAYER metal2 ;
      RECT 234.045 0.000 234.115 0.210 ;
    END
  END r0_rd_out[286]
  PIN r0_rd_out[287]
    DIRECTION OUTPUT ;
    USE SIGNAL ;
    SHAPE ABUTMENT ;
    PORT
      LAYER metal2 ;
      RECT 234.425 0.000 234.495 0.210 ;
    END
  END r0_rd_out[287]
  PIN r0_rd_out[288]
    DIRECTION OUTPUT ;
    USE SIGNAL ;
    SHAPE ABUTMENT ;
    PORT
      LAYER metal2 ;
      RECT 234.805 0.000 234.875 0.210 ;
    END
  END r0_rd_out[288]
  PIN r0_rd_out[289]
    DIRECTION OUTPUT ;
    USE SIGNAL ;
    SHAPE ABUTMENT ;
    PORT
      LAYER metal2 ;
      RECT 235.185 0.000 235.255 0.210 ;
    END
  END r0_rd_out[289]
  PIN r0_rd_out[290]
    DIRECTION OUTPUT ;
    USE SIGNAL ;
    SHAPE ABUTMENT ;
    PORT
      LAYER metal2 ;
      RECT 235.565 0.000 235.635 0.210 ;
    END
  END r0_rd_out[290]
  PIN r0_rd_out[291]
    DIRECTION OUTPUT ;
    USE SIGNAL ;
    SHAPE ABUTMENT ;
    PORT
      LAYER metal2 ;
      RECT 235.945 0.000 236.015 0.210 ;
    END
  END r0_rd_out[291]
  PIN r0_rd_out[292]
    DIRECTION OUTPUT ;
    USE SIGNAL ;
    SHAPE ABUTMENT ;
    PORT
      LAYER metal2 ;
      RECT 236.325 0.000 236.395 0.210 ;
    END
  END r0_rd_out[292]
  PIN r0_rd_out[293]
    DIRECTION OUTPUT ;
    USE SIGNAL ;
    SHAPE ABUTMENT ;
    PORT
      LAYER metal2 ;
      RECT 236.705 0.000 236.775 0.210 ;
    END
  END r0_rd_out[293]
  PIN r0_rd_out[294]
    DIRECTION OUTPUT ;
    USE SIGNAL ;
    SHAPE ABUTMENT ;
    PORT
      LAYER metal2 ;
      RECT 237.085 0.000 237.155 0.210 ;
    END
  END r0_rd_out[294]
  PIN r0_rd_out[295]
    DIRECTION OUTPUT ;
    USE SIGNAL ;
    SHAPE ABUTMENT ;
    PORT
      LAYER metal2 ;
      RECT 237.465 0.000 237.535 0.210 ;
    END
  END r0_rd_out[295]
  PIN r0_rd_out[296]
    DIRECTION OUTPUT ;
    USE SIGNAL ;
    SHAPE ABUTMENT ;
    PORT
      LAYER metal2 ;
      RECT 237.845 0.000 237.915 0.210 ;
    END
  END r0_rd_out[296]
  PIN r0_rd_out[297]
    DIRECTION OUTPUT ;
    USE SIGNAL ;
    SHAPE ABUTMENT ;
    PORT
      LAYER metal2 ;
      RECT 238.225 0.000 238.295 0.210 ;
    END
  END r0_rd_out[297]
  PIN r0_rd_out[298]
    DIRECTION OUTPUT ;
    USE SIGNAL ;
    SHAPE ABUTMENT ;
    PORT
      LAYER metal2 ;
      RECT 238.605 0.000 238.675 0.210 ;
    END
  END r0_rd_out[298]
  PIN r0_rd_out[299]
    DIRECTION OUTPUT ;
    USE SIGNAL ;
    SHAPE ABUTMENT ;
    PORT
      LAYER metal2 ;
      RECT 238.985 0.000 239.055 0.210 ;
    END
  END r0_rd_out[299]
  PIN r0_rd_out[300]
    DIRECTION OUTPUT ;
    USE SIGNAL ;
    SHAPE ABUTMENT ;
    PORT
      LAYER metal2 ;
      RECT 239.365 0.000 239.435 0.210 ;
    END
  END r0_rd_out[300]
  PIN r0_rd_out[301]
    DIRECTION OUTPUT ;
    USE SIGNAL ;
    SHAPE ABUTMENT ;
    PORT
      LAYER metal2 ;
      RECT 239.745 0.000 239.815 0.210 ;
    END
  END r0_rd_out[301]
  PIN r0_rd_out[302]
    DIRECTION OUTPUT ;
    USE SIGNAL ;
    SHAPE ABUTMENT ;
    PORT
      LAYER metal2 ;
      RECT 240.125 0.000 240.195 0.210 ;
    END
  END r0_rd_out[302]
  PIN r0_rd_out[303]
    DIRECTION OUTPUT ;
    USE SIGNAL ;
    SHAPE ABUTMENT ;
    PORT
      LAYER metal2 ;
      RECT 240.505 0.000 240.575 0.210 ;
    END
  END r0_rd_out[303]
  PIN r0_rd_out[304]
    DIRECTION OUTPUT ;
    USE SIGNAL ;
    SHAPE ABUTMENT ;
    PORT
      LAYER metal2 ;
      RECT 240.885 0.000 240.955 0.210 ;
    END
  END r0_rd_out[304]
  PIN r0_rd_out[305]
    DIRECTION OUTPUT ;
    USE SIGNAL ;
    SHAPE ABUTMENT ;
    PORT
      LAYER metal2 ;
      RECT 241.265 0.000 241.335 0.210 ;
    END
  END r0_rd_out[305]
  PIN r0_rd_out[306]
    DIRECTION OUTPUT ;
    USE SIGNAL ;
    SHAPE ABUTMENT ;
    PORT
      LAYER metal2 ;
      RECT 241.645 0.000 241.715 0.210 ;
    END
  END r0_rd_out[306]
  PIN r0_rd_out[307]
    DIRECTION OUTPUT ;
    USE SIGNAL ;
    SHAPE ABUTMENT ;
    PORT
      LAYER metal2 ;
      RECT 242.025 0.000 242.095 0.210 ;
    END
  END r0_rd_out[307]
  PIN r0_rd_out[308]
    DIRECTION OUTPUT ;
    USE SIGNAL ;
    SHAPE ABUTMENT ;
    PORT
      LAYER metal2 ;
      RECT 242.405 0.000 242.475 0.210 ;
    END
  END r0_rd_out[308]
  PIN r0_rd_out[309]
    DIRECTION OUTPUT ;
    USE SIGNAL ;
    SHAPE ABUTMENT ;
    PORT
      LAYER metal2 ;
      RECT 242.785 0.000 242.855 0.210 ;
    END
  END r0_rd_out[309]
  PIN r0_rd_out[310]
    DIRECTION OUTPUT ;
    USE SIGNAL ;
    SHAPE ABUTMENT ;
    PORT
      LAYER metal2 ;
      RECT 243.165 0.000 243.235 0.210 ;
    END
  END r0_rd_out[310]
  PIN r0_rd_out[311]
    DIRECTION OUTPUT ;
    USE SIGNAL ;
    SHAPE ABUTMENT ;
    PORT
      LAYER metal2 ;
      RECT 243.545 0.000 243.615 0.210 ;
    END
  END r0_rd_out[311]
  PIN r0_rd_out[312]
    DIRECTION OUTPUT ;
    USE SIGNAL ;
    SHAPE ABUTMENT ;
    PORT
      LAYER metal2 ;
      RECT 243.925 0.000 243.995 0.210 ;
    END
  END r0_rd_out[312]
  PIN r0_rd_out[313]
    DIRECTION OUTPUT ;
    USE SIGNAL ;
    SHAPE ABUTMENT ;
    PORT
      LAYER metal2 ;
      RECT 244.305 0.000 244.375 0.210 ;
    END
  END r0_rd_out[313]
  PIN r0_rd_out[314]
    DIRECTION OUTPUT ;
    USE SIGNAL ;
    SHAPE ABUTMENT ;
    PORT
      LAYER metal2 ;
      RECT 244.685 0.000 244.755 0.210 ;
    END
  END r0_rd_out[314]
  PIN r0_rd_out[315]
    DIRECTION OUTPUT ;
    USE SIGNAL ;
    SHAPE ABUTMENT ;
    PORT
      LAYER metal2 ;
      RECT 245.065 0.000 245.135 0.210 ;
    END
  END r0_rd_out[315]
  PIN r0_rd_out[316]
    DIRECTION OUTPUT ;
    USE SIGNAL ;
    SHAPE ABUTMENT ;
    PORT
      LAYER metal2 ;
      RECT 245.445 0.000 245.515 0.210 ;
    END
  END r0_rd_out[316]
  PIN r0_rd_out[317]
    DIRECTION OUTPUT ;
    USE SIGNAL ;
    SHAPE ABUTMENT ;
    PORT
      LAYER metal2 ;
      RECT 245.825 0.000 245.895 0.210 ;
    END
  END r0_rd_out[317]
  PIN r0_rd_out[318]
    DIRECTION OUTPUT ;
    USE SIGNAL ;
    SHAPE ABUTMENT ;
    PORT
      LAYER metal2 ;
      RECT 246.205 0.000 246.275 0.210 ;
    END
  END r0_rd_out[318]
  PIN r0_rd_out[319]
    DIRECTION OUTPUT ;
    USE SIGNAL ;
    SHAPE ABUTMENT ;
    PORT
      LAYER metal2 ;
      RECT 246.585 0.000 246.655 0.210 ;
    END
  END r0_rd_out[319]
  PIN r0_rd_out[320]
    DIRECTION OUTPUT ;
    USE SIGNAL ;
    SHAPE ABUTMENT ;
    PORT
      LAYER metal2 ;
      RECT 246.965 0.000 247.035 0.210 ;
    END
  END r0_rd_out[320]
  PIN r0_rd_out[321]
    DIRECTION OUTPUT ;
    USE SIGNAL ;
    SHAPE ABUTMENT ;
    PORT
      LAYER metal2 ;
      RECT 247.345 0.000 247.415 0.210 ;
    END
  END r0_rd_out[321]
  PIN r0_rd_out[322]
    DIRECTION OUTPUT ;
    USE SIGNAL ;
    SHAPE ABUTMENT ;
    PORT
      LAYER metal2 ;
      RECT 247.725 0.000 247.795 0.210 ;
    END
  END r0_rd_out[322]
  PIN r0_rd_out[323]
    DIRECTION OUTPUT ;
    USE SIGNAL ;
    SHAPE ABUTMENT ;
    PORT
      LAYER metal2 ;
      RECT 248.105 0.000 248.175 0.210 ;
    END
  END r0_rd_out[323]
  PIN r0_rd_out[324]
    DIRECTION OUTPUT ;
    USE SIGNAL ;
    SHAPE ABUTMENT ;
    PORT
      LAYER metal2 ;
      RECT 248.485 0.000 248.555 0.210 ;
    END
  END r0_rd_out[324]
  PIN r0_rd_out[325]
    DIRECTION OUTPUT ;
    USE SIGNAL ;
    SHAPE ABUTMENT ;
    PORT
      LAYER metal2 ;
      RECT 248.865 0.000 248.935 0.210 ;
    END
  END r0_rd_out[325]
  PIN r0_rd_out[326]
    DIRECTION OUTPUT ;
    USE SIGNAL ;
    SHAPE ABUTMENT ;
    PORT
      LAYER metal2 ;
      RECT 249.245 0.000 249.315 0.210 ;
    END
  END r0_rd_out[326]
  PIN r0_rd_out[327]
    DIRECTION OUTPUT ;
    USE SIGNAL ;
    SHAPE ABUTMENT ;
    PORT
      LAYER metal2 ;
      RECT 125.365 577.990 125.435 578.200 ;
    END
  END r0_rd_out[327]
  PIN r0_rd_out[328]
    DIRECTION OUTPUT ;
    USE SIGNAL ;
    SHAPE ABUTMENT ;
    PORT
      LAYER metal2 ;
      RECT 125.745 577.990 125.815 578.200 ;
    END
  END r0_rd_out[328]
  PIN r0_rd_out[329]
    DIRECTION OUTPUT ;
    USE SIGNAL ;
    SHAPE ABUTMENT ;
    PORT
      LAYER metal2 ;
      RECT 126.125 577.990 126.195 578.200 ;
    END
  END r0_rd_out[329]
  PIN r0_rd_out[330]
    DIRECTION OUTPUT ;
    USE SIGNAL ;
    SHAPE ABUTMENT ;
    PORT
      LAYER metal2 ;
      RECT 126.505 577.990 126.575 578.200 ;
    END
  END r0_rd_out[330]
  PIN r0_rd_out[331]
    DIRECTION OUTPUT ;
    USE SIGNAL ;
    SHAPE ABUTMENT ;
    PORT
      LAYER metal2 ;
      RECT 126.885 577.990 126.955 578.200 ;
    END
  END r0_rd_out[331]
  PIN r0_rd_out[332]
    DIRECTION OUTPUT ;
    USE SIGNAL ;
    SHAPE ABUTMENT ;
    PORT
      LAYER metal2 ;
      RECT 127.265 577.990 127.335 578.200 ;
    END
  END r0_rd_out[332]
  PIN r0_rd_out[333]
    DIRECTION OUTPUT ;
    USE SIGNAL ;
    SHAPE ABUTMENT ;
    PORT
      LAYER metal2 ;
      RECT 127.645 577.990 127.715 578.200 ;
    END
  END r0_rd_out[333]
  PIN r0_rd_out[334]
    DIRECTION OUTPUT ;
    USE SIGNAL ;
    SHAPE ABUTMENT ;
    PORT
      LAYER metal2 ;
      RECT 128.025 577.990 128.095 578.200 ;
    END
  END r0_rd_out[334]
  PIN r0_rd_out[335]
    DIRECTION OUTPUT ;
    USE SIGNAL ;
    SHAPE ABUTMENT ;
    PORT
      LAYER metal2 ;
      RECT 128.405 577.990 128.475 578.200 ;
    END
  END r0_rd_out[335]
  PIN r0_rd_out[336]
    DIRECTION OUTPUT ;
    USE SIGNAL ;
    SHAPE ABUTMENT ;
    PORT
      LAYER metal2 ;
      RECT 128.785 577.990 128.855 578.200 ;
    END
  END r0_rd_out[336]
  PIN r0_rd_out[337]
    DIRECTION OUTPUT ;
    USE SIGNAL ;
    SHAPE ABUTMENT ;
    PORT
      LAYER metal2 ;
      RECT 129.165 577.990 129.235 578.200 ;
    END
  END r0_rd_out[337]
  PIN r0_rd_out[338]
    DIRECTION OUTPUT ;
    USE SIGNAL ;
    SHAPE ABUTMENT ;
    PORT
      LAYER metal2 ;
      RECT 129.545 577.990 129.615 578.200 ;
    END
  END r0_rd_out[338]
  PIN r0_rd_out[339]
    DIRECTION OUTPUT ;
    USE SIGNAL ;
    SHAPE ABUTMENT ;
    PORT
      LAYER metal2 ;
      RECT 129.925 577.990 129.995 578.200 ;
    END
  END r0_rd_out[339]
  PIN r0_rd_out[340]
    DIRECTION OUTPUT ;
    USE SIGNAL ;
    SHAPE ABUTMENT ;
    PORT
      LAYER metal2 ;
      RECT 130.305 577.990 130.375 578.200 ;
    END
  END r0_rd_out[340]
  PIN r0_rd_out[341]
    DIRECTION OUTPUT ;
    USE SIGNAL ;
    SHAPE ABUTMENT ;
    PORT
      LAYER metal2 ;
      RECT 130.685 577.990 130.755 578.200 ;
    END
  END r0_rd_out[341]
  PIN r0_rd_out[342]
    DIRECTION OUTPUT ;
    USE SIGNAL ;
    SHAPE ABUTMENT ;
    PORT
      LAYER metal2 ;
      RECT 131.065 577.990 131.135 578.200 ;
    END
  END r0_rd_out[342]
  PIN r0_rd_out[343]
    DIRECTION OUTPUT ;
    USE SIGNAL ;
    SHAPE ABUTMENT ;
    PORT
      LAYER metal2 ;
      RECT 131.445 577.990 131.515 578.200 ;
    END
  END r0_rd_out[343]
  PIN r0_rd_out[344]
    DIRECTION OUTPUT ;
    USE SIGNAL ;
    SHAPE ABUTMENT ;
    PORT
      LAYER metal2 ;
      RECT 131.825 577.990 131.895 578.200 ;
    END
  END r0_rd_out[344]
  PIN r0_rd_out[345]
    DIRECTION OUTPUT ;
    USE SIGNAL ;
    SHAPE ABUTMENT ;
    PORT
      LAYER metal2 ;
      RECT 132.205 577.990 132.275 578.200 ;
    END
  END r0_rd_out[345]
  PIN r0_rd_out[346]
    DIRECTION OUTPUT ;
    USE SIGNAL ;
    SHAPE ABUTMENT ;
    PORT
      LAYER metal2 ;
      RECT 132.585 577.990 132.655 578.200 ;
    END
  END r0_rd_out[346]
  PIN r0_rd_out[347]
    DIRECTION OUTPUT ;
    USE SIGNAL ;
    SHAPE ABUTMENT ;
    PORT
      LAYER metal2 ;
      RECT 132.965 577.990 133.035 578.200 ;
    END
  END r0_rd_out[347]
  PIN r0_rd_out[348]
    DIRECTION OUTPUT ;
    USE SIGNAL ;
    SHAPE ABUTMENT ;
    PORT
      LAYER metal2 ;
      RECT 133.345 577.990 133.415 578.200 ;
    END
  END r0_rd_out[348]
  PIN r0_rd_out[349]
    DIRECTION OUTPUT ;
    USE SIGNAL ;
    SHAPE ABUTMENT ;
    PORT
      LAYER metal2 ;
      RECT 133.725 577.990 133.795 578.200 ;
    END
  END r0_rd_out[349]
  PIN r0_rd_out[350]
    DIRECTION OUTPUT ;
    USE SIGNAL ;
    SHAPE ABUTMENT ;
    PORT
      LAYER metal2 ;
      RECT 134.105 577.990 134.175 578.200 ;
    END
  END r0_rd_out[350]
  PIN r0_rd_out[351]
    DIRECTION OUTPUT ;
    USE SIGNAL ;
    SHAPE ABUTMENT ;
    PORT
      LAYER metal2 ;
      RECT 134.485 577.990 134.555 578.200 ;
    END
  END r0_rd_out[351]
  PIN r0_rd_out[352]
    DIRECTION OUTPUT ;
    USE SIGNAL ;
    SHAPE ABUTMENT ;
    PORT
      LAYER metal2 ;
      RECT 134.865 577.990 134.935 578.200 ;
    END
  END r0_rd_out[352]
  PIN r0_rd_out[353]
    DIRECTION OUTPUT ;
    USE SIGNAL ;
    SHAPE ABUTMENT ;
    PORT
      LAYER metal2 ;
      RECT 135.245 577.990 135.315 578.200 ;
    END
  END r0_rd_out[353]
  PIN r0_rd_out[354]
    DIRECTION OUTPUT ;
    USE SIGNAL ;
    SHAPE ABUTMENT ;
    PORT
      LAYER metal2 ;
      RECT 135.625 577.990 135.695 578.200 ;
    END
  END r0_rd_out[354]
  PIN r0_rd_out[355]
    DIRECTION OUTPUT ;
    USE SIGNAL ;
    SHAPE ABUTMENT ;
    PORT
      LAYER metal2 ;
      RECT 136.005 577.990 136.075 578.200 ;
    END
  END r0_rd_out[355]
  PIN r0_rd_out[356]
    DIRECTION OUTPUT ;
    USE SIGNAL ;
    SHAPE ABUTMENT ;
    PORT
      LAYER metal2 ;
      RECT 136.385 577.990 136.455 578.200 ;
    END
  END r0_rd_out[356]
  PIN r0_rd_out[357]
    DIRECTION OUTPUT ;
    USE SIGNAL ;
    SHAPE ABUTMENT ;
    PORT
      LAYER metal2 ;
      RECT 136.765 577.990 136.835 578.200 ;
    END
  END r0_rd_out[357]
  PIN r0_rd_out[358]
    DIRECTION OUTPUT ;
    USE SIGNAL ;
    SHAPE ABUTMENT ;
    PORT
      LAYER metal2 ;
      RECT 137.145 577.990 137.215 578.200 ;
    END
  END r0_rd_out[358]
  PIN r0_rd_out[359]
    DIRECTION OUTPUT ;
    USE SIGNAL ;
    SHAPE ABUTMENT ;
    PORT
      LAYER metal2 ;
      RECT 137.525 577.990 137.595 578.200 ;
    END
  END r0_rd_out[359]
  PIN r0_rd_out[360]
    DIRECTION OUTPUT ;
    USE SIGNAL ;
    SHAPE ABUTMENT ;
    PORT
      LAYER metal2 ;
      RECT 137.905 577.990 137.975 578.200 ;
    END
  END r0_rd_out[360]
  PIN r0_rd_out[361]
    DIRECTION OUTPUT ;
    USE SIGNAL ;
    SHAPE ABUTMENT ;
    PORT
      LAYER metal2 ;
      RECT 138.285 577.990 138.355 578.200 ;
    END
  END r0_rd_out[361]
  PIN r0_rd_out[362]
    DIRECTION OUTPUT ;
    USE SIGNAL ;
    SHAPE ABUTMENT ;
    PORT
      LAYER metal2 ;
      RECT 138.665 577.990 138.735 578.200 ;
    END
  END r0_rd_out[362]
  PIN r0_rd_out[363]
    DIRECTION OUTPUT ;
    USE SIGNAL ;
    SHAPE ABUTMENT ;
    PORT
      LAYER metal2 ;
      RECT 139.045 577.990 139.115 578.200 ;
    END
  END r0_rd_out[363]
  PIN r0_rd_out[364]
    DIRECTION OUTPUT ;
    USE SIGNAL ;
    SHAPE ABUTMENT ;
    PORT
      LAYER metal2 ;
      RECT 139.425 577.990 139.495 578.200 ;
    END
  END r0_rd_out[364]
  PIN r0_rd_out[365]
    DIRECTION OUTPUT ;
    USE SIGNAL ;
    SHAPE ABUTMENT ;
    PORT
      LAYER metal2 ;
      RECT 139.805 577.990 139.875 578.200 ;
    END
  END r0_rd_out[365]
  PIN r0_rd_out[366]
    DIRECTION OUTPUT ;
    USE SIGNAL ;
    SHAPE ABUTMENT ;
    PORT
      LAYER metal2 ;
      RECT 140.185 577.990 140.255 578.200 ;
    END
  END r0_rd_out[366]
  PIN r0_rd_out[367]
    DIRECTION OUTPUT ;
    USE SIGNAL ;
    SHAPE ABUTMENT ;
    PORT
      LAYER metal2 ;
      RECT 140.565 577.990 140.635 578.200 ;
    END
  END r0_rd_out[367]
  PIN r0_rd_out[368]
    DIRECTION OUTPUT ;
    USE SIGNAL ;
    SHAPE ABUTMENT ;
    PORT
      LAYER metal2 ;
      RECT 140.945 577.990 141.015 578.200 ;
    END
  END r0_rd_out[368]
  PIN r0_rd_out[369]
    DIRECTION OUTPUT ;
    USE SIGNAL ;
    SHAPE ABUTMENT ;
    PORT
      LAYER metal2 ;
      RECT 141.325 577.990 141.395 578.200 ;
    END
  END r0_rd_out[369]
  PIN r0_rd_out[370]
    DIRECTION OUTPUT ;
    USE SIGNAL ;
    SHAPE ABUTMENT ;
    PORT
      LAYER metal2 ;
      RECT 141.705 577.990 141.775 578.200 ;
    END
  END r0_rd_out[370]
  PIN r0_rd_out[371]
    DIRECTION OUTPUT ;
    USE SIGNAL ;
    SHAPE ABUTMENT ;
    PORT
      LAYER metal2 ;
      RECT 142.085 577.990 142.155 578.200 ;
    END
  END r0_rd_out[371]
  PIN r0_rd_out[372]
    DIRECTION OUTPUT ;
    USE SIGNAL ;
    SHAPE ABUTMENT ;
    PORT
      LAYER metal2 ;
      RECT 142.465 577.990 142.535 578.200 ;
    END
  END r0_rd_out[372]
  PIN r0_rd_out[373]
    DIRECTION OUTPUT ;
    USE SIGNAL ;
    SHAPE ABUTMENT ;
    PORT
      LAYER metal2 ;
      RECT 142.845 577.990 142.915 578.200 ;
    END
  END r0_rd_out[373]
  PIN r0_rd_out[374]
    DIRECTION OUTPUT ;
    USE SIGNAL ;
    SHAPE ABUTMENT ;
    PORT
      LAYER metal2 ;
      RECT 143.225 577.990 143.295 578.200 ;
    END
  END r0_rd_out[374]
  PIN r0_rd_out[375]
    DIRECTION OUTPUT ;
    USE SIGNAL ;
    SHAPE ABUTMENT ;
    PORT
      LAYER metal2 ;
      RECT 143.605 577.990 143.675 578.200 ;
    END
  END r0_rd_out[375]
  PIN r0_rd_out[376]
    DIRECTION OUTPUT ;
    USE SIGNAL ;
    SHAPE ABUTMENT ;
    PORT
      LAYER metal2 ;
      RECT 143.985 577.990 144.055 578.200 ;
    END
  END r0_rd_out[376]
  PIN r0_rd_out[377]
    DIRECTION OUTPUT ;
    USE SIGNAL ;
    SHAPE ABUTMENT ;
    PORT
      LAYER metal2 ;
      RECT 144.365 577.990 144.435 578.200 ;
    END
  END r0_rd_out[377]
  PIN r0_rd_out[378]
    DIRECTION OUTPUT ;
    USE SIGNAL ;
    SHAPE ABUTMENT ;
    PORT
      LAYER metal2 ;
      RECT 144.745 577.990 144.815 578.200 ;
    END
  END r0_rd_out[378]
  PIN r0_rd_out[379]
    DIRECTION OUTPUT ;
    USE SIGNAL ;
    SHAPE ABUTMENT ;
    PORT
      LAYER metal2 ;
      RECT 145.125 577.990 145.195 578.200 ;
    END
  END r0_rd_out[379]
  PIN r0_rd_out[380]
    DIRECTION OUTPUT ;
    USE SIGNAL ;
    SHAPE ABUTMENT ;
    PORT
      LAYER metal2 ;
      RECT 145.505 577.990 145.575 578.200 ;
    END
  END r0_rd_out[380]
  PIN r0_rd_out[381]
    DIRECTION OUTPUT ;
    USE SIGNAL ;
    SHAPE ABUTMENT ;
    PORT
      LAYER metal2 ;
      RECT 145.885 577.990 145.955 578.200 ;
    END
  END r0_rd_out[381]
  PIN r0_rd_out[382]
    DIRECTION OUTPUT ;
    USE SIGNAL ;
    SHAPE ABUTMENT ;
    PORT
      LAYER metal2 ;
      RECT 146.265 577.990 146.335 578.200 ;
    END
  END r0_rd_out[382]
  PIN r0_rd_out[383]
    DIRECTION OUTPUT ;
    USE SIGNAL ;
    SHAPE ABUTMENT ;
    PORT
      LAYER metal2 ;
      RECT 146.645 577.990 146.715 578.200 ;
    END
  END r0_rd_out[383]
  PIN r0_rd_out[384]
    DIRECTION OUTPUT ;
    USE SIGNAL ;
    SHAPE ABUTMENT ;
    PORT
      LAYER metal2 ;
      RECT 147.025 577.990 147.095 578.200 ;
    END
  END r0_rd_out[384]
  PIN r0_rd_out[385]
    DIRECTION OUTPUT ;
    USE SIGNAL ;
    SHAPE ABUTMENT ;
    PORT
      LAYER metal2 ;
      RECT 147.405 577.990 147.475 578.200 ;
    END
  END r0_rd_out[385]
  PIN r0_rd_out[386]
    DIRECTION OUTPUT ;
    USE SIGNAL ;
    SHAPE ABUTMENT ;
    PORT
      LAYER metal2 ;
      RECT 147.785 577.990 147.855 578.200 ;
    END
  END r0_rd_out[386]
  PIN r0_rd_out[387]
    DIRECTION OUTPUT ;
    USE SIGNAL ;
    SHAPE ABUTMENT ;
    PORT
      LAYER metal2 ;
      RECT 148.165 577.990 148.235 578.200 ;
    END
  END r0_rd_out[387]
  PIN r0_rd_out[388]
    DIRECTION OUTPUT ;
    USE SIGNAL ;
    SHAPE ABUTMENT ;
    PORT
      LAYER metal2 ;
      RECT 148.545 577.990 148.615 578.200 ;
    END
  END r0_rd_out[388]
  PIN r0_rd_out[389]
    DIRECTION OUTPUT ;
    USE SIGNAL ;
    SHAPE ABUTMENT ;
    PORT
      LAYER metal2 ;
      RECT 148.925 577.990 148.995 578.200 ;
    END
  END r0_rd_out[389]
  PIN r0_rd_out[390]
    DIRECTION OUTPUT ;
    USE SIGNAL ;
    SHAPE ABUTMENT ;
    PORT
      LAYER metal2 ;
      RECT 149.305 577.990 149.375 578.200 ;
    END
  END r0_rd_out[390]
  PIN r0_rd_out[391]
    DIRECTION OUTPUT ;
    USE SIGNAL ;
    SHAPE ABUTMENT ;
    PORT
      LAYER metal2 ;
      RECT 149.685 577.990 149.755 578.200 ;
    END
  END r0_rd_out[391]
  PIN r0_rd_out[392]
    DIRECTION OUTPUT ;
    USE SIGNAL ;
    SHAPE ABUTMENT ;
    PORT
      LAYER metal2 ;
      RECT 150.065 577.990 150.135 578.200 ;
    END
  END r0_rd_out[392]
  PIN r0_rd_out[393]
    DIRECTION OUTPUT ;
    USE SIGNAL ;
    SHAPE ABUTMENT ;
    PORT
      LAYER metal2 ;
      RECT 150.445 577.990 150.515 578.200 ;
    END
  END r0_rd_out[393]
  PIN r0_rd_out[394]
    DIRECTION OUTPUT ;
    USE SIGNAL ;
    SHAPE ABUTMENT ;
    PORT
      LAYER metal2 ;
      RECT 150.825 577.990 150.895 578.200 ;
    END
  END r0_rd_out[394]
  PIN r0_rd_out[395]
    DIRECTION OUTPUT ;
    USE SIGNAL ;
    SHAPE ABUTMENT ;
    PORT
      LAYER metal2 ;
      RECT 151.205 577.990 151.275 578.200 ;
    END
  END r0_rd_out[395]
  PIN r0_rd_out[396]
    DIRECTION OUTPUT ;
    USE SIGNAL ;
    SHAPE ABUTMENT ;
    PORT
      LAYER metal2 ;
      RECT 151.585 577.990 151.655 578.200 ;
    END
  END r0_rd_out[396]
  PIN r0_rd_out[397]
    DIRECTION OUTPUT ;
    USE SIGNAL ;
    SHAPE ABUTMENT ;
    PORT
      LAYER metal2 ;
      RECT 151.965 577.990 152.035 578.200 ;
    END
  END r0_rd_out[397]
  PIN r0_rd_out[398]
    DIRECTION OUTPUT ;
    USE SIGNAL ;
    SHAPE ABUTMENT ;
    PORT
      LAYER metal2 ;
      RECT 152.345 577.990 152.415 578.200 ;
    END
  END r0_rd_out[398]
  PIN r0_rd_out[399]
    DIRECTION OUTPUT ;
    USE SIGNAL ;
    SHAPE ABUTMENT ;
    PORT
      LAYER metal2 ;
      RECT 152.725 577.990 152.795 578.200 ;
    END
  END r0_rd_out[399]
  PIN r0_rd_out[400]
    DIRECTION OUTPUT ;
    USE SIGNAL ;
    SHAPE ABUTMENT ;
    PORT
      LAYER metal2 ;
      RECT 153.105 577.990 153.175 578.200 ;
    END
  END r0_rd_out[400]
  PIN r0_rd_out[401]
    DIRECTION OUTPUT ;
    USE SIGNAL ;
    SHAPE ABUTMENT ;
    PORT
      LAYER metal2 ;
      RECT 153.485 577.990 153.555 578.200 ;
    END
  END r0_rd_out[401]
  PIN r0_rd_out[402]
    DIRECTION OUTPUT ;
    USE SIGNAL ;
    SHAPE ABUTMENT ;
    PORT
      LAYER metal2 ;
      RECT 153.865 577.990 153.935 578.200 ;
    END
  END r0_rd_out[402]
  PIN r0_rd_out[403]
    DIRECTION OUTPUT ;
    USE SIGNAL ;
    SHAPE ABUTMENT ;
    PORT
      LAYER metal2 ;
      RECT 154.245 577.990 154.315 578.200 ;
    END
  END r0_rd_out[403]
  PIN r0_rd_out[404]
    DIRECTION OUTPUT ;
    USE SIGNAL ;
    SHAPE ABUTMENT ;
    PORT
      LAYER metal2 ;
      RECT 154.625 577.990 154.695 578.200 ;
    END
  END r0_rd_out[404]
  PIN r0_rd_out[405]
    DIRECTION OUTPUT ;
    USE SIGNAL ;
    SHAPE ABUTMENT ;
    PORT
      LAYER metal2 ;
      RECT 155.005 577.990 155.075 578.200 ;
    END
  END r0_rd_out[405]
  PIN r0_rd_out[406]
    DIRECTION OUTPUT ;
    USE SIGNAL ;
    SHAPE ABUTMENT ;
    PORT
      LAYER metal2 ;
      RECT 155.385 577.990 155.455 578.200 ;
    END
  END r0_rd_out[406]
  PIN r0_rd_out[407]
    DIRECTION OUTPUT ;
    USE SIGNAL ;
    SHAPE ABUTMENT ;
    PORT
      LAYER metal2 ;
      RECT 155.765 577.990 155.835 578.200 ;
    END
  END r0_rd_out[407]
  PIN r0_rd_out[408]
    DIRECTION OUTPUT ;
    USE SIGNAL ;
    SHAPE ABUTMENT ;
    PORT
      LAYER metal2 ;
      RECT 156.145 577.990 156.215 578.200 ;
    END
  END r0_rd_out[408]
  PIN r0_rd_out[409]
    DIRECTION OUTPUT ;
    USE SIGNAL ;
    SHAPE ABUTMENT ;
    PORT
      LAYER metal2 ;
      RECT 156.525 577.990 156.595 578.200 ;
    END
  END r0_rd_out[409]
  PIN r0_rd_out[410]
    DIRECTION OUTPUT ;
    USE SIGNAL ;
    SHAPE ABUTMENT ;
    PORT
      LAYER metal2 ;
      RECT 156.905 577.990 156.975 578.200 ;
    END
  END r0_rd_out[410]
  PIN r0_rd_out[411]
    DIRECTION OUTPUT ;
    USE SIGNAL ;
    SHAPE ABUTMENT ;
    PORT
      LAYER metal2 ;
      RECT 157.285 577.990 157.355 578.200 ;
    END
  END r0_rd_out[411]
  PIN r0_rd_out[412]
    DIRECTION OUTPUT ;
    USE SIGNAL ;
    SHAPE ABUTMENT ;
    PORT
      LAYER metal2 ;
      RECT 157.665 577.990 157.735 578.200 ;
    END
  END r0_rd_out[412]
  PIN r0_rd_out[413]
    DIRECTION OUTPUT ;
    USE SIGNAL ;
    SHAPE ABUTMENT ;
    PORT
      LAYER metal2 ;
      RECT 158.045 577.990 158.115 578.200 ;
    END
  END r0_rd_out[413]
  PIN r0_rd_out[414]
    DIRECTION OUTPUT ;
    USE SIGNAL ;
    SHAPE ABUTMENT ;
    PORT
      LAYER metal2 ;
      RECT 158.425 577.990 158.495 578.200 ;
    END
  END r0_rd_out[414]
  PIN r0_rd_out[415]
    DIRECTION OUTPUT ;
    USE SIGNAL ;
    SHAPE ABUTMENT ;
    PORT
      LAYER metal2 ;
      RECT 158.805 577.990 158.875 578.200 ;
    END
  END r0_rd_out[415]
  PIN r0_rd_out[416]
    DIRECTION OUTPUT ;
    USE SIGNAL ;
    SHAPE ABUTMENT ;
    PORT
      LAYER metal2 ;
      RECT 159.185 577.990 159.255 578.200 ;
    END
  END r0_rd_out[416]
  PIN r0_rd_out[417]
    DIRECTION OUTPUT ;
    USE SIGNAL ;
    SHAPE ABUTMENT ;
    PORT
      LAYER metal2 ;
      RECT 159.565 577.990 159.635 578.200 ;
    END
  END r0_rd_out[417]
  PIN r0_rd_out[418]
    DIRECTION OUTPUT ;
    USE SIGNAL ;
    SHAPE ABUTMENT ;
    PORT
      LAYER metal2 ;
      RECT 159.945 577.990 160.015 578.200 ;
    END
  END r0_rd_out[418]
  PIN r0_rd_out[419]
    DIRECTION OUTPUT ;
    USE SIGNAL ;
    SHAPE ABUTMENT ;
    PORT
      LAYER metal2 ;
      RECT 160.325 577.990 160.395 578.200 ;
    END
  END r0_rd_out[419]
  PIN r0_rd_out[420]
    DIRECTION OUTPUT ;
    USE SIGNAL ;
    SHAPE ABUTMENT ;
    PORT
      LAYER metal2 ;
      RECT 160.705 577.990 160.775 578.200 ;
    END
  END r0_rd_out[420]
  PIN r0_rd_out[421]
    DIRECTION OUTPUT ;
    USE SIGNAL ;
    SHAPE ABUTMENT ;
    PORT
      LAYER metal2 ;
      RECT 161.085 577.990 161.155 578.200 ;
    END
  END r0_rd_out[421]
  PIN r0_rd_out[422]
    DIRECTION OUTPUT ;
    USE SIGNAL ;
    SHAPE ABUTMENT ;
    PORT
      LAYER metal2 ;
      RECT 161.465 577.990 161.535 578.200 ;
    END
  END r0_rd_out[422]
  PIN r0_rd_out[423]
    DIRECTION OUTPUT ;
    USE SIGNAL ;
    SHAPE ABUTMENT ;
    PORT
      LAYER metal2 ;
      RECT 161.845 577.990 161.915 578.200 ;
    END
  END r0_rd_out[423]
  PIN r0_rd_out[424]
    DIRECTION OUTPUT ;
    USE SIGNAL ;
    SHAPE ABUTMENT ;
    PORT
      LAYER metal2 ;
      RECT 162.225 577.990 162.295 578.200 ;
    END
  END r0_rd_out[424]
  PIN r0_rd_out[425]
    DIRECTION OUTPUT ;
    USE SIGNAL ;
    SHAPE ABUTMENT ;
    PORT
      LAYER metal2 ;
      RECT 162.605 577.990 162.675 578.200 ;
    END
  END r0_rd_out[425]
  PIN r0_rd_out[426]
    DIRECTION OUTPUT ;
    USE SIGNAL ;
    SHAPE ABUTMENT ;
    PORT
      LAYER metal2 ;
      RECT 162.985 577.990 163.055 578.200 ;
    END
  END r0_rd_out[426]
  PIN r0_rd_out[427]
    DIRECTION OUTPUT ;
    USE SIGNAL ;
    SHAPE ABUTMENT ;
    PORT
      LAYER metal2 ;
      RECT 163.365 577.990 163.435 578.200 ;
    END
  END r0_rd_out[427]
  PIN r0_rd_out[428]
    DIRECTION OUTPUT ;
    USE SIGNAL ;
    SHAPE ABUTMENT ;
    PORT
      LAYER metal2 ;
      RECT 163.745 577.990 163.815 578.200 ;
    END
  END r0_rd_out[428]
  PIN r0_rd_out[429]
    DIRECTION OUTPUT ;
    USE SIGNAL ;
    SHAPE ABUTMENT ;
    PORT
      LAYER metal2 ;
      RECT 164.125 577.990 164.195 578.200 ;
    END
  END r0_rd_out[429]
  PIN r0_rd_out[430]
    DIRECTION OUTPUT ;
    USE SIGNAL ;
    SHAPE ABUTMENT ;
    PORT
      LAYER metal2 ;
      RECT 164.505 577.990 164.575 578.200 ;
    END
  END r0_rd_out[430]
  PIN r0_rd_out[431]
    DIRECTION OUTPUT ;
    USE SIGNAL ;
    SHAPE ABUTMENT ;
    PORT
      LAYER metal2 ;
      RECT 164.885 577.990 164.955 578.200 ;
    END
  END r0_rd_out[431]
  PIN r0_rd_out[432]
    DIRECTION OUTPUT ;
    USE SIGNAL ;
    SHAPE ABUTMENT ;
    PORT
      LAYER metal2 ;
      RECT 165.265 577.990 165.335 578.200 ;
    END
  END r0_rd_out[432]
  PIN r0_rd_out[433]
    DIRECTION OUTPUT ;
    USE SIGNAL ;
    SHAPE ABUTMENT ;
    PORT
      LAYER metal2 ;
      RECT 165.645 577.990 165.715 578.200 ;
    END
  END r0_rd_out[433]
  PIN r0_rd_out[434]
    DIRECTION OUTPUT ;
    USE SIGNAL ;
    SHAPE ABUTMENT ;
    PORT
      LAYER metal2 ;
      RECT 166.025 577.990 166.095 578.200 ;
    END
  END r0_rd_out[434]
  PIN r0_rd_out[435]
    DIRECTION OUTPUT ;
    USE SIGNAL ;
    SHAPE ABUTMENT ;
    PORT
      LAYER metal2 ;
      RECT 166.405 577.990 166.475 578.200 ;
    END
  END r0_rd_out[435]
  PIN r0_rd_out[436]
    DIRECTION OUTPUT ;
    USE SIGNAL ;
    SHAPE ABUTMENT ;
    PORT
      LAYER metal2 ;
      RECT 166.785 577.990 166.855 578.200 ;
    END
  END r0_rd_out[436]
  PIN r0_rd_out[437]
    DIRECTION OUTPUT ;
    USE SIGNAL ;
    SHAPE ABUTMENT ;
    PORT
      LAYER metal2 ;
      RECT 167.165 577.990 167.235 578.200 ;
    END
  END r0_rd_out[437]
  PIN r0_rd_out[438]
    DIRECTION OUTPUT ;
    USE SIGNAL ;
    SHAPE ABUTMENT ;
    PORT
      LAYER metal2 ;
      RECT 167.545 577.990 167.615 578.200 ;
    END
  END r0_rd_out[438]
  PIN r0_rd_out[439]
    DIRECTION OUTPUT ;
    USE SIGNAL ;
    SHAPE ABUTMENT ;
    PORT
      LAYER metal2 ;
      RECT 167.925 577.990 167.995 578.200 ;
    END
  END r0_rd_out[439]
  PIN r0_rd_out[440]
    DIRECTION OUTPUT ;
    USE SIGNAL ;
    SHAPE ABUTMENT ;
    PORT
      LAYER metal2 ;
      RECT 168.305 577.990 168.375 578.200 ;
    END
  END r0_rd_out[440]
  PIN r0_rd_out[441]
    DIRECTION OUTPUT ;
    USE SIGNAL ;
    SHAPE ABUTMENT ;
    PORT
      LAYER metal2 ;
      RECT 168.685 577.990 168.755 578.200 ;
    END
  END r0_rd_out[441]
  PIN r0_rd_out[442]
    DIRECTION OUTPUT ;
    USE SIGNAL ;
    SHAPE ABUTMENT ;
    PORT
      LAYER metal2 ;
      RECT 169.065 577.990 169.135 578.200 ;
    END
  END r0_rd_out[442]
  PIN r0_rd_out[443]
    DIRECTION OUTPUT ;
    USE SIGNAL ;
    SHAPE ABUTMENT ;
    PORT
      LAYER metal2 ;
      RECT 169.445 577.990 169.515 578.200 ;
    END
  END r0_rd_out[443]
  PIN r0_rd_out[444]
    DIRECTION OUTPUT ;
    USE SIGNAL ;
    SHAPE ABUTMENT ;
    PORT
      LAYER metal2 ;
      RECT 169.825 577.990 169.895 578.200 ;
    END
  END r0_rd_out[444]
  PIN r0_rd_out[445]
    DIRECTION OUTPUT ;
    USE SIGNAL ;
    SHAPE ABUTMENT ;
    PORT
      LAYER metal2 ;
      RECT 170.205 577.990 170.275 578.200 ;
    END
  END r0_rd_out[445]
  PIN r0_rd_out[446]
    DIRECTION OUTPUT ;
    USE SIGNAL ;
    SHAPE ABUTMENT ;
    PORT
      LAYER metal2 ;
      RECT 170.585 577.990 170.655 578.200 ;
    END
  END r0_rd_out[446]
  PIN r0_rd_out[447]
    DIRECTION OUTPUT ;
    USE SIGNAL ;
    SHAPE ABUTMENT ;
    PORT
      LAYER metal2 ;
      RECT 170.965 577.990 171.035 578.200 ;
    END
  END r0_rd_out[447]
  PIN r0_rd_out[448]
    DIRECTION OUTPUT ;
    USE SIGNAL ;
    SHAPE ABUTMENT ;
    PORT
      LAYER metal2 ;
      RECT 171.345 577.990 171.415 578.200 ;
    END
  END r0_rd_out[448]
  PIN r0_rd_out[449]
    DIRECTION OUTPUT ;
    USE SIGNAL ;
    SHAPE ABUTMENT ;
    PORT
      LAYER metal2 ;
      RECT 171.725 577.990 171.795 578.200 ;
    END
  END r0_rd_out[449]
  PIN r0_rd_out[450]
    DIRECTION OUTPUT ;
    USE SIGNAL ;
    SHAPE ABUTMENT ;
    PORT
      LAYER metal2 ;
      RECT 172.105 577.990 172.175 578.200 ;
    END
  END r0_rd_out[450]
  PIN r0_rd_out[451]
    DIRECTION OUTPUT ;
    USE SIGNAL ;
    SHAPE ABUTMENT ;
    PORT
      LAYER metal2 ;
      RECT 172.485 577.990 172.555 578.200 ;
    END
  END r0_rd_out[451]
  PIN r0_rd_out[452]
    DIRECTION OUTPUT ;
    USE SIGNAL ;
    SHAPE ABUTMENT ;
    PORT
      LAYER metal2 ;
      RECT 172.865 577.990 172.935 578.200 ;
    END
  END r0_rd_out[452]
  PIN r0_rd_out[453]
    DIRECTION OUTPUT ;
    USE SIGNAL ;
    SHAPE ABUTMENT ;
    PORT
      LAYER metal2 ;
      RECT 173.245 577.990 173.315 578.200 ;
    END
  END r0_rd_out[453]
  PIN r0_rd_out[454]
    DIRECTION OUTPUT ;
    USE SIGNAL ;
    SHAPE ABUTMENT ;
    PORT
      LAYER metal2 ;
      RECT 173.625 577.990 173.695 578.200 ;
    END
  END r0_rd_out[454]
  PIN r0_rd_out[455]
    DIRECTION OUTPUT ;
    USE SIGNAL ;
    SHAPE ABUTMENT ;
    PORT
      LAYER metal2 ;
      RECT 174.005 577.990 174.075 578.200 ;
    END
  END r0_rd_out[455]
  PIN r0_rd_out[456]
    DIRECTION OUTPUT ;
    USE SIGNAL ;
    SHAPE ABUTMENT ;
    PORT
      LAYER metal2 ;
      RECT 174.385 577.990 174.455 578.200 ;
    END
  END r0_rd_out[456]
  PIN r0_rd_out[457]
    DIRECTION OUTPUT ;
    USE SIGNAL ;
    SHAPE ABUTMENT ;
    PORT
      LAYER metal2 ;
      RECT 174.765 577.990 174.835 578.200 ;
    END
  END r0_rd_out[457]
  PIN r0_rd_out[458]
    DIRECTION OUTPUT ;
    USE SIGNAL ;
    SHAPE ABUTMENT ;
    PORT
      LAYER metal2 ;
      RECT 175.145 577.990 175.215 578.200 ;
    END
  END r0_rd_out[458]
  PIN r0_rd_out[459]
    DIRECTION OUTPUT ;
    USE SIGNAL ;
    SHAPE ABUTMENT ;
    PORT
      LAYER metal2 ;
      RECT 175.525 577.990 175.595 578.200 ;
    END
  END r0_rd_out[459]
  PIN r0_rd_out[460]
    DIRECTION OUTPUT ;
    USE SIGNAL ;
    SHAPE ABUTMENT ;
    PORT
      LAYER metal2 ;
      RECT 175.905 577.990 175.975 578.200 ;
    END
  END r0_rd_out[460]
  PIN r0_rd_out[461]
    DIRECTION OUTPUT ;
    USE SIGNAL ;
    SHAPE ABUTMENT ;
    PORT
      LAYER metal2 ;
      RECT 176.285 577.990 176.355 578.200 ;
    END
  END r0_rd_out[461]
  PIN r0_rd_out[462]
    DIRECTION OUTPUT ;
    USE SIGNAL ;
    SHAPE ABUTMENT ;
    PORT
      LAYER metal2 ;
      RECT 176.665 577.990 176.735 578.200 ;
    END
  END r0_rd_out[462]
  PIN r0_rd_out[463]
    DIRECTION OUTPUT ;
    USE SIGNAL ;
    SHAPE ABUTMENT ;
    PORT
      LAYER metal2 ;
      RECT 177.045 577.990 177.115 578.200 ;
    END
  END r0_rd_out[463]
  PIN r0_rd_out[464]
    DIRECTION OUTPUT ;
    USE SIGNAL ;
    SHAPE ABUTMENT ;
    PORT
      LAYER metal2 ;
      RECT 177.425 577.990 177.495 578.200 ;
    END
  END r0_rd_out[464]
  PIN r0_rd_out[465]
    DIRECTION OUTPUT ;
    USE SIGNAL ;
    SHAPE ABUTMENT ;
    PORT
      LAYER metal2 ;
      RECT 177.805 577.990 177.875 578.200 ;
    END
  END r0_rd_out[465]
  PIN r0_rd_out[466]
    DIRECTION OUTPUT ;
    USE SIGNAL ;
    SHAPE ABUTMENT ;
    PORT
      LAYER metal2 ;
      RECT 178.185 577.990 178.255 578.200 ;
    END
  END r0_rd_out[466]
  PIN r0_rd_out[467]
    DIRECTION OUTPUT ;
    USE SIGNAL ;
    SHAPE ABUTMENT ;
    PORT
      LAYER metal2 ;
      RECT 178.565 577.990 178.635 578.200 ;
    END
  END r0_rd_out[467]
  PIN r0_rd_out[468]
    DIRECTION OUTPUT ;
    USE SIGNAL ;
    SHAPE ABUTMENT ;
    PORT
      LAYER metal2 ;
      RECT 178.945 577.990 179.015 578.200 ;
    END
  END r0_rd_out[468]
  PIN r0_rd_out[469]
    DIRECTION OUTPUT ;
    USE SIGNAL ;
    SHAPE ABUTMENT ;
    PORT
      LAYER metal2 ;
      RECT 179.325 577.990 179.395 578.200 ;
    END
  END r0_rd_out[469]
  PIN r0_rd_out[470]
    DIRECTION OUTPUT ;
    USE SIGNAL ;
    SHAPE ABUTMENT ;
    PORT
      LAYER metal2 ;
      RECT 179.705 577.990 179.775 578.200 ;
    END
  END r0_rd_out[470]
  PIN r0_rd_out[471]
    DIRECTION OUTPUT ;
    USE SIGNAL ;
    SHAPE ABUTMENT ;
    PORT
      LAYER metal2 ;
      RECT 180.085 577.990 180.155 578.200 ;
    END
  END r0_rd_out[471]
  PIN r0_rd_out[472]
    DIRECTION OUTPUT ;
    USE SIGNAL ;
    SHAPE ABUTMENT ;
    PORT
      LAYER metal2 ;
      RECT 180.465 577.990 180.535 578.200 ;
    END
  END r0_rd_out[472]
  PIN r0_rd_out[473]
    DIRECTION OUTPUT ;
    USE SIGNAL ;
    SHAPE ABUTMENT ;
    PORT
      LAYER metal2 ;
      RECT 180.845 577.990 180.915 578.200 ;
    END
  END r0_rd_out[473]
  PIN r0_rd_out[474]
    DIRECTION OUTPUT ;
    USE SIGNAL ;
    SHAPE ABUTMENT ;
    PORT
      LAYER metal2 ;
      RECT 181.225 577.990 181.295 578.200 ;
    END
  END r0_rd_out[474]
  PIN r0_rd_out[475]
    DIRECTION OUTPUT ;
    USE SIGNAL ;
    SHAPE ABUTMENT ;
    PORT
      LAYER metal2 ;
      RECT 181.605 577.990 181.675 578.200 ;
    END
  END r0_rd_out[475]
  PIN r0_rd_out[476]
    DIRECTION OUTPUT ;
    USE SIGNAL ;
    SHAPE ABUTMENT ;
    PORT
      LAYER metal2 ;
      RECT 181.985 577.990 182.055 578.200 ;
    END
  END r0_rd_out[476]
  PIN r0_rd_out[477]
    DIRECTION OUTPUT ;
    USE SIGNAL ;
    SHAPE ABUTMENT ;
    PORT
      LAYER metal2 ;
      RECT 182.365 577.990 182.435 578.200 ;
    END
  END r0_rd_out[477]
  PIN r0_rd_out[478]
    DIRECTION OUTPUT ;
    USE SIGNAL ;
    SHAPE ABUTMENT ;
    PORT
      LAYER metal2 ;
      RECT 182.745 577.990 182.815 578.200 ;
    END
  END r0_rd_out[478]
  PIN r0_rd_out[479]
    DIRECTION OUTPUT ;
    USE SIGNAL ;
    SHAPE ABUTMENT ;
    PORT
      LAYER metal2 ;
      RECT 183.125 577.990 183.195 578.200 ;
    END
  END r0_rd_out[479]
  PIN r0_rd_out[480]
    DIRECTION OUTPUT ;
    USE SIGNAL ;
    SHAPE ABUTMENT ;
    PORT
      LAYER metal2 ;
      RECT 183.505 577.990 183.575 578.200 ;
    END
  END r0_rd_out[480]
  PIN r0_rd_out[481]
    DIRECTION OUTPUT ;
    USE SIGNAL ;
    SHAPE ABUTMENT ;
    PORT
      LAYER metal2 ;
      RECT 183.885 577.990 183.955 578.200 ;
    END
  END r0_rd_out[481]
  PIN r0_rd_out[482]
    DIRECTION OUTPUT ;
    USE SIGNAL ;
    SHAPE ABUTMENT ;
    PORT
      LAYER metal2 ;
      RECT 184.265 577.990 184.335 578.200 ;
    END
  END r0_rd_out[482]
  PIN r0_rd_out[483]
    DIRECTION OUTPUT ;
    USE SIGNAL ;
    SHAPE ABUTMENT ;
    PORT
      LAYER metal2 ;
      RECT 184.645 577.990 184.715 578.200 ;
    END
  END r0_rd_out[483]
  PIN r0_rd_out[484]
    DIRECTION OUTPUT ;
    USE SIGNAL ;
    SHAPE ABUTMENT ;
    PORT
      LAYER metal2 ;
      RECT 185.025 577.990 185.095 578.200 ;
    END
  END r0_rd_out[484]
  PIN r0_rd_out[485]
    DIRECTION OUTPUT ;
    USE SIGNAL ;
    SHAPE ABUTMENT ;
    PORT
      LAYER metal2 ;
      RECT 185.405 577.990 185.475 578.200 ;
    END
  END r0_rd_out[485]
  PIN r0_rd_out[486]
    DIRECTION OUTPUT ;
    USE SIGNAL ;
    SHAPE ABUTMENT ;
    PORT
      LAYER metal2 ;
      RECT 185.785 577.990 185.855 578.200 ;
    END
  END r0_rd_out[486]
  PIN r0_rd_out[487]
    DIRECTION OUTPUT ;
    USE SIGNAL ;
    SHAPE ABUTMENT ;
    PORT
      LAYER metal2 ;
      RECT 186.165 577.990 186.235 578.200 ;
    END
  END r0_rd_out[487]
  PIN r0_rd_out[488]
    DIRECTION OUTPUT ;
    USE SIGNAL ;
    SHAPE ABUTMENT ;
    PORT
      LAYER metal2 ;
      RECT 186.545 577.990 186.615 578.200 ;
    END
  END r0_rd_out[488]
  PIN r0_rd_out[489]
    DIRECTION OUTPUT ;
    USE SIGNAL ;
    SHAPE ABUTMENT ;
    PORT
      LAYER metal2 ;
      RECT 186.925 577.990 186.995 578.200 ;
    END
  END r0_rd_out[489]
  PIN r0_rd_out[490]
    DIRECTION OUTPUT ;
    USE SIGNAL ;
    SHAPE ABUTMENT ;
    PORT
      LAYER metal2 ;
      RECT 187.305 577.990 187.375 578.200 ;
    END
  END r0_rd_out[490]
  PIN r0_rd_out[491]
    DIRECTION OUTPUT ;
    USE SIGNAL ;
    SHAPE ABUTMENT ;
    PORT
      LAYER metal2 ;
      RECT 187.685 577.990 187.755 578.200 ;
    END
  END r0_rd_out[491]
  PIN r0_rd_out[492]
    DIRECTION OUTPUT ;
    USE SIGNAL ;
    SHAPE ABUTMENT ;
    PORT
      LAYER metal2 ;
      RECT 188.065 577.990 188.135 578.200 ;
    END
  END r0_rd_out[492]
  PIN r0_rd_out[493]
    DIRECTION OUTPUT ;
    USE SIGNAL ;
    SHAPE ABUTMENT ;
    PORT
      LAYER metal2 ;
      RECT 188.445 577.990 188.515 578.200 ;
    END
  END r0_rd_out[493]
  PIN r0_rd_out[494]
    DIRECTION OUTPUT ;
    USE SIGNAL ;
    SHAPE ABUTMENT ;
    PORT
      LAYER metal2 ;
      RECT 188.825 577.990 188.895 578.200 ;
    END
  END r0_rd_out[494]
  PIN r0_rd_out[495]
    DIRECTION OUTPUT ;
    USE SIGNAL ;
    SHAPE ABUTMENT ;
    PORT
      LAYER metal2 ;
      RECT 189.205 577.990 189.275 578.200 ;
    END
  END r0_rd_out[495]
  PIN r0_rd_out[496]
    DIRECTION OUTPUT ;
    USE SIGNAL ;
    SHAPE ABUTMENT ;
    PORT
      LAYER metal2 ;
      RECT 189.585 577.990 189.655 578.200 ;
    END
  END r0_rd_out[496]
  PIN r0_rd_out[497]
    DIRECTION OUTPUT ;
    USE SIGNAL ;
    SHAPE ABUTMENT ;
    PORT
      LAYER metal2 ;
      RECT 189.965 577.990 190.035 578.200 ;
    END
  END r0_rd_out[497]
  PIN r0_rd_out[498]
    DIRECTION OUTPUT ;
    USE SIGNAL ;
    SHAPE ABUTMENT ;
    PORT
      LAYER metal2 ;
      RECT 190.345 577.990 190.415 578.200 ;
    END
  END r0_rd_out[498]
  PIN r0_rd_out[499]
    DIRECTION OUTPUT ;
    USE SIGNAL ;
    SHAPE ABUTMENT ;
    PORT
      LAYER metal2 ;
      RECT 190.725 577.990 190.795 578.200 ;
    END
  END r0_rd_out[499]
  PIN r0_rd_out[500]
    DIRECTION OUTPUT ;
    USE SIGNAL ;
    SHAPE ABUTMENT ;
    PORT
      LAYER metal2 ;
      RECT 191.105 577.990 191.175 578.200 ;
    END
  END r0_rd_out[500]
  PIN r0_rd_out[501]
    DIRECTION OUTPUT ;
    USE SIGNAL ;
    SHAPE ABUTMENT ;
    PORT
      LAYER metal2 ;
      RECT 191.485 577.990 191.555 578.200 ;
    END
  END r0_rd_out[501]
  PIN r0_rd_out[502]
    DIRECTION OUTPUT ;
    USE SIGNAL ;
    SHAPE ABUTMENT ;
    PORT
      LAYER metal2 ;
      RECT 191.865 577.990 191.935 578.200 ;
    END
  END r0_rd_out[502]
  PIN r0_rd_out[503]
    DIRECTION OUTPUT ;
    USE SIGNAL ;
    SHAPE ABUTMENT ;
    PORT
      LAYER metal2 ;
      RECT 192.245 577.990 192.315 578.200 ;
    END
  END r0_rd_out[503]
  PIN r0_rd_out[504]
    DIRECTION OUTPUT ;
    USE SIGNAL ;
    SHAPE ABUTMENT ;
    PORT
      LAYER metal2 ;
      RECT 192.625 577.990 192.695 578.200 ;
    END
  END r0_rd_out[504]
  PIN r0_rd_out[505]
    DIRECTION OUTPUT ;
    USE SIGNAL ;
    SHAPE ABUTMENT ;
    PORT
      LAYER metal2 ;
      RECT 193.005 577.990 193.075 578.200 ;
    END
  END r0_rd_out[505]
  PIN r0_rd_out[506]
    DIRECTION OUTPUT ;
    USE SIGNAL ;
    SHAPE ABUTMENT ;
    PORT
      LAYER metal2 ;
      RECT 193.385 577.990 193.455 578.200 ;
    END
  END r0_rd_out[506]
  PIN r0_rd_out[507]
    DIRECTION OUTPUT ;
    USE SIGNAL ;
    SHAPE ABUTMENT ;
    PORT
      LAYER metal2 ;
      RECT 193.765 577.990 193.835 578.200 ;
    END
  END r0_rd_out[507]
  PIN r0_rd_out[508]
    DIRECTION OUTPUT ;
    USE SIGNAL ;
    SHAPE ABUTMENT ;
    PORT
      LAYER metal2 ;
      RECT 194.145 577.990 194.215 578.200 ;
    END
  END r0_rd_out[508]
  PIN r0_rd_out[509]
    DIRECTION OUTPUT ;
    USE SIGNAL ;
    SHAPE ABUTMENT ;
    PORT
      LAYER metal2 ;
      RECT 194.525 577.990 194.595 578.200 ;
    END
  END r0_rd_out[509]
  PIN r0_rd_out[510]
    DIRECTION OUTPUT ;
    USE SIGNAL ;
    SHAPE ABUTMENT ;
    PORT
      LAYER metal2 ;
      RECT 194.905 577.990 194.975 578.200 ;
    END
  END r0_rd_out[510]
  PIN r0_rd_out[511]
    DIRECTION OUTPUT ;
    USE SIGNAL ;
    SHAPE ABUTMENT ;
    PORT
      LAYER metal2 ;
      RECT 195.285 577.990 195.355 578.200 ;
    END
  END r0_rd_out[511]
  PIN r0_rd_out[512]
    DIRECTION OUTPUT ;
    USE SIGNAL ;
    SHAPE ABUTMENT ;
    PORT
      LAYER metal2 ;
      RECT 195.665 577.990 195.735 578.200 ;
    END
  END r0_rd_out[512]
  PIN r0_rd_out[513]
    DIRECTION OUTPUT ;
    USE SIGNAL ;
    SHAPE ABUTMENT ;
    PORT
      LAYER metal2 ;
      RECT 196.045 577.990 196.115 578.200 ;
    END
  END r0_rd_out[513]
  PIN r0_rd_out[514]
    DIRECTION OUTPUT ;
    USE SIGNAL ;
    SHAPE ABUTMENT ;
    PORT
      LAYER metal2 ;
      RECT 196.425 577.990 196.495 578.200 ;
    END
  END r0_rd_out[514]
  PIN r0_rd_out[515]
    DIRECTION OUTPUT ;
    USE SIGNAL ;
    SHAPE ABUTMENT ;
    PORT
      LAYER metal2 ;
      RECT 196.805 577.990 196.875 578.200 ;
    END
  END r0_rd_out[515]
  PIN r0_rd_out[516]
    DIRECTION OUTPUT ;
    USE SIGNAL ;
    SHAPE ABUTMENT ;
    PORT
      LAYER metal2 ;
      RECT 197.185 577.990 197.255 578.200 ;
    END
  END r0_rd_out[516]
  PIN r0_rd_out[517]
    DIRECTION OUTPUT ;
    USE SIGNAL ;
    SHAPE ABUTMENT ;
    PORT
      LAYER metal2 ;
      RECT 197.565 577.990 197.635 578.200 ;
    END
  END r0_rd_out[517]
  PIN r0_rd_out[518]
    DIRECTION OUTPUT ;
    USE SIGNAL ;
    SHAPE ABUTMENT ;
    PORT
      LAYER metal2 ;
      RECT 197.945 577.990 198.015 578.200 ;
    END
  END r0_rd_out[518]
  PIN r0_rd_out[519]
    DIRECTION OUTPUT ;
    USE SIGNAL ;
    SHAPE ABUTMENT ;
    PORT
      LAYER metal2 ;
      RECT 198.325 577.990 198.395 578.200 ;
    END
  END r0_rd_out[519]
  PIN r0_rd_out[520]
    DIRECTION OUTPUT ;
    USE SIGNAL ;
    SHAPE ABUTMENT ;
    PORT
      LAYER metal2 ;
      RECT 198.705 577.990 198.775 578.200 ;
    END
  END r0_rd_out[520]
  PIN r0_rd_out[521]
    DIRECTION OUTPUT ;
    USE SIGNAL ;
    SHAPE ABUTMENT ;
    PORT
      LAYER metal2 ;
      RECT 199.085 577.990 199.155 578.200 ;
    END
  END r0_rd_out[521]
  PIN r0_rd_out[522]
    DIRECTION OUTPUT ;
    USE SIGNAL ;
    SHAPE ABUTMENT ;
    PORT
      LAYER metal2 ;
      RECT 199.465 577.990 199.535 578.200 ;
    END
  END r0_rd_out[522]
  PIN r0_rd_out[523]
    DIRECTION OUTPUT ;
    USE SIGNAL ;
    SHAPE ABUTMENT ;
    PORT
      LAYER metal2 ;
      RECT 199.845 577.990 199.915 578.200 ;
    END
  END r0_rd_out[523]
  PIN r0_rd_out[524]
    DIRECTION OUTPUT ;
    USE SIGNAL ;
    SHAPE ABUTMENT ;
    PORT
      LAYER metal2 ;
      RECT 200.225 577.990 200.295 578.200 ;
    END
  END r0_rd_out[524]
  PIN r0_rd_out[525]
    DIRECTION OUTPUT ;
    USE SIGNAL ;
    SHAPE ABUTMENT ;
    PORT
      LAYER metal2 ;
      RECT 200.605 577.990 200.675 578.200 ;
    END
  END r0_rd_out[525]
  PIN r0_rd_out[526]
    DIRECTION OUTPUT ;
    USE SIGNAL ;
    SHAPE ABUTMENT ;
    PORT
      LAYER metal2 ;
      RECT 200.985 577.990 201.055 578.200 ;
    END
  END r0_rd_out[526]
  PIN r0_rd_out[527]
    DIRECTION OUTPUT ;
    USE SIGNAL ;
    SHAPE ABUTMENT ;
    PORT
      LAYER metal2 ;
      RECT 201.365 577.990 201.435 578.200 ;
    END
  END r0_rd_out[527]
  PIN r0_rd_out[528]
    DIRECTION OUTPUT ;
    USE SIGNAL ;
    SHAPE ABUTMENT ;
    PORT
      LAYER metal2 ;
      RECT 201.745 577.990 201.815 578.200 ;
    END
  END r0_rd_out[528]
  PIN r0_rd_out[529]
    DIRECTION OUTPUT ;
    USE SIGNAL ;
    SHAPE ABUTMENT ;
    PORT
      LAYER metal2 ;
      RECT 202.125 577.990 202.195 578.200 ;
    END
  END r0_rd_out[529]
  PIN r0_rd_out[530]
    DIRECTION OUTPUT ;
    USE SIGNAL ;
    SHAPE ABUTMENT ;
    PORT
      LAYER metal2 ;
      RECT 202.505 577.990 202.575 578.200 ;
    END
  END r0_rd_out[530]
  PIN r0_rd_out[531]
    DIRECTION OUTPUT ;
    USE SIGNAL ;
    SHAPE ABUTMENT ;
    PORT
      LAYER metal2 ;
      RECT 202.885 577.990 202.955 578.200 ;
    END
  END r0_rd_out[531]
  PIN r0_rd_out[532]
    DIRECTION OUTPUT ;
    USE SIGNAL ;
    SHAPE ABUTMENT ;
    PORT
      LAYER metal2 ;
      RECT 203.265 577.990 203.335 578.200 ;
    END
  END r0_rd_out[532]
  PIN r0_rd_out[533]
    DIRECTION OUTPUT ;
    USE SIGNAL ;
    SHAPE ABUTMENT ;
    PORT
      LAYER metal2 ;
      RECT 203.645 577.990 203.715 578.200 ;
    END
  END r0_rd_out[533]
  PIN r0_rd_out[534]
    DIRECTION OUTPUT ;
    USE SIGNAL ;
    SHAPE ABUTMENT ;
    PORT
      LAYER metal2 ;
      RECT 204.025 577.990 204.095 578.200 ;
    END
  END r0_rd_out[534]
  PIN r0_rd_out[535]
    DIRECTION OUTPUT ;
    USE SIGNAL ;
    SHAPE ABUTMENT ;
    PORT
      LAYER metal2 ;
      RECT 204.405 577.990 204.475 578.200 ;
    END
  END r0_rd_out[535]
  PIN r0_rd_out[536]
    DIRECTION OUTPUT ;
    USE SIGNAL ;
    SHAPE ABUTMENT ;
    PORT
      LAYER metal2 ;
      RECT 204.785 577.990 204.855 578.200 ;
    END
  END r0_rd_out[536]
  PIN r0_rd_out[537]
    DIRECTION OUTPUT ;
    USE SIGNAL ;
    SHAPE ABUTMENT ;
    PORT
      LAYER metal2 ;
      RECT 205.165 577.990 205.235 578.200 ;
    END
  END r0_rd_out[537]
  PIN r0_rd_out[538]
    DIRECTION OUTPUT ;
    USE SIGNAL ;
    SHAPE ABUTMENT ;
    PORT
      LAYER metal2 ;
      RECT 205.545 577.990 205.615 578.200 ;
    END
  END r0_rd_out[538]
  PIN r0_rd_out[539]
    DIRECTION OUTPUT ;
    USE SIGNAL ;
    SHAPE ABUTMENT ;
    PORT
      LAYER metal2 ;
      RECT 205.925 577.990 205.995 578.200 ;
    END
  END r0_rd_out[539]
  PIN r0_rd_out[540]
    DIRECTION OUTPUT ;
    USE SIGNAL ;
    SHAPE ABUTMENT ;
    PORT
      LAYER metal2 ;
      RECT 206.305 577.990 206.375 578.200 ;
    END
  END r0_rd_out[540]
  PIN r0_rd_out[541]
    DIRECTION OUTPUT ;
    USE SIGNAL ;
    SHAPE ABUTMENT ;
    PORT
      LAYER metal2 ;
      RECT 206.685 577.990 206.755 578.200 ;
    END
  END r0_rd_out[541]
  PIN r0_rd_out[542]
    DIRECTION OUTPUT ;
    USE SIGNAL ;
    SHAPE ABUTMENT ;
    PORT
      LAYER metal2 ;
      RECT 207.065 577.990 207.135 578.200 ;
    END
  END r0_rd_out[542]
  PIN r0_rd_out[543]
    DIRECTION OUTPUT ;
    USE SIGNAL ;
    SHAPE ABUTMENT ;
    PORT
      LAYER metal2 ;
      RECT 207.445 577.990 207.515 578.200 ;
    END
  END r0_rd_out[543]
  PIN r0_rd_out[544]
    DIRECTION OUTPUT ;
    USE SIGNAL ;
    SHAPE ABUTMENT ;
    PORT
      LAYER metal2 ;
      RECT 207.825 577.990 207.895 578.200 ;
    END
  END r0_rd_out[544]
  PIN r0_rd_out[545]
    DIRECTION OUTPUT ;
    USE SIGNAL ;
    SHAPE ABUTMENT ;
    PORT
      LAYER metal2 ;
      RECT 208.205 577.990 208.275 578.200 ;
    END
  END r0_rd_out[545]
  PIN r0_rd_out[546]
    DIRECTION OUTPUT ;
    USE SIGNAL ;
    SHAPE ABUTMENT ;
    PORT
      LAYER metal2 ;
      RECT 208.585 577.990 208.655 578.200 ;
    END
  END r0_rd_out[546]
  PIN r0_rd_out[547]
    DIRECTION OUTPUT ;
    USE SIGNAL ;
    SHAPE ABUTMENT ;
    PORT
      LAYER metal2 ;
      RECT 208.965 577.990 209.035 578.200 ;
    END
  END r0_rd_out[547]
  PIN r0_rd_out[548]
    DIRECTION OUTPUT ;
    USE SIGNAL ;
    SHAPE ABUTMENT ;
    PORT
      LAYER metal2 ;
      RECT 209.345 577.990 209.415 578.200 ;
    END
  END r0_rd_out[548]
  PIN r0_rd_out[549]
    DIRECTION OUTPUT ;
    USE SIGNAL ;
    SHAPE ABUTMENT ;
    PORT
      LAYER metal2 ;
      RECT 209.725 577.990 209.795 578.200 ;
    END
  END r0_rd_out[549]
  PIN r0_rd_out[550]
    DIRECTION OUTPUT ;
    USE SIGNAL ;
    SHAPE ABUTMENT ;
    PORT
      LAYER metal2 ;
      RECT 210.105 577.990 210.175 578.200 ;
    END
  END r0_rd_out[550]
  PIN r0_rd_out[551]
    DIRECTION OUTPUT ;
    USE SIGNAL ;
    SHAPE ABUTMENT ;
    PORT
      LAYER metal2 ;
      RECT 210.485 577.990 210.555 578.200 ;
    END
  END r0_rd_out[551]
  PIN r0_rd_out[552]
    DIRECTION OUTPUT ;
    USE SIGNAL ;
    SHAPE ABUTMENT ;
    PORT
      LAYER metal2 ;
      RECT 210.865 577.990 210.935 578.200 ;
    END
  END r0_rd_out[552]
  PIN r0_rd_out[553]
    DIRECTION OUTPUT ;
    USE SIGNAL ;
    SHAPE ABUTMENT ;
    PORT
      LAYER metal2 ;
      RECT 211.245 577.990 211.315 578.200 ;
    END
  END r0_rd_out[553]
  PIN r0_rd_out[554]
    DIRECTION OUTPUT ;
    USE SIGNAL ;
    SHAPE ABUTMENT ;
    PORT
      LAYER metal2 ;
      RECT 211.625 577.990 211.695 578.200 ;
    END
  END r0_rd_out[554]
  PIN r0_rd_out[555]
    DIRECTION OUTPUT ;
    USE SIGNAL ;
    SHAPE ABUTMENT ;
    PORT
      LAYER metal2 ;
      RECT 212.005 577.990 212.075 578.200 ;
    END
  END r0_rd_out[555]
  PIN r0_rd_out[556]
    DIRECTION OUTPUT ;
    USE SIGNAL ;
    SHAPE ABUTMENT ;
    PORT
      LAYER metal2 ;
      RECT 212.385 577.990 212.455 578.200 ;
    END
  END r0_rd_out[556]
  PIN r0_rd_out[557]
    DIRECTION OUTPUT ;
    USE SIGNAL ;
    SHAPE ABUTMENT ;
    PORT
      LAYER metal2 ;
      RECT 212.765 577.990 212.835 578.200 ;
    END
  END r0_rd_out[557]
  PIN r0_rd_out[558]
    DIRECTION OUTPUT ;
    USE SIGNAL ;
    SHAPE ABUTMENT ;
    PORT
      LAYER metal2 ;
      RECT 213.145 577.990 213.215 578.200 ;
    END
  END r0_rd_out[558]
  PIN r0_rd_out[559]
    DIRECTION OUTPUT ;
    USE SIGNAL ;
    SHAPE ABUTMENT ;
    PORT
      LAYER metal2 ;
      RECT 213.525 577.990 213.595 578.200 ;
    END
  END r0_rd_out[559]
  PIN r0_rd_out[560]
    DIRECTION OUTPUT ;
    USE SIGNAL ;
    SHAPE ABUTMENT ;
    PORT
      LAYER metal2 ;
      RECT 213.905 577.990 213.975 578.200 ;
    END
  END r0_rd_out[560]
  PIN r0_rd_out[561]
    DIRECTION OUTPUT ;
    USE SIGNAL ;
    SHAPE ABUTMENT ;
    PORT
      LAYER metal2 ;
      RECT 214.285 577.990 214.355 578.200 ;
    END
  END r0_rd_out[561]
  PIN r0_rd_out[562]
    DIRECTION OUTPUT ;
    USE SIGNAL ;
    SHAPE ABUTMENT ;
    PORT
      LAYER metal2 ;
      RECT 214.665 577.990 214.735 578.200 ;
    END
  END r0_rd_out[562]
  PIN r0_rd_out[563]
    DIRECTION OUTPUT ;
    USE SIGNAL ;
    SHAPE ABUTMENT ;
    PORT
      LAYER metal2 ;
      RECT 215.045 577.990 215.115 578.200 ;
    END
  END r0_rd_out[563]
  PIN r0_rd_out[564]
    DIRECTION OUTPUT ;
    USE SIGNAL ;
    SHAPE ABUTMENT ;
    PORT
      LAYER metal2 ;
      RECT 215.425 577.990 215.495 578.200 ;
    END
  END r0_rd_out[564]
  PIN r0_rd_out[565]
    DIRECTION OUTPUT ;
    USE SIGNAL ;
    SHAPE ABUTMENT ;
    PORT
      LAYER metal2 ;
      RECT 215.805 577.990 215.875 578.200 ;
    END
  END r0_rd_out[565]
  PIN r0_rd_out[566]
    DIRECTION OUTPUT ;
    USE SIGNAL ;
    SHAPE ABUTMENT ;
    PORT
      LAYER metal2 ;
      RECT 216.185 577.990 216.255 578.200 ;
    END
  END r0_rd_out[566]
  PIN r0_rd_out[567]
    DIRECTION OUTPUT ;
    USE SIGNAL ;
    SHAPE ABUTMENT ;
    PORT
      LAYER metal2 ;
      RECT 216.565 577.990 216.635 578.200 ;
    END
  END r0_rd_out[567]
  PIN r0_rd_out[568]
    DIRECTION OUTPUT ;
    USE SIGNAL ;
    SHAPE ABUTMENT ;
    PORT
      LAYER metal2 ;
      RECT 216.945 577.990 217.015 578.200 ;
    END
  END r0_rd_out[568]
  PIN r0_rd_out[569]
    DIRECTION OUTPUT ;
    USE SIGNAL ;
    SHAPE ABUTMENT ;
    PORT
      LAYER metal2 ;
      RECT 217.325 577.990 217.395 578.200 ;
    END
  END r0_rd_out[569]
  PIN r0_rd_out[570]
    DIRECTION OUTPUT ;
    USE SIGNAL ;
    SHAPE ABUTMENT ;
    PORT
      LAYER metal2 ;
      RECT 217.705 577.990 217.775 578.200 ;
    END
  END r0_rd_out[570]
  PIN r0_rd_out[571]
    DIRECTION OUTPUT ;
    USE SIGNAL ;
    SHAPE ABUTMENT ;
    PORT
      LAYER metal2 ;
      RECT 218.085 577.990 218.155 578.200 ;
    END
  END r0_rd_out[571]
  PIN r0_rd_out[572]
    DIRECTION OUTPUT ;
    USE SIGNAL ;
    SHAPE ABUTMENT ;
    PORT
      LAYER metal2 ;
      RECT 218.465 577.990 218.535 578.200 ;
    END
  END r0_rd_out[572]
  PIN r0_rd_out[573]
    DIRECTION OUTPUT ;
    USE SIGNAL ;
    SHAPE ABUTMENT ;
    PORT
      LAYER metal2 ;
      RECT 218.845 577.990 218.915 578.200 ;
    END
  END r0_rd_out[573]
  PIN r0_rd_out[574]
    DIRECTION OUTPUT ;
    USE SIGNAL ;
    SHAPE ABUTMENT ;
    PORT
      LAYER metal2 ;
      RECT 219.225 577.990 219.295 578.200 ;
    END
  END r0_rd_out[574]
  PIN r0_rd_out[575]
    DIRECTION OUTPUT ;
    USE SIGNAL ;
    SHAPE ABUTMENT ;
    PORT
      LAYER metal2 ;
      RECT 219.605 577.990 219.675 578.200 ;
    END
  END r0_rd_out[575]
  PIN r0_rd_out[576]
    DIRECTION OUTPUT ;
    USE SIGNAL ;
    SHAPE ABUTMENT ;
    PORT
      LAYER metal2 ;
      RECT 219.985 577.990 220.055 578.200 ;
    END
  END r0_rd_out[576]
  PIN r0_rd_out[577]
    DIRECTION OUTPUT ;
    USE SIGNAL ;
    SHAPE ABUTMENT ;
    PORT
      LAYER metal2 ;
      RECT 220.365 577.990 220.435 578.200 ;
    END
  END r0_rd_out[577]
  PIN r0_rd_out[578]
    DIRECTION OUTPUT ;
    USE SIGNAL ;
    SHAPE ABUTMENT ;
    PORT
      LAYER metal2 ;
      RECT 220.745 577.990 220.815 578.200 ;
    END
  END r0_rd_out[578]
  PIN r0_rd_out[579]
    DIRECTION OUTPUT ;
    USE SIGNAL ;
    SHAPE ABUTMENT ;
    PORT
      LAYER metal2 ;
      RECT 221.125 577.990 221.195 578.200 ;
    END
  END r0_rd_out[579]
  PIN r0_rd_out[580]
    DIRECTION OUTPUT ;
    USE SIGNAL ;
    SHAPE ABUTMENT ;
    PORT
      LAYER metal2 ;
      RECT 221.505 577.990 221.575 578.200 ;
    END
  END r0_rd_out[580]
  PIN r0_rd_out[581]
    DIRECTION OUTPUT ;
    USE SIGNAL ;
    SHAPE ABUTMENT ;
    PORT
      LAYER metal2 ;
      RECT 221.885 577.990 221.955 578.200 ;
    END
  END r0_rd_out[581]
  PIN r0_rd_out[582]
    DIRECTION OUTPUT ;
    USE SIGNAL ;
    SHAPE ABUTMENT ;
    PORT
      LAYER metal2 ;
      RECT 222.265 577.990 222.335 578.200 ;
    END
  END r0_rd_out[582]
  PIN r0_rd_out[583]
    DIRECTION OUTPUT ;
    USE SIGNAL ;
    SHAPE ABUTMENT ;
    PORT
      LAYER metal2 ;
      RECT 222.645 577.990 222.715 578.200 ;
    END
  END r0_rd_out[583]
  PIN r0_rd_out[584]
    DIRECTION OUTPUT ;
    USE SIGNAL ;
    SHAPE ABUTMENT ;
    PORT
      LAYER metal2 ;
      RECT 223.025 577.990 223.095 578.200 ;
    END
  END r0_rd_out[584]
  PIN r0_rd_out[585]
    DIRECTION OUTPUT ;
    USE SIGNAL ;
    SHAPE ABUTMENT ;
    PORT
      LAYER metal2 ;
      RECT 223.405 577.990 223.475 578.200 ;
    END
  END r0_rd_out[585]
  PIN r0_rd_out[586]
    DIRECTION OUTPUT ;
    USE SIGNAL ;
    SHAPE ABUTMENT ;
    PORT
      LAYER metal2 ;
      RECT 223.785 577.990 223.855 578.200 ;
    END
  END r0_rd_out[586]
  PIN r0_rd_out[587]
    DIRECTION OUTPUT ;
    USE SIGNAL ;
    SHAPE ABUTMENT ;
    PORT
      LAYER metal2 ;
      RECT 224.165 577.990 224.235 578.200 ;
    END
  END r0_rd_out[587]
  PIN r0_rd_out[588]
    DIRECTION OUTPUT ;
    USE SIGNAL ;
    SHAPE ABUTMENT ;
    PORT
      LAYER metal2 ;
      RECT 224.545 577.990 224.615 578.200 ;
    END
  END r0_rd_out[588]
  PIN r0_rd_out[589]
    DIRECTION OUTPUT ;
    USE SIGNAL ;
    SHAPE ABUTMENT ;
    PORT
      LAYER metal2 ;
      RECT 224.925 577.990 224.995 578.200 ;
    END
  END r0_rd_out[589]
  PIN r0_rd_out[590]
    DIRECTION OUTPUT ;
    USE SIGNAL ;
    SHAPE ABUTMENT ;
    PORT
      LAYER metal2 ;
      RECT 225.305 577.990 225.375 578.200 ;
    END
  END r0_rd_out[590]
  PIN r0_rd_out[591]
    DIRECTION OUTPUT ;
    USE SIGNAL ;
    SHAPE ABUTMENT ;
    PORT
      LAYER metal2 ;
      RECT 225.685 577.990 225.755 578.200 ;
    END
  END r0_rd_out[591]
  PIN r0_rd_out[592]
    DIRECTION OUTPUT ;
    USE SIGNAL ;
    SHAPE ABUTMENT ;
    PORT
      LAYER metal2 ;
      RECT 226.065 577.990 226.135 578.200 ;
    END
  END r0_rd_out[592]
  PIN r0_rd_out[593]
    DIRECTION OUTPUT ;
    USE SIGNAL ;
    SHAPE ABUTMENT ;
    PORT
      LAYER metal2 ;
      RECT 226.445 577.990 226.515 578.200 ;
    END
  END r0_rd_out[593]
  PIN r0_rd_out[594]
    DIRECTION OUTPUT ;
    USE SIGNAL ;
    SHAPE ABUTMENT ;
    PORT
      LAYER metal2 ;
      RECT 226.825 577.990 226.895 578.200 ;
    END
  END r0_rd_out[594]
  PIN r0_rd_out[595]
    DIRECTION OUTPUT ;
    USE SIGNAL ;
    SHAPE ABUTMENT ;
    PORT
      LAYER metal2 ;
      RECT 227.205 577.990 227.275 578.200 ;
    END
  END r0_rd_out[595]
  PIN r0_rd_out[596]
    DIRECTION OUTPUT ;
    USE SIGNAL ;
    SHAPE ABUTMENT ;
    PORT
      LAYER metal2 ;
      RECT 227.585 577.990 227.655 578.200 ;
    END
  END r0_rd_out[596]
  PIN r0_rd_out[597]
    DIRECTION OUTPUT ;
    USE SIGNAL ;
    SHAPE ABUTMENT ;
    PORT
      LAYER metal2 ;
      RECT 227.965 577.990 228.035 578.200 ;
    END
  END r0_rd_out[597]
  PIN r0_rd_out[598]
    DIRECTION OUTPUT ;
    USE SIGNAL ;
    SHAPE ABUTMENT ;
    PORT
      LAYER metal2 ;
      RECT 228.345 577.990 228.415 578.200 ;
    END
  END r0_rd_out[598]
  PIN r0_rd_out[599]
    DIRECTION OUTPUT ;
    USE SIGNAL ;
    SHAPE ABUTMENT ;
    PORT
      LAYER metal2 ;
      RECT 228.725 577.990 228.795 578.200 ;
    END
  END r0_rd_out[599]
  PIN r0_rd_out[600]
    DIRECTION OUTPUT ;
    USE SIGNAL ;
    SHAPE ABUTMENT ;
    PORT
      LAYER metal2 ;
      RECT 229.105 577.990 229.175 578.200 ;
    END
  END r0_rd_out[600]
  PIN r0_rd_out[601]
    DIRECTION OUTPUT ;
    USE SIGNAL ;
    SHAPE ABUTMENT ;
    PORT
      LAYER metal2 ;
      RECT 229.485 577.990 229.555 578.200 ;
    END
  END r0_rd_out[601]
  PIN r0_rd_out[602]
    DIRECTION OUTPUT ;
    USE SIGNAL ;
    SHAPE ABUTMENT ;
    PORT
      LAYER metal2 ;
      RECT 229.865 577.990 229.935 578.200 ;
    END
  END r0_rd_out[602]
  PIN r0_rd_out[603]
    DIRECTION OUTPUT ;
    USE SIGNAL ;
    SHAPE ABUTMENT ;
    PORT
      LAYER metal2 ;
      RECT 230.245 577.990 230.315 578.200 ;
    END
  END r0_rd_out[603]
  PIN r0_rd_out[604]
    DIRECTION OUTPUT ;
    USE SIGNAL ;
    SHAPE ABUTMENT ;
    PORT
      LAYER metal2 ;
      RECT 230.625 577.990 230.695 578.200 ;
    END
  END r0_rd_out[604]
  PIN r0_rd_out[605]
    DIRECTION OUTPUT ;
    USE SIGNAL ;
    SHAPE ABUTMENT ;
    PORT
      LAYER metal2 ;
      RECT 231.005 577.990 231.075 578.200 ;
    END
  END r0_rd_out[605]
  PIN r0_rd_out[606]
    DIRECTION OUTPUT ;
    USE SIGNAL ;
    SHAPE ABUTMENT ;
    PORT
      LAYER metal2 ;
      RECT 231.385 577.990 231.455 578.200 ;
    END
  END r0_rd_out[606]
  PIN r0_rd_out[607]
    DIRECTION OUTPUT ;
    USE SIGNAL ;
    SHAPE ABUTMENT ;
    PORT
      LAYER metal2 ;
      RECT 231.765 577.990 231.835 578.200 ;
    END
  END r0_rd_out[607]
  PIN r0_rd_out[608]
    DIRECTION OUTPUT ;
    USE SIGNAL ;
    SHAPE ABUTMENT ;
    PORT
      LAYER metal2 ;
      RECT 232.145 577.990 232.215 578.200 ;
    END
  END r0_rd_out[608]
  PIN r0_rd_out[609]
    DIRECTION OUTPUT ;
    USE SIGNAL ;
    SHAPE ABUTMENT ;
    PORT
      LAYER metal2 ;
      RECT 232.525 577.990 232.595 578.200 ;
    END
  END r0_rd_out[609]
  PIN r0_rd_out[610]
    DIRECTION OUTPUT ;
    USE SIGNAL ;
    SHAPE ABUTMENT ;
    PORT
      LAYER metal2 ;
      RECT 232.905 577.990 232.975 578.200 ;
    END
  END r0_rd_out[610]
  PIN r0_rd_out[611]
    DIRECTION OUTPUT ;
    USE SIGNAL ;
    SHAPE ABUTMENT ;
    PORT
      LAYER metal2 ;
      RECT 233.285 577.990 233.355 578.200 ;
    END
  END r0_rd_out[611]
  PIN r0_rd_out[612]
    DIRECTION OUTPUT ;
    USE SIGNAL ;
    SHAPE ABUTMENT ;
    PORT
      LAYER metal2 ;
      RECT 233.665 577.990 233.735 578.200 ;
    END
  END r0_rd_out[612]
  PIN r0_rd_out[613]
    DIRECTION OUTPUT ;
    USE SIGNAL ;
    SHAPE ABUTMENT ;
    PORT
      LAYER metal2 ;
      RECT 234.045 577.990 234.115 578.200 ;
    END
  END r0_rd_out[613]
  PIN r0_rd_out[614]
    DIRECTION OUTPUT ;
    USE SIGNAL ;
    SHAPE ABUTMENT ;
    PORT
      LAYER metal2 ;
      RECT 234.425 577.990 234.495 578.200 ;
    END
  END r0_rd_out[614]
  PIN r0_rd_out[615]
    DIRECTION OUTPUT ;
    USE SIGNAL ;
    SHAPE ABUTMENT ;
    PORT
      LAYER metal2 ;
      RECT 234.805 577.990 234.875 578.200 ;
    END
  END r0_rd_out[615]
  PIN r0_rd_out[616]
    DIRECTION OUTPUT ;
    USE SIGNAL ;
    SHAPE ABUTMENT ;
    PORT
      LAYER metal2 ;
      RECT 235.185 577.990 235.255 578.200 ;
    END
  END r0_rd_out[616]
  PIN r0_rd_out[617]
    DIRECTION OUTPUT ;
    USE SIGNAL ;
    SHAPE ABUTMENT ;
    PORT
      LAYER metal2 ;
      RECT 235.565 577.990 235.635 578.200 ;
    END
  END r0_rd_out[617]
  PIN r0_rd_out[618]
    DIRECTION OUTPUT ;
    USE SIGNAL ;
    SHAPE ABUTMENT ;
    PORT
      LAYER metal2 ;
      RECT 235.945 577.990 236.015 578.200 ;
    END
  END r0_rd_out[618]
  PIN r0_rd_out[619]
    DIRECTION OUTPUT ;
    USE SIGNAL ;
    SHAPE ABUTMENT ;
    PORT
      LAYER metal2 ;
      RECT 236.325 577.990 236.395 578.200 ;
    END
  END r0_rd_out[619]
  PIN r0_rd_out[620]
    DIRECTION OUTPUT ;
    USE SIGNAL ;
    SHAPE ABUTMENT ;
    PORT
      LAYER metal2 ;
      RECT 236.705 577.990 236.775 578.200 ;
    END
  END r0_rd_out[620]
  PIN r0_rd_out[621]
    DIRECTION OUTPUT ;
    USE SIGNAL ;
    SHAPE ABUTMENT ;
    PORT
      LAYER metal2 ;
      RECT 237.085 577.990 237.155 578.200 ;
    END
  END r0_rd_out[621]
  PIN r0_rd_out[622]
    DIRECTION OUTPUT ;
    USE SIGNAL ;
    SHAPE ABUTMENT ;
    PORT
      LAYER metal2 ;
      RECT 237.465 577.990 237.535 578.200 ;
    END
  END r0_rd_out[622]
  PIN r0_rd_out[623]
    DIRECTION OUTPUT ;
    USE SIGNAL ;
    SHAPE ABUTMENT ;
    PORT
      LAYER metal2 ;
      RECT 237.845 577.990 237.915 578.200 ;
    END
  END r0_rd_out[623]
  PIN r0_rd_out[624]
    DIRECTION OUTPUT ;
    USE SIGNAL ;
    SHAPE ABUTMENT ;
    PORT
      LAYER metal2 ;
      RECT 238.225 577.990 238.295 578.200 ;
    END
  END r0_rd_out[624]
  PIN r0_rd_out[625]
    DIRECTION OUTPUT ;
    USE SIGNAL ;
    SHAPE ABUTMENT ;
    PORT
      LAYER metal2 ;
      RECT 238.605 577.990 238.675 578.200 ;
    END
  END r0_rd_out[625]
  PIN r0_rd_out[626]
    DIRECTION OUTPUT ;
    USE SIGNAL ;
    SHAPE ABUTMENT ;
    PORT
      LAYER metal2 ;
      RECT 238.985 577.990 239.055 578.200 ;
    END
  END r0_rd_out[626]
  PIN r0_rd_out[627]
    DIRECTION OUTPUT ;
    USE SIGNAL ;
    SHAPE ABUTMENT ;
    PORT
      LAYER metal2 ;
      RECT 239.365 577.990 239.435 578.200 ;
    END
  END r0_rd_out[627]
  PIN r0_rd_out[628]
    DIRECTION OUTPUT ;
    USE SIGNAL ;
    SHAPE ABUTMENT ;
    PORT
      LAYER metal2 ;
      RECT 239.745 577.990 239.815 578.200 ;
    END
  END r0_rd_out[628]
  PIN r0_rd_out[629]
    DIRECTION OUTPUT ;
    USE SIGNAL ;
    SHAPE ABUTMENT ;
    PORT
      LAYER metal2 ;
      RECT 240.125 577.990 240.195 578.200 ;
    END
  END r0_rd_out[629]
  PIN r0_rd_out[630]
    DIRECTION OUTPUT ;
    USE SIGNAL ;
    SHAPE ABUTMENT ;
    PORT
      LAYER metal2 ;
      RECT 240.505 577.990 240.575 578.200 ;
    END
  END r0_rd_out[630]
  PIN r0_rd_out[631]
    DIRECTION OUTPUT ;
    USE SIGNAL ;
    SHAPE ABUTMENT ;
    PORT
      LAYER metal2 ;
      RECT 240.885 577.990 240.955 578.200 ;
    END
  END r0_rd_out[631]
  PIN r0_rd_out[632]
    DIRECTION OUTPUT ;
    USE SIGNAL ;
    SHAPE ABUTMENT ;
    PORT
      LAYER metal2 ;
      RECT 241.265 577.990 241.335 578.200 ;
    END
  END r0_rd_out[632]
  PIN r0_rd_out[633]
    DIRECTION OUTPUT ;
    USE SIGNAL ;
    SHAPE ABUTMENT ;
    PORT
      LAYER metal2 ;
      RECT 241.645 577.990 241.715 578.200 ;
    END
  END r0_rd_out[633]
  PIN r0_rd_out[634]
    DIRECTION OUTPUT ;
    USE SIGNAL ;
    SHAPE ABUTMENT ;
    PORT
      LAYER metal2 ;
      RECT 242.025 577.990 242.095 578.200 ;
    END
  END r0_rd_out[634]
  PIN r0_rd_out[635]
    DIRECTION OUTPUT ;
    USE SIGNAL ;
    SHAPE ABUTMENT ;
    PORT
      LAYER metal2 ;
      RECT 242.405 577.990 242.475 578.200 ;
    END
  END r0_rd_out[635]
  PIN r0_rd_out[636]
    DIRECTION OUTPUT ;
    USE SIGNAL ;
    SHAPE ABUTMENT ;
    PORT
      LAYER metal2 ;
      RECT 242.785 577.990 242.855 578.200 ;
    END
  END r0_rd_out[636]
  PIN r0_rd_out[637]
    DIRECTION OUTPUT ;
    USE SIGNAL ;
    SHAPE ABUTMENT ;
    PORT
      LAYER metal2 ;
      RECT 243.165 577.990 243.235 578.200 ;
    END
  END r0_rd_out[637]
  PIN r0_rd_out[638]
    DIRECTION OUTPUT ;
    USE SIGNAL ;
    SHAPE ABUTMENT ;
    PORT
      LAYER metal2 ;
      RECT 243.545 577.990 243.615 578.200 ;
    END
  END r0_rd_out[638]
  PIN r0_rd_out[639]
    DIRECTION OUTPUT ;
    USE SIGNAL ;
    SHAPE ABUTMENT ;
    PORT
      LAYER metal2 ;
      RECT 243.925 577.990 243.995 578.200 ;
    END
  END r0_rd_out[639]
  PIN r0_rd_out[640]
    DIRECTION OUTPUT ;
    USE SIGNAL ;
    SHAPE ABUTMENT ;
    PORT
      LAYER metal2 ;
      RECT 244.305 577.990 244.375 578.200 ;
    END
  END r0_rd_out[640]
  PIN r0_rd_out[641]
    DIRECTION OUTPUT ;
    USE SIGNAL ;
    SHAPE ABUTMENT ;
    PORT
      LAYER metal2 ;
      RECT 244.685 577.990 244.755 578.200 ;
    END
  END r0_rd_out[641]
  PIN r0_rd_out[642]
    DIRECTION OUTPUT ;
    USE SIGNAL ;
    SHAPE ABUTMENT ;
    PORT
      LAYER metal2 ;
      RECT 245.065 577.990 245.135 578.200 ;
    END
  END r0_rd_out[642]
  PIN r0_rd_out[643]
    DIRECTION OUTPUT ;
    USE SIGNAL ;
    SHAPE ABUTMENT ;
    PORT
      LAYER metal2 ;
      RECT 245.445 577.990 245.515 578.200 ;
    END
  END r0_rd_out[643]
  PIN r0_rd_out[644]
    DIRECTION OUTPUT ;
    USE SIGNAL ;
    SHAPE ABUTMENT ;
    PORT
      LAYER metal2 ;
      RECT 245.825 577.990 245.895 578.200 ;
    END
  END r0_rd_out[644]
  PIN r0_rd_out[645]
    DIRECTION OUTPUT ;
    USE SIGNAL ;
    SHAPE ABUTMENT ;
    PORT
      LAYER metal2 ;
      RECT 246.205 577.990 246.275 578.200 ;
    END
  END r0_rd_out[645]
  PIN r0_rd_out[646]
    DIRECTION OUTPUT ;
    USE SIGNAL ;
    SHAPE ABUTMENT ;
    PORT
      LAYER metal2 ;
      RECT 246.585 577.990 246.655 578.200 ;
    END
  END r0_rd_out[646]
  PIN r0_rd_out[647]
    DIRECTION OUTPUT ;
    USE SIGNAL ;
    SHAPE ABUTMENT ;
    PORT
      LAYER metal2 ;
      RECT 246.965 577.990 247.035 578.200 ;
    END
  END r0_rd_out[647]
  PIN r0_rd_out[648]
    DIRECTION OUTPUT ;
    USE SIGNAL ;
    SHAPE ABUTMENT ;
    PORT
      LAYER metal2 ;
      RECT 247.345 577.990 247.415 578.200 ;
    END
  END r0_rd_out[648]
  PIN r0_rd_out[649]
    DIRECTION OUTPUT ;
    USE SIGNAL ;
    SHAPE ABUTMENT ;
    PORT
      LAYER metal2 ;
      RECT 247.725 577.990 247.795 578.200 ;
    END
  END r0_rd_out[649]
  PIN r0_rd_out[650]
    DIRECTION OUTPUT ;
    USE SIGNAL ;
    SHAPE ABUTMENT ;
    PORT
      LAYER metal2 ;
      RECT 248.105 577.990 248.175 578.200 ;
    END
  END r0_rd_out[650]
  PIN r0_rd_out[651]
    DIRECTION OUTPUT ;
    USE SIGNAL ;
    SHAPE ABUTMENT ;
    PORT
      LAYER metal2 ;
      RECT 248.485 577.990 248.555 578.200 ;
    END
  END r0_rd_out[651]
  PIN r0_rd_out[652]
    DIRECTION OUTPUT ;
    USE SIGNAL ;
    SHAPE ABUTMENT ;
    PORT
      LAYER metal2 ;
      RECT 248.865 577.990 248.935 578.200 ;
    END
  END r0_rd_out[652]
  PIN r0_rd_out[653]
    DIRECTION OUTPUT ;
    USE SIGNAL ;
    SHAPE ABUTMENT ;
    PORT
      LAYER metal2 ;
      RECT 249.245 577.990 249.315 578.200 ;
    END
  END r0_rd_out[653]
  PIN w0_addr_in[0]
    DIRECTION INPUT ;
    USE SIGNAL ;
    SHAPE ABUTMENT ;
    PORT
      LAYER metal3 ;
      RECT 0.000 551.845 0.210 551.915 ;
    END
  END w0_addr_in[0]
  PIN w0_addr_in[1]
    DIRECTION INPUT ;
    USE SIGNAL ;
    SHAPE ABUTMENT ;
    PORT
      LAYER metal3 ;
      RECT 0.000 553.525 0.210 553.595 ;
    END
  END w0_addr_in[1]
  PIN r0_addr_in[0]
    DIRECTION INPUT ;
    USE SIGNAL ;
    SHAPE ABUTMENT ;
    PORT
      LAYER metal3 ;
      RECT 0.000 556.885 0.210 556.955 ;
    END
  END r0_addr_in[0]
  PIN r0_addr_in[1]
    DIRECTION INPUT ;
    USE SIGNAL ;
    SHAPE ABUTMENT ;
    PORT
      LAYER metal3 ;
      RECT 0.000 558.565 0.210 558.635 ;
    END
  END r0_addr_in[1]
  PIN w0_we_in
    DIRECTION INPUT ;
    USE SIGNAL ;
    SHAPE ABUTMENT ;
    PORT
      LAYER metal2 ;
      RECT 249.625 577.990 249.695 578.200 ;
    END
  END w0_we_in
  PIN w0_ce_in
    DIRECTION INPUT ;
    USE SIGNAL ;
    SHAPE ABUTMENT ;
    PORT
      LAYER metal2 ;
      RECT 250.005 577.990 250.075 578.200 ;
    END
  END w0_ce_in
  PIN w0_clk
    DIRECTION INPUT ;
    USE SIGNAL ;
    SHAPE ABUTMENT ;
    PORT
      LAYER metal2 ;
      RECT 250.385 577.990 250.455 578.200 ;
    END
  END w0_clk
  PIN r0_ce_in
    DIRECTION INPUT ;
    USE SIGNAL ;
    SHAPE ABUTMENT ;
    PORT
      LAYER metal2 ;
      RECT 250.765 577.990 250.835 578.200 ;
    END
  END r0_ce_in
  PIN r0_clk
    DIRECTION INPUT ;
    USE SIGNAL ;
    SHAPE ABUTMENT ;
    PORT
      LAYER metal2 ;
      RECT 251.145 577.990 251.215 578.200 ;
    END
  END r0_clk
  PIN VSS
    DIRECTION INOUT ;
    USE GROUND ;
    PORT
      LAYER metal4 ;
      RECT 1.000 0.840 1.280 577.360 ;
      RECT 3.240 0.840 3.520 577.360 ;
      RECT 5.480 0.840 5.760 577.360 ;
      RECT 7.720 0.840 8.000 577.360 ;
      RECT 9.960 0.840 10.240 577.360 ;
      RECT 12.200 0.840 12.480 577.360 ;
      RECT 14.440 0.840 14.720 577.360 ;
      RECT 16.680 0.840 16.960 577.360 ;
      RECT 18.920 0.840 19.200 577.360 ;
      RECT 21.160 0.840 21.440 577.360 ;
      RECT 23.400 0.840 23.680 577.360 ;
      RECT 25.640 0.840 25.920 577.360 ;
      RECT 27.880 0.840 28.160 577.360 ;
      RECT 30.120 0.840 30.400 577.360 ;
      RECT 32.360 0.840 32.640 577.360 ;
      RECT 34.600 0.840 34.880 577.360 ;
      RECT 36.840 0.840 37.120 577.360 ;
      RECT 39.080 0.840 39.360 577.360 ;
      RECT 41.320 0.840 41.600 577.360 ;
      RECT 43.560 0.840 43.840 577.360 ;
      RECT 45.800 0.840 46.080 577.360 ;
      RECT 48.040 0.840 48.320 577.360 ;
      RECT 50.280 0.840 50.560 577.360 ;
      RECT 52.520 0.840 52.800 577.360 ;
      RECT 54.760 0.840 55.040 577.360 ;
      RECT 57.000 0.840 57.280 577.360 ;
      RECT 59.240 0.840 59.520 577.360 ;
      RECT 61.480 0.840 61.760 577.360 ;
      RECT 63.720 0.840 64.000 577.360 ;
      RECT 65.960 0.840 66.240 577.360 ;
      RECT 68.200 0.840 68.480 577.360 ;
      RECT 70.440 0.840 70.720 577.360 ;
      RECT 72.680 0.840 72.960 577.360 ;
      RECT 74.920 0.840 75.200 577.360 ;
      RECT 77.160 0.840 77.440 577.360 ;
      RECT 79.400 0.840 79.680 577.360 ;
      RECT 81.640 0.840 81.920 577.360 ;
      RECT 83.880 0.840 84.160 577.360 ;
      RECT 86.120 0.840 86.400 577.360 ;
      RECT 88.360 0.840 88.640 577.360 ;
      RECT 90.600 0.840 90.880 577.360 ;
      RECT 92.840 0.840 93.120 577.360 ;
      RECT 95.080 0.840 95.360 577.360 ;
      RECT 97.320 0.840 97.600 577.360 ;
      RECT 99.560 0.840 99.840 577.360 ;
      RECT 101.800 0.840 102.080 577.360 ;
      RECT 104.040 0.840 104.320 577.360 ;
      RECT 106.280 0.840 106.560 577.360 ;
      RECT 108.520 0.840 108.800 577.360 ;
      RECT 110.760 0.840 111.040 577.360 ;
      RECT 113.000 0.840 113.280 577.360 ;
      RECT 115.240 0.840 115.520 577.360 ;
      RECT 117.480 0.840 117.760 577.360 ;
      RECT 119.720 0.840 120.000 577.360 ;
      RECT 121.960 0.840 122.240 577.360 ;
      RECT 124.200 0.840 124.480 577.360 ;
      RECT 126.440 0.840 126.720 577.360 ;
      RECT 128.680 0.840 128.960 577.360 ;
      RECT 130.920 0.840 131.200 577.360 ;
      RECT 133.160 0.840 133.440 577.360 ;
      RECT 135.400 0.840 135.680 577.360 ;
      RECT 137.640 0.840 137.920 577.360 ;
      RECT 139.880 0.840 140.160 577.360 ;
      RECT 142.120 0.840 142.400 577.360 ;
      RECT 144.360 0.840 144.640 577.360 ;
      RECT 146.600 0.840 146.880 577.360 ;
      RECT 148.840 0.840 149.120 577.360 ;
      RECT 151.080 0.840 151.360 577.360 ;
      RECT 153.320 0.840 153.600 577.360 ;
      RECT 155.560 0.840 155.840 577.360 ;
      RECT 157.800 0.840 158.080 577.360 ;
      RECT 160.040 0.840 160.320 577.360 ;
      RECT 162.280 0.840 162.560 577.360 ;
      RECT 164.520 0.840 164.800 577.360 ;
      RECT 166.760 0.840 167.040 577.360 ;
      RECT 169.000 0.840 169.280 577.360 ;
      RECT 171.240 0.840 171.520 577.360 ;
      RECT 173.480 0.840 173.760 577.360 ;
      RECT 175.720 0.840 176.000 577.360 ;
      RECT 177.960 0.840 178.240 577.360 ;
      RECT 180.200 0.840 180.480 577.360 ;
      RECT 182.440 0.840 182.720 577.360 ;
      RECT 184.680 0.840 184.960 577.360 ;
      RECT 186.920 0.840 187.200 577.360 ;
      RECT 189.160 0.840 189.440 577.360 ;
      RECT 191.400 0.840 191.680 577.360 ;
      RECT 193.640 0.840 193.920 577.360 ;
      RECT 195.880 0.840 196.160 577.360 ;
      RECT 198.120 0.840 198.400 577.360 ;
      RECT 200.360 0.840 200.640 577.360 ;
      RECT 202.600 0.840 202.880 577.360 ;
      RECT 204.840 0.840 205.120 577.360 ;
      RECT 207.080 0.840 207.360 577.360 ;
      RECT 209.320 0.840 209.600 577.360 ;
      RECT 211.560 0.840 211.840 577.360 ;
      RECT 213.800 0.840 214.080 577.360 ;
      RECT 216.040 0.840 216.320 577.360 ;
      RECT 218.280 0.840 218.560 577.360 ;
      RECT 220.520 0.840 220.800 577.360 ;
      RECT 222.760 0.840 223.040 577.360 ;
      RECT 225.000 0.840 225.280 577.360 ;
      RECT 227.240 0.840 227.520 577.360 ;
      RECT 229.480 0.840 229.760 577.360 ;
      RECT 231.720 0.840 232.000 577.360 ;
      RECT 233.960 0.840 234.240 577.360 ;
      RECT 236.200 0.840 236.480 577.360 ;
      RECT 238.440 0.840 238.720 577.360 ;
      RECT 240.680 0.840 240.960 577.360 ;
      RECT 242.920 0.840 243.200 577.360 ;
      RECT 245.160 0.840 245.440 577.360 ;
      RECT 247.400 0.840 247.680 577.360 ;
      RECT 249.640 0.840 249.920 577.360 ;
      RECT 251.880 0.840 252.160 577.360 ;
      RECT 254.120 0.840 254.400 577.360 ;
      RECT 256.360 0.840 256.640 577.360 ;
      RECT 258.600 0.840 258.880 577.360 ;
      RECT 260.840 0.840 261.120 577.360 ;
      RECT 263.080 0.840 263.360 577.360 ;
      RECT 265.320 0.840 265.600 577.360 ;
      RECT 267.560 0.840 267.840 577.360 ;
      RECT 269.800 0.840 270.080 577.360 ;
      RECT 272.040 0.840 272.320 577.360 ;
      RECT 274.280 0.840 274.560 577.360 ;
      RECT 276.520 0.840 276.800 577.360 ;
      RECT 278.760 0.840 279.040 577.360 ;
      RECT 281.000 0.840 281.280 577.360 ;
      RECT 283.240 0.840 283.520 577.360 ;
      RECT 285.480 0.840 285.760 577.360 ;
      RECT 287.720 0.840 288.000 577.360 ;
      RECT 289.960 0.840 290.240 577.360 ;
      RECT 292.200 0.840 292.480 577.360 ;
      RECT 294.440 0.840 294.720 577.360 ;
      RECT 296.680 0.840 296.960 577.360 ;
      RECT 298.920 0.840 299.200 577.360 ;
      RECT 301.160 0.840 301.440 577.360 ;
      RECT 303.400 0.840 303.680 577.360 ;
      RECT 305.640 0.840 305.920 577.360 ;
      RECT 307.880 0.840 308.160 577.360 ;
      RECT 310.120 0.840 310.400 577.360 ;
      RECT 312.360 0.840 312.640 577.360 ;
      RECT 314.600 0.840 314.880 577.360 ;
    END
  END VSS
  PIN VDD
    DIRECTION INOUT ;
    USE POWER ;
    PORT
      LAYER metal4 ;
      RECT 1.000 0.840 1.280 577.360 ;
      RECT 3.240 0.840 3.520 577.360 ;
      RECT 5.480 0.840 5.760 577.360 ;
      RECT 7.720 0.840 8.000 577.360 ;
      RECT 9.960 0.840 10.240 577.360 ;
      RECT 12.200 0.840 12.480 577.360 ;
      RECT 14.440 0.840 14.720 577.360 ;
      RECT 16.680 0.840 16.960 577.360 ;
      RECT 18.920 0.840 19.200 577.360 ;
      RECT 21.160 0.840 21.440 577.360 ;
      RECT 23.400 0.840 23.680 577.360 ;
      RECT 25.640 0.840 25.920 577.360 ;
      RECT 27.880 0.840 28.160 577.360 ;
      RECT 30.120 0.840 30.400 577.360 ;
      RECT 32.360 0.840 32.640 577.360 ;
      RECT 34.600 0.840 34.880 577.360 ;
      RECT 36.840 0.840 37.120 577.360 ;
      RECT 39.080 0.840 39.360 577.360 ;
      RECT 41.320 0.840 41.600 577.360 ;
      RECT 43.560 0.840 43.840 577.360 ;
      RECT 45.800 0.840 46.080 577.360 ;
      RECT 48.040 0.840 48.320 577.360 ;
      RECT 50.280 0.840 50.560 577.360 ;
      RECT 52.520 0.840 52.800 577.360 ;
      RECT 54.760 0.840 55.040 577.360 ;
      RECT 57.000 0.840 57.280 577.360 ;
      RECT 59.240 0.840 59.520 577.360 ;
      RECT 61.480 0.840 61.760 577.360 ;
      RECT 63.720 0.840 64.000 577.360 ;
      RECT 65.960 0.840 66.240 577.360 ;
      RECT 68.200 0.840 68.480 577.360 ;
      RECT 70.440 0.840 70.720 577.360 ;
      RECT 72.680 0.840 72.960 577.360 ;
      RECT 74.920 0.840 75.200 577.360 ;
      RECT 77.160 0.840 77.440 577.360 ;
      RECT 79.400 0.840 79.680 577.360 ;
      RECT 81.640 0.840 81.920 577.360 ;
      RECT 83.880 0.840 84.160 577.360 ;
      RECT 86.120 0.840 86.400 577.360 ;
      RECT 88.360 0.840 88.640 577.360 ;
      RECT 90.600 0.840 90.880 577.360 ;
      RECT 92.840 0.840 93.120 577.360 ;
      RECT 95.080 0.840 95.360 577.360 ;
      RECT 97.320 0.840 97.600 577.360 ;
      RECT 99.560 0.840 99.840 577.360 ;
      RECT 101.800 0.840 102.080 577.360 ;
      RECT 104.040 0.840 104.320 577.360 ;
      RECT 106.280 0.840 106.560 577.360 ;
      RECT 108.520 0.840 108.800 577.360 ;
      RECT 110.760 0.840 111.040 577.360 ;
      RECT 113.000 0.840 113.280 577.360 ;
      RECT 115.240 0.840 115.520 577.360 ;
      RECT 117.480 0.840 117.760 577.360 ;
      RECT 119.720 0.840 120.000 577.360 ;
      RECT 121.960 0.840 122.240 577.360 ;
      RECT 124.200 0.840 124.480 577.360 ;
      RECT 126.440 0.840 126.720 577.360 ;
      RECT 128.680 0.840 128.960 577.360 ;
      RECT 130.920 0.840 131.200 577.360 ;
      RECT 133.160 0.840 133.440 577.360 ;
      RECT 135.400 0.840 135.680 577.360 ;
      RECT 137.640 0.840 137.920 577.360 ;
      RECT 139.880 0.840 140.160 577.360 ;
      RECT 142.120 0.840 142.400 577.360 ;
      RECT 144.360 0.840 144.640 577.360 ;
      RECT 146.600 0.840 146.880 577.360 ;
      RECT 148.840 0.840 149.120 577.360 ;
      RECT 151.080 0.840 151.360 577.360 ;
      RECT 153.320 0.840 153.600 577.360 ;
      RECT 155.560 0.840 155.840 577.360 ;
      RECT 157.800 0.840 158.080 577.360 ;
      RECT 160.040 0.840 160.320 577.360 ;
      RECT 162.280 0.840 162.560 577.360 ;
      RECT 164.520 0.840 164.800 577.360 ;
      RECT 166.760 0.840 167.040 577.360 ;
      RECT 169.000 0.840 169.280 577.360 ;
      RECT 171.240 0.840 171.520 577.360 ;
      RECT 173.480 0.840 173.760 577.360 ;
      RECT 175.720 0.840 176.000 577.360 ;
      RECT 177.960 0.840 178.240 577.360 ;
      RECT 180.200 0.840 180.480 577.360 ;
      RECT 182.440 0.840 182.720 577.360 ;
      RECT 184.680 0.840 184.960 577.360 ;
      RECT 186.920 0.840 187.200 577.360 ;
      RECT 189.160 0.840 189.440 577.360 ;
      RECT 191.400 0.840 191.680 577.360 ;
      RECT 193.640 0.840 193.920 577.360 ;
      RECT 195.880 0.840 196.160 577.360 ;
      RECT 198.120 0.840 198.400 577.360 ;
      RECT 200.360 0.840 200.640 577.360 ;
      RECT 202.600 0.840 202.880 577.360 ;
      RECT 204.840 0.840 205.120 577.360 ;
      RECT 207.080 0.840 207.360 577.360 ;
      RECT 209.320 0.840 209.600 577.360 ;
      RECT 211.560 0.840 211.840 577.360 ;
      RECT 213.800 0.840 214.080 577.360 ;
      RECT 216.040 0.840 216.320 577.360 ;
      RECT 218.280 0.840 218.560 577.360 ;
      RECT 220.520 0.840 220.800 577.360 ;
      RECT 222.760 0.840 223.040 577.360 ;
      RECT 225.000 0.840 225.280 577.360 ;
      RECT 227.240 0.840 227.520 577.360 ;
      RECT 229.480 0.840 229.760 577.360 ;
      RECT 231.720 0.840 232.000 577.360 ;
      RECT 233.960 0.840 234.240 577.360 ;
      RECT 236.200 0.840 236.480 577.360 ;
      RECT 238.440 0.840 238.720 577.360 ;
      RECT 240.680 0.840 240.960 577.360 ;
      RECT 242.920 0.840 243.200 577.360 ;
      RECT 245.160 0.840 245.440 577.360 ;
      RECT 247.400 0.840 247.680 577.360 ;
      RECT 249.640 0.840 249.920 577.360 ;
      RECT 251.880 0.840 252.160 577.360 ;
      RECT 254.120 0.840 254.400 577.360 ;
      RECT 256.360 0.840 256.640 577.360 ;
      RECT 258.600 0.840 258.880 577.360 ;
      RECT 260.840 0.840 261.120 577.360 ;
      RECT 263.080 0.840 263.360 577.360 ;
      RECT 265.320 0.840 265.600 577.360 ;
      RECT 267.560 0.840 267.840 577.360 ;
      RECT 269.800 0.840 270.080 577.360 ;
      RECT 272.040 0.840 272.320 577.360 ;
      RECT 274.280 0.840 274.560 577.360 ;
      RECT 276.520 0.840 276.800 577.360 ;
      RECT 278.760 0.840 279.040 577.360 ;
      RECT 281.000 0.840 281.280 577.360 ;
      RECT 283.240 0.840 283.520 577.360 ;
      RECT 285.480 0.840 285.760 577.360 ;
      RECT 287.720 0.840 288.000 577.360 ;
      RECT 289.960 0.840 290.240 577.360 ;
      RECT 292.200 0.840 292.480 577.360 ;
      RECT 294.440 0.840 294.720 577.360 ;
      RECT 296.680 0.840 296.960 577.360 ;
      RECT 298.920 0.840 299.200 577.360 ;
      RECT 301.160 0.840 301.440 577.360 ;
      RECT 303.400 0.840 303.680 577.360 ;
      RECT 305.640 0.840 305.920 577.360 ;
      RECT 307.880 0.840 308.160 577.360 ;
      RECT 310.120 0.840 310.400 577.360 ;
      RECT 312.360 0.840 312.640 577.360 ;
      RECT 314.600 0.840 314.880 577.360 ;
    END
  END VDD
  OBS
    LAYER metal1 ;
    RECT 0 0 316.730 578.200 ;
    LAYER metal2 ;
    RECT 0 0 316.730 578.200 ;
    LAYER metal3 ;
    RECT 0 0 316.730 578.200 ;
    LAYER metal4 ;
    RECT 0 0 316.730 578.200 ;
    LAYER OVERLAP ;
    RECT 0 0 316.730 578.200 ;
  END
END fakeram_654x4_1r1w

END LIBRARY
